VERSION 5.8 ;
BUSBITCHARS "[]" ;
DIVIDERCHAR "/" ;
UNITS
    DATABASE MICRONS 1000 ;
END UNITS

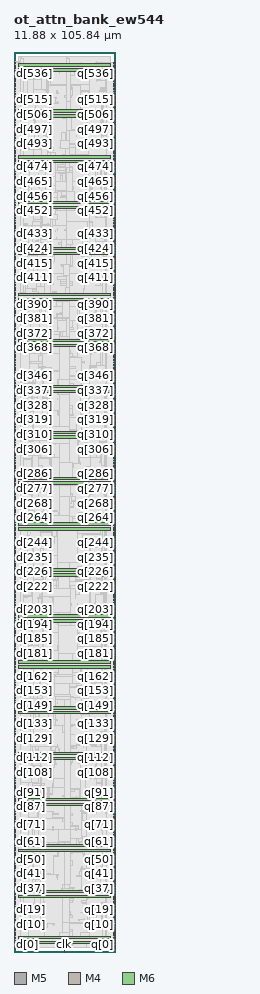
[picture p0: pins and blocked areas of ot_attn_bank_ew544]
MACRO ot_attn_bank_ew544
  FOREIGN ot_attn_bank_ew544 0 0 ;
  CLASS BLOCK ;
  SIZE 11.88 BY 105.84 ;
  PIN clk
    DIRECTION INPUT ;
    USE SIGNAL ;
    PORT
      LAYER M5 ;
        RECT  5.904 0 5.928 0.192 ;
    END
  END clk
  PIN d[0]
    DIRECTION INPUT ;
    USE SIGNAL ;
    PORT
      LAYER M4 ;
        RECT  0 0.384 0.192 0.408 ;
    END
  END d[0]
  PIN d[100]
    DIRECTION INPUT ;
    USE SIGNAL ;
    PORT
      LAYER M4 ;
        RECT  0 19.584 0.192 19.608 ;
    END
  END d[100]
  PIN d[101]
    DIRECTION INPUT ;
    USE SIGNAL ;
    PORT
      LAYER M4 ;
        RECT  0 19.776 0.192 19.8 ;
    END
  END d[101]
  PIN d[102]
    DIRECTION INPUT ;
    USE SIGNAL ;
    PORT
      LAYER M4 ;
        RECT  0 19.968 0.192 19.992 ;
    END
  END d[102]
  PIN d[103]
    DIRECTION INPUT ;
    USE SIGNAL ;
    PORT
      LAYER M4 ;
        RECT  0 20.16 0.192 20.184 ;
    END
  END d[103]
  PIN d[104]
    DIRECTION INPUT ;
    USE SIGNAL ;
    PORT
      LAYER M4 ;
        RECT  0 20.352 0.192 20.376 ;
    END
  END d[104]
  PIN d[105]
    DIRECTION INPUT ;
    USE SIGNAL ;
    PORT
      LAYER M4 ;
        RECT  0 20.544 0.192 20.568 ;
    END
  END d[105]
  PIN d[106]
    DIRECTION INPUT ;
    USE SIGNAL ;
    PORT
      LAYER M4 ;
        RECT  0 20.736 0.192 20.76 ;
    END
  END d[106]
  PIN d[107]
    DIRECTION INPUT ;
    USE SIGNAL ;
    PORT
      LAYER M4 ;
        RECT  0 20.928 0.192 20.952 ;
    END
  END d[107]
  PIN d[108]
    DIRECTION INPUT ;
    USE SIGNAL ;
    PORT
      LAYER M4 ;
        RECT  0 21.12 0.192 21.144 ;
    END
  END d[108]
  PIN d[109]
    DIRECTION INPUT ;
    USE SIGNAL ;
    PORT
      LAYER M4 ;
        RECT  0 21.312 0.192 21.336 ;
    END
  END d[109]
  PIN d[10]
    DIRECTION INPUT ;
    USE SIGNAL ;
    PORT
      LAYER M4 ;
        RECT  0 2.304 0.192 2.328 ;
    END
  END d[10]
  PIN d[110]
    DIRECTION INPUT ;
    USE SIGNAL ;
    PORT
      LAYER M4 ;
        RECT  0 21.504 0.192 21.528 ;
    END
  END d[110]
  PIN d[111]
    DIRECTION INPUT ;
    USE SIGNAL ;
    PORT
      LAYER M4 ;
        RECT  0 21.696 0.192 21.72 ;
    END
  END d[111]
  PIN d[112]
    DIRECTION INPUT ;
    USE SIGNAL ;
    PORT
      LAYER M4 ;
        RECT  0 21.888 0.192 21.912 ;
    END
  END d[112]
  PIN d[113]
    DIRECTION INPUT ;
    USE SIGNAL ;
    PORT
      LAYER M4 ;
        RECT  0 22.08 0.192 22.104 ;
    END
  END d[113]
  PIN d[114]
    DIRECTION INPUT ;
    USE SIGNAL ;
    PORT
      LAYER M4 ;
        RECT  0 22.272 0.192 22.296 ;
    END
  END d[114]
  PIN d[115]
    DIRECTION INPUT ;
    USE SIGNAL ;
    PORT
      LAYER M4 ;
        RECT  0 22.464 0.192 22.488 ;
    END
  END d[115]
  PIN d[116]
    DIRECTION INPUT ;
    USE SIGNAL ;
    PORT
      LAYER M4 ;
        RECT  0 22.656 0.192 22.68 ;
    END
  END d[116]
  PIN d[117]
    DIRECTION INPUT ;
    USE SIGNAL ;
    PORT
      LAYER M4 ;
        RECT  0 22.848 0.192 22.872 ;
    END
  END d[117]
  PIN d[118]
    DIRECTION INPUT ;
    USE SIGNAL ;
    PORT
      LAYER M4 ;
        RECT  0 23.04 0.192 23.064 ;
    END
  END d[118]
  PIN d[119]
    DIRECTION INPUT ;
    USE SIGNAL ;
    PORT
      LAYER M4 ;
        RECT  0 23.232 0.192 23.256 ;
    END
  END d[119]
  PIN d[11]
    DIRECTION INPUT ;
    USE SIGNAL ;
    PORT
      LAYER M4 ;
        RECT  0 2.496 0.192 2.52 ;
    END
  END d[11]
  PIN d[120]
    DIRECTION INPUT ;
    USE SIGNAL ;
    PORT
      LAYER M4 ;
        RECT  0 23.424 0.192 23.448 ;
    END
  END d[120]
  PIN d[121]
    DIRECTION INPUT ;
    USE SIGNAL ;
    PORT
      LAYER M4 ;
        RECT  0 23.616 0.192 23.64 ;
    END
  END d[121]
  PIN d[122]
    DIRECTION INPUT ;
    USE SIGNAL ;
    PORT
      LAYER M4 ;
        RECT  0 23.808 0.192 23.832 ;
    END
  END d[122]
  PIN d[123]
    DIRECTION INPUT ;
    USE SIGNAL ;
    PORT
      LAYER M4 ;
        RECT  0 24 0.192 24.024 ;
    END
  END d[123]
  PIN d[124]
    DIRECTION INPUT ;
    USE SIGNAL ;
    PORT
      LAYER M4 ;
        RECT  0 24.192 0.192 24.216 ;
    END
  END d[124]
  PIN d[125]
    DIRECTION INPUT ;
    USE SIGNAL ;
    PORT
      LAYER M4 ;
        RECT  0 24.384 0.192 24.408 ;
    END
  END d[125]
  PIN d[126]
    DIRECTION INPUT ;
    USE SIGNAL ;
    PORT
      LAYER M4 ;
        RECT  0 24.576 0.192 24.6 ;
    END
  END d[126]
  PIN d[127]
    DIRECTION INPUT ;
    USE SIGNAL ;
    PORT
      LAYER M4 ;
        RECT  0 24.768 0.192 24.792 ;
    END
  END d[127]
  PIN d[128]
    DIRECTION INPUT ;
    USE SIGNAL ;
    PORT
      LAYER M4 ;
        RECT  0 24.96 0.192 24.984 ;
    END
  END d[128]
  PIN d[129]
    DIRECTION INPUT ;
    USE SIGNAL ;
    PORT
      LAYER M4 ;
        RECT  0 25.152 0.192 25.176 ;
    END
  END d[129]
  PIN d[12]
    DIRECTION INPUT ;
    USE SIGNAL ;
    PORT
      LAYER M4 ;
        RECT  0 2.688 0.192 2.712 ;
    END
  END d[12]
  PIN d[130]
    DIRECTION INPUT ;
    USE SIGNAL ;
    PORT
      LAYER M4 ;
        RECT  0 25.344 0.192 25.368 ;
    END
  END d[130]
  PIN d[131]
    DIRECTION INPUT ;
    USE SIGNAL ;
    PORT
      LAYER M4 ;
        RECT  0 25.536 0.192 25.56 ;
    END
  END d[131]
  PIN d[132]
    DIRECTION INPUT ;
    USE SIGNAL ;
    PORT
      LAYER M4 ;
        RECT  0 25.728 0.192 25.752 ;
    END
  END d[132]
  PIN d[133]
    DIRECTION INPUT ;
    USE SIGNAL ;
    PORT
      LAYER M4 ;
        RECT  0 25.92 0.192 25.944 ;
    END
  END d[133]
  PIN d[134]
    DIRECTION INPUT ;
    USE SIGNAL ;
    PORT
      LAYER M4 ;
        RECT  0 26.112 0.192 26.136 ;
    END
  END d[134]
  PIN d[135]
    DIRECTION INPUT ;
    USE SIGNAL ;
    PORT
      LAYER M4 ;
        RECT  0 26.304 0.192 26.328 ;
    END
  END d[135]
  PIN d[136]
    DIRECTION INPUT ;
    USE SIGNAL ;
    PORT
      LAYER M4 ;
        RECT  0 26.496 0.192 26.52 ;
    END
  END d[136]
  PIN d[137]
    DIRECTION INPUT ;
    USE SIGNAL ;
    PORT
      LAYER M4 ;
        RECT  0 26.688 0.192 26.712 ;
    END
  END d[137]
  PIN d[138]
    DIRECTION INPUT ;
    USE SIGNAL ;
    PORT
      LAYER M4 ;
        RECT  0 26.88 0.192 26.904 ;
    END
  END d[138]
  PIN d[139]
    DIRECTION INPUT ;
    USE SIGNAL ;
    PORT
      LAYER M4 ;
        RECT  0 27.072 0.192 27.096 ;
    END
  END d[139]
  PIN d[13]
    DIRECTION INPUT ;
    USE SIGNAL ;
    PORT
      LAYER M4 ;
        RECT  0 2.88 0.192 2.904 ;
    END
  END d[13]
  PIN d[140]
    DIRECTION INPUT ;
    USE SIGNAL ;
    PORT
      LAYER M4 ;
        RECT  0 27.264 0.192 27.288 ;
    END
  END d[140]
  PIN d[141]
    DIRECTION INPUT ;
    USE SIGNAL ;
    PORT
      LAYER M4 ;
        RECT  0 27.456 0.192 27.48 ;
    END
  END d[141]
  PIN d[142]
    DIRECTION INPUT ;
    USE SIGNAL ;
    PORT
      LAYER M4 ;
        RECT  0 27.648 0.192 27.672 ;
    END
  END d[142]
  PIN d[143]
    DIRECTION INPUT ;
    USE SIGNAL ;
    PORT
      LAYER M4 ;
        RECT  0 27.84 0.192 27.864 ;
    END
  END d[143]
  PIN d[144]
    DIRECTION INPUT ;
    USE SIGNAL ;
    PORT
      LAYER M4 ;
        RECT  0 28.032 0.192 28.056 ;
    END
  END d[144]
  PIN d[145]
    DIRECTION INPUT ;
    USE SIGNAL ;
    PORT
      LAYER M4 ;
        RECT  0 28.224 0.192 28.248 ;
    END
  END d[145]
  PIN d[146]
    DIRECTION INPUT ;
    USE SIGNAL ;
    PORT
      LAYER M4 ;
        RECT  0 28.416 0.192 28.44 ;
    END
  END d[146]
  PIN d[147]
    DIRECTION INPUT ;
    USE SIGNAL ;
    PORT
      LAYER M4 ;
        RECT  0 28.608 0.192 28.632 ;
    END
  END d[147]
  PIN d[148]
    DIRECTION INPUT ;
    USE SIGNAL ;
    PORT
      LAYER M4 ;
        RECT  0 28.8 0.192 28.824 ;
    END
  END d[148]
  PIN d[149]
    DIRECTION INPUT ;
    USE SIGNAL ;
    PORT
      LAYER M4 ;
        RECT  0 28.992 0.192 29.016 ;
    END
  END d[149]
  PIN d[14]
    DIRECTION INPUT ;
    USE SIGNAL ;
    PORT
      LAYER M4 ;
        RECT  0 3.072 0.192 3.096 ;
    END
  END d[14]
  PIN d[150]
    DIRECTION INPUT ;
    USE SIGNAL ;
    PORT
      LAYER M4 ;
        RECT  0 29.184 0.192 29.208 ;
    END
  END d[150]
  PIN d[151]
    DIRECTION INPUT ;
    USE SIGNAL ;
    PORT
      LAYER M4 ;
        RECT  0 29.376 0.192 29.4 ;
    END
  END d[151]
  PIN d[152]
    DIRECTION INPUT ;
    USE SIGNAL ;
    PORT
      LAYER M4 ;
        RECT  0 29.568 0.192 29.592 ;
    END
  END d[152]
  PIN d[153]
    DIRECTION INPUT ;
    USE SIGNAL ;
    PORT
      LAYER M4 ;
        RECT  0 29.76 0.192 29.784 ;
    END
  END d[153]
  PIN d[154]
    DIRECTION INPUT ;
    USE SIGNAL ;
    PORT
      LAYER M4 ;
        RECT  0 29.952 0.192 29.976 ;
    END
  END d[154]
  PIN d[155]
    DIRECTION INPUT ;
    USE SIGNAL ;
    PORT
      LAYER M4 ;
        RECT  0 30.144 0.192 30.168 ;
    END
  END d[155]
  PIN d[156]
    DIRECTION INPUT ;
    USE SIGNAL ;
    PORT
      LAYER M4 ;
        RECT  0 30.336 0.192 30.36 ;
    END
  END d[156]
  PIN d[157]
    DIRECTION INPUT ;
    USE SIGNAL ;
    PORT
      LAYER M4 ;
        RECT  0 30.528 0.192 30.552 ;
    END
  END d[157]
  PIN d[158]
    DIRECTION INPUT ;
    USE SIGNAL ;
    PORT
      LAYER M4 ;
        RECT  0 30.72 0.192 30.744 ;
    END
  END d[158]
  PIN d[159]
    DIRECTION INPUT ;
    USE SIGNAL ;
    PORT
      LAYER M4 ;
        RECT  0 30.912 0.192 30.936 ;
    END
  END d[159]
  PIN d[15]
    DIRECTION INPUT ;
    USE SIGNAL ;
    PORT
      LAYER M4 ;
        RECT  0 3.264 0.192 3.288 ;
    END
  END d[15]
  PIN d[160]
    DIRECTION INPUT ;
    USE SIGNAL ;
    PORT
      LAYER M4 ;
        RECT  0 31.104 0.192 31.128 ;
    END
  END d[160]
  PIN d[161]
    DIRECTION INPUT ;
    USE SIGNAL ;
    PORT
      LAYER M4 ;
        RECT  0 31.296 0.192 31.32 ;
    END
  END d[161]
  PIN d[162]
    DIRECTION INPUT ;
    USE SIGNAL ;
    PORT
      LAYER M4 ;
        RECT  0 31.488 0.192 31.512 ;
    END
  END d[162]
  PIN d[163]
    DIRECTION INPUT ;
    USE SIGNAL ;
    PORT
      LAYER M4 ;
        RECT  0 31.68 0.192 31.704 ;
    END
  END d[163]
  PIN d[164]
    DIRECTION INPUT ;
    USE SIGNAL ;
    PORT
      LAYER M4 ;
        RECT  0 31.872 0.192 31.896 ;
    END
  END d[164]
  PIN d[165]
    DIRECTION INPUT ;
    USE SIGNAL ;
    PORT
      LAYER M4 ;
        RECT  0 32.064 0.192 32.088 ;
    END
  END d[165]
  PIN d[166]
    DIRECTION INPUT ;
    USE SIGNAL ;
    PORT
      LAYER M4 ;
        RECT  0 32.256 0.192 32.28 ;
    END
  END d[166]
  PIN d[167]
    DIRECTION INPUT ;
    USE SIGNAL ;
    PORT
      LAYER M4 ;
        RECT  0 32.448 0.192 32.472 ;
    END
  END d[167]
  PIN d[168]
    DIRECTION INPUT ;
    USE SIGNAL ;
    PORT
      LAYER M4 ;
        RECT  0 32.64 0.192 32.664 ;
    END
  END d[168]
  PIN d[169]
    DIRECTION INPUT ;
    USE SIGNAL ;
    PORT
      LAYER M4 ;
        RECT  0 32.832 0.192 32.856 ;
    END
  END d[169]
  PIN d[16]
    DIRECTION INPUT ;
    USE SIGNAL ;
    PORT
      LAYER M4 ;
        RECT  0 3.456 0.192 3.48 ;
    END
  END d[16]
  PIN d[170]
    DIRECTION INPUT ;
    USE SIGNAL ;
    PORT
      LAYER M4 ;
        RECT  0 33.024 0.192 33.048 ;
    END
  END d[170]
  PIN d[171]
    DIRECTION INPUT ;
    USE SIGNAL ;
    PORT
      LAYER M4 ;
        RECT  0 33.216 0.192 33.24 ;
    END
  END d[171]
  PIN d[172]
    DIRECTION INPUT ;
    USE SIGNAL ;
    PORT
      LAYER M4 ;
        RECT  0 33.408 0.192 33.432 ;
    END
  END d[172]
  PIN d[173]
    DIRECTION INPUT ;
    USE SIGNAL ;
    PORT
      LAYER M4 ;
        RECT  0 33.6 0.192 33.624 ;
    END
  END d[173]
  PIN d[174]
    DIRECTION INPUT ;
    USE SIGNAL ;
    PORT
      LAYER M4 ;
        RECT  0 33.792 0.192 33.816 ;
    END
  END d[174]
  PIN d[175]
    DIRECTION INPUT ;
    USE SIGNAL ;
    PORT
      LAYER M4 ;
        RECT  0 33.984 0.192 34.008 ;
    END
  END d[175]
  PIN d[176]
    DIRECTION INPUT ;
    USE SIGNAL ;
    PORT
      LAYER M4 ;
        RECT  0 34.176 0.192 34.2 ;
    END
  END d[176]
  PIN d[177]
    DIRECTION INPUT ;
    USE SIGNAL ;
    PORT
      LAYER M4 ;
        RECT  0 34.368 0.192 34.392 ;
    END
  END d[177]
  PIN d[178]
    DIRECTION INPUT ;
    USE SIGNAL ;
    PORT
      LAYER M4 ;
        RECT  0 34.56 0.192 34.584 ;
    END
  END d[178]
  PIN d[179]
    DIRECTION INPUT ;
    USE SIGNAL ;
    PORT
      LAYER M4 ;
        RECT  0 34.752 0.192 34.776 ;
    END
  END d[179]
  PIN d[17]
    DIRECTION INPUT ;
    USE SIGNAL ;
    PORT
      LAYER M4 ;
        RECT  0 3.648 0.192 3.672 ;
    END
  END d[17]
  PIN d[180]
    DIRECTION INPUT ;
    USE SIGNAL ;
    PORT
      LAYER M4 ;
        RECT  0 34.944 0.192 34.968 ;
    END
  END d[180]
  PIN d[181]
    DIRECTION INPUT ;
    USE SIGNAL ;
    PORT
      LAYER M4 ;
        RECT  0 35.136 0.192 35.16 ;
    END
  END d[181]
  PIN d[182]
    DIRECTION INPUT ;
    USE SIGNAL ;
    PORT
      LAYER M4 ;
        RECT  0 35.328 0.192 35.352 ;
    END
  END d[182]
  PIN d[183]
    DIRECTION INPUT ;
    USE SIGNAL ;
    PORT
      LAYER M4 ;
        RECT  0 35.52 0.192 35.544 ;
    END
  END d[183]
  PIN d[184]
    DIRECTION INPUT ;
    USE SIGNAL ;
    PORT
      LAYER M4 ;
        RECT  0 35.712 0.192 35.736 ;
    END
  END d[184]
  PIN d[185]
    DIRECTION INPUT ;
    USE SIGNAL ;
    PORT
      LAYER M4 ;
        RECT  0 35.904 0.192 35.928 ;
    END
  END d[185]
  PIN d[186]
    DIRECTION INPUT ;
    USE SIGNAL ;
    PORT
      LAYER M4 ;
        RECT  0 36.096 0.192 36.12 ;
    END
  END d[186]
  PIN d[187]
    DIRECTION INPUT ;
    USE SIGNAL ;
    PORT
      LAYER M4 ;
        RECT  0 36.288 0.192 36.312 ;
    END
  END d[187]
  PIN d[188]
    DIRECTION INPUT ;
    USE SIGNAL ;
    PORT
      LAYER M4 ;
        RECT  0 36.48 0.192 36.504 ;
    END
  END d[188]
  PIN d[189]
    DIRECTION INPUT ;
    USE SIGNAL ;
    PORT
      LAYER M4 ;
        RECT  0 36.672 0.192 36.696 ;
    END
  END d[189]
  PIN d[18]
    DIRECTION INPUT ;
    USE SIGNAL ;
    PORT
      LAYER M4 ;
        RECT  0 3.84 0.192 3.864 ;
    END
  END d[18]
  PIN d[190]
    DIRECTION INPUT ;
    USE SIGNAL ;
    PORT
      LAYER M4 ;
        RECT  0 36.864 0.192 36.888 ;
    END
  END d[190]
  PIN d[191]
    DIRECTION INPUT ;
    USE SIGNAL ;
    PORT
      LAYER M4 ;
        RECT  0 37.056 0.192 37.08 ;
    END
  END d[191]
  PIN d[192]
    DIRECTION INPUT ;
    USE SIGNAL ;
    PORT
      LAYER M4 ;
        RECT  0 37.248 0.192 37.272 ;
    END
  END d[192]
  PIN d[193]
    DIRECTION INPUT ;
    USE SIGNAL ;
    PORT
      LAYER M4 ;
        RECT  0 37.44 0.192 37.464 ;
    END
  END d[193]
  PIN d[194]
    DIRECTION INPUT ;
    USE SIGNAL ;
    PORT
      LAYER M4 ;
        RECT  0 37.632 0.192 37.656 ;
    END
  END d[194]
  PIN d[195]
    DIRECTION INPUT ;
    USE SIGNAL ;
    PORT
      LAYER M4 ;
        RECT  0 37.824 0.192 37.848 ;
    END
  END d[195]
  PIN d[196]
    DIRECTION INPUT ;
    USE SIGNAL ;
    PORT
      LAYER M4 ;
        RECT  0 38.016 0.192 38.04 ;
    END
  END d[196]
  PIN d[197]
    DIRECTION INPUT ;
    USE SIGNAL ;
    PORT
      LAYER M4 ;
        RECT  0 38.208 0.192 38.232 ;
    END
  END d[197]
  PIN d[198]
    DIRECTION INPUT ;
    USE SIGNAL ;
    PORT
      LAYER M4 ;
        RECT  0 38.4 0.192 38.424 ;
    END
  END d[198]
  PIN d[199]
    DIRECTION INPUT ;
    USE SIGNAL ;
    PORT
      LAYER M4 ;
        RECT  0 38.592 0.192 38.616 ;
    END
  END d[199]
  PIN d[19]
    DIRECTION INPUT ;
    USE SIGNAL ;
    PORT
      LAYER M4 ;
        RECT  0 4.032 0.192 4.056 ;
    END
  END d[19]
  PIN d[1]
    DIRECTION INPUT ;
    USE SIGNAL ;
    PORT
      LAYER M4 ;
        RECT  0 0.576 0.192 0.6 ;
    END
  END d[1]
  PIN d[200]
    DIRECTION INPUT ;
    USE SIGNAL ;
    PORT
      LAYER M4 ;
        RECT  0 38.784 0.192 38.808 ;
    END
  END d[200]
  PIN d[201]
    DIRECTION INPUT ;
    USE SIGNAL ;
    PORT
      LAYER M4 ;
        RECT  0 38.976 0.192 39 ;
    END
  END d[201]
  PIN d[202]
    DIRECTION INPUT ;
    USE SIGNAL ;
    PORT
      LAYER M4 ;
        RECT  0 39.168 0.192 39.192 ;
    END
  END d[202]
  PIN d[203]
    DIRECTION INPUT ;
    USE SIGNAL ;
    PORT
      LAYER M4 ;
        RECT  0 39.36 0.192 39.384 ;
    END
  END d[203]
  PIN d[204]
    DIRECTION INPUT ;
    USE SIGNAL ;
    PORT
      LAYER M4 ;
        RECT  0 39.552 0.192 39.576 ;
    END
  END d[204]
  PIN d[205]
    DIRECTION INPUT ;
    USE SIGNAL ;
    PORT
      LAYER M4 ;
        RECT  0 39.744 0.192 39.768 ;
    END
  END d[205]
  PIN d[206]
    DIRECTION INPUT ;
    USE SIGNAL ;
    PORT
      LAYER M4 ;
        RECT  0 39.936 0.192 39.96 ;
    END
  END d[206]
  PIN d[207]
    DIRECTION INPUT ;
    USE SIGNAL ;
    PORT
      LAYER M4 ;
        RECT  0 40.128 0.192 40.152 ;
    END
  END d[207]
  PIN d[208]
    DIRECTION INPUT ;
    USE SIGNAL ;
    PORT
      LAYER M4 ;
        RECT  0 40.32 0.192 40.344 ;
    END
  END d[208]
  PIN d[209]
    DIRECTION INPUT ;
    USE SIGNAL ;
    PORT
      LAYER M4 ;
        RECT  0 40.512 0.192 40.536 ;
    END
  END d[209]
  PIN d[20]
    DIRECTION INPUT ;
    USE SIGNAL ;
    PORT
      LAYER M4 ;
        RECT  0 4.224 0.192 4.248 ;
    END
  END d[20]
  PIN d[210]
    DIRECTION INPUT ;
    USE SIGNAL ;
    PORT
      LAYER M4 ;
        RECT  0 40.704 0.192 40.728 ;
    END
  END d[210]
  PIN d[211]
    DIRECTION INPUT ;
    USE SIGNAL ;
    PORT
      LAYER M4 ;
        RECT  0 40.896 0.192 40.92 ;
    END
  END d[211]
  PIN d[212]
    DIRECTION INPUT ;
    USE SIGNAL ;
    PORT
      LAYER M4 ;
        RECT  0 41.088 0.192 41.112 ;
    END
  END d[212]
  PIN d[213]
    DIRECTION INPUT ;
    USE SIGNAL ;
    PORT
      LAYER M4 ;
        RECT  0 41.28 0.192 41.304 ;
    END
  END d[213]
  PIN d[214]
    DIRECTION INPUT ;
    USE SIGNAL ;
    PORT
      LAYER M4 ;
        RECT  0 41.472 0.192 41.496 ;
    END
  END d[214]
  PIN d[215]
    DIRECTION INPUT ;
    USE SIGNAL ;
    PORT
      LAYER M4 ;
        RECT  0 41.664 0.192 41.688 ;
    END
  END d[215]
  PIN d[216]
    DIRECTION INPUT ;
    USE SIGNAL ;
    PORT
      LAYER M4 ;
        RECT  0 41.856 0.192 41.88 ;
    END
  END d[216]
  PIN d[217]
    DIRECTION INPUT ;
    USE SIGNAL ;
    PORT
      LAYER M4 ;
        RECT  0 42.048 0.192 42.072 ;
    END
  END d[217]
  PIN d[218]
    DIRECTION INPUT ;
    USE SIGNAL ;
    PORT
      LAYER M4 ;
        RECT  0 42.24 0.192 42.264 ;
    END
  END d[218]
  PIN d[219]
    DIRECTION INPUT ;
    USE SIGNAL ;
    PORT
      LAYER M4 ;
        RECT  0 42.432 0.192 42.456 ;
    END
  END d[219]
  PIN d[21]
    DIRECTION INPUT ;
    USE SIGNAL ;
    PORT
      LAYER M4 ;
        RECT  0 4.416 0.192 4.44 ;
    END
  END d[21]
  PIN d[220]
    DIRECTION INPUT ;
    USE SIGNAL ;
    PORT
      LAYER M4 ;
        RECT  0 42.624 0.192 42.648 ;
    END
  END d[220]
  PIN d[221]
    DIRECTION INPUT ;
    USE SIGNAL ;
    PORT
      LAYER M4 ;
        RECT  0 42.816 0.192 42.84 ;
    END
  END d[221]
  PIN d[222]
    DIRECTION INPUT ;
    USE SIGNAL ;
    PORT
      LAYER M4 ;
        RECT  0 43.008 0.192 43.032 ;
    END
  END d[222]
  PIN d[223]
    DIRECTION INPUT ;
    USE SIGNAL ;
    PORT
      LAYER M4 ;
        RECT  0 43.2 0.192 43.224 ;
    END
  END d[223]
  PIN d[224]
    DIRECTION INPUT ;
    USE SIGNAL ;
    PORT
      LAYER M4 ;
        RECT  0 43.392 0.192 43.416 ;
    END
  END d[224]
  PIN d[225]
    DIRECTION INPUT ;
    USE SIGNAL ;
    PORT
      LAYER M4 ;
        RECT  0 43.584 0.192 43.608 ;
    END
  END d[225]
  PIN d[226]
    DIRECTION INPUT ;
    USE SIGNAL ;
    PORT
      LAYER M4 ;
        RECT  0 43.776 0.192 43.8 ;
    END
  END d[226]
  PIN d[227]
    DIRECTION INPUT ;
    USE SIGNAL ;
    PORT
      LAYER M4 ;
        RECT  0 43.968 0.192 43.992 ;
    END
  END d[227]
  PIN d[228]
    DIRECTION INPUT ;
    USE SIGNAL ;
    PORT
      LAYER M4 ;
        RECT  0 44.16 0.192 44.184 ;
    END
  END d[228]
  PIN d[229]
    DIRECTION INPUT ;
    USE SIGNAL ;
    PORT
      LAYER M4 ;
        RECT  0 44.352 0.192 44.376 ;
    END
  END d[229]
  PIN d[22]
    DIRECTION INPUT ;
    USE SIGNAL ;
    PORT
      LAYER M4 ;
        RECT  0 4.608 0.192 4.632 ;
    END
  END d[22]
  PIN d[230]
    DIRECTION INPUT ;
    USE SIGNAL ;
    PORT
      LAYER M4 ;
        RECT  0 44.544 0.192 44.568 ;
    END
  END d[230]
  PIN d[231]
    DIRECTION INPUT ;
    USE SIGNAL ;
    PORT
      LAYER M4 ;
        RECT  0 44.736 0.192 44.76 ;
    END
  END d[231]
  PIN d[232]
    DIRECTION INPUT ;
    USE SIGNAL ;
    PORT
      LAYER M4 ;
        RECT  0 44.928 0.192 44.952 ;
    END
  END d[232]
  PIN d[233]
    DIRECTION INPUT ;
    USE SIGNAL ;
    PORT
      LAYER M4 ;
        RECT  0 45.12 0.192 45.144 ;
    END
  END d[233]
  PIN d[234]
    DIRECTION INPUT ;
    USE SIGNAL ;
    PORT
      LAYER M4 ;
        RECT  0 45.312 0.192 45.336 ;
    END
  END d[234]
  PIN d[235]
    DIRECTION INPUT ;
    USE SIGNAL ;
    PORT
      LAYER M4 ;
        RECT  0 45.504 0.192 45.528 ;
    END
  END d[235]
  PIN d[236]
    DIRECTION INPUT ;
    USE SIGNAL ;
    PORT
      LAYER M4 ;
        RECT  0 45.696 0.192 45.72 ;
    END
  END d[236]
  PIN d[237]
    DIRECTION INPUT ;
    USE SIGNAL ;
    PORT
      LAYER M4 ;
        RECT  0 45.888 0.192 45.912 ;
    END
  END d[237]
  PIN d[238]
    DIRECTION INPUT ;
    USE SIGNAL ;
    PORT
      LAYER M4 ;
        RECT  0 46.08 0.192 46.104 ;
    END
  END d[238]
  PIN d[239]
    DIRECTION INPUT ;
    USE SIGNAL ;
    PORT
      LAYER M4 ;
        RECT  0 46.272 0.192 46.296 ;
    END
  END d[239]
  PIN d[23]
    DIRECTION INPUT ;
    USE SIGNAL ;
    PORT
      LAYER M4 ;
        RECT  0 4.8 0.192 4.824 ;
    END
  END d[23]
  PIN d[240]
    DIRECTION INPUT ;
    USE SIGNAL ;
    PORT
      LAYER M4 ;
        RECT  0 46.464 0.192 46.488 ;
    END
  END d[240]
  PIN d[241]
    DIRECTION INPUT ;
    USE SIGNAL ;
    PORT
      LAYER M4 ;
        RECT  0 46.656 0.192 46.68 ;
    END
  END d[241]
  PIN d[242]
    DIRECTION INPUT ;
    USE SIGNAL ;
    PORT
      LAYER M4 ;
        RECT  0 46.848 0.192 46.872 ;
    END
  END d[242]
  PIN d[243]
    DIRECTION INPUT ;
    USE SIGNAL ;
    PORT
      LAYER M4 ;
        RECT  0 47.04 0.192 47.064 ;
    END
  END d[243]
  PIN d[244]
    DIRECTION INPUT ;
    USE SIGNAL ;
    PORT
      LAYER M4 ;
        RECT  0 47.232 0.192 47.256 ;
    END
  END d[244]
  PIN d[245]
    DIRECTION INPUT ;
    USE SIGNAL ;
    PORT
      LAYER M4 ;
        RECT  0 47.424 0.192 47.448 ;
    END
  END d[245]
  PIN d[246]
    DIRECTION INPUT ;
    USE SIGNAL ;
    PORT
      LAYER M4 ;
        RECT  0 47.616 0.192 47.64 ;
    END
  END d[246]
  PIN d[247]
    DIRECTION INPUT ;
    USE SIGNAL ;
    PORT
      LAYER M4 ;
        RECT  0 47.808 0.192 47.832 ;
    END
  END d[247]
  PIN d[248]
    DIRECTION INPUT ;
    USE SIGNAL ;
    PORT
      LAYER M4 ;
        RECT  0 48 0.192 48.024 ;
    END
  END d[248]
  PIN d[249]
    DIRECTION INPUT ;
    USE SIGNAL ;
    PORT
      LAYER M4 ;
        RECT  0 48.192 0.192 48.216 ;
    END
  END d[249]
  PIN d[24]
    DIRECTION INPUT ;
    USE SIGNAL ;
    PORT
      LAYER M4 ;
        RECT  0 4.992 0.192 5.016 ;
    END
  END d[24]
  PIN d[250]
    DIRECTION INPUT ;
    USE SIGNAL ;
    PORT
      LAYER M4 ;
        RECT  0 48.384 0.192 48.408 ;
    END
  END d[250]
  PIN d[251]
    DIRECTION INPUT ;
    USE SIGNAL ;
    PORT
      LAYER M4 ;
        RECT  0 48.576 0.192 48.6 ;
    END
  END d[251]
  PIN d[252]
    DIRECTION INPUT ;
    USE SIGNAL ;
    PORT
      LAYER M4 ;
        RECT  0 48.768 0.192 48.792 ;
    END
  END d[252]
  PIN d[253]
    DIRECTION INPUT ;
    USE SIGNAL ;
    PORT
      LAYER M4 ;
        RECT  0 48.96 0.192 48.984 ;
    END
  END d[253]
  PIN d[254]
    DIRECTION INPUT ;
    USE SIGNAL ;
    PORT
      LAYER M4 ;
        RECT  0 49.152 0.192 49.176 ;
    END
  END d[254]
  PIN d[255]
    DIRECTION INPUT ;
    USE SIGNAL ;
    PORT
      LAYER M4 ;
        RECT  0 49.344 0.192 49.368 ;
    END
  END d[255]
  PIN d[256]
    DIRECTION INPUT ;
    USE SIGNAL ;
    PORT
      LAYER M4 ;
        RECT  0 49.536 0.192 49.56 ;
    END
  END d[256]
  PIN d[257]
    DIRECTION INPUT ;
    USE SIGNAL ;
    PORT
      LAYER M4 ;
        RECT  0 49.728 0.192 49.752 ;
    END
  END d[257]
  PIN d[258]
    DIRECTION INPUT ;
    USE SIGNAL ;
    PORT
      LAYER M4 ;
        RECT  0 49.92 0.192 49.944 ;
    END
  END d[258]
  PIN d[259]
    DIRECTION INPUT ;
    USE SIGNAL ;
    PORT
      LAYER M4 ;
        RECT  0 50.112 0.192 50.136 ;
    END
  END d[259]
  PIN d[25]
    DIRECTION INPUT ;
    USE SIGNAL ;
    PORT
      LAYER M4 ;
        RECT  0 5.184 0.192 5.208 ;
    END
  END d[25]
  PIN d[260]
    DIRECTION INPUT ;
    USE SIGNAL ;
    PORT
      LAYER M4 ;
        RECT  0 50.304 0.192 50.328 ;
    END
  END d[260]
  PIN d[261]
    DIRECTION INPUT ;
    USE SIGNAL ;
    PORT
      LAYER M4 ;
        RECT  0 50.496 0.192 50.52 ;
    END
  END d[261]
  PIN d[262]
    DIRECTION INPUT ;
    USE SIGNAL ;
    PORT
      LAYER M4 ;
        RECT  0 50.688 0.192 50.712 ;
    END
  END d[262]
  PIN d[263]
    DIRECTION INPUT ;
    USE SIGNAL ;
    PORT
      LAYER M4 ;
        RECT  0 50.88 0.192 50.904 ;
    END
  END d[263]
  PIN d[264]
    DIRECTION INPUT ;
    USE SIGNAL ;
    PORT
      LAYER M4 ;
        RECT  0 51.072 0.192 51.096 ;
    END
  END d[264]
  PIN d[265]
    DIRECTION INPUT ;
    USE SIGNAL ;
    PORT
      LAYER M4 ;
        RECT  0 51.264 0.192 51.288 ;
    END
  END d[265]
  PIN d[266]
    DIRECTION INPUT ;
    USE SIGNAL ;
    PORT
      LAYER M4 ;
        RECT  0 51.456 0.192 51.48 ;
    END
  END d[266]
  PIN d[267]
    DIRECTION INPUT ;
    USE SIGNAL ;
    PORT
      LAYER M4 ;
        RECT  0 51.648 0.192 51.672 ;
    END
  END d[267]
  PIN d[268]
    DIRECTION INPUT ;
    USE SIGNAL ;
    PORT
      LAYER M4 ;
        RECT  0 51.84 0.192 51.864 ;
    END
  END d[268]
  PIN d[269]
    DIRECTION INPUT ;
    USE SIGNAL ;
    PORT
      LAYER M4 ;
        RECT  0 52.032 0.192 52.056 ;
    END
  END d[269]
  PIN d[26]
    DIRECTION INPUT ;
    USE SIGNAL ;
    PORT
      LAYER M4 ;
        RECT  0 5.376 0.192 5.4 ;
    END
  END d[26]
  PIN d[270]
    DIRECTION INPUT ;
    USE SIGNAL ;
    PORT
      LAYER M4 ;
        RECT  0 52.224 0.192 52.248 ;
    END
  END d[270]
  PIN d[271]
    DIRECTION INPUT ;
    USE SIGNAL ;
    PORT
      LAYER M4 ;
        RECT  0 52.416 0.192 52.44 ;
    END
  END d[271]
  PIN d[272]
    DIRECTION INPUT ;
    USE SIGNAL ;
    PORT
      LAYER M4 ;
        RECT  0 52.608 0.192 52.632 ;
    END
  END d[272]
  PIN d[273]
    DIRECTION INPUT ;
    USE SIGNAL ;
    PORT
      LAYER M4 ;
        RECT  0 52.8 0.192 52.824 ;
    END
  END d[273]
  PIN d[274]
    DIRECTION INPUT ;
    USE SIGNAL ;
    PORT
      LAYER M4 ;
        RECT  0 52.992 0.192 53.016 ;
    END
  END d[274]
  PIN d[275]
    DIRECTION INPUT ;
    USE SIGNAL ;
    PORT
      LAYER M4 ;
        RECT  0 53.184 0.192 53.208 ;
    END
  END d[275]
  PIN d[276]
    DIRECTION INPUT ;
    USE SIGNAL ;
    PORT
      LAYER M4 ;
        RECT  0 53.376 0.192 53.4 ;
    END
  END d[276]
  PIN d[277]
    DIRECTION INPUT ;
    USE SIGNAL ;
    PORT
      LAYER M4 ;
        RECT  0 53.568 0.192 53.592 ;
    END
  END d[277]
  PIN d[278]
    DIRECTION INPUT ;
    USE SIGNAL ;
    PORT
      LAYER M4 ;
        RECT  0 53.76 0.192 53.784 ;
    END
  END d[278]
  PIN d[279]
    DIRECTION INPUT ;
    USE SIGNAL ;
    PORT
      LAYER M4 ;
        RECT  0 53.952 0.192 53.976 ;
    END
  END d[279]
  PIN d[27]
    DIRECTION INPUT ;
    USE SIGNAL ;
    PORT
      LAYER M4 ;
        RECT  0 5.568 0.192 5.592 ;
    END
  END d[27]
  PIN d[280]
    DIRECTION INPUT ;
    USE SIGNAL ;
    PORT
      LAYER M4 ;
        RECT  0 54.144 0.192 54.168 ;
    END
  END d[280]
  PIN d[281]
    DIRECTION INPUT ;
    USE SIGNAL ;
    PORT
      LAYER M4 ;
        RECT  0 54.336 0.192 54.36 ;
    END
  END d[281]
  PIN d[282]
    DIRECTION INPUT ;
    USE SIGNAL ;
    PORT
      LAYER M4 ;
        RECT  0 54.528 0.192 54.552 ;
    END
  END d[282]
  PIN d[283]
    DIRECTION INPUT ;
    USE SIGNAL ;
    PORT
      LAYER M4 ;
        RECT  0 54.72 0.192 54.744 ;
    END
  END d[283]
  PIN d[284]
    DIRECTION INPUT ;
    USE SIGNAL ;
    PORT
      LAYER M4 ;
        RECT  0 54.912 0.192 54.936 ;
    END
  END d[284]
  PIN d[285]
    DIRECTION INPUT ;
    USE SIGNAL ;
    PORT
      LAYER M4 ;
        RECT  0 55.104 0.192 55.128 ;
    END
  END d[285]
  PIN d[286]
    DIRECTION INPUT ;
    USE SIGNAL ;
    PORT
      LAYER M4 ;
        RECT  0 55.296 0.192 55.32 ;
    END
  END d[286]
  PIN d[287]
    DIRECTION INPUT ;
    USE SIGNAL ;
    PORT
      LAYER M4 ;
        RECT  0 55.488 0.192 55.512 ;
    END
  END d[287]
  PIN d[288]
    DIRECTION INPUT ;
    USE SIGNAL ;
    PORT
      LAYER M4 ;
        RECT  0 55.68 0.192 55.704 ;
    END
  END d[288]
  PIN d[289]
    DIRECTION INPUT ;
    USE SIGNAL ;
    PORT
      LAYER M4 ;
        RECT  0 55.872 0.192 55.896 ;
    END
  END d[289]
  PIN d[28]
    DIRECTION INPUT ;
    USE SIGNAL ;
    PORT
      LAYER M4 ;
        RECT  0 5.76 0.192 5.784 ;
    END
  END d[28]
  PIN d[290]
    DIRECTION INPUT ;
    USE SIGNAL ;
    PORT
      LAYER M4 ;
        RECT  0 56.064 0.192 56.088 ;
    END
  END d[290]
  PIN d[291]
    DIRECTION INPUT ;
    USE SIGNAL ;
    PORT
      LAYER M4 ;
        RECT  0 56.256 0.192 56.28 ;
    END
  END d[291]
  PIN d[292]
    DIRECTION INPUT ;
    USE SIGNAL ;
    PORT
      LAYER M4 ;
        RECT  0 56.448 0.192 56.472 ;
    END
  END d[292]
  PIN d[293]
    DIRECTION INPUT ;
    USE SIGNAL ;
    PORT
      LAYER M4 ;
        RECT  0 56.64 0.192 56.664 ;
    END
  END d[293]
  PIN d[294]
    DIRECTION INPUT ;
    USE SIGNAL ;
    PORT
      LAYER M4 ;
        RECT  0 56.832 0.192 56.856 ;
    END
  END d[294]
  PIN d[295]
    DIRECTION INPUT ;
    USE SIGNAL ;
    PORT
      LAYER M4 ;
        RECT  0 57.024 0.192 57.048 ;
    END
  END d[295]
  PIN d[296]
    DIRECTION INPUT ;
    USE SIGNAL ;
    PORT
      LAYER M4 ;
        RECT  0 57.216 0.192 57.24 ;
    END
  END d[296]
  PIN d[297]
    DIRECTION INPUT ;
    USE SIGNAL ;
    PORT
      LAYER M4 ;
        RECT  0 57.408 0.192 57.432 ;
    END
  END d[297]
  PIN d[298]
    DIRECTION INPUT ;
    USE SIGNAL ;
    PORT
      LAYER M4 ;
        RECT  0 57.6 0.192 57.624 ;
    END
  END d[298]
  PIN d[299]
    DIRECTION INPUT ;
    USE SIGNAL ;
    PORT
      LAYER M4 ;
        RECT  0 57.792 0.192 57.816 ;
    END
  END d[299]
  PIN d[29]
    DIRECTION INPUT ;
    USE SIGNAL ;
    PORT
      LAYER M4 ;
        RECT  0 5.952 0.192 5.976 ;
    END
  END d[29]
  PIN d[2]
    DIRECTION INPUT ;
    USE SIGNAL ;
    PORT
      LAYER M4 ;
        RECT  0 0.768 0.192 0.792 ;
    END
  END d[2]
  PIN d[300]
    DIRECTION INPUT ;
    USE SIGNAL ;
    PORT
      LAYER M4 ;
        RECT  0 57.984 0.192 58.008 ;
    END
  END d[300]
  PIN d[301]
    DIRECTION INPUT ;
    USE SIGNAL ;
    PORT
      LAYER M4 ;
        RECT  0 58.176 0.192 58.2 ;
    END
  END d[301]
  PIN d[302]
    DIRECTION INPUT ;
    USE SIGNAL ;
    PORT
      LAYER M4 ;
        RECT  0 58.368 0.192 58.392 ;
    END
  END d[302]
  PIN d[303]
    DIRECTION INPUT ;
    USE SIGNAL ;
    PORT
      LAYER M4 ;
        RECT  0 58.56 0.192 58.584 ;
    END
  END d[303]
  PIN d[304]
    DIRECTION INPUT ;
    USE SIGNAL ;
    PORT
      LAYER M4 ;
        RECT  0 58.752 0.192 58.776 ;
    END
  END d[304]
  PIN d[305]
    DIRECTION INPUT ;
    USE SIGNAL ;
    PORT
      LAYER M4 ;
        RECT  0 58.944 0.192 58.968 ;
    END
  END d[305]
  PIN d[306]
    DIRECTION INPUT ;
    USE SIGNAL ;
    PORT
      LAYER M4 ;
        RECT  0 59.136 0.192 59.16 ;
    END
  END d[306]
  PIN d[307]
    DIRECTION INPUT ;
    USE SIGNAL ;
    PORT
      LAYER M4 ;
        RECT  0 59.328 0.192 59.352 ;
    END
  END d[307]
  PIN d[308]
    DIRECTION INPUT ;
    USE SIGNAL ;
    PORT
      LAYER M4 ;
        RECT  0 59.52 0.192 59.544 ;
    END
  END d[308]
  PIN d[309]
    DIRECTION INPUT ;
    USE SIGNAL ;
    PORT
      LAYER M4 ;
        RECT  0 59.712 0.192 59.736 ;
    END
  END d[309]
  PIN d[30]
    DIRECTION INPUT ;
    USE SIGNAL ;
    PORT
      LAYER M4 ;
        RECT  0 6.144 0.192 6.168 ;
    END
  END d[30]
  PIN d[310]
    DIRECTION INPUT ;
    USE SIGNAL ;
    PORT
      LAYER M4 ;
        RECT  0 59.904 0.192 59.928 ;
    END
  END d[310]
  PIN d[311]
    DIRECTION INPUT ;
    USE SIGNAL ;
    PORT
      LAYER M4 ;
        RECT  0 60.096 0.192 60.12 ;
    END
  END d[311]
  PIN d[312]
    DIRECTION INPUT ;
    USE SIGNAL ;
    PORT
      LAYER M4 ;
        RECT  0 60.288 0.192 60.312 ;
    END
  END d[312]
  PIN d[313]
    DIRECTION INPUT ;
    USE SIGNAL ;
    PORT
      LAYER M4 ;
        RECT  0 60.48 0.192 60.504 ;
    END
  END d[313]
  PIN d[314]
    DIRECTION INPUT ;
    USE SIGNAL ;
    PORT
      LAYER M4 ;
        RECT  0 60.672 0.192 60.696 ;
    END
  END d[314]
  PIN d[315]
    DIRECTION INPUT ;
    USE SIGNAL ;
    PORT
      LAYER M4 ;
        RECT  0 60.864 0.192 60.888 ;
    END
  END d[315]
  PIN d[316]
    DIRECTION INPUT ;
    USE SIGNAL ;
    PORT
      LAYER M4 ;
        RECT  0 61.056 0.192 61.08 ;
    END
  END d[316]
  PIN d[317]
    DIRECTION INPUT ;
    USE SIGNAL ;
    PORT
      LAYER M4 ;
        RECT  0 61.248 0.192 61.272 ;
    END
  END d[317]
  PIN d[318]
    DIRECTION INPUT ;
    USE SIGNAL ;
    PORT
      LAYER M4 ;
        RECT  0 61.44 0.192 61.464 ;
    END
  END d[318]
  PIN d[319]
    DIRECTION INPUT ;
    USE SIGNAL ;
    PORT
      LAYER M4 ;
        RECT  0 61.632 0.192 61.656 ;
    END
  END d[319]
  PIN d[31]
    DIRECTION INPUT ;
    USE SIGNAL ;
    PORT
      LAYER M4 ;
        RECT  0 6.336 0.192 6.36 ;
    END
  END d[31]
  PIN d[320]
    DIRECTION INPUT ;
    USE SIGNAL ;
    PORT
      LAYER M4 ;
        RECT  0 61.824 0.192 61.848 ;
    END
  END d[320]
  PIN d[321]
    DIRECTION INPUT ;
    USE SIGNAL ;
    PORT
      LAYER M4 ;
        RECT  0 62.016 0.192 62.04 ;
    END
  END d[321]
  PIN d[322]
    DIRECTION INPUT ;
    USE SIGNAL ;
    PORT
      LAYER M4 ;
        RECT  0 62.208 0.192 62.232 ;
    END
  END d[322]
  PIN d[323]
    DIRECTION INPUT ;
    USE SIGNAL ;
    PORT
      LAYER M4 ;
        RECT  0 62.4 0.192 62.424 ;
    END
  END d[323]
  PIN d[324]
    DIRECTION INPUT ;
    USE SIGNAL ;
    PORT
      LAYER M4 ;
        RECT  0 62.592 0.192 62.616 ;
    END
  END d[324]
  PIN d[325]
    DIRECTION INPUT ;
    USE SIGNAL ;
    PORT
      LAYER M4 ;
        RECT  0 62.784 0.192 62.808 ;
    END
  END d[325]
  PIN d[326]
    DIRECTION INPUT ;
    USE SIGNAL ;
    PORT
      LAYER M4 ;
        RECT  0 62.976 0.192 63 ;
    END
  END d[326]
  PIN d[327]
    DIRECTION INPUT ;
    USE SIGNAL ;
    PORT
      LAYER M4 ;
        RECT  0 63.168 0.192 63.192 ;
    END
  END d[327]
  PIN d[328]
    DIRECTION INPUT ;
    USE SIGNAL ;
    PORT
      LAYER M4 ;
        RECT  0 63.36 0.192 63.384 ;
    END
  END d[328]
  PIN d[329]
    DIRECTION INPUT ;
    USE SIGNAL ;
    PORT
      LAYER M4 ;
        RECT  0 63.552 0.192 63.576 ;
    END
  END d[329]
  PIN d[32]
    DIRECTION INPUT ;
    USE SIGNAL ;
    PORT
      LAYER M4 ;
        RECT  0 6.528 0.192 6.552 ;
    END
  END d[32]
  PIN d[330]
    DIRECTION INPUT ;
    USE SIGNAL ;
    PORT
      LAYER M4 ;
        RECT  0 63.744 0.192 63.768 ;
    END
  END d[330]
  PIN d[331]
    DIRECTION INPUT ;
    USE SIGNAL ;
    PORT
      LAYER M4 ;
        RECT  0 63.936 0.192 63.96 ;
    END
  END d[331]
  PIN d[332]
    DIRECTION INPUT ;
    USE SIGNAL ;
    PORT
      LAYER M4 ;
        RECT  0 64.128 0.192 64.152 ;
    END
  END d[332]
  PIN d[333]
    DIRECTION INPUT ;
    USE SIGNAL ;
    PORT
      LAYER M4 ;
        RECT  0 64.32 0.192 64.344 ;
    END
  END d[333]
  PIN d[334]
    DIRECTION INPUT ;
    USE SIGNAL ;
    PORT
      LAYER M4 ;
        RECT  0 64.512 0.192 64.536 ;
    END
  END d[334]
  PIN d[335]
    DIRECTION INPUT ;
    USE SIGNAL ;
    PORT
      LAYER M4 ;
        RECT  0 64.704 0.192 64.728 ;
    END
  END d[335]
  PIN d[336]
    DIRECTION INPUT ;
    USE SIGNAL ;
    PORT
      LAYER M4 ;
        RECT  0 64.896 0.192 64.92 ;
    END
  END d[336]
  PIN d[337]
    DIRECTION INPUT ;
    USE SIGNAL ;
    PORT
      LAYER M4 ;
        RECT  0 65.088 0.192 65.112 ;
    END
  END d[337]
  PIN d[338]
    DIRECTION INPUT ;
    USE SIGNAL ;
    PORT
      LAYER M4 ;
        RECT  0 65.28 0.192 65.304 ;
    END
  END d[338]
  PIN d[339]
    DIRECTION INPUT ;
    USE SIGNAL ;
    PORT
      LAYER M4 ;
        RECT  0 65.472 0.192 65.496 ;
    END
  END d[339]
  PIN d[33]
    DIRECTION INPUT ;
    USE SIGNAL ;
    PORT
      LAYER M4 ;
        RECT  0 6.72 0.192 6.744 ;
    END
  END d[33]
  PIN d[340]
    DIRECTION INPUT ;
    USE SIGNAL ;
    PORT
      LAYER M4 ;
        RECT  0 65.664 0.192 65.688 ;
    END
  END d[340]
  PIN d[341]
    DIRECTION INPUT ;
    USE SIGNAL ;
    PORT
      LAYER M4 ;
        RECT  0 65.856 0.192 65.88 ;
    END
  END d[341]
  PIN d[342]
    DIRECTION INPUT ;
    USE SIGNAL ;
    PORT
      LAYER M4 ;
        RECT  0 66.048 0.192 66.072 ;
    END
  END d[342]
  PIN d[343]
    DIRECTION INPUT ;
    USE SIGNAL ;
    PORT
      LAYER M4 ;
        RECT  0 66.24 0.192 66.264 ;
    END
  END d[343]
  PIN d[344]
    DIRECTION INPUT ;
    USE SIGNAL ;
    PORT
      LAYER M4 ;
        RECT  0 66.432 0.192 66.456 ;
    END
  END d[344]
  PIN d[345]
    DIRECTION INPUT ;
    USE SIGNAL ;
    PORT
      LAYER M4 ;
        RECT  0 66.624 0.192 66.648 ;
    END
  END d[345]
  PIN d[346]
    DIRECTION INPUT ;
    USE SIGNAL ;
    PORT
      LAYER M4 ;
        RECT  0 66.816 0.192 66.84 ;
    END
  END d[346]
  PIN d[347]
    DIRECTION INPUT ;
    USE SIGNAL ;
    PORT
      LAYER M4 ;
        RECT  0 67.008 0.192 67.032 ;
    END
  END d[347]
  PIN d[348]
    DIRECTION INPUT ;
    USE SIGNAL ;
    PORT
      LAYER M4 ;
        RECT  0 67.2 0.192 67.224 ;
    END
  END d[348]
  PIN d[349]
    DIRECTION INPUT ;
    USE SIGNAL ;
    PORT
      LAYER M4 ;
        RECT  0 67.392 0.192 67.416 ;
    END
  END d[349]
  PIN d[34]
    DIRECTION INPUT ;
    USE SIGNAL ;
    PORT
      LAYER M4 ;
        RECT  0 6.912 0.192 6.936 ;
    END
  END d[34]
  PIN d[350]
    DIRECTION INPUT ;
    USE SIGNAL ;
    PORT
      LAYER M4 ;
        RECT  0 67.584 0.192 67.608 ;
    END
  END d[350]
  PIN d[351]
    DIRECTION INPUT ;
    USE SIGNAL ;
    PORT
      LAYER M4 ;
        RECT  0 67.776 0.192 67.8 ;
    END
  END d[351]
  PIN d[352]
    DIRECTION INPUT ;
    USE SIGNAL ;
    PORT
      LAYER M4 ;
        RECT  0 67.968 0.192 67.992 ;
    END
  END d[352]
  PIN d[353]
    DIRECTION INPUT ;
    USE SIGNAL ;
    PORT
      LAYER M4 ;
        RECT  0 68.16 0.192 68.184 ;
    END
  END d[353]
  PIN d[354]
    DIRECTION INPUT ;
    USE SIGNAL ;
    PORT
      LAYER M4 ;
        RECT  0 68.352 0.192 68.376 ;
    END
  END d[354]
  PIN d[355]
    DIRECTION INPUT ;
    USE SIGNAL ;
    PORT
      LAYER M4 ;
        RECT  0 68.544 0.192 68.568 ;
    END
  END d[355]
  PIN d[356]
    DIRECTION INPUT ;
    USE SIGNAL ;
    PORT
      LAYER M4 ;
        RECT  0 68.736 0.192 68.76 ;
    END
  END d[356]
  PIN d[357]
    DIRECTION INPUT ;
    USE SIGNAL ;
    PORT
      LAYER M4 ;
        RECT  0 68.928 0.192 68.952 ;
    END
  END d[357]
  PIN d[358]
    DIRECTION INPUT ;
    USE SIGNAL ;
    PORT
      LAYER M4 ;
        RECT  0 69.12 0.192 69.144 ;
    END
  END d[358]
  PIN d[359]
    DIRECTION INPUT ;
    USE SIGNAL ;
    PORT
      LAYER M4 ;
        RECT  0 69.312 0.192 69.336 ;
    END
  END d[359]
  PIN d[35]
    DIRECTION INPUT ;
    USE SIGNAL ;
    PORT
      LAYER M4 ;
        RECT  0 7.104 0.192 7.128 ;
    END
  END d[35]
  PIN d[360]
    DIRECTION INPUT ;
    USE SIGNAL ;
    PORT
      LAYER M4 ;
        RECT  0 69.504 0.192 69.528 ;
    END
  END d[360]
  PIN d[361]
    DIRECTION INPUT ;
    USE SIGNAL ;
    PORT
      LAYER M4 ;
        RECT  0 69.696 0.192 69.72 ;
    END
  END d[361]
  PIN d[362]
    DIRECTION INPUT ;
    USE SIGNAL ;
    PORT
      LAYER M4 ;
        RECT  0 69.888 0.192 69.912 ;
    END
  END d[362]
  PIN d[363]
    DIRECTION INPUT ;
    USE SIGNAL ;
    PORT
      LAYER M4 ;
        RECT  0 70.08 0.192 70.104 ;
    END
  END d[363]
  PIN d[364]
    DIRECTION INPUT ;
    USE SIGNAL ;
    PORT
      LAYER M4 ;
        RECT  0 70.272 0.192 70.296 ;
    END
  END d[364]
  PIN d[365]
    DIRECTION INPUT ;
    USE SIGNAL ;
    PORT
      LAYER M4 ;
        RECT  0 70.464 0.192 70.488 ;
    END
  END d[365]
  PIN d[366]
    DIRECTION INPUT ;
    USE SIGNAL ;
    PORT
      LAYER M4 ;
        RECT  0 70.656 0.192 70.68 ;
    END
  END d[366]
  PIN d[367]
    DIRECTION INPUT ;
    USE SIGNAL ;
    PORT
      LAYER M4 ;
        RECT  0 70.848 0.192 70.872 ;
    END
  END d[367]
  PIN d[368]
    DIRECTION INPUT ;
    USE SIGNAL ;
    PORT
      LAYER M4 ;
        RECT  0 71.04 0.192 71.064 ;
    END
  END d[368]
  PIN d[369]
    DIRECTION INPUT ;
    USE SIGNAL ;
    PORT
      LAYER M4 ;
        RECT  0 71.232 0.192 71.256 ;
    END
  END d[369]
  PIN d[36]
    DIRECTION INPUT ;
    USE SIGNAL ;
    PORT
      LAYER M4 ;
        RECT  0 7.296 0.192 7.32 ;
    END
  END d[36]
  PIN d[370]
    DIRECTION INPUT ;
    USE SIGNAL ;
    PORT
      LAYER M4 ;
        RECT  0 71.424 0.192 71.448 ;
    END
  END d[370]
  PIN d[371]
    DIRECTION INPUT ;
    USE SIGNAL ;
    PORT
      LAYER M4 ;
        RECT  0 71.616 0.192 71.64 ;
    END
  END d[371]
  PIN d[372]
    DIRECTION INPUT ;
    USE SIGNAL ;
    PORT
      LAYER M4 ;
        RECT  0 71.808 0.192 71.832 ;
    END
  END d[372]
  PIN d[373]
    DIRECTION INPUT ;
    USE SIGNAL ;
    PORT
      LAYER M4 ;
        RECT  0 72 0.192 72.024 ;
    END
  END d[373]
  PIN d[374]
    DIRECTION INPUT ;
    USE SIGNAL ;
    PORT
      LAYER M4 ;
        RECT  0 72.192 0.192 72.216 ;
    END
  END d[374]
  PIN d[375]
    DIRECTION INPUT ;
    USE SIGNAL ;
    PORT
      LAYER M4 ;
        RECT  0 72.384 0.192 72.408 ;
    END
  END d[375]
  PIN d[376]
    DIRECTION INPUT ;
    USE SIGNAL ;
    PORT
      LAYER M4 ;
        RECT  0 72.576 0.192 72.6 ;
    END
  END d[376]
  PIN d[377]
    DIRECTION INPUT ;
    USE SIGNAL ;
    PORT
      LAYER M4 ;
        RECT  0 72.768 0.192 72.792 ;
    END
  END d[377]
  PIN d[378]
    DIRECTION INPUT ;
    USE SIGNAL ;
    PORT
      LAYER M4 ;
        RECT  0 72.96 0.192 72.984 ;
    END
  END d[378]
  PIN d[379]
    DIRECTION INPUT ;
    USE SIGNAL ;
    PORT
      LAYER M4 ;
        RECT  0 73.152 0.192 73.176 ;
    END
  END d[379]
  PIN d[37]
    DIRECTION INPUT ;
    USE SIGNAL ;
    PORT
      LAYER M4 ;
        RECT  0 7.488 0.192 7.512 ;
    END
  END d[37]
  PIN d[380]
    DIRECTION INPUT ;
    USE SIGNAL ;
    PORT
      LAYER M4 ;
        RECT  0 73.344 0.192 73.368 ;
    END
  END d[380]
  PIN d[381]
    DIRECTION INPUT ;
    USE SIGNAL ;
    PORT
      LAYER M4 ;
        RECT  0 73.536 0.192 73.56 ;
    END
  END d[381]
  PIN d[382]
    DIRECTION INPUT ;
    USE SIGNAL ;
    PORT
      LAYER M4 ;
        RECT  0 73.728 0.192 73.752 ;
    END
  END d[382]
  PIN d[383]
    DIRECTION INPUT ;
    USE SIGNAL ;
    PORT
      LAYER M4 ;
        RECT  0 73.92 0.192 73.944 ;
    END
  END d[383]
  PIN d[384]
    DIRECTION INPUT ;
    USE SIGNAL ;
    PORT
      LAYER M4 ;
        RECT  0 74.112 0.192 74.136 ;
    END
  END d[384]
  PIN d[385]
    DIRECTION INPUT ;
    USE SIGNAL ;
    PORT
      LAYER M4 ;
        RECT  0 74.304 0.192 74.328 ;
    END
  END d[385]
  PIN d[386]
    DIRECTION INPUT ;
    USE SIGNAL ;
    PORT
      LAYER M4 ;
        RECT  0 74.496 0.192 74.52 ;
    END
  END d[386]
  PIN d[387]
    DIRECTION INPUT ;
    USE SIGNAL ;
    PORT
      LAYER M4 ;
        RECT  0 74.688 0.192 74.712 ;
    END
  END d[387]
  PIN d[388]
    DIRECTION INPUT ;
    USE SIGNAL ;
    PORT
      LAYER M4 ;
        RECT  0 74.88 0.192 74.904 ;
    END
  END d[388]
  PIN d[389]
    DIRECTION INPUT ;
    USE SIGNAL ;
    PORT
      LAYER M4 ;
        RECT  0 75.072 0.192 75.096 ;
    END
  END d[389]
  PIN d[38]
    DIRECTION INPUT ;
    USE SIGNAL ;
    PORT
      LAYER M4 ;
        RECT  0 7.68 0.192 7.704 ;
    END
  END d[38]
  PIN d[390]
    DIRECTION INPUT ;
    USE SIGNAL ;
    PORT
      LAYER M4 ;
        RECT  0 75.264 0.192 75.288 ;
    END
  END d[390]
  PIN d[391]
    DIRECTION INPUT ;
    USE SIGNAL ;
    PORT
      LAYER M4 ;
        RECT  0 75.456 0.192 75.48 ;
    END
  END d[391]
  PIN d[392]
    DIRECTION INPUT ;
    USE SIGNAL ;
    PORT
      LAYER M4 ;
        RECT  0 75.648 0.192 75.672 ;
    END
  END d[392]
  PIN d[393]
    DIRECTION INPUT ;
    USE SIGNAL ;
    PORT
      LAYER M4 ;
        RECT  0 75.84 0.192 75.864 ;
    END
  END d[393]
  PIN d[394]
    DIRECTION INPUT ;
    USE SIGNAL ;
    PORT
      LAYER M4 ;
        RECT  0 76.032 0.192 76.056 ;
    END
  END d[394]
  PIN d[395]
    DIRECTION INPUT ;
    USE SIGNAL ;
    PORT
      LAYER M4 ;
        RECT  0 76.224 0.192 76.248 ;
    END
  END d[395]
  PIN d[396]
    DIRECTION INPUT ;
    USE SIGNAL ;
    PORT
      LAYER M4 ;
        RECT  0 76.416 0.192 76.44 ;
    END
  END d[396]
  PIN d[397]
    DIRECTION INPUT ;
    USE SIGNAL ;
    PORT
      LAYER M4 ;
        RECT  0 76.608 0.192 76.632 ;
    END
  END d[397]
  PIN d[398]
    DIRECTION INPUT ;
    USE SIGNAL ;
    PORT
      LAYER M4 ;
        RECT  0 76.8 0.192 76.824 ;
    END
  END d[398]
  PIN d[399]
    DIRECTION INPUT ;
    USE SIGNAL ;
    PORT
      LAYER M4 ;
        RECT  0 76.992 0.192 77.016 ;
    END
  END d[399]
  PIN d[39]
    DIRECTION INPUT ;
    USE SIGNAL ;
    PORT
      LAYER M4 ;
        RECT  0 7.872 0.192 7.896 ;
    END
  END d[39]
  PIN d[3]
    DIRECTION INPUT ;
    USE SIGNAL ;
    PORT
      LAYER M4 ;
        RECT  0 0.96 0.192 0.984 ;
    END
  END d[3]
  PIN d[400]
    DIRECTION INPUT ;
    USE SIGNAL ;
    PORT
      LAYER M4 ;
        RECT  0 77.184 0.192 77.208 ;
    END
  END d[400]
  PIN d[401]
    DIRECTION INPUT ;
    USE SIGNAL ;
    PORT
      LAYER M4 ;
        RECT  0 77.376 0.192 77.4 ;
    END
  END d[401]
  PIN d[402]
    DIRECTION INPUT ;
    USE SIGNAL ;
    PORT
      LAYER M4 ;
        RECT  0 77.568 0.192 77.592 ;
    END
  END d[402]
  PIN d[403]
    DIRECTION INPUT ;
    USE SIGNAL ;
    PORT
      LAYER M4 ;
        RECT  0 77.76 0.192 77.784 ;
    END
  END d[403]
  PIN d[404]
    DIRECTION INPUT ;
    USE SIGNAL ;
    PORT
      LAYER M4 ;
        RECT  0 77.952 0.192 77.976 ;
    END
  END d[404]
  PIN d[405]
    DIRECTION INPUT ;
    USE SIGNAL ;
    PORT
      LAYER M4 ;
        RECT  0 78.144 0.192 78.168 ;
    END
  END d[405]
  PIN d[406]
    DIRECTION INPUT ;
    USE SIGNAL ;
    PORT
      LAYER M4 ;
        RECT  0 78.336 0.192 78.36 ;
    END
  END d[406]
  PIN d[407]
    DIRECTION INPUT ;
    USE SIGNAL ;
    PORT
      LAYER M4 ;
        RECT  0 78.528 0.192 78.552 ;
    END
  END d[407]
  PIN d[408]
    DIRECTION INPUT ;
    USE SIGNAL ;
    PORT
      LAYER M4 ;
        RECT  0 78.72 0.192 78.744 ;
    END
  END d[408]
  PIN d[409]
    DIRECTION INPUT ;
    USE SIGNAL ;
    PORT
      LAYER M4 ;
        RECT  0 78.912 0.192 78.936 ;
    END
  END d[409]
  PIN d[40]
    DIRECTION INPUT ;
    USE SIGNAL ;
    PORT
      LAYER M4 ;
        RECT  0 8.064 0.192 8.088 ;
    END
  END d[40]
  PIN d[410]
    DIRECTION INPUT ;
    USE SIGNAL ;
    PORT
      LAYER M4 ;
        RECT  0 79.104 0.192 79.128 ;
    END
  END d[410]
  PIN d[411]
    DIRECTION INPUT ;
    USE SIGNAL ;
    PORT
      LAYER M4 ;
        RECT  0 79.296 0.192 79.32 ;
    END
  END d[411]
  PIN d[412]
    DIRECTION INPUT ;
    USE SIGNAL ;
    PORT
      LAYER M4 ;
        RECT  0 79.488 0.192 79.512 ;
    END
  END d[412]
  PIN d[413]
    DIRECTION INPUT ;
    USE SIGNAL ;
    PORT
      LAYER M4 ;
        RECT  0 79.68 0.192 79.704 ;
    END
  END d[413]
  PIN d[414]
    DIRECTION INPUT ;
    USE SIGNAL ;
    PORT
      LAYER M4 ;
        RECT  0 79.872 0.192 79.896 ;
    END
  END d[414]
  PIN d[415]
    DIRECTION INPUT ;
    USE SIGNAL ;
    PORT
      LAYER M4 ;
        RECT  0 80.064 0.192 80.088 ;
    END
  END d[415]
  PIN d[416]
    DIRECTION INPUT ;
    USE SIGNAL ;
    PORT
      LAYER M4 ;
        RECT  0 80.256 0.192 80.28 ;
    END
  END d[416]
  PIN d[417]
    DIRECTION INPUT ;
    USE SIGNAL ;
    PORT
      LAYER M4 ;
        RECT  0 80.448 0.192 80.472 ;
    END
  END d[417]
  PIN d[418]
    DIRECTION INPUT ;
    USE SIGNAL ;
    PORT
      LAYER M4 ;
        RECT  0 80.64 0.192 80.664 ;
    END
  END d[418]
  PIN d[419]
    DIRECTION INPUT ;
    USE SIGNAL ;
    PORT
      LAYER M4 ;
        RECT  0 80.832 0.192 80.856 ;
    END
  END d[419]
  PIN d[41]
    DIRECTION INPUT ;
    USE SIGNAL ;
    PORT
      LAYER M4 ;
        RECT  0 8.256 0.192 8.28 ;
    END
  END d[41]
  PIN d[420]
    DIRECTION INPUT ;
    USE SIGNAL ;
    PORT
      LAYER M4 ;
        RECT  0 81.024 0.192 81.048 ;
    END
  END d[420]
  PIN d[421]
    DIRECTION INPUT ;
    USE SIGNAL ;
    PORT
      LAYER M4 ;
        RECT  0 81.216 0.192 81.24 ;
    END
  END d[421]
  PIN d[422]
    DIRECTION INPUT ;
    USE SIGNAL ;
    PORT
      LAYER M4 ;
        RECT  0 81.408 0.192 81.432 ;
    END
  END d[422]
  PIN d[423]
    DIRECTION INPUT ;
    USE SIGNAL ;
    PORT
      LAYER M4 ;
        RECT  0 81.6 0.192 81.624 ;
    END
  END d[423]
  PIN d[424]
    DIRECTION INPUT ;
    USE SIGNAL ;
    PORT
      LAYER M4 ;
        RECT  0 81.792 0.192 81.816 ;
    END
  END d[424]
  PIN d[425]
    DIRECTION INPUT ;
    USE SIGNAL ;
    PORT
      LAYER M4 ;
        RECT  0 81.984 0.192 82.008 ;
    END
  END d[425]
  PIN d[426]
    DIRECTION INPUT ;
    USE SIGNAL ;
    PORT
      LAYER M4 ;
        RECT  0 82.176 0.192 82.2 ;
    END
  END d[426]
  PIN d[427]
    DIRECTION INPUT ;
    USE SIGNAL ;
    PORT
      LAYER M4 ;
        RECT  0 82.368 0.192 82.392 ;
    END
  END d[427]
  PIN d[428]
    DIRECTION INPUT ;
    USE SIGNAL ;
    PORT
      LAYER M4 ;
        RECT  0 82.56 0.192 82.584 ;
    END
  END d[428]
  PIN d[429]
    DIRECTION INPUT ;
    USE SIGNAL ;
    PORT
      LAYER M4 ;
        RECT  0 82.752 0.192 82.776 ;
    END
  END d[429]
  PIN d[42]
    DIRECTION INPUT ;
    USE SIGNAL ;
    PORT
      LAYER M4 ;
        RECT  0 8.448 0.192 8.472 ;
    END
  END d[42]
  PIN d[430]
    DIRECTION INPUT ;
    USE SIGNAL ;
    PORT
      LAYER M4 ;
        RECT  0 82.944 0.192 82.968 ;
    END
  END d[430]
  PIN d[431]
    DIRECTION INPUT ;
    USE SIGNAL ;
    PORT
      LAYER M4 ;
        RECT  0 83.136 0.192 83.16 ;
    END
  END d[431]
  PIN d[432]
    DIRECTION INPUT ;
    USE SIGNAL ;
    PORT
      LAYER M4 ;
        RECT  0 83.328 0.192 83.352 ;
    END
  END d[432]
  PIN d[433]
    DIRECTION INPUT ;
    USE SIGNAL ;
    PORT
      LAYER M4 ;
        RECT  0 83.52 0.192 83.544 ;
    END
  END d[433]
  PIN d[434]
    DIRECTION INPUT ;
    USE SIGNAL ;
    PORT
      LAYER M4 ;
        RECT  0 83.712 0.192 83.736 ;
    END
  END d[434]
  PIN d[435]
    DIRECTION INPUT ;
    USE SIGNAL ;
    PORT
      LAYER M4 ;
        RECT  0 83.904 0.192 83.928 ;
    END
  END d[435]
  PIN d[436]
    DIRECTION INPUT ;
    USE SIGNAL ;
    PORT
      LAYER M4 ;
        RECT  0 84.096 0.192 84.12 ;
    END
  END d[436]
  PIN d[437]
    DIRECTION INPUT ;
    USE SIGNAL ;
    PORT
      LAYER M4 ;
        RECT  0 84.288 0.192 84.312 ;
    END
  END d[437]
  PIN d[438]
    DIRECTION INPUT ;
    USE SIGNAL ;
    PORT
      LAYER M4 ;
        RECT  0 84.48 0.192 84.504 ;
    END
  END d[438]
  PIN d[439]
    DIRECTION INPUT ;
    USE SIGNAL ;
    PORT
      LAYER M4 ;
        RECT  0 84.672 0.192 84.696 ;
    END
  END d[439]
  PIN d[43]
    DIRECTION INPUT ;
    USE SIGNAL ;
    PORT
      LAYER M4 ;
        RECT  0 8.64 0.192 8.664 ;
    END
  END d[43]
  PIN d[440]
    DIRECTION INPUT ;
    USE SIGNAL ;
    PORT
      LAYER M4 ;
        RECT  0 84.864 0.192 84.888 ;
    END
  END d[440]
  PIN d[441]
    DIRECTION INPUT ;
    USE SIGNAL ;
    PORT
      LAYER M4 ;
        RECT  0 85.056 0.192 85.08 ;
    END
  END d[441]
  PIN d[442]
    DIRECTION INPUT ;
    USE SIGNAL ;
    PORT
      LAYER M4 ;
        RECT  0 85.248 0.192 85.272 ;
    END
  END d[442]
  PIN d[443]
    DIRECTION INPUT ;
    USE SIGNAL ;
    PORT
      LAYER M4 ;
        RECT  0 85.44 0.192 85.464 ;
    END
  END d[443]
  PIN d[444]
    DIRECTION INPUT ;
    USE SIGNAL ;
    PORT
      LAYER M4 ;
        RECT  0 85.632 0.192 85.656 ;
    END
  END d[444]
  PIN d[445]
    DIRECTION INPUT ;
    USE SIGNAL ;
    PORT
      LAYER M4 ;
        RECT  0 85.824 0.192 85.848 ;
    END
  END d[445]
  PIN d[446]
    DIRECTION INPUT ;
    USE SIGNAL ;
    PORT
      LAYER M4 ;
        RECT  0 86.016 0.192 86.04 ;
    END
  END d[446]
  PIN d[447]
    DIRECTION INPUT ;
    USE SIGNAL ;
    PORT
      LAYER M4 ;
        RECT  0 86.208 0.192 86.232 ;
    END
  END d[447]
  PIN d[448]
    DIRECTION INPUT ;
    USE SIGNAL ;
    PORT
      LAYER M4 ;
        RECT  0 86.4 0.192 86.424 ;
    END
  END d[448]
  PIN d[449]
    DIRECTION INPUT ;
    USE SIGNAL ;
    PORT
      LAYER M4 ;
        RECT  0 86.592 0.192 86.616 ;
    END
  END d[449]
  PIN d[44]
    DIRECTION INPUT ;
    USE SIGNAL ;
    PORT
      LAYER M4 ;
        RECT  0 8.832 0.192 8.856 ;
    END
  END d[44]
  PIN d[450]
    DIRECTION INPUT ;
    USE SIGNAL ;
    PORT
      LAYER M4 ;
        RECT  0 86.784 0.192 86.808 ;
    END
  END d[450]
  PIN d[451]
    DIRECTION INPUT ;
    USE SIGNAL ;
    PORT
      LAYER M4 ;
        RECT  0 86.976 0.192 87 ;
    END
  END d[451]
  PIN d[452]
    DIRECTION INPUT ;
    USE SIGNAL ;
    PORT
      LAYER M4 ;
        RECT  0 87.168 0.192 87.192 ;
    END
  END d[452]
  PIN d[453]
    DIRECTION INPUT ;
    USE SIGNAL ;
    PORT
      LAYER M4 ;
        RECT  0 87.36 0.192 87.384 ;
    END
  END d[453]
  PIN d[454]
    DIRECTION INPUT ;
    USE SIGNAL ;
    PORT
      LAYER M4 ;
        RECT  0 87.552 0.192 87.576 ;
    END
  END d[454]
  PIN d[455]
    DIRECTION INPUT ;
    USE SIGNAL ;
    PORT
      LAYER M4 ;
        RECT  0 87.744 0.192 87.768 ;
    END
  END d[455]
  PIN d[456]
    DIRECTION INPUT ;
    USE SIGNAL ;
    PORT
      LAYER M4 ;
        RECT  0 87.936 0.192 87.96 ;
    END
  END d[456]
  PIN d[457]
    DIRECTION INPUT ;
    USE SIGNAL ;
    PORT
      LAYER M4 ;
        RECT  0 88.128 0.192 88.152 ;
    END
  END d[457]
  PIN d[458]
    DIRECTION INPUT ;
    USE SIGNAL ;
    PORT
      LAYER M4 ;
        RECT  0 88.32 0.192 88.344 ;
    END
  END d[458]
  PIN d[459]
    DIRECTION INPUT ;
    USE SIGNAL ;
    PORT
      LAYER M4 ;
        RECT  0 88.512 0.192 88.536 ;
    END
  END d[459]
  PIN d[45]
    DIRECTION INPUT ;
    USE SIGNAL ;
    PORT
      LAYER M4 ;
        RECT  0 9.024 0.192 9.048 ;
    END
  END d[45]
  PIN d[460]
    DIRECTION INPUT ;
    USE SIGNAL ;
    PORT
      LAYER M4 ;
        RECT  0 88.704 0.192 88.728 ;
    END
  END d[460]
  PIN d[461]
    DIRECTION INPUT ;
    USE SIGNAL ;
    PORT
      LAYER M4 ;
        RECT  0 88.896 0.192 88.92 ;
    END
  END d[461]
  PIN d[462]
    DIRECTION INPUT ;
    USE SIGNAL ;
    PORT
      LAYER M4 ;
        RECT  0 89.088 0.192 89.112 ;
    END
  END d[462]
  PIN d[463]
    DIRECTION INPUT ;
    USE SIGNAL ;
    PORT
      LAYER M4 ;
        RECT  0 89.28 0.192 89.304 ;
    END
  END d[463]
  PIN d[464]
    DIRECTION INPUT ;
    USE SIGNAL ;
    PORT
      LAYER M4 ;
        RECT  0 89.472 0.192 89.496 ;
    END
  END d[464]
  PIN d[465]
    DIRECTION INPUT ;
    USE SIGNAL ;
    PORT
      LAYER M4 ;
        RECT  0 89.664 0.192 89.688 ;
    END
  END d[465]
  PIN d[466]
    DIRECTION INPUT ;
    USE SIGNAL ;
    PORT
      LAYER M4 ;
        RECT  0 89.856 0.192 89.88 ;
    END
  END d[466]
  PIN d[467]
    DIRECTION INPUT ;
    USE SIGNAL ;
    PORT
      LAYER M4 ;
        RECT  0 90.048 0.192 90.072 ;
    END
  END d[467]
  PIN d[468]
    DIRECTION INPUT ;
    USE SIGNAL ;
    PORT
      LAYER M4 ;
        RECT  0 90.24 0.192 90.264 ;
    END
  END d[468]
  PIN d[469]
    DIRECTION INPUT ;
    USE SIGNAL ;
    PORT
      LAYER M4 ;
        RECT  0 90.432 0.192 90.456 ;
    END
  END d[469]
  PIN d[46]
    DIRECTION INPUT ;
    USE SIGNAL ;
    PORT
      LAYER M4 ;
        RECT  0 9.216 0.192 9.24 ;
    END
  END d[46]
  PIN d[470]
    DIRECTION INPUT ;
    USE SIGNAL ;
    PORT
      LAYER M4 ;
        RECT  0 90.624 0.192 90.648 ;
    END
  END d[470]
  PIN d[471]
    DIRECTION INPUT ;
    USE SIGNAL ;
    PORT
      LAYER M4 ;
        RECT  0 90.816 0.192 90.84 ;
    END
  END d[471]
  PIN d[472]
    DIRECTION INPUT ;
    USE SIGNAL ;
    PORT
      LAYER M4 ;
        RECT  0 91.008 0.192 91.032 ;
    END
  END d[472]
  PIN d[473]
    DIRECTION INPUT ;
    USE SIGNAL ;
    PORT
      LAYER M4 ;
        RECT  0 91.2 0.192 91.224 ;
    END
  END d[473]
  PIN d[474]
    DIRECTION INPUT ;
    USE SIGNAL ;
    PORT
      LAYER M4 ;
        RECT  0 91.392 0.192 91.416 ;
    END
  END d[474]
  PIN d[475]
    DIRECTION INPUT ;
    USE SIGNAL ;
    PORT
      LAYER M4 ;
        RECT  0 91.584 0.192 91.608 ;
    END
  END d[475]
  PIN d[476]
    DIRECTION INPUT ;
    USE SIGNAL ;
    PORT
      LAYER M4 ;
        RECT  0 91.776 0.192 91.8 ;
    END
  END d[476]
  PIN d[477]
    DIRECTION INPUT ;
    USE SIGNAL ;
    PORT
      LAYER M4 ;
        RECT  0 91.968 0.192 91.992 ;
    END
  END d[477]
  PIN d[478]
    DIRECTION INPUT ;
    USE SIGNAL ;
    PORT
      LAYER M4 ;
        RECT  0 92.16 0.192 92.184 ;
    END
  END d[478]
  PIN d[479]
    DIRECTION INPUT ;
    USE SIGNAL ;
    PORT
      LAYER M4 ;
        RECT  0 92.352 0.192 92.376 ;
    END
  END d[479]
  PIN d[47]
    DIRECTION INPUT ;
    USE SIGNAL ;
    PORT
      LAYER M4 ;
        RECT  0 9.408 0.192 9.432 ;
    END
  END d[47]
  PIN d[480]
    DIRECTION INPUT ;
    USE SIGNAL ;
    PORT
      LAYER M4 ;
        RECT  0 92.544 0.192 92.568 ;
    END
  END d[480]
  PIN d[481]
    DIRECTION INPUT ;
    USE SIGNAL ;
    PORT
      LAYER M4 ;
        RECT  0 92.736 0.192 92.76 ;
    END
  END d[481]
  PIN d[482]
    DIRECTION INPUT ;
    USE SIGNAL ;
    PORT
      LAYER M4 ;
        RECT  0 92.928 0.192 92.952 ;
    END
  END d[482]
  PIN d[483]
    DIRECTION INPUT ;
    USE SIGNAL ;
    PORT
      LAYER M4 ;
        RECT  0 93.12 0.192 93.144 ;
    END
  END d[483]
  PIN d[484]
    DIRECTION INPUT ;
    USE SIGNAL ;
    PORT
      LAYER M4 ;
        RECT  0 93.312 0.192 93.336 ;
    END
  END d[484]
  PIN d[485]
    DIRECTION INPUT ;
    USE SIGNAL ;
    PORT
      LAYER M4 ;
        RECT  0 93.504 0.192 93.528 ;
    END
  END d[485]
  PIN d[486]
    DIRECTION INPUT ;
    USE SIGNAL ;
    PORT
      LAYER M4 ;
        RECT  0 93.696 0.192 93.72 ;
    END
  END d[486]
  PIN d[487]
    DIRECTION INPUT ;
    USE SIGNAL ;
    PORT
      LAYER M4 ;
        RECT  0 93.888 0.192 93.912 ;
    END
  END d[487]
  PIN d[488]
    DIRECTION INPUT ;
    USE SIGNAL ;
    PORT
      LAYER M4 ;
        RECT  0 94.08 0.192 94.104 ;
    END
  END d[488]
  PIN d[489]
    DIRECTION INPUT ;
    USE SIGNAL ;
    PORT
      LAYER M4 ;
        RECT  0 94.272 0.192 94.296 ;
    END
  END d[489]
  PIN d[48]
    DIRECTION INPUT ;
    USE SIGNAL ;
    PORT
      LAYER M4 ;
        RECT  0 9.6 0.192 9.624 ;
    END
  END d[48]
  PIN d[490]
    DIRECTION INPUT ;
    USE SIGNAL ;
    PORT
      LAYER M4 ;
        RECT  0 94.464 0.192 94.488 ;
    END
  END d[490]
  PIN d[491]
    DIRECTION INPUT ;
    USE SIGNAL ;
    PORT
      LAYER M4 ;
        RECT  0 94.656 0.192 94.68 ;
    END
  END d[491]
  PIN d[492]
    DIRECTION INPUT ;
    USE SIGNAL ;
    PORT
      LAYER M4 ;
        RECT  0 94.848 0.192 94.872 ;
    END
  END d[492]
  PIN d[493]
    DIRECTION INPUT ;
    USE SIGNAL ;
    PORT
      LAYER M4 ;
        RECT  0 95.04 0.192 95.064 ;
    END
  END d[493]
  PIN d[494]
    DIRECTION INPUT ;
    USE SIGNAL ;
    PORT
      LAYER M4 ;
        RECT  0 95.232 0.192 95.256 ;
    END
  END d[494]
  PIN d[495]
    DIRECTION INPUT ;
    USE SIGNAL ;
    PORT
      LAYER M4 ;
        RECT  0 95.424 0.192 95.448 ;
    END
  END d[495]
  PIN d[496]
    DIRECTION INPUT ;
    USE SIGNAL ;
    PORT
      LAYER M4 ;
        RECT  0 95.616 0.192 95.64 ;
    END
  END d[496]
  PIN d[497]
    DIRECTION INPUT ;
    USE SIGNAL ;
    PORT
      LAYER M4 ;
        RECT  0 95.808 0.192 95.832 ;
    END
  END d[497]
  PIN d[498]
    DIRECTION INPUT ;
    USE SIGNAL ;
    PORT
      LAYER M4 ;
        RECT  0 96 0.192 96.024 ;
    END
  END d[498]
  PIN d[499]
    DIRECTION INPUT ;
    USE SIGNAL ;
    PORT
      LAYER M4 ;
        RECT  0 96.192 0.192 96.216 ;
    END
  END d[499]
  PIN d[49]
    DIRECTION INPUT ;
    USE SIGNAL ;
    PORT
      LAYER M4 ;
        RECT  0 9.792 0.192 9.816 ;
    END
  END d[49]
  PIN d[4]
    DIRECTION INPUT ;
    USE SIGNAL ;
    PORT
      LAYER M4 ;
        RECT  0 1.152 0.192 1.176 ;
    END
  END d[4]
  PIN d[500]
    DIRECTION INPUT ;
    USE SIGNAL ;
    PORT
      LAYER M4 ;
        RECT  0 96.384 0.192 96.408 ;
    END
  END d[500]
  PIN d[501]
    DIRECTION INPUT ;
    USE SIGNAL ;
    PORT
      LAYER M4 ;
        RECT  0 96.576 0.192 96.6 ;
    END
  END d[501]
  PIN d[502]
    DIRECTION INPUT ;
    USE SIGNAL ;
    PORT
      LAYER M4 ;
        RECT  0 96.768 0.192 96.792 ;
    END
  END d[502]
  PIN d[503]
    DIRECTION INPUT ;
    USE SIGNAL ;
    PORT
      LAYER M4 ;
        RECT  0 96.96 0.192 96.984 ;
    END
  END d[503]
  PIN d[504]
    DIRECTION INPUT ;
    USE SIGNAL ;
    PORT
      LAYER M4 ;
        RECT  0 97.152 0.192 97.176 ;
    END
  END d[504]
  PIN d[505]
    DIRECTION INPUT ;
    USE SIGNAL ;
    PORT
      LAYER M4 ;
        RECT  0 97.344 0.192 97.368 ;
    END
  END d[505]
  PIN d[506]
    DIRECTION INPUT ;
    USE SIGNAL ;
    PORT
      LAYER M4 ;
        RECT  0 97.536 0.192 97.56 ;
    END
  END d[506]
  PIN d[507]
    DIRECTION INPUT ;
    USE SIGNAL ;
    PORT
      LAYER M4 ;
        RECT  0 97.728 0.192 97.752 ;
    END
  END d[507]
  PIN d[508]
    DIRECTION INPUT ;
    USE SIGNAL ;
    PORT
      LAYER M4 ;
        RECT  0 97.92 0.192 97.944 ;
    END
  END d[508]
  PIN d[509]
    DIRECTION INPUT ;
    USE SIGNAL ;
    PORT
      LAYER M4 ;
        RECT  0 98.112 0.192 98.136 ;
    END
  END d[509]
  PIN d[50]
    DIRECTION INPUT ;
    USE SIGNAL ;
    PORT
      LAYER M4 ;
        RECT  0 9.984 0.192 10.008 ;
    END
  END d[50]
  PIN d[510]
    DIRECTION INPUT ;
    USE SIGNAL ;
    PORT
      LAYER M4 ;
        RECT  0 98.304 0.192 98.328 ;
    END
  END d[510]
  PIN d[511]
    DIRECTION INPUT ;
    USE SIGNAL ;
    PORT
      LAYER M4 ;
        RECT  0 98.496 0.192 98.52 ;
    END
  END d[511]
  PIN d[512]
    DIRECTION INPUT ;
    USE SIGNAL ;
    PORT
      LAYER M4 ;
        RECT  0 98.688 0.192 98.712 ;
    END
  END d[512]
  PIN d[513]
    DIRECTION INPUT ;
    USE SIGNAL ;
    PORT
      LAYER M4 ;
        RECT  0 98.88 0.192 98.904 ;
    END
  END d[513]
  PIN d[514]
    DIRECTION INPUT ;
    USE SIGNAL ;
    PORT
      LAYER M4 ;
        RECT  0 99.072 0.192 99.096 ;
    END
  END d[514]
  PIN d[515]
    DIRECTION INPUT ;
    USE SIGNAL ;
    PORT
      LAYER M4 ;
        RECT  0 99.264 0.192 99.288 ;
    END
  END d[515]
  PIN d[516]
    DIRECTION INPUT ;
    USE SIGNAL ;
    PORT
      LAYER M4 ;
        RECT  0 99.456 0.192 99.48 ;
    END
  END d[516]
  PIN d[517]
    DIRECTION INPUT ;
    USE SIGNAL ;
    PORT
      LAYER M4 ;
        RECT  0 99.648 0.192 99.672 ;
    END
  END d[517]
  PIN d[518]
    DIRECTION INPUT ;
    USE SIGNAL ;
    PORT
      LAYER M4 ;
        RECT  0 99.84 0.192 99.864 ;
    END
  END d[518]
  PIN d[519]
    DIRECTION INPUT ;
    USE SIGNAL ;
    PORT
      LAYER M4 ;
        RECT  0 100.032 0.192 100.056 ;
    END
  END d[519]
  PIN d[51]
    DIRECTION INPUT ;
    USE SIGNAL ;
    PORT
      LAYER M4 ;
        RECT  0 10.176 0.192 10.2 ;
    END
  END d[51]
  PIN d[520]
    DIRECTION INPUT ;
    USE SIGNAL ;
    PORT
      LAYER M4 ;
        RECT  0 100.224 0.192 100.248 ;
    END
  END d[520]
  PIN d[521]
    DIRECTION INPUT ;
    USE SIGNAL ;
    PORT
      LAYER M4 ;
        RECT  0 100.416 0.192 100.44 ;
    END
  END d[521]
  PIN d[522]
    DIRECTION INPUT ;
    USE SIGNAL ;
    PORT
      LAYER M4 ;
        RECT  0 100.608 0.192 100.632 ;
    END
  END d[522]
  PIN d[523]
    DIRECTION INPUT ;
    USE SIGNAL ;
    PORT
      LAYER M4 ;
        RECT  0 100.8 0.192 100.824 ;
    END
  END d[523]
  PIN d[524]
    DIRECTION INPUT ;
    USE SIGNAL ;
    PORT
      LAYER M4 ;
        RECT  0 100.992 0.192 101.016 ;
    END
  END d[524]
  PIN d[525]
    DIRECTION INPUT ;
    USE SIGNAL ;
    PORT
      LAYER M4 ;
        RECT  0 101.184 0.192 101.208 ;
    END
  END d[525]
  PIN d[526]
    DIRECTION INPUT ;
    USE SIGNAL ;
    PORT
      LAYER M4 ;
        RECT  0 101.376 0.192 101.4 ;
    END
  END d[526]
  PIN d[527]
    DIRECTION INPUT ;
    USE SIGNAL ;
    PORT
      LAYER M4 ;
        RECT  0 101.568 0.192 101.592 ;
    END
  END d[527]
  PIN d[528]
    DIRECTION INPUT ;
    USE SIGNAL ;
    PORT
      LAYER M4 ;
        RECT  0 101.76 0.192 101.784 ;
    END
  END d[528]
  PIN d[529]
    DIRECTION INPUT ;
    USE SIGNAL ;
    PORT
      LAYER M4 ;
        RECT  0 101.952 0.192 101.976 ;
    END
  END d[529]
  PIN d[52]
    DIRECTION INPUT ;
    USE SIGNAL ;
    PORT
      LAYER M4 ;
        RECT  0 10.368 0.192 10.392 ;
    END
  END d[52]
  PIN d[530]
    DIRECTION INPUT ;
    USE SIGNAL ;
    PORT
      LAYER M4 ;
        RECT  0 102.144 0.192 102.168 ;
    END
  END d[530]
  PIN d[531]
    DIRECTION INPUT ;
    USE SIGNAL ;
    PORT
      LAYER M4 ;
        RECT  0 102.336 0.192 102.36 ;
    END
  END d[531]
  PIN d[532]
    DIRECTION INPUT ;
    USE SIGNAL ;
    PORT
      LAYER M4 ;
        RECT  0 102.528 0.192 102.552 ;
    END
  END d[532]
  PIN d[533]
    DIRECTION INPUT ;
    USE SIGNAL ;
    PORT
      LAYER M4 ;
        RECT  0 102.72 0.192 102.744 ;
    END
  END d[533]
  PIN d[534]
    DIRECTION INPUT ;
    USE SIGNAL ;
    PORT
      LAYER M4 ;
        RECT  0 102.912 0.192 102.936 ;
    END
  END d[534]
  PIN d[535]
    DIRECTION INPUT ;
    USE SIGNAL ;
    PORT
      LAYER M4 ;
        RECT  0 103.104 0.192 103.128 ;
    END
  END d[535]
  PIN d[536]
    DIRECTION INPUT ;
    USE SIGNAL ;
    PORT
      LAYER M4 ;
        RECT  0 103.296 0.192 103.32 ;
    END
  END d[536]
  PIN d[537]
    DIRECTION INPUT ;
    USE SIGNAL ;
    PORT
      LAYER M4 ;
        RECT  0 103.488 0.192 103.512 ;
    END
  END d[537]
  PIN d[538]
    DIRECTION INPUT ;
    USE SIGNAL ;
    PORT
      LAYER M4 ;
        RECT  0 103.68 0.192 103.704 ;
    END
  END d[538]
  PIN d[539]
    DIRECTION INPUT ;
    USE SIGNAL ;
    PORT
      LAYER M4 ;
        RECT  0 103.872 0.192 103.896 ;
    END
  END d[539]
  PIN d[53]
    DIRECTION INPUT ;
    USE SIGNAL ;
    PORT
      LAYER M4 ;
        RECT  0 10.56 0.192 10.584 ;
    END
  END d[53]
  PIN d[540]
    DIRECTION INPUT ;
    USE SIGNAL ;
    PORT
      LAYER M4 ;
        RECT  0 104.064 0.192 104.088 ;
    END
  END d[540]
  PIN d[541]
    DIRECTION INPUT ;
    USE SIGNAL ;
    PORT
      LAYER M4 ;
        RECT  0 104.256 0.192 104.28 ;
    END
  END d[541]
  PIN d[542]
    DIRECTION INPUT ;
    USE SIGNAL ;
    PORT
      LAYER M4 ;
        RECT  0 104.448 0.192 104.472 ;
    END
  END d[542]
  PIN d[543]
    DIRECTION INPUT ;
    USE SIGNAL ;
    PORT
      LAYER M4 ;
        RECT  0 104.64 0.192 104.664 ;
    END
  END d[543]
  PIN d[54]
    DIRECTION INPUT ;
    USE SIGNAL ;
    PORT
      LAYER M4 ;
        RECT  0 10.752 0.192 10.776 ;
    END
  END d[54]
  PIN d[55]
    DIRECTION INPUT ;
    USE SIGNAL ;
    PORT
      LAYER M4 ;
        RECT  0 10.944 0.192 10.968 ;
    END
  END d[55]
  PIN d[56]
    DIRECTION INPUT ;
    USE SIGNAL ;
    PORT
      LAYER M4 ;
        RECT  0 11.136 0.192 11.16 ;
    END
  END d[56]
  PIN d[57]
    DIRECTION INPUT ;
    USE SIGNAL ;
    PORT
      LAYER M4 ;
        RECT  0 11.328 0.192 11.352 ;
    END
  END d[57]
  PIN d[58]
    DIRECTION INPUT ;
    USE SIGNAL ;
    PORT
      LAYER M4 ;
        RECT  0 11.52 0.192 11.544 ;
    END
  END d[58]
  PIN d[59]
    DIRECTION INPUT ;
    USE SIGNAL ;
    PORT
      LAYER M4 ;
        RECT  0 11.712 0.192 11.736 ;
    END
  END d[59]
  PIN d[5]
    DIRECTION INPUT ;
    USE SIGNAL ;
    PORT
      LAYER M4 ;
        RECT  0 1.344 0.192 1.368 ;
    END
  END d[5]
  PIN d[60]
    DIRECTION INPUT ;
    USE SIGNAL ;
    PORT
      LAYER M4 ;
        RECT  0 11.904 0.192 11.928 ;
    END
  END d[60]
  PIN d[61]
    DIRECTION INPUT ;
    USE SIGNAL ;
    PORT
      LAYER M4 ;
        RECT  0 12.096 0.192 12.12 ;
    END
  END d[61]
  PIN d[62]
    DIRECTION INPUT ;
    USE SIGNAL ;
    PORT
      LAYER M4 ;
        RECT  0 12.288 0.192 12.312 ;
    END
  END d[62]
  PIN d[63]
    DIRECTION INPUT ;
    USE SIGNAL ;
    PORT
      LAYER M4 ;
        RECT  0 12.48 0.192 12.504 ;
    END
  END d[63]
  PIN d[64]
    DIRECTION INPUT ;
    USE SIGNAL ;
    PORT
      LAYER M4 ;
        RECT  0 12.672 0.192 12.696 ;
    END
  END d[64]
  PIN d[65]
    DIRECTION INPUT ;
    USE SIGNAL ;
    PORT
      LAYER M4 ;
        RECT  0 12.864 0.192 12.888 ;
    END
  END d[65]
  PIN d[66]
    DIRECTION INPUT ;
    USE SIGNAL ;
    PORT
      LAYER M4 ;
        RECT  0 13.056 0.192 13.08 ;
    END
  END d[66]
  PIN d[67]
    DIRECTION INPUT ;
    USE SIGNAL ;
    PORT
      LAYER M4 ;
        RECT  0 13.248 0.192 13.272 ;
    END
  END d[67]
  PIN d[68]
    DIRECTION INPUT ;
    USE SIGNAL ;
    PORT
      LAYER M4 ;
        RECT  0 13.44 0.192 13.464 ;
    END
  END d[68]
  PIN d[69]
    DIRECTION INPUT ;
    USE SIGNAL ;
    PORT
      LAYER M4 ;
        RECT  0 13.632 0.192 13.656 ;
    END
  END d[69]
  PIN d[6]
    DIRECTION INPUT ;
    USE SIGNAL ;
    PORT
      LAYER M4 ;
        RECT  0 1.536 0.192 1.56 ;
    END
  END d[6]
  PIN d[70]
    DIRECTION INPUT ;
    USE SIGNAL ;
    PORT
      LAYER M4 ;
        RECT  0 13.824 0.192 13.848 ;
    END
  END d[70]
  PIN d[71]
    DIRECTION INPUT ;
    USE SIGNAL ;
    PORT
      LAYER M4 ;
        RECT  0 14.016 0.192 14.04 ;
    END
  END d[71]
  PIN d[72]
    DIRECTION INPUT ;
    USE SIGNAL ;
    PORT
      LAYER M4 ;
        RECT  0 14.208 0.192 14.232 ;
    END
  END d[72]
  PIN d[73]
    DIRECTION INPUT ;
    USE SIGNAL ;
    PORT
      LAYER M4 ;
        RECT  0 14.4 0.192 14.424 ;
    END
  END d[73]
  PIN d[74]
    DIRECTION INPUT ;
    USE SIGNAL ;
    PORT
      LAYER M4 ;
        RECT  0 14.592 0.192 14.616 ;
    END
  END d[74]
  PIN d[75]
    DIRECTION INPUT ;
    USE SIGNAL ;
    PORT
      LAYER M4 ;
        RECT  0 14.784 0.192 14.808 ;
    END
  END d[75]
  PIN d[76]
    DIRECTION INPUT ;
    USE SIGNAL ;
    PORT
      LAYER M4 ;
        RECT  0 14.976 0.192 15 ;
    END
  END d[76]
  PIN d[77]
    DIRECTION INPUT ;
    USE SIGNAL ;
    PORT
      LAYER M4 ;
        RECT  0 15.168 0.192 15.192 ;
    END
  END d[77]
  PIN d[78]
    DIRECTION INPUT ;
    USE SIGNAL ;
    PORT
      LAYER M4 ;
        RECT  0 15.36 0.192 15.384 ;
    END
  END d[78]
  PIN d[79]
    DIRECTION INPUT ;
    USE SIGNAL ;
    PORT
      LAYER M4 ;
        RECT  0 15.552 0.192 15.576 ;
    END
  END d[79]
  PIN d[7]
    DIRECTION INPUT ;
    USE SIGNAL ;
    PORT
      LAYER M4 ;
        RECT  0 1.728 0.192 1.752 ;
    END
  END d[7]
  PIN d[80]
    DIRECTION INPUT ;
    USE SIGNAL ;
    PORT
      LAYER M4 ;
        RECT  0 15.744 0.192 15.768 ;
    END
  END d[80]
  PIN d[81]
    DIRECTION INPUT ;
    USE SIGNAL ;
    PORT
      LAYER M4 ;
        RECT  0 15.936 0.192 15.96 ;
    END
  END d[81]
  PIN d[82]
    DIRECTION INPUT ;
    USE SIGNAL ;
    PORT
      LAYER M4 ;
        RECT  0 16.128 0.192 16.152 ;
    END
  END d[82]
  PIN d[83]
    DIRECTION INPUT ;
    USE SIGNAL ;
    PORT
      LAYER M4 ;
        RECT  0 16.32 0.192 16.344 ;
    END
  END d[83]
  PIN d[84]
    DIRECTION INPUT ;
    USE SIGNAL ;
    PORT
      LAYER M4 ;
        RECT  0 16.512 0.192 16.536 ;
    END
  END d[84]
  PIN d[85]
    DIRECTION INPUT ;
    USE SIGNAL ;
    PORT
      LAYER M4 ;
        RECT  0 16.704 0.192 16.728 ;
    END
  END d[85]
  PIN d[86]
    DIRECTION INPUT ;
    USE SIGNAL ;
    PORT
      LAYER M4 ;
        RECT  0 16.896 0.192 16.92 ;
    END
  END d[86]
  PIN d[87]
    DIRECTION INPUT ;
    USE SIGNAL ;
    PORT
      LAYER M4 ;
        RECT  0 17.088 0.192 17.112 ;
    END
  END d[87]
  PIN d[88]
    DIRECTION INPUT ;
    USE SIGNAL ;
    PORT
      LAYER M4 ;
        RECT  0 17.28 0.192 17.304 ;
    END
  END d[88]
  PIN d[89]
    DIRECTION INPUT ;
    USE SIGNAL ;
    PORT
      LAYER M4 ;
        RECT  0 17.472 0.192 17.496 ;
    END
  END d[89]
  PIN d[8]
    DIRECTION INPUT ;
    USE SIGNAL ;
    PORT
      LAYER M4 ;
        RECT  0 1.92 0.192 1.944 ;
    END
  END d[8]
  PIN d[90]
    DIRECTION INPUT ;
    USE SIGNAL ;
    PORT
      LAYER M4 ;
        RECT  0 17.664 0.192 17.688 ;
    END
  END d[90]
  PIN d[91]
    DIRECTION INPUT ;
    USE SIGNAL ;
    PORT
      LAYER M4 ;
        RECT  0 17.856 0.192 17.88 ;
    END
  END d[91]
  PIN d[92]
    DIRECTION INPUT ;
    USE SIGNAL ;
    PORT
      LAYER M4 ;
        RECT  0 18.048 0.192 18.072 ;
    END
  END d[92]
  PIN d[93]
    DIRECTION INPUT ;
    USE SIGNAL ;
    PORT
      LAYER M4 ;
        RECT  0 18.24 0.192 18.264 ;
    END
  END d[93]
  PIN d[94]
    DIRECTION INPUT ;
    USE SIGNAL ;
    PORT
      LAYER M4 ;
        RECT  0 18.432 0.192 18.456 ;
    END
  END d[94]
  PIN d[95]
    DIRECTION INPUT ;
    USE SIGNAL ;
    PORT
      LAYER M4 ;
        RECT  0 18.624 0.192 18.648 ;
    END
  END d[95]
  PIN d[96]
    DIRECTION INPUT ;
    USE SIGNAL ;
    PORT
      LAYER M4 ;
        RECT  0 18.816 0.192 18.84 ;
    END
  END d[96]
  PIN d[97]
    DIRECTION INPUT ;
    USE SIGNAL ;
    PORT
      LAYER M4 ;
        RECT  0 19.008 0.192 19.032 ;
    END
  END d[97]
  PIN d[98]
    DIRECTION INPUT ;
    USE SIGNAL ;
    PORT
      LAYER M4 ;
        RECT  0 19.2 0.192 19.224 ;
    END
  END d[98]
  PIN d[99]
    DIRECTION INPUT ;
    USE SIGNAL ;
    PORT
      LAYER M4 ;
        RECT  0 19.392 0.192 19.416 ;
    END
  END d[99]
  PIN d[9]
    DIRECTION INPUT ;
    USE SIGNAL ;
    PORT
      LAYER M4 ;
        RECT  0 2.112 0.192 2.136 ;
    END
  END d[9]
  PIN q[0]
    DIRECTION OUTPUT ;
    USE SIGNAL ;
    PORT
      LAYER M4 ;
        RECT  11.688 0.384 11.88 0.408 ;
    END
  END q[0]
  PIN q[100]
    DIRECTION OUTPUT ;
    USE SIGNAL ;
    PORT
      LAYER M4 ;
        RECT  11.688 19.584 11.88 19.608 ;
    END
  END q[100]
  PIN q[101]
    DIRECTION OUTPUT ;
    USE SIGNAL ;
    PORT
      LAYER M4 ;
        RECT  11.688 19.776 11.88 19.8 ;
    END
  END q[101]
  PIN q[102]
    DIRECTION OUTPUT ;
    USE SIGNAL ;
    PORT
      LAYER M4 ;
        RECT  11.688 19.968 11.88 19.992 ;
    END
  END q[102]
  PIN q[103]
    DIRECTION OUTPUT ;
    USE SIGNAL ;
    PORT
      LAYER M4 ;
        RECT  11.688 20.16 11.88 20.184 ;
    END
  END q[103]
  PIN q[104]
    DIRECTION OUTPUT ;
    USE SIGNAL ;
    PORT
      LAYER M4 ;
        RECT  11.688 20.352 11.88 20.376 ;
    END
  END q[104]
  PIN q[105]
    DIRECTION OUTPUT ;
    USE SIGNAL ;
    PORT
      LAYER M4 ;
        RECT  11.688 20.544 11.88 20.568 ;
    END
  END q[105]
  PIN q[106]
    DIRECTION OUTPUT ;
    USE SIGNAL ;
    PORT
      LAYER M4 ;
        RECT  11.688 20.736 11.88 20.76 ;
    END
  END q[106]
  PIN q[107]
    DIRECTION OUTPUT ;
    USE SIGNAL ;
    PORT
      LAYER M4 ;
        RECT  11.688 20.928 11.88 20.952 ;
    END
  END q[107]
  PIN q[108]
    DIRECTION OUTPUT ;
    USE SIGNAL ;
    PORT
      LAYER M4 ;
        RECT  11.688 21.12 11.88 21.144 ;
    END
  END q[108]
  PIN q[109]
    DIRECTION OUTPUT ;
    USE SIGNAL ;
    PORT
      LAYER M4 ;
        RECT  11.688 21.312 11.88 21.336 ;
    END
  END q[109]
  PIN q[10]
    DIRECTION OUTPUT ;
    USE SIGNAL ;
    PORT
      LAYER M4 ;
        RECT  11.688 2.304 11.88 2.328 ;
    END
  END q[10]
  PIN q[110]
    DIRECTION OUTPUT ;
    USE SIGNAL ;
    PORT
      LAYER M4 ;
        RECT  11.688 21.504 11.88 21.528 ;
    END
  END q[110]
  PIN q[111]
    DIRECTION OUTPUT ;
    USE SIGNAL ;
    PORT
      LAYER M4 ;
        RECT  11.688 21.696 11.88 21.72 ;
    END
  END q[111]
  PIN q[112]
    DIRECTION OUTPUT ;
    USE SIGNAL ;
    PORT
      LAYER M4 ;
        RECT  11.688 21.888 11.88 21.912 ;
    END
  END q[112]
  PIN q[113]
    DIRECTION OUTPUT ;
    USE SIGNAL ;
    PORT
      LAYER M4 ;
        RECT  11.688 22.08 11.88 22.104 ;
    END
  END q[113]
  PIN q[114]
    DIRECTION OUTPUT ;
    USE SIGNAL ;
    PORT
      LAYER M4 ;
        RECT  11.688 22.272 11.88 22.296 ;
    END
  END q[114]
  PIN q[115]
    DIRECTION OUTPUT ;
    USE SIGNAL ;
    PORT
      LAYER M4 ;
        RECT  11.688 22.464 11.88 22.488 ;
    END
  END q[115]
  PIN q[116]
    DIRECTION OUTPUT ;
    USE SIGNAL ;
    PORT
      LAYER M4 ;
        RECT  11.688 22.656 11.88 22.68 ;
    END
  END q[116]
  PIN q[117]
    DIRECTION OUTPUT ;
    USE SIGNAL ;
    PORT
      LAYER M4 ;
        RECT  11.688 22.848 11.88 22.872 ;
    END
  END q[117]
  PIN q[118]
    DIRECTION OUTPUT ;
    USE SIGNAL ;
    PORT
      LAYER M4 ;
        RECT  11.688 23.04 11.88 23.064 ;
    END
  END q[118]
  PIN q[119]
    DIRECTION OUTPUT ;
    USE SIGNAL ;
    PORT
      LAYER M4 ;
        RECT  11.688 23.232 11.88 23.256 ;
    END
  END q[119]
  PIN q[11]
    DIRECTION OUTPUT ;
    USE SIGNAL ;
    PORT
      LAYER M4 ;
        RECT  11.688 2.496 11.88 2.52 ;
    END
  END q[11]
  PIN q[120]
    DIRECTION OUTPUT ;
    USE SIGNAL ;
    PORT
      LAYER M4 ;
        RECT  11.688 23.424 11.88 23.448 ;
    END
  END q[120]
  PIN q[121]
    DIRECTION OUTPUT ;
    USE SIGNAL ;
    PORT
      LAYER M4 ;
        RECT  11.688 23.616 11.88 23.64 ;
    END
  END q[121]
  PIN q[122]
    DIRECTION OUTPUT ;
    USE SIGNAL ;
    PORT
      LAYER M4 ;
        RECT  11.688 23.808 11.88 23.832 ;
    END
  END q[122]
  PIN q[123]
    DIRECTION OUTPUT ;
    USE SIGNAL ;
    PORT
      LAYER M4 ;
        RECT  11.688 24 11.88 24.024 ;
    END
  END q[123]
  PIN q[124]
    DIRECTION OUTPUT ;
    USE SIGNAL ;
    PORT
      LAYER M4 ;
        RECT  11.688 24.192 11.88 24.216 ;
    END
  END q[124]
  PIN q[125]
    DIRECTION OUTPUT ;
    USE SIGNAL ;
    PORT
      LAYER M4 ;
        RECT  11.688 24.384 11.88 24.408 ;
    END
  END q[125]
  PIN q[126]
    DIRECTION OUTPUT ;
    USE SIGNAL ;
    PORT
      LAYER M4 ;
        RECT  11.688 24.576 11.88 24.6 ;
    END
  END q[126]
  PIN q[127]
    DIRECTION OUTPUT ;
    USE SIGNAL ;
    PORT
      LAYER M4 ;
        RECT  11.688 24.768 11.88 24.792 ;
    END
  END q[127]
  PIN q[128]
    DIRECTION OUTPUT ;
    USE SIGNAL ;
    PORT
      LAYER M4 ;
        RECT  11.688 24.96 11.88 24.984 ;
    END
  END q[128]
  PIN q[129]
    DIRECTION OUTPUT ;
    USE SIGNAL ;
    PORT
      LAYER M4 ;
        RECT  11.688 25.152 11.88 25.176 ;
    END
  END q[129]
  PIN q[12]
    DIRECTION OUTPUT ;
    USE SIGNAL ;
    PORT
      LAYER M4 ;
        RECT  11.688 2.688 11.88 2.712 ;
    END
  END q[12]
  PIN q[130]
    DIRECTION OUTPUT ;
    USE SIGNAL ;
    PORT
      LAYER M4 ;
        RECT  11.688 25.344 11.88 25.368 ;
    END
  END q[130]
  PIN q[131]
    DIRECTION OUTPUT ;
    USE SIGNAL ;
    PORT
      LAYER M4 ;
        RECT  11.688 25.536 11.88 25.56 ;
    END
  END q[131]
  PIN q[132]
    DIRECTION OUTPUT ;
    USE SIGNAL ;
    PORT
      LAYER M4 ;
        RECT  11.688 25.728 11.88 25.752 ;
    END
  END q[132]
  PIN q[133]
    DIRECTION OUTPUT ;
    USE SIGNAL ;
    PORT
      LAYER M4 ;
        RECT  11.688 25.92 11.88 25.944 ;
    END
  END q[133]
  PIN q[134]
    DIRECTION OUTPUT ;
    USE SIGNAL ;
    PORT
      LAYER M4 ;
        RECT  11.688 26.112 11.88 26.136 ;
    END
  END q[134]
  PIN q[135]
    DIRECTION OUTPUT ;
    USE SIGNAL ;
    PORT
      LAYER M4 ;
        RECT  11.688 26.304 11.88 26.328 ;
    END
  END q[135]
  PIN q[136]
    DIRECTION OUTPUT ;
    USE SIGNAL ;
    PORT
      LAYER M4 ;
        RECT  11.688 26.496 11.88 26.52 ;
    END
  END q[136]
  PIN q[137]
    DIRECTION OUTPUT ;
    USE SIGNAL ;
    PORT
      LAYER M4 ;
        RECT  11.688 26.688 11.88 26.712 ;
    END
  END q[137]
  PIN q[138]
    DIRECTION OUTPUT ;
    USE SIGNAL ;
    PORT
      LAYER M4 ;
        RECT  11.688 26.88 11.88 26.904 ;
    END
  END q[138]
  PIN q[139]
    DIRECTION OUTPUT ;
    USE SIGNAL ;
    PORT
      LAYER M4 ;
        RECT  11.688 27.072 11.88 27.096 ;
    END
  END q[139]
  PIN q[13]
    DIRECTION OUTPUT ;
    USE SIGNAL ;
    PORT
      LAYER M4 ;
        RECT  11.688 2.88 11.88 2.904 ;
    END
  END q[13]
  PIN q[140]
    DIRECTION OUTPUT ;
    USE SIGNAL ;
    PORT
      LAYER M4 ;
        RECT  11.688 27.264 11.88 27.288 ;
    END
  END q[140]
  PIN q[141]
    DIRECTION OUTPUT ;
    USE SIGNAL ;
    PORT
      LAYER M4 ;
        RECT  11.688 27.456 11.88 27.48 ;
    END
  END q[141]
  PIN q[142]
    DIRECTION OUTPUT ;
    USE SIGNAL ;
    PORT
      LAYER M4 ;
        RECT  11.688 27.648 11.88 27.672 ;
    END
  END q[142]
  PIN q[143]
    DIRECTION OUTPUT ;
    USE SIGNAL ;
    PORT
      LAYER M4 ;
        RECT  11.688 27.84 11.88 27.864 ;
    END
  END q[143]
  PIN q[144]
    DIRECTION OUTPUT ;
    USE SIGNAL ;
    PORT
      LAYER M4 ;
        RECT  11.688 28.032 11.88 28.056 ;
    END
  END q[144]
  PIN q[145]
    DIRECTION OUTPUT ;
    USE SIGNAL ;
    PORT
      LAYER M4 ;
        RECT  11.688 28.224 11.88 28.248 ;
    END
  END q[145]
  PIN q[146]
    DIRECTION OUTPUT ;
    USE SIGNAL ;
    PORT
      LAYER M4 ;
        RECT  11.688 28.416 11.88 28.44 ;
    END
  END q[146]
  PIN q[147]
    DIRECTION OUTPUT ;
    USE SIGNAL ;
    PORT
      LAYER M4 ;
        RECT  11.688 28.608 11.88 28.632 ;
    END
  END q[147]
  PIN q[148]
    DIRECTION OUTPUT ;
    USE SIGNAL ;
    PORT
      LAYER M4 ;
        RECT  11.688 28.8 11.88 28.824 ;
    END
  END q[148]
  PIN q[149]
    DIRECTION OUTPUT ;
    USE SIGNAL ;
    PORT
      LAYER M4 ;
        RECT  11.688 28.992 11.88 29.016 ;
    END
  END q[149]
  PIN q[14]
    DIRECTION OUTPUT ;
    USE SIGNAL ;
    PORT
      LAYER M4 ;
        RECT  11.688 3.072 11.88 3.096 ;
    END
  END q[14]
  PIN q[150]
    DIRECTION OUTPUT ;
    USE SIGNAL ;
    PORT
      LAYER M4 ;
        RECT  11.688 29.184 11.88 29.208 ;
    END
  END q[150]
  PIN q[151]
    DIRECTION OUTPUT ;
    USE SIGNAL ;
    PORT
      LAYER M4 ;
        RECT  11.688 29.376 11.88 29.4 ;
    END
  END q[151]
  PIN q[152]
    DIRECTION OUTPUT ;
    USE SIGNAL ;
    PORT
      LAYER M4 ;
        RECT  11.688 29.568 11.88 29.592 ;
    END
  END q[152]
  PIN q[153]
    DIRECTION OUTPUT ;
    USE SIGNAL ;
    PORT
      LAYER M4 ;
        RECT  11.688 29.76 11.88 29.784 ;
    END
  END q[153]
  PIN q[154]
    DIRECTION OUTPUT ;
    USE SIGNAL ;
    PORT
      LAYER M4 ;
        RECT  11.688 29.952 11.88 29.976 ;
    END
  END q[154]
  PIN q[155]
    DIRECTION OUTPUT ;
    USE SIGNAL ;
    PORT
      LAYER M4 ;
        RECT  11.688 30.144 11.88 30.168 ;
    END
  END q[155]
  PIN q[156]
    DIRECTION OUTPUT ;
    USE SIGNAL ;
    PORT
      LAYER M4 ;
        RECT  11.688 30.336 11.88 30.36 ;
    END
  END q[156]
  PIN q[157]
    DIRECTION OUTPUT ;
    USE SIGNAL ;
    PORT
      LAYER M4 ;
        RECT  11.688 30.528 11.88 30.552 ;
    END
  END q[157]
  PIN q[158]
    DIRECTION OUTPUT ;
    USE SIGNAL ;
    PORT
      LAYER M4 ;
        RECT  11.688 30.72 11.88 30.744 ;
    END
  END q[158]
  PIN q[159]
    DIRECTION OUTPUT ;
    USE SIGNAL ;
    PORT
      LAYER M4 ;
        RECT  11.688 30.912 11.88 30.936 ;
    END
  END q[159]
  PIN q[15]
    DIRECTION OUTPUT ;
    USE SIGNAL ;
    PORT
      LAYER M4 ;
        RECT  11.688 3.264 11.88 3.288 ;
    END
  END q[15]
  PIN q[160]
    DIRECTION OUTPUT ;
    USE SIGNAL ;
    PORT
      LAYER M4 ;
        RECT  11.688 31.104 11.88 31.128 ;
    END
  END q[160]
  PIN q[161]
    DIRECTION OUTPUT ;
    USE SIGNAL ;
    PORT
      LAYER M4 ;
        RECT  11.688 31.296 11.88 31.32 ;
    END
  END q[161]
  PIN q[162]
    DIRECTION OUTPUT ;
    USE SIGNAL ;
    PORT
      LAYER M4 ;
        RECT  11.688 31.488 11.88 31.512 ;
    END
  END q[162]
  PIN q[163]
    DIRECTION OUTPUT ;
    USE SIGNAL ;
    PORT
      LAYER M4 ;
        RECT  11.688 31.68 11.88 31.704 ;
    END
  END q[163]
  PIN q[164]
    DIRECTION OUTPUT ;
    USE SIGNAL ;
    PORT
      LAYER M4 ;
        RECT  11.688 31.872 11.88 31.896 ;
    END
  END q[164]
  PIN q[165]
    DIRECTION OUTPUT ;
    USE SIGNAL ;
    PORT
      LAYER M4 ;
        RECT  11.688 32.064 11.88 32.088 ;
    END
  END q[165]
  PIN q[166]
    DIRECTION OUTPUT ;
    USE SIGNAL ;
    PORT
      LAYER M4 ;
        RECT  11.688 32.256 11.88 32.28 ;
    END
  END q[166]
  PIN q[167]
    DIRECTION OUTPUT ;
    USE SIGNAL ;
    PORT
      LAYER M4 ;
        RECT  11.688 32.448 11.88 32.472 ;
    END
  END q[167]
  PIN q[168]
    DIRECTION OUTPUT ;
    USE SIGNAL ;
    PORT
      LAYER M4 ;
        RECT  11.688 32.64 11.88 32.664 ;
    END
  END q[168]
  PIN q[169]
    DIRECTION OUTPUT ;
    USE SIGNAL ;
    PORT
      LAYER M4 ;
        RECT  11.688 32.832 11.88 32.856 ;
    END
  END q[169]
  PIN q[16]
    DIRECTION OUTPUT ;
    USE SIGNAL ;
    PORT
      LAYER M4 ;
        RECT  11.688 3.456 11.88 3.48 ;
    END
  END q[16]
  PIN q[170]
    DIRECTION OUTPUT ;
    USE SIGNAL ;
    PORT
      LAYER M4 ;
        RECT  11.688 33.024 11.88 33.048 ;
    END
  END q[170]
  PIN q[171]
    DIRECTION OUTPUT ;
    USE SIGNAL ;
    PORT
      LAYER M4 ;
        RECT  11.688 33.216 11.88 33.24 ;
    END
  END q[171]
  PIN q[172]
    DIRECTION OUTPUT ;
    USE SIGNAL ;
    PORT
      LAYER M4 ;
        RECT  11.688 33.408 11.88 33.432 ;
    END
  END q[172]
  PIN q[173]
    DIRECTION OUTPUT ;
    USE SIGNAL ;
    PORT
      LAYER M4 ;
        RECT  11.688 33.6 11.88 33.624 ;
    END
  END q[173]
  PIN q[174]
    DIRECTION OUTPUT ;
    USE SIGNAL ;
    PORT
      LAYER M4 ;
        RECT  11.688 33.792 11.88 33.816 ;
    END
  END q[174]
  PIN q[175]
    DIRECTION OUTPUT ;
    USE SIGNAL ;
    PORT
      LAYER M4 ;
        RECT  11.688 33.984 11.88 34.008 ;
    END
  END q[175]
  PIN q[176]
    DIRECTION OUTPUT ;
    USE SIGNAL ;
    PORT
      LAYER M4 ;
        RECT  11.688 34.176 11.88 34.2 ;
    END
  END q[176]
  PIN q[177]
    DIRECTION OUTPUT ;
    USE SIGNAL ;
    PORT
      LAYER M4 ;
        RECT  11.688 34.368 11.88 34.392 ;
    END
  END q[177]
  PIN q[178]
    DIRECTION OUTPUT ;
    USE SIGNAL ;
    PORT
      LAYER M4 ;
        RECT  11.688 34.56 11.88 34.584 ;
    END
  END q[178]
  PIN q[179]
    DIRECTION OUTPUT ;
    USE SIGNAL ;
    PORT
      LAYER M4 ;
        RECT  11.688 34.752 11.88 34.776 ;
    END
  END q[179]
  PIN q[17]
    DIRECTION OUTPUT ;
    USE SIGNAL ;
    PORT
      LAYER M4 ;
        RECT  11.688 3.648 11.88 3.672 ;
    END
  END q[17]
  PIN q[180]
    DIRECTION OUTPUT ;
    USE SIGNAL ;
    PORT
      LAYER M4 ;
        RECT  11.688 34.944 11.88 34.968 ;
    END
  END q[180]
  PIN q[181]
    DIRECTION OUTPUT ;
    USE SIGNAL ;
    PORT
      LAYER M4 ;
        RECT  11.688 35.136 11.88 35.16 ;
    END
  END q[181]
  PIN q[182]
    DIRECTION OUTPUT ;
    USE SIGNAL ;
    PORT
      LAYER M4 ;
        RECT  11.688 35.328 11.88 35.352 ;
    END
  END q[182]
  PIN q[183]
    DIRECTION OUTPUT ;
    USE SIGNAL ;
    PORT
      LAYER M4 ;
        RECT  11.688 35.52 11.88 35.544 ;
    END
  END q[183]
  PIN q[184]
    DIRECTION OUTPUT ;
    USE SIGNAL ;
    PORT
      LAYER M4 ;
        RECT  11.688 35.712 11.88 35.736 ;
    END
  END q[184]
  PIN q[185]
    DIRECTION OUTPUT ;
    USE SIGNAL ;
    PORT
      LAYER M4 ;
        RECT  11.688 35.904 11.88 35.928 ;
    END
  END q[185]
  PIN q[186]
    DIRECTION OUTPUT ;
    USE SIGNAL ;
    PORT
      LAYER M4 ;
        RECT  11.688 36.096 11.88 36.12 ;
    END
  END q[186]
  PIN q[187]
    DIRECTION OUTPUT ;
    USE SIGNAL ;
    PORT
      LAYER M4 ;
        RECT  11.688 36.288 11.88 36.312 ;
    END
  END q[187]
  PIN q[188]
    DIRECTION OUTPUT ;
    USE SIGNAL ;
    PORT
      LAYER M4 ;
        RECT  11.688 36.48 11.88 36.504 ;
    END
  END q[188]
  PIN q[189]
    DIRECTION OUTPUT ;
    USE SIGNAL ;
    PORT
      LAYER M4 ;
        RECT  11.688 36.672 11.88 36.696 ;
    END
  END q[189]
  PIN q[18]
    DIRECTION OUTPUT ;
    USE SIGNAL ;
    PORT
      LAYER M4 ;
        RECT  11.688 3.84 11.88 3.864 ;
    END
  END q[18]
  PIN q[190]
    DIRECTION OUTPUT ;
    USE SIGNAL ;
    PORT
      LAYER M4 ;
        RECT  11.688 36.864 11.88 36.888 ;
    END
  END q[190]
  PIN q[191]
    DIRECTION OUTPUT ;
    USE SIGNAL ;
    PORT
      LAYER M4 ;
        RECT  11.688 37.056 11.88 37.08 ;
    END
  END q[191]
  PIN q[192]
    DIRECTION OUTPUT ;
    USE SIGNAL ;
    PORT
      LAYER M4 ;
        RECT  11.688 37.248 11.88 37.272 ;
    END
  END q[192]
  PIN q[193]
    DIRECTION OUTPUT ;
    USE SIGNAL ;
    PORT
      LAYER M4 ;
        RECT  11.688 37.44 11.88 37.464 ;
    END
  END q[193]
  PIN q[194]
    DIRECTION OUTPUT ;
    USE SIGNAL ;
    PORT
      LAYER M4 ;
        RECT  11.688 37.632 11.88 37.656 ;
    END
  END q[194]
  PIN q[195]
    DIRECTION OUTPUT ;
    USE SIGNAL ;
    PORT
      LAYER M4 ;
        RECT  11.688 37.824 11.88 37.848 ;
    END
  END q[195]
  PIN q[196]
    DIRECTION OUTPUT ;
    USE SIGNAL ;
    PORT
      LAYER M4 ;
        RECT  11.688 38.016 11.88 38.04 ;
    END
  END q[196]
  PIN q[197]
    DIRECTION OUTPUT ;
    USE SIGNAL ;
    PORT
      LAYER M4 ;
        RECT  11.688 38.208 11.88 38.232 ;
    END
  END q[197]
  PIN q[198]
    DIRECTION OUTPUT ;
    USE SIGNAL ;
    PORT
      LAYER M4 ;
        RECT  11.688 38.4 11.88 38.424 ;
    END
  END q[198]
  PIN q[199]
    DIRECTION OUTPUT ;
    USE SIGNAL ;
    PORT
      LAYER M4 ;
        RECT  11.688 38.592 11.88 38.616 ;
    END
  END q[199]
  PIN q[19]
    DIRECTION OUTPUT ;
    USE SIGNAL ;
    PORT
      LAYER M4 ;
        RECT  11.688 4.032 11.88 4.056 ;
    END
  END q[19]
  PIN q[1]
    DIRECTION OUTPUT ;
    USE SIGNAL ;
    PORT
      LAYER M4 ;
        RECT  11.688 0.576 11.88 0.6 ;
    END
  END q[1]
  PIN q[200]
    DIRECTION OUTPUT ;
    USE SIGNAL ;
    PORT
      LAYER M4 ;
        RECT  11.688 38.784 11.88 38.808 ;
    END
  END q[200]
  PIN q[201]
    DIRECTION OUTPUT ;
    USE SIGNAL ;
    PORT
      LAYER M4 ;
        RECT  11.688 38.976 11.88 39 ;
    END
  END q[201]
  PIN q[202]
    DIRECTION OUTPUT ;
    USE SIGNAL ;
    PORT
      LAYER M4 ;
        RECT  11.688 39.168 11.88 39.192 ;
    END
  END q[202]
  PIN q[203]
    DIRECTION OUTPUT ;
    USE SIGNAL ;
    PORT
      LAYER M4 ;
        RECT  11.688 39.36 11.88 39.384 ;
    END
  END q[203]
  PIN q[204]
    DIRECTION OUTPUT ;
    USE SIGNAL ;
    PORT
      LAYER M4 ;
        RECT  11.688 39.552 11.88 39.576 ;
    END
  END q[204]
  PIN q[205]
    DIRECTION OUTPUT ;
    USE SIGNAL ;
    PORT
      LAYER M4 ;
        RECT  11.688 39.744 11.88 39.768 ;
    END
  END q[205]
  PIN q[206]
    DIRECTION OUTPUT ;
    USE SIGNAL ;
    PORT
      LAYER M4 ;
        RECT  11.688 39.936 11.88 39.96 ;
    END
  END q[206]
  PIN q[207]
    DIRECTION OUTPUT ;
    USE SIGNAL ;
    PORT
      LAYER M4 ;
        RECT  11.688 40.128 11.88 40.152 ;
    END
  END q[207]
  PIN q[208]
    DIRECTION OUTPUT ;
    USE SIGNAL ;
    PORT
      LAYER M4 ;
        RECT  11.688 40.32 11.88 40.344 ;
    END
  END q[208]
  PIN q[209]
    DIRECTION OUTPUT ;
    USE SIGNAL ;
    PORT
      LAYER M4 ;
        RECT  11.688 40.512 11.88 40.536 ;
    END
  END q[209]
  PIN q[20]
    DIRECTION OUTPUT ;
    USE SIGNAL ;
    PORT
      LAYER M4 ;
        RECT  11.688 4.224 11.88 4.248 ;
    END
  END q[20]
  PIN q[210]
    DIRECTION OUTPUT ;
    USE SIGNAL ;
    PORT
      LAYER M4 ;
        RECT  11.688 40.704 11.88 40.728 ;
    END
  END q[210]
  PIN q[211]
    DIRECTION OUTPUT ;
    USE SIGNAL ;
    PORT
      LAYER M4 ;
        RECT  11.688 40.896 11.88 40.92 ;
    END
  END q[211]
  PIN q[212]
    DIRECTION OUTPUT ;
    USE SIGNAL ;
    PORT
      LAYER M4 ;
        RECT  11.688 41.088 11.88 41.112 ;
    END
  END q[212]
  PIN q[213]
    DIRECTION OUTPUT ;
    USE SIGNAL ;
    PORT
      LAYER M4 ;
        RECT  11.688 41.28 11.88 41.304 ;
    END
  END q[213]
  PIN q[214]
    DIRECTION OUTPUT ;
    USE SIGNAL ;
    PORT
      LAYER M4 ;
        RECT  11.688 41.472 11.88 41.496 ;
    END
  END q[214]
  PIN q[215]
    DIRECTION OUTPUT ;
    USE SIGNAL ;
    PORT
      LAYER M4 ;
        RECT  11.688 41.664 11.88 41.688 ;
    END
  END q[215]
  PIN q[216]
    DIRECTION OUTPUT ;
    USE SIGNAL ;
    PORT
      LAYER M4 ;
        RECT  11.688 41.856 11.88 41.88 ;
    END
  END q[216]
  PIN q[217]
    DIRECTION OUTPUT ;
    USE SIGNAL ;
    PORT
      LAYER M4 ;
        RECT  11.688 42.048 11.88 42.072 ;
    END
  END q[217]
  PIN q[218]
    DIRECTION OUTPUT ;
    USE SIGNAL ;
    PORT
      LAYER M4 ;
        RECT  11.688 42.24 11.88 42.264 ;
    END
  END q[218]
  PIN q[219]
    DIRECTION OUTPUT ;
    USE SIGNAL ;
    PORT
      LAYER M4 ;
        RECT  11.688 42.432 11.88 42.456 ;
    END
  END q[219]
  PIN q[21]
    DIRECTION OUTPUT ;
    USE SIGNAL ;
    PORT
      LAYER M4 ;
        RECT  11.688 4.416 11.88 4.44 ;
    END
  END q[21]
  PIN q[220]
    DIRECTION OUTPUT ;
    USE SIGNAL ;
    PORT
      LAYER M4 ;
        RECT  11.688 42.624 11.88 42.648 ;
    END
  END q[220]
  PIN q[221]
    DIRECTION OUTPUT ;
    USE SIGNAL ;
    PORT
      LAYER M4 ;
        RECT  11.688 42.816 11.88 42.84 ;
    END
  END q[221]
  PIN q[222]
    DIRECTION OUTPUT ;
    USE SIGNAL ;
    PORT
      LAYER M4 ;
        RECT  11.688 43.008 11.88 43.032 ;
    END
  END q[222]
  PIN q[223]
    DIRECTION OUTPUT ;
    USE SIGNAL ;
    PORT
      LAYER M4 ;
        RECT  11.688 43.2 11.88 43.224 ;
    END
  END q[223]
  PIN q[224]
    DIRECTION OUTPUT ;
    USE SIGNAL ;
    PORT
      LAYER M4 ;
        RECT  11.688 43.392 11.88 43.416 ;
    END
  END q[224]
  PIN q[225]
    DIRECTION OUTPUT ;
    USE SIGNAL ;
    PORT
      LAYER M4 ;
        RECT  11.688 43.584 11.88 43.608 ;
    END
  END q[225]
  PIN q[226]
    DIRECTION OUTPUT ;
    USE SIGNAL ;
    PORT
      LAYER M4 ;
        RECT  11.688 43.776 11.88 43.8 ;
    END
  END q[226]
  PIN q[227]
    DIRECTION OUTPUT ;
    USE SIGNAL ;
    PORT
      LAYER M4 ;
        RECT  11.688 43.968 11.88 43.992 ;
    END
  END q[227]
  PIN q[228]
    DIRECTION OUTPUT ;
    USE SIGNAL ;
    PORT
      LAYER M4 ;
        RECT  11.688 44.16 11.88 44.184 ;
    END
  END q[228]
  PIN q[229]
    DIRECTION OUTPUT ;
    USE SIGNAL ;
    PORT
      LAYER M4 ;
        RECT  11.688 44.352 11.88 44.376 ;
    END
  END q[229]
  PIN q[22]
    DIRECTION OUTPUT ;
    USE SIGNAL ;
    PORT
      LAYER M4 ;
        RECT  11.688 4.608 11.88 4.632 ;
    END
  END q[22]
  PIN q[230]
    DIRECTION OUTPUT ;
    USE SIGNAL ;
    PORT
      LAYER M4 ;
        RECT  11.688 44.544 11.88 44.568 ;
    END
  END q[230]
  PIN q[231]
    DIRECTION OUTPUT ;
    USE SIGNAL ;
    PORT
      LAYER M4 ;
        RECT  11.688 44.736 11.88 44.76 ;
    END
  END q[231]
  PIN q[232]
    DIRECTION OUTPUT ;
    USE SIGNAL ;
    PORT
      LAYER M4 ;
        RECT  11.688 44.928 11.88 44.952 ;
    END
  END q[232]
  PIN q[233]
    DIRECTION OUTPUT ;
    USE SIGNAL ;
    PORT
      LAYER M4 ;
        RECT  11.688 45.12 11.88 45.144 ;
    END
  END q[233]
  PIN q[234]
    DIRECTION OUTPUT ;
    USE SIGNAL ;
    PORT
      LAYER M4 ;
        RECT  11.688 45.312 11.88 45.336 ;
    END
  END q[234]
  PIN q[235]
    DIRECTION OUTPUT ;
    USE SIGNAL ;
    PORT
      LAYER M4 ;
        RECT  11.688 45.504 11.88 45.528 ;
    END
  END q[235]
  PIN q[236]
    DIRECTION OUTPUT ;
    USE SIGNAL ;
    PORT
      LAYER M4 ;
        RECT  11.688 45.696 11.88 45.72 ;
    END
  END q[236]
  PIN q[237]
    DIRECTION OUTPUT ;
    USE SIGNAL ;
    PORT
      LAYER M4 ;
        RECT  11.688 45.888 11.88 45.912 ;
    END
  END q[237]
  PIN q[238]
    DIRECTION OUTPUT ;
    USE SIGNAL ;
    PORT
      LAYER M4 ;
        RECT  11.688 46.08 11.88 46.104 ;
    END
  END q[238]
  PIN q[239]
    DIRECTION OUTPUT ;
    USE SIGNAL ;
    PORT
      LAYER M4 ;
        RECT  11.688 46.272 11.88 46.296 ;
    END
  END q[239]
  PIN q[23]
    DIRECTION OUTPUT ;
    USE SIGNAL ;
    PORT
      LAYER M4 ;
        RECT  11.688 4.8 11.88 4.824 ;
    END
  END q[23]
  PIN q[240]
    DIRECTION OUTPUT ;
    USE SIGNAL ;
    PORT
      LAYER M4 ;
        RECT  11.688 46.464 11.88 46.488 ;
    END
  END q[240]
  PIN q[241]
    DIRECTION OUTPUT ;
    USE SIGNAL ;
    PORT
      LAYER M4 ;
        RECT  11.688 46.656 11.88 46.68 ;
    END
  END q[241]
  PIN q[242]
    DIRECTION OUTPUT ;
    USE SIGNAL ;
    PORT
      LAYER M4 ;
        RECT  11.688 46.848 11.88 46.872 ;
    END
  END q[242]
  PIN q[243]
    DIRECTION OUTPUT ;
    USE SIGNAL ;
    PORT
      LAYER M4 ;
        RECT  11.688 47.04 11.88 47.064 ;
    END
  END q[243]
  PIN q[244]
    DIRECTION OUTPUT ;
    USE SIGNAL ;
    PORT
      LAYER M4 ;
        RECT  11.688 47.232 11.88 47.256 ;
    END
  END q[244]
  PIN q[245]
    DIRECTION OUTPUT ;
    USE SIGNAL ;
    PORT
      LAYER M4 ;
        RECT  11.688 47.424 11.88 47.448 ;
    END
  END q[245]
  PIN q[246]
    DIRECTION OUTPUT ;
    USE SIGNAL ;
    PORT
      LAYER M4 ;
        RECT  11.688 47.616 11.88 47.64 ;
    END
  END q[246]
  PIN q[247]
    DIRECTION OUTPUT ;
    USE SIGNAL ;
    PORT
      LAYER M4 ;
        RECT  11.688 47.808 11.88 47.832 ;
    END
  END q[247]
  PIN q[248]
    DIRECTION OUTPUT ;
    USE SIGNAL ;
    PORT
      LAYER M4 ;
        RECT  11.688 48 11.88 48.024 ;
    END
  END q[248]
  PIN q[249]
    DIRECTION OUTPUT ;
    USE SIGNAL ;
    PORT
      LAYER M4 ;
        RECT  11.688 48.192 11.88 48.216 ;
    END
  END q[249]
  PIN q[24]
    DIRECTION OUTPUT ;
    USE SIGNAL ;
    PORT
      LAYER M4 ;
        RECT  11.688 4.992 11.88 5.016 ;
    END
  END q[24]
  PIN q[250]
    DIRECTION OUTPUT ;
    USE SIGNAL ;
    PORT
      LAYER M4 ;
        RECT  11.688 48.384 11.88 48.408 ;
    END
  END q[250]
  PIN q[251]
    DIRECTION OUTPUT ;
    USE SIGNAL ;
    PORT
      LAYER M4 ;
        RECT  11.688 48.576 11.88 48.6 ;
    END
  END q[251]
  PIN q[252]
    DIRECTION OUTPUT ;
    USE SIGNAL ;
    PORT
      LAYER M4 ;
        RECT  11.688 48.768 11.88 48.792 ;
    END
  END q[252]
  PIN q[253]
    DIRECTION OUTPUT ;
    USE SIGNAL ;
    PORT
      LAYER M4 ;
        RECT  11.688 48.96 11.88 48.984 ;
    END
  END q[253]
  PIN q[254]
    DIRECTION OUTPUT ;
    USE SIGNAL ;
    PORT
      LAYER M4 ;
        RECT  11.688 49.152 11.88 49.176 ;
    END
  END q[254]
  PIN q[255]
    DIRECTION OUTPUT ;
    USE SIGNAL ;
    PORT
      LAYER M4 ;
        RECT  11.688 49.344 11.88 49.368 ;
    END
  END q[255]
  PIN q[256]
    DIRECTION OUTPUT ;
    USE SIGNAL ;
    PORT
      LAYER M4 ;
        RECT  11.688 49.536 11.88 49.56 ;
    END
  END q[256]
  PIN q[257]
    DIRECTION OUTPUT ;
    USE SIGNAL ;
    PORT
      LAYER M4 ;
        RECT  11.688 49.728 11.88 49.752 ;
    END
  END q[257]
  PIN q[258]
    DIRECTION OUTPUT ;
    USE SIGNAL ;
    PORT
      LAYER M4 ;
        RECT  11.688 49.92 11.88 49.944 ;
    END
  END q[258]
  PIN q[259]
    DIRECTION OUTPUT ;
    USE SIGNAL ;
    PORT
      LAYER M4 ;
        RECT  11.688 50.112 11.88 50.136 ;
    END
  END q[259]
  PIN q[25]
    DIRECTION OUTPUT ;
    USE SIGNAL ;
    PORT
      LAYER M4 ;
        RECT  11.688 5.184 11.88 5.208 ;
    END
  END q[25]
  PIN q[260]
    DIRECTION OUTPUT ;
    USE SIGNAL ;
    PORT
      LAYER M4 ;
        RECT  11.688 50.304 11.88 50.328 ;
    END
  END q[260]
  PIN q[261]
    DIRECTION OUTPUT ;
    USE SIGNAL ;
    PORT
      LAYER M4 ;
        RECT  11.688 50.496 11.88 50.52 ;
    END
  END q[261]
  PIN q[262]
    DIRECTION OUTPUT ;
    USE SIGNAL ;
    PORT
      LAYER M4 ;
        RECT  11.688 50.688 11.88 50.712 ;
    END
  END q[262]
  PIN q[263]
    DIRECTION OUTPUT ;
    USE SIGNAL ;
    PORT
      LAYER M4 ;
        RECT  11.688 50.88 11.88 50.904 ;
    END
  END q[263]
  PIN q[264]
    DIRECTION OUTPUT ;
    USE SIGNAL ;
    PORT
      LAYER M4 ;
        RECT  11.688 51.072 11.88 51.096 ;
    END
  END q[264]
  PIN q[265]
    DIRECTION OUTPUT ;
    USE SIGNAL ;
    PORT
      LAYER M4 ;
        RECT  11.688 51.264 11.88 51.288 ;
    END
  END q[265]
  PIN q[266]
    DIRECTION OUTPUT ;
    USE SIGNAL ;
    PORT
      LAYER M4 ;
        RECT  11.688 51.456 11.88 51.48 ;
    END
  END q[266]
  PIN q[267]
    DIRECTION OUTPUT ;
    USE SIGNAL ;
    PORT
      LAYER M4 ;
        RECT  11.688 51.648 11.88 51.672 ;
    END
  END q[267]
  PIN q[268]
    DIRECTION OUTPUT ;
    USE SIGNAL ;
    PORT
      LAYER M4 ;
        RECT  11.688 51.84 11.88 51.864 ;
    END
  END q[268]
  PIN q[269]
    DIRECTION OUTPUT ;
    USE SIGNAL ;
    PORT
      LAYER M4 ;
        RECT  11.688 52.032 11.88 52.056 ;
    END
  END q[269]
  PIN q[26]
    DIRECTION OUTPUT ;
    USE SIGNAL ;
    PORT
      LAYER M4 ;
        RECT  11.688 5.376 11.88 5.4 ;
    END
  END q[26]
  PIN q[270]
    DIRECTION OUTPUT ;
    USE SIGNAL ;
    PORT
      LAYER M4 ;
        RECT  11.688 52.224 11.88 52.248 ;
    END
  END q[270]
  PIN q[271]
    DIRECTION OUTPUT ;
    USE SIGNAL ;
    PORT
      LAYER M4 ;
        RECT  11.688 52.416 11.88 52.44 ;
    END
  END q[271]
  PIN q[272]
    DIRECTION OUTPUT ;
    USE SIGNAL ;
    PORT
      LAYER M4 ;
        RECT  11.688 52.608 11.88 52.632 ;
    END
  END q[272]
  PIN q[273]
    DIRECTION OUTPUT ;
    USE SIGNAL ;
    PORT
      LAYER M4 ;
        RECT  11.688 52.8 11.88 52.824 ;
    END
  END q[273]
  PIN q[274]
    DIRECTION OUTPUT ;
    USE SIGNAL ;
    PORT
      LAYER M4 ;
        RECT  11.688 52.992 11.88 53.016 ;
    END
  END q[274]
  PIN q[275]
    DIRECTION OUTPUT ;
    USE SIGNAL ;
    PORT
      LAYER M4 ;
        RECT  11.688 53.184 11.88 53.208 ;
    END
  END q[275]
  PIN q[276]
    DIRECTION OUTPUT ;
    USE SIGNAL ;
    PORT
      LAYER M4 ;
        RECT  11.688 53.376 11.88 53.4 ;
    END
  END q[276]
  PIN q[277]
    DIRECTION OUTPUT ;
    USE SIGNAL ;
    PORT
      LAYER M4 ;
        RECT  11.688 53.568 11.88 53.592 ;
    END
  END q[277]
  PIN q[278]
    DIRECTION OUTPUT ;
    USE SIGNAL ;
    PORT
      LAYER M4 ;
        RECT  11.688 53.76 11.88 53.784 ;
    END
  END q[278]
  PIN q[279]
    DIRECTION OUTPUT ;
    USE SIGNAL ;
    PORT
      LAYER M4 ;
        RECT  11.688 53.952 11.88 53.976 ;
    END
  END q[279]
  PIN q[27]
    DIRECTION OUTPUT ;
    USE SIGNAL ;
    PORT
      LAYER M4 ;
        RECT  11.688 5.568 11.88 5.592 ;
    END
  END q[27]
  PIN q[280]
    DIRECTION OUTPUT ;
    USE SIGNAL ;
    PORT
      LAYER M4 ;
        RECT  11.688 54.144 11.88 54.168 ;
    END
  END q[280]
  PIN q[281]
    DIRECTION OUTPUT ;
    USE SIGNAL ;
    PORT
      LAYER M4 ;
        RECT  11.688 54.336 11.88 54.36 ;
    END
  END q[281]
  PIN q[282]
    DIRECTION OUTPUT ;
    USE SIGNAL ;
    PORT
      LAYER M4 ;
        RECT  11.688 54.528 11.88 54.552 ;
    END
  END q[282]
  PIN q[283]
    DIRECTION OUTPUT ;
    USE SIGNAL ;
    PORT
      LAYER M4 ;
        RECT  11.688 54.72 11.88 54.744 ;
    END
  END q[283]
  PIN q[284]
    DIRECTION OUTPUT ;
    USE SIGNAL ;
    PORT
      LAYER M4 ;
        RECT  11.688 54.912 11.88 54.936 ;
    END
  END q[284]
  PIN q[285]
    DIRECTION OUTPUT ;
    USE SIGNAL ;
    PORT
      LAYER M4 ;
        RECT  11.688 55.104 11.88 55.128 ;
    END
  END q[285]
  PIN q[286]
    DIRECTION OUTPUT ;
    USE SIGNAL ;
    PORT
      LAYER M4 ;
        RECT  11.688 55.296 11.88 55.32 ;
    END
  END q[286]
  PIN q[287]
    DIRECTION OUTPUT ;
    USE SIGNAL ;
    PORT
      LAYER M4 ;
        RECT  11.688 55.488 11.88 55.512 ;
    END
  END q[287]
  PIN q[288]
    DIRECTION OUTPUT ;
    USE SIGNAL ;
    PORT
      LAYER M4 ;
        RECT  11.688 55.68 11.88 55.704 ;
    END
  END q[288]
  PIN q[289]
    DIRECTION OUTPUT ;
    USE SIGNAL ;
    PORT
      LAYER M4 ;
        RECT  11.688 55.872 11.88 55.896 ;
    END
  END q[289]
  PIN q[28]
    DIRECTION OUTPUT ;
    USE SIGNAL ;
    PORT
      LAYER M4 ;
        RECT  11.688 5.76 11.88 5.784 ;
    END
  END q[28]
  PIN q[290]
    DIRECTION OUTPUT ;
    USE SIGNAL ;
    PORT
      LAYER M4 ;
        RECT  11.688 56.064 11.88 56.088 ;
    END
  END q[290]
  PIN q[291]
    DIRECTION OUTPUT ;
    USE SIGNAL ;
    PORT
      LAYER M4 ;
        RECT  11.688 56.256 11.88 56.28 ;
    END
  END q[291]
  PIN q[292]
    DIRECTION OUTPUT ;
    USE SIGNAL ;
    PORT
      LAYER M4 ;
        RECT  11.688 56.448 11.88 56.472 ;
    END
  END q[292]
  PIN q[293]
    DIRECTION OUTPUT ;
    USE SIGNAL ;
    PORT
      LAYER M4 ;
        RECT  11.688 56.64 11.88 56.664 ;
    END
  END q[293]
  PIN q[294]
    DIRECTION OUTPUT ;
    USE SIGNAL ;
    PORT
      LAYER M4 ;
        RECT  11.688 56.832 11.88 56.856 ;
    END
  END q[294]
  PIN q[295]
    DIRECTION OUTPUT ;
    USE SIGNAL ;
    PORT
      LAYER M4 ;
        RECT  11.688 57.024 11.88 57.048 ;
    END
  END q[295]
  PIN q[296]
    DIRECTION OUTPUT ;
    USE SIGNAL ;
    PORT
      LAYER M4 ;
        RECT  11.688 57.216 11.88 57.24 ;
    END
  END q[296]
  PIN q[297]
    DIRECTION OUTPUT ;
    USE SIGNAL ;
    PORT
      LAYER M4 ;
        RECT  11.688 57.408 11.88 57.432 ;
    END
  END q[297]
  PIN q[298]
    DIRECTION OUTPUT ;
    USE SIGNAL ;
    PORT
      LAYER M4 ;
        RECT  11.688 57.6 11.88 57.624 ;
    END
  END q[298]
  PIN q[299]
    DIRECTION OUTPUT ;
    USE SIGNAL ;
    PORT
      LAYER M4 ;
        RECT  11.688 57.792 11.88 57.816 ;
    END
  END q[299]
  PIN q[29]
    DIRECTION OUTPUT ;
    USE SIGNAL ;
    PORT
      LAYER M4 ;
        RECT  11.688 5.952 11.88 5.976 ;
    END
  END q[29]
  PIN q[2]
    DIRECTION OUTPUT ;
    USE SIGNAL ;
    PORT
      LAYER M4 ;
        RECT  11.688 0.768 11.88 0.792 ;
    END
  END q[2]
  PIN q[300]
    DIRECTION OUTPUT ;
    USE SIGNAL ;
    PORT
      LAYER M4 ;
        RECT  11.688 57.984 11.88 58.008 ;
    END
  END q[300]
  PIN q[301]
    DIRECTION OUTPUT ;
    USE SIGNAL ;
    PORT
      LAYER M4 ;
        RECT  11.688 58.176 11.88 58.2 ;
    END
  END q[301]
  PIN q[302]
    DIRECTION OUTPUT ;
    USE SIGNAL ;
    PORT
      LAYER M4 ;
        RECT  11.688 58.368 11.88 58.392 ;
    END
  END q[302]
  PIN q[303]
    DIRECTION OUTPUT ;
    USE SIGNAL ;
    PORT
      LAYER M4 ;
        RECT  11.688 58.56 11.88 58.584 ;
    END
  END q[303]
  PIN q[304]
    DIRECTION OUTPUT ;
    USE SIGNAL ;
    PORT
      LAYER M4 ;
        RECT  11.688 58.752 11.88 58.776 ;
    END
  END q[304]
  PIN q[305]
    DIRECTION OUTPUT ;
    USE SIGNAL ;
    PORT
      LAYER M4 ;
        RECT  11.688 58.944 11.88 58.968 ;
    END
  END q[305]
  PIN q[306]
    DIRECTION OUTPUT ;
    USE SIGNAL ;
    PORT
      LAYER M4 ;
        RECT  11.688 59.136 11.88 59.16 ;
    END
  END q[306]
  PIN q[307]
    DIRECTION OUTPUT ;
    USE SIGNAL ;
    PORT
      LAYER M4 ;
        RECT  11.688 59.328 11.88 59.352 ;
    END
  END q[307]
  PIN q[308]
    DIRECTION OUTPUT ;
    USE SIGNAL ;
    PORT
      LAYER M4 ;
        RECT  11.688 59.52 11.88 59.544 ;
    END
  END q[308]
  PIN q[309]
    DIRECTION OUTPUT ;
    USE SIGNAL ;
    PORT
      LAYER M4 ;
        RECT  11.688 59.712 11.88 59.736 ;
    END
  END q[309]
  PIN q[30]
    DIRECTION OUTPUT ;
    USE SIGNAL ;
    PORT
      LAYER M4 ;
        RECT  11.688 6.144 11.88 6.168 ;
    END
  END q[30]
  PIN q[310]
    DIRECTION OUTPUT ;
    USE SIGNAL ;
    PORT
      LAYER M4 ;
        RECT  11.688 59.904 11.88 59.928 ;
    END
  END q[310]
  PIN q[311]
    DIRECTION OUTPUT ;
    USE SIGNAL ;
    PORT
      LAYER M4 ;
        RECT  11.688 60.096 11.88 60.12 ;
    END
  END q[311]
  PIN q[312]
    DIRECTION OUTPUT ;
    USE SIGNAL ;
    PORT
      LAYER M4 ;
        RECT  11.688 60.288 11.88 60.312 ;
    END
  END q[312]
  PIN q[313]
    DIRECTION OUTPUT ;
    USE SIGNAL ;
    PORT
      LAYER M4 ;
        RECT  11.688 60.48 11.88 60.504 ;
    END
  END q[313]
  PIN q[314]
    DIRECTION OUTPUT ;
    USE SIGNAL ;
    PORT
      LAYER M4 ;
        RECT  11.688 60.672 11.88 60.696 ;
    END
  END q[314]
  PIN q[315]
    DIRECTION OUTPUT ;
    USE SIGNAL ;
    PORT
      LAYER M4 ;
        RECT  11.688 60.864 11.88 60.888 ;
    END
  END q[315]
  PIN q[316]
    DIRECTION OUTPUT ;
    USE SIGNAL ;
    PORT
      LAYER M4 ;
        RECT  11.688 61.056 11.88 61.08 ;
    END
  END q[316]
  PIN q[317]
    DIRECTION OUTPUT ;
    USE SIGNAL ;
    PORT
      LAYER M4 ;
        RECT  11.688 61.248 11.88 61.272 ;
    END
  END q[317]
  PIN q[318]
    DIRECTION OUTPUT ;
    USE SIGNAL ;
    PORT
      LAYER M4 ;
        RECT  11.688 61.44 11.88 61.464 ;
    END
  END q[318]
  PIN q[319]
    DIRECTION OUTPUT ;
    USE SIGNAL ;
    PORT
      LAYER M4 ;
        RECT  11.688 61.632 11.88 61.656 ;
    END
  END q[319]
  PIN q[31]
    DIRECTION OUTPUT ;
    USE SIGNAL ;
    PORT
      LAYER M4 ;
        RECT  11.688 6.336 11.88 6.36 ;
    END
  END q[31]
  PIN q[320]
    DIRECTION OUTPUT ;
    USE SIGNAL ;
    PORT
      LAYER M4 ;
        RECT  11.688 61.824 11.88 61.848 ;
    END
  END q[320]
  PIN q[321]
    DIRECTION OUTPUT ;
    USE SIGNAL ;
    PORT
      LAYER M4 ;
        RECT  11.688 62.016 11.88 62.04 ;
    END
  END q[321]
  PIN q[322]
    DIRECTION OUTPUT ;
    USE SIGNAL ;
    PORT
      LAYER M4 ;
        RECT  11.688 62.208 11.88 62.232 ;
    END
  END q[322]
  PIN q[323]
    DIRECTION OUTPUT ;
    USE SIGNAL ;
    PORT
      LAYER M4 ;
        RECT  11.688 62.4 11.88 62.424 ;
    END
  END q[323]
  PIN q[324]
    DIRECTION OUTPUT ;
    USE SIGNAL ;
    PORT
      LAYER M4 ;
        RECT  11.688 62.592 11.88 62.616 ;
    END
  END q[324]
  PIN q[325]
    DIRECTION OUTPUT ;
    USE SIGNAL ;
    PORT
      LAYER M4 ;
        RECT  11.688 62.784 11.88 62.808 ;
    END
  END q[325]
  PIN q[326]
    DIRECTION OUTPUT ;
    USE SIGNAL ;
    PORT
      LAYER M4 ;
        RECT  11.688 62.976 11.88 63 ;
    END
  END q[326]
  PIN q[327]
    DIRECTION OUTPUT ;
    USE SIGNAL ;
    PORT
      LAYER M4 ;
        RECT  11.688 63.168 11.88 63.192 ;
    END
  END q[327]
  PIN q[328]
    DIRECTION OUTPUT ;
    USE SIGNAL ;
    PORT
      LAYER M4 ;
        RECT  11.688 63.36 11.88 63.384 ;
    END
  END q[328]
  PIN q[329]
    DIRECTION OUTPUT ;
    USE SIGNAL ;
    PORT
      LAYER M4 ;
        RECT  11.688 63.552 11.88 63.576 ;
    END
  END q[329]
  PIN q[32]
    DIRECTION OUTPUT ;
    USE SIGNAL ;
    PORT
      LAYER M4 ;
        RECT  11.688 6.528 11.88 6.552 ;
    END
  END q[32]
  PIN q[330]
    DIRECTION OUTPUT ;
    USE SIGNAL ;
    PORT
      LAYER M4 ;
        RECT  11.688 63.744 11.88 63.768 ;
    END
  END q[330]
  PIN q[331]
    DIRECTION OUTPUT ;
    USE SIGNAL ;
    PORT
      LAYER M4 ;
        RECT  11.688 63.936 11.88 63.96 ;
    END
  END q[331]
  PIN q[332]
    DIRECTION OUTPUT ;
    USE SIGNAL ;
    PORT
      LAYER M4 ;
        RECT  11.688 64.128 11.88 64.152 ;
    END
  END q[332]
  PIN q[333]
    DIRECTION OUTPUT ;
    USE SIGNAL ;
    PORT
      LAYER M4 ;
        RECT  11.688 64.32 11.88 64.344 ;
    END
  END q[333]
  PIN q[334]
    DIRECTION OUTPUT ;
    USE SIGNAL ;
    PORT
      LAYER M4 ;
        RECT  11.688 64.512 11.88 64.536 ;
    END
  END q[334]
  PIN q[335]
    DIRECTION OUTPUT ;
    USE SIGNAL ;
    PORT
      LAYER M4 ;
        RECT  11.688 64.704 11.88 64.728 ;
    END
  END q[335]
  PIN q[336]
    DIRECTION OUTPUT ;
    USE SIGNAL ;
    PORT
      LAYER M4 ;
        RECT  11.688 64.896 11.88 64.92 ;
    END
  END q[336]
  PIN q[337]
    DIRECTION OUTPUT ;
    USE SIGNAL ;
    PORT
      LAYER M4 ;
        RECT  11.688 65.088 11.88 65.112 ;
    END
  END q[337]
  PIN q[338]
    DIRECTION OUTPUT ;
    USE SIGNAL ;
    PORT
      LAYER M4 ;
        RECT  11.688 65.28 11.88 65.304 ;
    END
  END q[338]
  PIN q[339]
    DIRECTION OUTPUT ;
    USE SIGNAL ;
    PORT
      LAYER M4 ;
        RECT  11.688 65.472 11.88 65.496 ;
    END
  END q[339]
  PIN q[33]
    DIRECTION OUTPUT ;
    USE SIGNAL ;
    PORT
      LAYER M4 ;
        RECT  11.688 6.72 11.88 6.744 ;
    END
  END q[33]
  PIN q[340]
    DIRECTION OUTPUT ;
    USE SIGNAL ;
    PORT
      LAYER M4 ;
        RECT  11.688 65.664 11.88 65.688 ;
    END
  END q[340]
  PIN q[341]
    DIRECTION OUTPUT ;
    USE SIGNAL ;
    PORT
      LAYER M4 ;
        RECT  11.688 65.856 11.88 65.88 ;
    END
  END q[341]
  PIN q[342]
    DIRECTION OUTPUT ;
    USE SIGNAL ;
    PORT
      LAYER M4 ;
        RECT  11.688 66.048 11.88 66.072 ;
    END
  END q[342]
  PIN q[343]
    DIRECTION OUTPUT ;
    USE SIGNAL ;
    PORT
      LAYER M4 ;
        RECT  11.688 66.24 11.88 66.264 ;
    END
  END q[343]
  PIN q[344]
    DIRECTION OUTPUT ;
    USE SIGNAL ;
    PORT
      LAYER M4 ;
        RECT  11.688 66.432 11.88 66.456 ;
    END
  END q[344]
  PIN q[345]
    DIRECTION OUTPUT ;
    USE SIGNAL ;
    PORT
      LAYER M4 ;
        RECT  11.688 66.624 11.88 66.648 ;
    END
  END q[345]
  PIN q[346]
    DIRECTION OUTPUT ;
    USE SIGNAL ;
    PORT
      LAYER M4 ;
        RECT  11.688 66.816 11.88 66.84 ;
    END
  END q[346]
  PIN q[347]
    DIRECTION OUTPUT ;
    USE SIGNAL ;
    PORT
      LAYER M4 ;
        RECT  11.688 67.008 11.88 67.032 ;
    END
  END q[347]
  PIN q[348]
    DIRECTION OUTPUT ;
    USE SIGNAL ;
    PORT
      LAYER M4 ;
        RECT  11.688 67.2 11.88 67.224 ;
    END
  END q[348]
  PIN q[349]
    DIRECTION OUTPUT ;
    USE SIGNAL ;
    PORT
      LAYER M4 ;
        RECT  11.688 67.392 11.88 67.416 ;
    END
  END q[349]
  PIN q[34]
    DIRECTION OUTPUT ;
    USE SIGNAL ;
    PORT
      LAYER M4 ;
        RECT  11.688 6.912 11.88 6.936 ;
    END
  END q[34]
  PIN q[350]
    DIRECTION OUTPUT ;
    USE SIGNAL ;
    PORT
      LAYER M4 ;
        RECT  11.688 67.584 11.88 67.608 ;
    END
  END q[350]
  PIN q[351]
    DIRECTION OUTPUT ;
    USE SIGNAL ;
    PORT
      LAYER M4 ;
        RECT  11.688 67.776 11.88 67.8 ;
    END
  END q[351]
  PIN q[352]
    DIRECTION OUTPUT ;
    USE SIGNAL ;
    PORT
      LAYER M4 ;
        RECT  11.688 67.968 11.88 67.992 ;
    END
  END q[352]
  PIN q[353]
    DIRECTION OUTPUT ;
    USE SIGNAL ;
    PORT
      LAYER M4 ;
        RECT  11.688 68.16 11.88 68.184 ;
    END
  END q[353]
  PIN q[354]
    DIRECTION OUTPUT ;
    USE SIGNAL ;
    PORT
      LAYER M4 ;
        RECT  11.688 68.352 11.88 68.376 ;
    END
  END q[354]
  PIN q[355]
    DIRECTION OUTPUT ;
    USE SIGNAL ;
    PORT
      LAYER M4 ;
        RECT  11.688 68.544 11.88 68.568 ;
    END
  END q[355]
  PIN q[356]
    DIRECTION OUTPUT ;
    USE SIGNAL ;
    PORT
      LAYER M4 ;
        RECT  11.688 68.736 11.88 68.76 ;
    END
  END q[356]
  PIN q[357]
    DIRECTION OUTPUT ;
    USE SIGNAL ;
    PORT
      LAYER M4 ;
        RECT  11.688 68.928 11.88 68.952 ;
    END
  END q[357]
  PIN q[358]
    DIRECTION OUTPUT ;
    USE SIGNAL ;
    PORT
      LAYER M4 ;
        RECT  11.688 69.12 11.88 69.144 ;
    END
  END q[358]
  PIN q[359]
    DIRECTION OUTPUT ;
    USE SIGNAL ;
    PORT
      LAYER M4 ;
        RECT  11.688 69.312 11.88 69.336 ;
    END
  END q[359]
  PIN q[35]
    DIRECTION OUTPUT ;
    USE SIGNAL ;
    PORT
      LAYER M4 ;
        RECT  11.688 7.104 11.88 7.128 ;
    END
  END q[35]
  PIN q[360]
    DIRECTION OUTPUT ;
    USE SIGNAL ;
    PORT
      LAYER M4 ;
        RECT  11.688 69.504 11.88 69.528 ;
    END
  END q[360]
  PIN q[361]
    DIRECTION OUTPUT ;
    USE SIGNAL ;
    PORT
      LAYER M4 ;
        RECT  11.688 69.696 11.88 69.72 ;
    END
  END q[361]
  PIN q[362]
    DIRECTION OUTPUT ;
    USE SIGNAL ;
    PORT
      LAYER M4 ;
        RECT  11.688 69.888 11.88 69.912 ;
    END
  END q[362]
  PIN q[363]
    DIRECTION OUTPUT ;
    USE SIGNAL ;
    PORT
      LAYER M4 ;
        RECT  11.688 70.08 11.88 70.104 ;
    END
  END q[363]
  PIN q[364]
    DIRECTION OUTPUT ;
    USE SIGNAL ;
    PORT
      LAYER M4 ;
        RECT  11.688 70.272 11.88 70.296 ;
    END
  END q[364]
  PIN q[365]
    DIRECTION OUTPUT ;
    USE SIGNAL ;
    PORT
      LAYER M4 ;
        RECT  11.688 70.464 11.88 70.488 ;
    END
  END q[365]
  PIN q[366]
    DIRECTION OUTPUT ;
    USE SIGNAL ;
    PORT
      LAYER M4 ;
        RECT  11.688 70.656 11.88 70.68 ;
    END
  END q[366]
  PIN q[367]
    DIRECTION OUTPUT ;
    USE SIGNAL ;
    PORT
      LAYER M4 ;
        RECT  11.688 70.848 11.88 70.872 ;
    END
  END q[367]
  PIN q[368]
    DIRECTION OUTPUT ;
    USE SIGNAL ;
    PORT
      LAYER M4 ;
        RECT  11.688 71.04 11.88 71.064 ;
    END
  END q[368]
  PIN q[369]
    DIRECTION OUTPUT ;
    USE SIGNAL ;
    PORT
      LAYER M4 ;
        RECT  11.688 71.232 11.88 71.256 ;
    END
  END q[369]
  PIN q[36]
    DIRECTION OUTPUT ;
    USE SIGNAL ;
    PORT
      LAYER M4 ;
        RECT  11.688 7.296 11.88 7.32 ;
    END
  END q[36]
  PIN q[370]
    DIRECTION OUTPUT ;
    USE SIGNAL ;
    PORT
      LAYER M4 ;
        RECT  11.688 71.424 11.88 71.448 ;
    END
  END q[370]
  PIN q[371]
    DIRECTION OUTPUT ;
    USE SIGNAL ;
    PORT
      LAYER M4 ;
        RECT  11.688 71.616 11.88 71.64 ;
    END
  END q[371]
  PIN q[372]
    DIRECTION OUTPUT ;
    USE SIGNAL ;
    PORT
      LAYER M4 ;
        RECT  11.688 71.808 11.88 71.832 ;
    END
  END q[372]
  PIN q[373]
    DIRECTION OUTPUT ;
    USE SIGNAL ;
    PORT
      LAYER M4 ;
        RECT  11.688 72 11.88 72.024 ;
    END
  END q[373]
  PIN q[374]
    DIRECTION OUTPUT ;
    USE SIGNAL ;
    PORT
      LAYER M4 ;
        RECT  11.688 72.192 11.88 72.216 ;
    END
  END q[374]
  PIN q[375]
    DIRECTION OUTPUT ;
    USE SIGNAL ;
    PORT
      LAYER M4 ;
        RECT  11.688 72.384 11.88 72.408 ;
    END
  END q[375]
  PIN q[376]
    DIRECTION OUTPUT ;
    USE SIGNAL ;
    PORT
      LAYER M4 ;
        RECT  11.688 72.576 11.88 72.6 ;
    END
  END q[376]
  PIN q[377]
    DIRECTION OUTPUT ;
    USE SIGNAL ;
    PORT
      LAYER M4 ;
        RECT  11.688 72.768 11.88 72.792 ;
    END
  END q[377]
  PIN q[378]
    DIRECTION OUTPUT ;
    USE SIGNAL ;
    PORT
      LAYER M4 ;
        RECT  11.688 72.96 11.88 72.984 ;
    END
  END q[378]
  PIN q[379]
    DIRECTION OUTPUT ;
    USE SIGNAL ;
    PORT
      LAYER M4 ;
        RECT  11.688 73.152 11.88 73.176 ;
    END
  END q[379]
  PIN q[37]
    DIRECTION OUTPUT ;
    USE SIGNAL ;
    PORT
      LAYER M4 ;
        RECT  11.688 7.488 11.88 7.512 ;
    END
  END q[37]
  PIN q[380]
    DIRECTION OUTPUT ;
    USE SIGNAL ;
    PORT
      LAYER M4 ;
        RECT  11.688 73.344 11.88 73.368 ;
    END
  END q[380]
  PIN q[381]
    DIRECTION OUTPUT ;
    USE SIGNAL ;
    PORT
      LAYER M4 ;
        RECT  11.688 73.536 11.88 73.56 ;
    END
  END q[381]
  PIN q[382]
    DIRECTION OUTPUT ;
    USE SIGNAL ;
    PORT
      LAYER M4 ;
        RECT  11.688 73.728 11.88 73.752 ;
    END
  END q[382]
  PIN q[383]
    DIRECTION OUTPUT ;
    USE SIGNAL ;
    PORT
      LAYER M4 ;
        RECT  11.688 73.92 11.88 73.944 ;
    END
  END q[383]
  PIN q[384]
    DIRECTION OUTPUT ;
    USE SIGNAL ;
    PORT
      LAYER M4 ;
        RECT  11.688 74.112 11.88 74.136 ;
    END
  END q[384]
  PIN q[385]
    DIRECTION OUTPUT ;
    USE SIGNAL ;
    PORT
      LAYER M4 ;
        RECT  11.688 74.304 11.88 74.328 ;
    END
  END q[385]
  PIN q[386]
    DIRECTION OUTPUT ;
    USE SIGNAL ;
    PORT
      LAYER M4 ;
        RECT  11.688 74.496 11.88 74.52 ;
    END
  END q[386]
  PIN q[387]
    DIRECTION OUTPUT ;
    USE SIGNAL ;
    PORT
      LAYER M4 ;
        RECT  11.688 74.688 11.88 74.712 ;
    END
  END q[387]
  PIN q[388]
    DIRECTION OUTPUT ;
    USE SIGNAL ;
    PORT
      LAYER M4 ;
        RECT  11.688 74.88 11.88 74.904 ;
    END
  END q[388]
  PIN q[389]
    DIRECTION OUTPUT ;
    USE SIGNAL ;
    PORT
      LAYER M4 ;
        RECT  11.688 75.072 11.88 75.096 ;
    END
  END q[389]
  PIN q[38]
    DIRECTION OUTPUT ;
    USE SIGNAL ;
    PORT
      LAYER M4 ;
        RECT  11.688 7.68 11.88 7.704 ;
    END
  END q[38]
  PIN q[390]
    DIRECTION OUTPUT ;
    USE SIGNAL ;
    PORT
      LAYER M4 ;
        RECT  11.688 75.264 11.88 75.288 ;
    END
  END q[390]
  PIN q[391]
    DIRECTION OUTPUT ;
    USE SIGNAL ;
    PORT
      LAYER M4 ;
        RECT  11.688 75.456 11.88 75.48 ;
    END
  END q[391]
  PIN q[392]
    DIRECTION OUTPUT ;
    USE SIGNAL ;
    PORT
      LAYER M4 ;
        RECT  11.688 75.648 11.88 75.672 ;
    END
  END q[392]
  PIN q[393]
    DIRECTION OUTPUT ;
    USE SIGNAL ;
    PORT
      LAYER M4 ;
        RECT  11.688 75.84 11.88 75.864 ;
    END
  END q[393]
  PIN q[394]
    DIRECTION OUTPUT ;
    USE SIGNAL ;
    PORT
      LAYER M4 ;
        RECT  11.688 76.032 11.88 76.056 ;
    END
  END q[394]
  PIN q[395]
    DIRECTION OUTPUT ;
    USE SIGNAL ;
    PORT
      LAYER M4 ;
        RECT  11.688 76.224 11.88 76.248 ;
    END
  END q[395]
  PIN q[396]
    DIRECTION OUTPUT ;
    USE SIGNAL ;
    PORT
      LAYER M4 ;
        RECT  11.688 76.416 11.88 76.44 ;
    END
  END q[396]
  PIN q[397]
    DIRECTION OUTPUT ;
    USE SIGNAL ;
    PORT
      LAYER M4 ;
        RECT  11.688 76.608 11.88 76.632 ;
    END
  END q[397]
  PIN q[398]
    DIRECTION OUTPUT ;
    USE SIGNAL ;
    PORT
      LAYER M4 ;
        RECT  11.688 76.8 11.88 76.824 ;
    END
  END q[398]
  PIN q[399]
    DIRECTION OUTPUT ;
    USE SIGNAL ;
    PORT
      LAYER M4 ;
        RECT  11.688 76.992 11.88 77.016 ;
    END
  END q[399]
  PIN q[39]
    DIRECTION OUTPUT ;
    USE SIGNAL ;
    PORT
      LAYER M4 ;
        RECT  11.688 7.872 11.88 7.896 ;
    END
  END q[39]
  PIN q[3]
    DIRECTION OUTPUT ;
    USE SIGNAL ;
    PORT
      LAYER M4 ;
        RECT  11.688 0.96 11.88 0.984 ;
    END
  END q[3]
  PIN q[400]
    DIRECTION OUTPUT ;
    USE SIGNAL ;
    PORT
      LAYER M4 ;
        RECT  11.688 77.184 11.88 77.208 ;
    END
  END q[400]
  PIN q[401]
    DIRECTION OUTPUT ;
    USE SIGNAL ;
    PORT
      LAYER M4 ;
        RECT  11.688 77.376 11.88 77.4 ;
    END
  END q[401]
  PIN q[402]
    DIRECTION OUTPUT ;
    USE SIGNAL ;
    PORT
      LAYER M4 ;
        RECT  11.688 77.568 11.88 77.592 ;
    END
  END q[402]
  PIN q[403]
    DIRECTION OUTPUT ;
    USE SIGNAL ;
    PORT
      LAYER M4 ;
        RECT  11.688 77.76 11.88 77.784 ;
    END
  END q[403]
  PIN q[404]
    DIRECTION OUTPUT ;
    USE SIGNAL ;
    PORT
      LAYER M4 ;
        RECT  11.688 77.952 11.88 77.976 ;
    END
  END q[404]
  PIN q[405]
    DIRECTION OUTPUT ;
    USE SIGNAL ;
    PORT
      LAYER M4 ;
        RECT  11.688 78.144 11.88 78.168 ;
    END
  END q[405]
  PIN q[406]
    DIRECTION OUTPUT ;
    USE SIGNAL ;
    PORT
      LAYER M4 ;
        RECT  11.688 78.336 11.88 78.36 ;
    END
  END q[406]
  PIN q[407]
    DIRECTION OUTPUT ;
    USE SIGNAL ;
    PORT
      LAYER M4 ;
        RECT  11.688 78.528 11.88 78.552 ;
    END
  END q[407]
  PIN q[408]
    DIRECTION OUTPUT ;
    USE SIGNAL ;
    PORT
      LAYER M4 ;
        RECT  11.688 78.72 11.88 78.744 ;
    END
  END q[408]
  PIN q[409]
    DIRECTION OUTPUT ;
    USE SIGNAL ;
    PORT
      LAYER M4 ;
        RECT  11.688 78.912 11.88 78.936 ;
    END
  END q[409]
  PIN q[40]
    DIRECTION OUTPUT ;
    USE SIGNAL ;
    PORT
      LAYER M4 ;
        RECT  11.688 8.064 11.88 8.088 ;
    END
  END q[40]
  PIN q[410]
    DIRECTION OUTPUT ;
    USE SIGNAL ;
    PORT
      LAYER M4 ;
        RECT  11.688 79.104 11.88 79.128 ;
    END
  END q[410]
  PIN q[411]
    DIRECTION OUTPUT ;
    USE SIGNAL ;
    PORT
      LAYER M4 ;
        RECT  11.688 79.296 11.88 79.32 ;
    END
  END q[411]
  PIN q[412]
    DIRECTION OUTPUT ;
    USE SIGNAL ;
    PORT
      LAYER M4 ;
        RECT  11.688 79.488 11.88 79.512 ;
    END
  END q[412]
  PIN q[413]
    DIRECTION OUTPUT ;
    USE SIGNAL ;
    PORT
      LAYER M4 ;
        RECT  11.688 79.68 11.88 79.704 ;
    END
  END q[413]
  PIN q[414]
    DIRECTION OUTPUT ;
    USE SIGNAL ;
    PORT
      LAYER M4 ;
        RECT  11.688 79.872 11.88 79.896 ;
    END
  END q[414]
  PIN q[415]
    DIRECTION OUTPUT ;
    USE SIGNAL ;
    PORT
      LAYER M4 ;
        RECT  11.688 80.064 11.88 80.088 ;
    END
  END q[415]
  PIN q[416]
    DIRECTION OUTPUT ;
    USE SIGNAL ;
    PORT
      LAYER M4 ;
        RECT  11.688 80.256 11.88 80.28 ;
    END
  END q[416]
  PIN q[417]
    DIRECTION OUTPUT ;
    USE SIGNAL ;
    PORT
      LAYER M4 ;
        RECT  11.688 80.448 11.88 80.472 ;
    END
  END q[417]
  PIN q[418]
    DIRECTION OUTPUT ;
    USE SIGNAL ;
    PORT
      LAYER M4 ;
        RECT  11.688 80.64 11.88 80.664 ;
    END
  END q[418]
  PIN q[419]
    DIRECTION OUTPUT ;
    USE SIGNAL ;
    PORT
      LAYER M4 ;
        RECT  11.688 80.832 11.88 80.856 ;
    END
  END q[419]
  PIN q[41]
    DIRECTION OUTPUT ;
    USE SIGNAL ;
    PORT
      LAYER M4 ;
        RECT  11.688 8.256 11.88 8.28 ;
    END
  END q[41]
  PIN q[420]
    DIRECTION OUTPUT ;
    USE SIGNAL ;
    PORT
      LAYER M4 ;
        RECT  11.688 81.024 11.88 81.048 ;
    END
  END q[420]
  PIN q[421]
    DIRECTION OUTPUT ;
    USE SIGNAL ;
    PORT
      LAYER M4 ;
        RECT  11.688 81.216 11.88 81.24 ;
    END
  END q[421]
  PIN q[422]
    DIRECTION OUTPUT ;
    USE SIGNAL ;
    PORT
      LAYER M4 ;
        RECT  11.688 81.408 11.88 81.432 ;
    END
  END q[422]
  PIN q[423]
    DIRECTION OUTPUT ;
    USE SIGNAL ;
    PORT
      LAYER M4 ;
        RECT  11.688 81.6 11.88 81.624 ;
    END
  END q[423]
  PIN q[424]
    DIRECTION OUTPUT ;
    USE SIGNAL ;
    PORT
      LAYER M4 ;
        RECT  11.688 81.792 11.88 81.816 ;
    END
  END q[424]
  PIN q[425]
    DIRECTION OUTPUT ;
    USE SIGNAL ;
    PORT
      LAYER M4 ;
        RECT  11.688 81.984 11.88 82.008 ;
    END
  END q[425]
  PIN q[426]
    DIRECTION OUTPUT ;
    USE SIGNAL ;
    PORT
      LAYER M4 ;
        RECT  11.688 82.176 11.88 82.2 ;
    END
  END q[426]
  PIN q[427]
    DIRECTION OUTPUT ;
    USE SIGNAL ;
    PORT
      LAYER M4 ;
        RECT  11.688 82.368 11.88 82.392 ;
    END
  END q[427]
  PIN q[428]
    DIRECTION OUTPUT ;
    USE SIGNAL ;
    PORT
      LAYER M4 ;
        RECT  11.688 82.56 11.88 82.584 ;
    END
  END q[428]
  PIN q[429]
    DIRECTION OUTPUT ;
    USE SIGNAL ;
    PORT
      LAYER M4 ;
        RECT  11.688 82.752 11.88 82.776 ;
    END
  END q[429]
  PIN q[42]
    DIRECTION OUTPUT ;
    USE SIGNAL ;
    PORT
      LAYER M4 ;
        RECT  11.688 8.448 11.88 8.472 ;
    END
  END q[42]
  PIN q[430]
    DIRECTION OUTPUT ;
    USE SIGNAL ;
    PORT
      LAYER M4 ;
        RECT  11.688 82.944 11.88 82.968 ;
    END
  END q[430]
  PIN q[431]
    DIRECTION OUTPUT ;
    USE SIGNAL ;
    PORT
      LAYER M4 ;
        RECT  11.688 83.136 11.88 83.16 ;
    END
  END q[431]
  PIN q[432]
    DIRECTION OUTPUT ;
    USE SIGNAL ;
    PORT
      LAYER M4 ;
        RECT  11.688 83.328 11.88 83.352 ;
    END
  END q[432]
  PIN q[433]
    DIRECTION OUTPUT ;
    USE SIGNAL ;
    PORT
      LAYER M4 ;
        RECT  11.688 83.52 11.88 83.544 ;
    END
  END q[433]
  PIN q[434]
    DIRECTION OUTPUT ;
    USE SIGNAL ;
    PORT
      LAYER M4 ;
        RECT  11.688 83.712 11.88 83.736 ;
    END
  END q[434]
  PIN q[435]
    DIRECTION OUTPUT ;
    USE SIGNAL ;
    PORT
      LAYER M4 ;
        RECT  11.688 83.904 11.88 83.928 ;
    END
  END q[435]
  PIN q[436]
    DIRECTION OUTPUT ;
    USE SIGNAL ;
    PORT
      LAYER M4 ;
        RECT  11.688 84.096 11.88 84.12 ;
    END
  END q[436]
  PIN q[437]
    DIRECTION OUTPUT ;
    USE SIGNAL ;
    PORT
      LAYER M4 ;
        RECT  11.688 84.288 11.88 84.312 ;
    END
  END q[437]
  PIN q[438]
    DIRECTION OUTPUT ;
    USE SIGNAL ;
    PORT
      LAYER M4 ;
        RECT  11.688 84.48 11.88 84.504 ;
    END
  END q[438]
  PIN q[439]
    DIRECTION OUTPUT ;
    USE SIGNAL ;
    PORT
      LAYER M4 ;
        RECT  11.688 84.672 11.88 84.696 ;
    END
  END q[439]
  PIN q[43]
    DIRECTION OUTPUT ;
    USE SIGNAL ;
    PORT
      LAYER M4 ;
        RECT  11.688 8.64 11.88 8.664 ;
    END
  END q[43]
  PIN q[440]
    DIRECTION OUTPUT ;
    USE SIGNAL ;
    PORT
      LAYER M4 ;
        RECT  11.688 84.864 11.88 84.888 ;
    END
  END q[440]
  PIN q[441]
    DIRECTION OUTPUT ;
    USE SIGNAL ;
    PORT
      LAYER M4 ;
        RECT  11.688 85.056 11.88 85.08 ;
    END
  END q[441]
  PIN q[442]
    DIRECTION OUTPUT ;
    USE SIGNAL ;
    PORT
      LAYER M4 ;
        RECT  11.688 85.248 11.88 85.272 ;
    END
  END q[442]
  PIN q[443]
    DIRECTION OUTPUT ;
    USE SIGNAL ;
    PORT
      LAYER M4 ;
        RECT  11.688 85.44 11.88 85.464 ;
    END
  END q[443]
  PIN q[444]
    DIRECTION OUTPUT ;
    USE SIGNAL ;
    PORT
      LAYER M4 ;
        RECT  11.688 85.632 11.88 85.656 ;
    END
  END q[444]
  PIN q[445]
    DIRECTION OUTPUT ;
    USE SIGNAL ;
    PORT
      LAYER M4 ;
        RECT  11.688 85.824 11.88 85.848 ;
    END
  END q[445]
  PIN q[446]
    DIRECTION OUTPUT ;
    USE SIGNAL ;
    PORT
      LAYER M4 ;
        RECT  11.688 86.016 11.88 86.04 ;
    END
  END q[446]
  PIN q[447]
    DIRECTION OUTPUT ;
    USE SIGNAL ;
    PORT
      LAYER M4 ;
        RECT  11.688 86.208 11.88 86.232 ;
    END
  END q[447]
  PIN q[448]
    DIRECTION OUTPUT ;
    USE SIGNAL ;
    PORT
      LAYER M4 ;
        RECT  11.688 86.4 11.88 86.424 ;
    END
  END q[448]
  PIN q[449]
    DIRECTION OUTPUT ;
    USE SIGNAL ;
    PORT
      LAYER M4 ;
        RECT  11.688 86.592 11.88 86.616 ;
    END
  END q[449]
  PIN q[44]
    DIRECTION OUTPUT ;
    USE SIGNAL ;
    PORT
      LAYER M4 ;
        RECT  11.688 8.832 11.88 8.856 ;
    END
  END q[44]
  PIN q[450]
    DIRECTION OUTPUT ;
    USE SIGNAL ;
    PORT
      LAYER M4 ;
        RECT  11.688 86.784 11.88 86.808 ;
    END
  END q[450]
  PIN q[451]
    DIRECTION OUTPUT ;
    USE SIGNAL ;
    PORT
      LAYER M4 ;
        RECT  11.688 86.976 11.88 87 ;
    END
  END q[451]
  PIN q[452]
    DIRECTION OUTPUT ;
    USE SIGNAL ;
    PORT
      LAYER M4 ;
        RECT  11.688 87.168 11.88 87.192 ;
    END
  END q[452]
  PIN q[453]
    DIRECTION OUTPUT ;
    USE SIGNAL ;
    PORT
      LAYER M4 ;
        RECT  11.688 87.36 11.88 87.384 ;
    END
  END q[453]
  PIN q[454]
    DIRECTION OUTPUT ;
    USE SIGNAL ;
    PORT
      LAYER M4 ;
        RECT  11.688 87.552 11.88 87.576 ;
    END
  END q[454]
  PIN q[455]
    DIRECTION OUTPUT ;
    USE SIGNAL ;
    PORT
      LAYER M4 ;
        RECT  11.688 87.744 11.88 87.768 ;
    END
  END q[455]
  PIN q[456]
    DIRECTION OUTPUT ;
    USE SIGNAL ;
    PORT
      LAYER M4 ;
        RECT  11.688 87.936 11.88 87.96 ;
    END
  END q[456]
  PIN q[457]
    DIRECTION OUTPUT ;
    USE SIGNAL ;
    PORT
      LAYER M4 ;
        RECT  11.688 88.128 11.88 88.152 ;
    END
  END q[457]
  PIN q[458]
    DIRECTION OUTPUT ;
    USE SIGNAL ;
    PORT
      LAYER M4 ;
        RECT  11.688 88.32 11.88 88.344 ;
    END
  END q[458]
  PIN q[459]
    DIRECTION OUTPUT ;
    USE SIGNAL ;
    PORT
      LAYER M4 ;
        RECT  11.688 88.512 11.88 88.536 ;
    END
  END q[459]
  PIN q[45]
    DIRECTION OUTPUT ;
    USE SIGNAL ;
    PORT
      LAYER M4 ;
        RECT  11.688 9.024 11.88 9.048 ;
    END
  END q[45]
  PIN q[460]
    DIRECTION OUTPUT ;
    USE SIGNAL ;
    PORT
      LAYER M4 ;
        RECT  11.688 88.704 11.88 88.728 ;
    END
  END q[460]
  PIN q[461]
    DIRECTION OUTPUT ;
    USE SIGNAL ;
    PORT
      LAYER M4 ;
        RECT  11.688 88.896 11.88 88.92 ;
    END
  END q[461]
  PIN q[462]
    DIRECTION OUTPUT ;
    USE SIGNAL ;
    PORT
      LAYER M4 ;
        RECT  11.688 89.088 11.88 89.112 ;
    END
  END q[462]
  PIN q[463]
    DIRECTION OUTPUT ;
    USE SIGNAL ;
    PORT
      LAYER M4 ;
        RECT  11.688 89.28 11.88 89.304 ;
    END
  END q[463]
  PIN q[464]
    DIRECTION OUTPUT ;
    USE SIGNAL ;
    PORT
      LAYER M4 ;
        RECT  11.688 89.472 11.88 89.496 ;
    END
  END q[464]
  PIN q[465]
    DIRECTION OUTPUT ;
    USE SIGNAL ;
    PORT
      LAYER M4 ;
        RECT  11.688 89.664 11.88 89.688 ;
    END
  END q[465]
  PIN q[466]
    DIRECTION OUTPUT ;
    USE SIGNAL ;
    PORT
      LAYER M4 ;
        RECT  11.688 89.856 11.88 89.88 ;
    END
  END q[466]
  PIN q[467]
    DIRECTION OUTPUT ;
    USE SIGNAL ;
    PORT
      LAYER M4 ;
        RECT  11.688 90.048 11.88 90.072 ;
    END
  END q[467]
  PIN q[468]
    DIRECTION OUTPUT ;
    USE SIGNAL ;
    PORT
      LAYER M4 ;
        RECT  11.688 90.24 11.88 90.264 ;
    END
  END q[468]
  PIN q[469]
    DIRECTION OUTPUT ;
    USE SIGNAL ;
    PORT
      LAYER M4 ;
        RECT  11.688 90.432 11.88 90.456 ;
    END
  END q[469]
  PIN q[46]
    DIRECTION OUTPUT ;
    USE SIGNAL ;
    PORT
      LAYER M4 ;
        RECT  11.688 9.216 11.88 9.24 ;
    END
  END q[46]
  PIN q[470]
    DIRECTION OUTPUT ;
    USE SIGNAL ;
    PORT
      LAYER M4 ;
        RECT  11.688 90.624 11.88 90.648 ;
    END
  END q[470]
  PIN q[471]
    DIRECTION OUTPUT ;
    USE SIGNAL ;
    PORT
      LAYER M4 ;
        RECT  11.688 90.816 11.88 90.84 ;
    END
  END q[471]
  PIN q[472]
    DIRECTION OUTPUT ;
    USE SIGNAL ;
    PORT
      LAYER M4 ;
        RECT  11.688 91.008 11.88 91.032 ;
    END
  END q[472]
  PIN q[473]
    DIRECTION OUTPUT ;
    USE SIGNAL ;
    PORT
      LAYER M4 ;
        RECT  11.688 91.2 11.88 91.224 ;
    END
  END q[473]
  PIN q[474]
    DIRECTION OUTPUT ;
    USE SIGNAL ;
    PORT
      LAYER M4 ;
        RECT  11.688 91.392 11.88 91.416 ;
    END
  END q[474]
  PIN q[475]
    DIRECTION OUTPUT ;
    USE SIGNAL ;
    PORT
      LAYER M4 ;
        RECT  11.688 91.584 11.88 91.608 ;
    END
  END q[475]
  PIN q[476]
    DIRECTION OUTPUT ;
    USE SIGNAL ;
    PORT
      LAYER M4 ;
        RECT  11.688 91.776 11.88 91.8 ;
    END
  END q[476]
  PIN q[477]
    DIRECTION OUTPUT ;
    USE SIGNAL ;
    PORT
      LAYER M4 ;
        RECT  11.688 91.968 11.88 91.992 ;
    END
  END q[477]
  PIN q[478]
    DIRECTION OUTPUT ;
    USE SIGNAL ;
    PORT
      LAYER M4 ;
        RECT  11.688 92.16 11.88 92.184 ;
    END
  END q[478]
  PIN q[479]
    DIRECTION OUTPUT ;
    USE SIGNAL ;
    PORT
      LAYER M4 ;
        RECT  11.688 92.352 11.88 92.376 ;
    END
  END q[479]
  PIN q[47]
    DIRECTION OUTPUT ;
    USE SIGNAL ;
    PORT
      LAYER M4 ;
        RECT  11.688 9.408 11.88 9.432 ;
    END
  END q[47]
  PIN q[480]
    DIRECTION OUTPUT ;
    USE SIGNAL ;
    PORT
      LAYER M4 ;
        RECT  11.688 92.544 11.88 92.568 ;
    END
  END q[480]
  PIN q[481]
    DIRECTION OUTPUT ;
    USE SIGNAL ;
    PORT
      LAYER M4 ;
        RECT  11.688 92.736 11.88 92.76 ;
    END
  END q[481]
  PIN q[482]
    DIRECTION OUTPUT ;
    USE SIGNAL ;
    PORT
      LAYER M4 ;
        RECT  11.688 92.928 11.88 92.952 ;
    END
  END q[482]
  PIN q[483]
    DIRECTION OUTPUT ;
    USE SIGNAL ;
    PORT
      LAYER M4 ;
        RECT  11.688 93.12 11.88 93.144 ;
    END
  END q[483]
  PIN q[484]
    DIRECTION OUTPUT ;
    USE SIGNAL ;
    PORT
      LAYER M4 ;
        RECT  11.688 93.312 11.88 93.336 ;
    END
  END q[484]
  PIN q[485]
    DIRECTION OUTPUT ;
    USE SIGNAL ;
    PORT
      LAYER M4 ;
        RECT  11.688 93.504 11.88 93.528 ;
    END
  END q[485]
  PIN q[486]
    DIRECTION OUTPUT ;
    USE SIGNAL ;
    PORT
      LAYER M4 ;
        RECT  11.688 93.696 11.88 93.72 ;
    END
  END q[486]
  PIN q[487]
    DIRECTION OUTPUT ;
    USE SIGNAL ;
    PORT
      LAYER M4 ;
        RECT  11.688 93.888 11.88 93.912 ;
    END
  END q[487]
  PIN q[488]
    DIRECTION OUTPUT ;
    USE SIGNAL ;
    PORT
      LAYER M4 ;
        RECT  11.688 94.08 11.88 94.104 ;
    END
  END q[488]
  PIN q[489]
    DIRECTION OUTPUT ;
    USE SIGNAL ;
    PORT
      LAYER M4 ;
        RECT  11.688 94.272 11.88 94.296 ;
    END
  END q[489]
  PIN q[48]
    DIRECTION OUTPUT ;
    USE SIGNAL ;
    PORT
      LAYER M4 ;
        RECT  11.688 9.6 11.88 9.624 ;
    END
  END q[48]
  PIN q[490]
    DIRECTION OUTPUT ;
    USE SIGNAL ;
    PORT
      LAYER M4 ;
        RECT  11.688 94.464 11.88 94.488 ;
    END
  END q[490]
  PIN q[491]
    DIRECTION OUTPUT ;
    USE SIGNAL ;
    PORT
      LAYER M4 ;
        RECT  11.688 94.656 11.88 94.68 ;
    END
  END q[491]
  PIN q[492]
    DIRECTION OUTPUT ;
    USE SIGNAL ;
    PORT
      LAYER M4 ;
        RECT  11.688 94.848 11.88 94.872 ;
    END
  END q[492]
  PIN q[493]
    DIRECTION OUTPUT ;
    USE SIGNAL ;
    PORT
      LAYER M4 ;
        RECT  11.688 95.04 11.88 95.064 ;
    END
  END q[493]
  PIN q[494]
    DIRECTION OUTPUT ;
    USE SIGNAL ;
    PORT
      LAYER M4 ;
        RECT  11.688 95.232 11.88 95.256 ;
    END
  END q[494]
  PIN q[495]
    DIRECTION OUTPUT ;
    USE SIGNAL ;
    PORT
      LAYER M4 ;
        RECT  11.688 95.424 11.88 95.448 ;
    END
  END q[495]
  PIN q[496]
    DIRECTION OUTPUT ;
    USE SIGNAL ;
    PORT
      LAYER M4 ;
        RECT  11.688 95.616 11.88 95.64 ;
    END
  END q[496]
  PIN q[497]
    DIRECTION OUTPUT ;
    USE SIGNAL ;
    PORT
      LAYER M4 ;
        RECT  11.688 95.808 11.88 95.832 ;
    END
  END q[497]
  PIN q[498]
    DIRECTION OUTPUT ;
    USE SIGNAL ;
    PORT
      LAYER M4 ;
        RECT  11.688 96 11.88 96.024 ;
    END
  END q[498]
  PIN q[499]
    DIRECTION OUTPUT ;
    USE SIGNAL ;
    PORT
      LAYER M4 ;
        RECT  11.688 96.192 11.88 96.216 ;
    END
  END q[499]
  PIN q[49]
    DIRECTION OUTPUT ;
    USE SIGNAL ;
    PORT
      LAYER M4 ;
        RECT  11.688 9.792 11.88 9.816 ;
    END
  END q[49]
  PIN q[4]
    DIRECTION OUTPUT ;
    USE SIGNAL ;
    PORT
      LAYER M4 ;
        RECT  11.688 1.152 11.88 1.176 ;
    END
  END q[4]
  PIN q[500]
    DIRECTION OUTPUT ;
    USE SIGNAL ;
    PORT
      LAYER M4 ;
        RECT  11.688 96.384 11.88 96.408 ;
    END
  END q[500]
  PIN q[501]
    DIRECTION OUTPUT ;
    USE SIGNAL ;
    PORT
      LAYER M4 ;
        RECT  11.688 96.576 11.88 96.6 ;
    END
  END q[501]
  PIN q[502]
    DIRECTION OUTPUT ;
    USE SIGNAL ;
    PORT
      LAYER M4 ;
        RECT  11.688 96.768 11.88 96.792 ;
    END
  END q[502]
  PIN q[503]
    DIRECTION OUTPUT ;
    USE SIGNAL ;
    PORT
      LAYER M4 ;
        RECT  11.688 96.96 11.88 96.984 ;
    END
  END q[503]
  PIN q[504]
    DIRECTION OUTPUT ;
    USE SIGNAL ;
    PORT
      LAYER M4 ;
        RECT  11.688 97.152 11.88 97.176 ;
    END
  END q[504]
  PIN q[505]
    DIRECTION OUTPUT ;
    USE SIGNAL ;
    PORT
      LAYER M4 ;
        RECT  11.688 97.344 11.88 97.368 ;
    END
  END q[505]
  PIN q[506]
    DIRECTION OUTPUT ;
    USE SIGNAL ;
    PORT
      LAYER M4 ;
        RECT  11.688 97.536 11.88 97.56 ;
    END
  END q[506]
  PIN q[507]
    DIRECTION OUTPUT ;
    USE SIGNAL ;
    PORT
      LAYER M4 ;
        RECT  11.688 97.728 11.88 97.752 ;
    END
  END q[507]
  PIN q[508]
    DIRECTION OUTPUT ;
    USE SIGNAL ;
    PORT
      LAYER M4 ;
        RECT  11.688 97.92 11.88 97.944 ;
    END
  END q[508]
  PIN q[509]
    DIRECTION OUTPUT ;
    USE SIGNAL ;
    PORT
      LAYER M4 ;
        RECT  11.688 98.112 11.88 98.136 ;
    END
  END q[509]
  PIN q[50]
    DIRECTION OUTPUT ;
    USE SIGNAL ;
    PORT
      LAYER M4 ;
        RECT  11.688 9.984 11.88 10.008 ;
    END
  END q[50]
  PIN q[510]
    DIRECTION OUTPUT ;
    USE SIGNAL ;
    PORT
      LAYER M4 ;
        RECT  11.688 98.304 11.88 98.328 ;
    END
  END q[510]
  PIN q[511]
    DIRECTION OUTPUT ;
    USE SIGNAL ;
    PORT
      LAYER M4 ;
        RECT  11.688 98.496 11.88 98.52 ;
    END
  END q[511]
  PIN q[512]
    DIRECTION OUTPUT ;
    USE SIGNAL ;
    PORT
      LAYER M4 ;
        RECT  11.688 98.688 11.88 98.712 ;
    END
  END q[512]
  PIN q[513]
    DIRECTION OUTPUT ;
    USE SIGNAL ;
    PORT
      LAYER M4 ;
        RECT  11.688 98.88 11.88 98.904 ;
    END
  END q[513]
  PIN q[514]
    DIRECTION OUTPUT ;
    USE SIGNAL ;
    PORT
      LAYER M4 ;
        RECT  11.688 99.072 11.88 99.096 ;
    END
  END q[514]
  PIN q[515]
    DIRECTION OUTPUT ;
    USE SIGNAL ;
    PORT
      LAYER M4 ;
        RECT  11.688 99.264 11.88 99.288 ;
    END
  END q[515]
  PIN q[516]
    DIRECTION OUTPUT ;
    USE SIGNAL ;
    PORT
      LAYER M4 ;
        RECT  11.688 99.456 11.88 99.48 ;
    END
  END q[516]
  PIN q[517]
    DIRECTION OUTPUT ;
    USE SIGNAL ;
    PORT
      LAYER M4 ;
        RECT  11.688 99.648 11.88 99.672 ;
    END
  END q[517]
  PIN q[518]
    DIRECTION OUTPUT ;
    USE SIGNAL ;
    PORT
      LAYER M4 ;
        RECT  11.688 99.84 11.88 99.864 ;
    END
  END q[518]
  PIN q[519]
    DIRECTION OUTPUT ;
    USE SIGNAL ;
    PORT
      LAYER M4 ;
        RECT  11.688 100.032 11.88 100.056 ;
    END
  END q[519]
  PIN q[51]
    DIRECTION OUTPUT ;
    USE SIGNAL ;
    PORT
      LAYER M4 ;
        RECT  11.688 10.176 11.88 10.2 ;
    END
  END q[51]
  PIN q[520]
    DIRECTION OUTPUT ;
    USE SIGNAL ;
    PORT
      LAYER M4 ;
        RECT  11.688 100.224 11.88 100.248 ;
    END
  END q[520]
  PIN q[521]
    DIRECTION OUTPUT ;
    USE SIGNAL ;
    PORT
      LAYER M4 ;
        RECT  11.688 100.416 11.88 100.44 ;
    END
  END q[521]
  PIN q[522]
    DIRECTION OUTPUT ;
    USE SIGNAL ;
    PORT
      LAYER M4 ;
        RECT  11.688 100.608 11.88 100.632 ;
    END
  END q[522]
  PIN q[523]
    DIRECTION OUTPUT ;
    USE SIGNAL ;
    PORT
      LAYER M4 ;
        RECT  11.688 100.8 11.88 100.824 ;
    END
  END q[523]
  PIN q[524]
    DIRECTION OUTPUT ;
    USE SIGNAL ;
    PORT
      LAYER M4 ;
        RECT  11.688 100.992 11.88 101.016 ;
    END
  END q[524]
  PIN q[525]
    DIRECTION OUTPUT ;
    USE SIGNAL ;
    PORT
      LAYER M4 ;
        RECT  11.688 101.184 11.88 101.208 ;
    END
  END q[525]
  PIN q[526]
    DIRECTION OUTPUT ;
    USE SIGNAL ;
    PORT
      LAYER M4 ;
        RECT  11.688 101.376 11.88 101.4 ;
    END
  END q[526]
  PIN q[527]
    DIRECTION OUTPUT ;
    USE SIGNAL ;
    PORT
      LAYER M4 ;
        RECT  11.688 101.568 11.88 101.592 ;
    END
  END q[527]
  PIN q[528]
    DIRECTION OUTPUT ;
    USE SIGNAL ;
    PORT
      LAYER M4 ;
        RECT  11.688 101.76 11.88 101.784 ;
    END
  END q[528]
  PIN q[529]
    DIRECTION OUTPUT ;
    USE SIGNAL ;
    PORT
      LAYER M4 ;
        RECT  11.688 101.952 11.88 101.976 ;
    END
  END q[529]
  PIN q[52]
    DIRECTION OUTPUT ;
    USE SIGNAL ;
    PORT
      LAYER M4 ;
        RECT  11.688 10.368 11.88 10.392 ;
    END
  END q[52]
  PIN q[530]
    DIRECTION OUTPUT ;
    USE SIGNAL ;
    PORT
      LAYER M4 ;
        RECT  11.688 102.144 11.88 102.168 ;
    END
  END q[530]
  PIN q[531]
    DIRECTION OUTPUT ;
    USE SIGNAL ;
    PORT
      LAYER M4 ;
        RECT  11.688 102.336 11.88 102.36 ;
    END
  END q[531]
  PIN q[532]
    DIRECTION OUTPUT ;
    USE SIGNAL ;
    PORT
      LAYER M4 ;
        RECT  11.688 102.528 11.88 102.552 ;
    END
  END q[532]
  PIN q[533]
    DIRECTION OUTPUT ;
    USE SIGNAL ;
    PORT
      LAYER M4 ;
        RECT  11.688 102.72 11.88 102.744 ;
    END
  END q[533]
  PIN q[534]
    DIRECTION OUTPUT ;
    USE SIGNAL ;
    PORT
      LAYER M4 ;
        RECT  11.688 102.912 11.88 102.936 ;
    END
  END q[534]
  PIN q[535]
    DIRECTION OUTPUT ;
    USE SIGNAL ;
    PORT
      LAYER M4 ;
        RECT  11.688 103.104 11.88 103.128 ;
    END
  END q[535]
  PIN q[536]
    DIRECTION OUTPUT ;
    USE SIGNAL ;
    PORT
      LAYER M4 ;
        RECT  11.688 103.296 11.88 103.32 ;
    END
  END q[536]
  PIN q[537]
    DIRECTION OUTPUT ;
    USE SIGNAL ;
    PORT
      LAYER M4 ;
        RECT  11.688 103.488 11.88 103.512 ;
    END
  END q[537]
  PIN q[538]
    DIRECTION OUTPUT ;
    USE SIGNAL ;
    PORT
      LAYER M4 ;
        RECT  11.688 103.68 11.88 103.704 ;
    END
  END q[538]
  PIN q[539]
    DIRECTION OUTPUT ;
    USE SIGNAL ;
    PORT
      LAYER M4 ;
        RECT  11.688 103.872 11.88 103.896 ;
    END
  END q[539]
  PIN q[53]
    DIRECTION OUTPUT ;
    USE SIGNAL ;
    PORT
      LAYER M4 ;
        RECT  11.688 10.56 11.88 10.584 ;
    END
  END q[53]
  PIN q[540]
    DIRECTION OUTPUT ;
    USE SIGNAL ;
    PORT
      LAYER M4 ;
        RECT  11.688 104.064 11.88 104.088 ;
    END
  END q[540]
  PIN q[541]
    DIRECTION OUTPUT ;
    USE SIGNAL ;
    PORT
      LAYER M4 ;
        RECT  11.688 104.256 11.88 104.28 ;
    END
  END q[541]
  PIN q[542]
    DIRECTION OUTPUT ;
    USE SIGNAL ;
    PORT
      LAYER M4 ;
        RECT  11.688 104.448 11.88 104.472 ;
    END
  END q[542]
  PIN q[543]
    DIRECTION OUTPUT ;
    USE SIGNAL ;
    PORT
      LAYER M4 ;
        RECT  11.688 104.64 11.88 104.664 ;
    END
  END q[543]
  PIN q[54]
    DIRECTION OUTPUT ;
    USE SIGNAL ;
    PORT
      LAYER M4 ;
        RECT  11.688 10.752 11.88 10.776 ;
    END
  END q[54]
  PIN q[55]
    DIRECTION OUTPUT ;
    USE SIGNAL ;
    PORT
      LAYER M4 ;
        RECT  11.688 10.944 11.88 10.968 ;
    END
  END q[55]
  PIN q[56]
    DIRECTION OUTPUT ;
    USE SIGNAL ;
    PORT
      LAYER M4 ;
        RECT  11.688 11.136 11.88 11.16 ;
    END
  END q[56]
  PIN q[57]
    DIRECTION OUTPUT ;
    USE SIGNAL ;
    PORT
      LAYER M4 ;
        RECT  11.688 11.328 11.88 11.352 ;
    END
  END q[57]
  PIN q[58]
    DIRECTION OUTPUT ;
    USE SIGNAL ;
    PORT
      LAYER M4 ;
        RECT  11.688 11.52 11.88 11.544 ;
    END
  END q[58]
  PIN q[59]
    DIRECTION OUTPUT ;
    USE SIGNAL ;
    PORT
      LAYER M4 ;
        RECT  11.688 11.712 11.88 11.736 ;
    END
  END q[59]
  PIN q[5]
    DIRECTION OUTPUT ;
    USE SIGNAL ;
    PORT
      LAYER M4 ;
        RECT  11.688 1.344 11.88 1.368 ;
    END
  END q[5]
  PIN q[60]
    DIRECTION OUTPUT ;
    USE SIGNAL ;
    PORT
      LAYER M4 ;
        RECT  11.688 11.904 11.88 11.928 ;
    END
  END q[60]
  PIN q[61]
    DIRECTION OUTPUT ;
    USE SIGNAL ;
    PORT
      LAYER M4 ;
        RECT  11.688 12.096 11.88 12.12 ;
    END
  END q[61]
  PIN q[62]
    DIRECTION OUTPUT ;
    USE SIGNAL ;
    PORT
      LAYER M4 ;
        RECT  11.688 12.288 11.88 12.312 ;
    END
  END q[62]
  PIN q[63]
    DIRECTION OUTPUT ;
    USE SIGNAL ;
    PORT
      LAYER M4 ;
        RECT  11.688 12.48 11.88 12.504 ;
    END
  END q[63]
  PIN q[64]
    DIRECTION OUTPUT ;
    USE SIGNAL ;
    PORT
      LAYER M4 ;
        RECT  11.688 12.672 11.88 12.696 ;
    END
  END q[64]
  PIN q[65]
    DIRECTION OUTPUT ;
    USE SIGNAL ;
    PORT
      LAYER M4 ;
        RECT  11.688 12.864 11.88 12.888 ;
    END
  END q[65]
  PIN q[66]
    DIRECTION OUTPUT ;
    USE SIGNAL ;
    PORT
      LAYER M4 ;
        RECT  11.688 13.056 11.88 13.08 ;
    END
  END q[66]
  PIN q[67]
    DIRECTION OUTPUT ;
    USE SIGNAL ;
    PORT
      LAYER M4 ;
        RECT  11.688 13.248 11.88 13.272 ;
    END
  END q[67]
  PIN q[68]
    DIRECTION OUTPUT ;
    USE SIGNAL ;
    PORT
      LAYER M4 ;
        RECT  11.688 13.44 11.88 13.464 ;
    END
  END q[68]
  PIN q[69]
    DIRECTION OUTPUT ;
    USE SIGNAL ;
    PORT
      LAYER M4 ;
        RECT  11.688 13.632 11.88 13.656 ;
    END
  END q[69]
  PIN q[6]
    DIRECTION OUTPUT ;
    USE SIGNAL ;
    PORT
      LAYER M4 ;
        RECT  11.688 1.536 11.88 1.56 ;
    END
  END q[6]
  PIN q[70]
    DIRECTION OUTPUT ;
    USE SIGNAL ;
    PORT
      LAYER M4 ;
        RECT  11.688 13.824 11.88 13.848 ;
    END
  END q[70]
  PIN q[71]
    DIRECTION OUTPUT ;
    USE SIGNAL ;
    PORT
      LAYER M4 ;
        RECT  11.688 14.016 11.88 14.04 ;
    END
  END q[71]
  PIN q[72]
    DIRECTION OUTPUT ;
    USE SIGNAL ;
    PORT
      LAYER M4 ;
        RECT  11.688 14.208 11.88 14.232 ;
    END
  END q[72]
  PIN q[73]
    DIRECTION OUTPUT ;
    USE SIGNAL ;
    PORT
      LAYER M4 ;
        RECT  11.688 14.4 11.88 14.424 ;
    END
  END q[73]
  PIN q[74]
    DIRECTION OUTPUT ;
    USE SIGNAL ;
    PORT
      LAYER M4 ;
        RECT  11.688 14.592 11.88 14.616 ;
    END
  END q[74]
  PIN q[75]
    DIRECTION OUTPUT ;
    USE SIGNAL ;
    PORT
      LAYER M4 ;
        RECT  11.688 14.784 11.88 14.808 ;
    END
  END q[75]
  PIN q[76]
    DIRECTION OUTPUT ;
    USE SIGNAL ;
    PORT
      LAYER M4 ;
        RECT  11.688 14.976 11.88 15 ;
    END
  END q[76]
  PIN q[77]
    DIRECTION OUTPUT ;
    USE SIGNAL ;
    PORT
      LAYER M4 ;
        RECT  11.688 15.168 11.88 15.192 ;
    END
  END q[77]
  PIN q[78]
    DIRECTION OUTPUT ;
    USE SIGNAL ;
    PORT
      LAYER M4 ;
        RECT  11.688 15.36 11.88 15.384 ;
    END
  END q[78]
  PIN q[79]
    DIRECTION OUTPUT ;
    USE SIGNAL ;
    PORT
      LAYER M4 ;
        RECT  11.688 15.552 11.88 15.576 ;
    END
  END q[79]
  PIN q[7]
    DIRECTION OUTPUT ;
    USE SIGNAL ;
    PORT
      LAYER M4 ;
        RECT  11.688 1.728 11.88 1.752 ;
    END
  END q[7]
  PIN q[80]
    DIRECTION OUTPUT ;
    USE SIGNAL ;
    PORT
      LAYER M4 ;
        RECT  11.688 15.744 11.88 15.768 ;
    END
  END q[80]
  PIN q[81]
    DIRECTION OUTPUT ;
    USE SIGNAL ;
    PORT
      LAYER M4 ;
        RECT  11.688 15.936 11.88 15.96 ;
    END
  END q[81]
  PIN q[82]
    DIRECTION OUTPUT ;
    USE SIGNAL ;
    PORT
      LAYER M4 ;
        RECT  11.688 16.128 11.88 16.152 ;
    END
  END q[82]
  PIN q[83]
    DIRECTION OUTPUT ;
    USE SIGNAL ;
    PORT
      LAYER M4 ;
        RECT  11.688 16.32 11.88 16.344 ;
    END
  END q[83]
  PIN q[84]
    DIRECTION OUTPUT ;
    USE SIGNAL ;
    PORT
      LAYER M4 ;
        RECT  11.688 16.512 11.88 16.536 ;
    END
  END q[84]
  PIN q[85]
    DIRECTION OUTPUT ;
    USE SIGNAL ;
    PORT
      LAYER M4 ;
        RECT  11.688 16.704 11.88 16.728 ;
    END
  END q[85]
  PIN q[86]
    DIRECTION OUTPUT ;
    USE SIGNAL ;
    PORT
      LAYER M4 ;
        RECT  11.688 16.896 11.88 16.92 ;
    END
  END q[86]
  PIN q[87]
    DIRECTION OUTPUT ;
    USE SIGNAL ;
    PORT
      LAYER M4 ;
        RECT  11.688 17.088 11.88 17.112 ;
    END
  END q[87]
  PIN q[88]
    DIRECTION OUTPUT ;
    USE SIGNAL ;
    PORT
      LAYER M4 ;
        RECT  11.688 17.28 11.88 17.304 ;
    END
  END q[88]
  PIN q[89]
    DIRECTION OUTPUT ;
    USE SIGNAL ;
    PORT
      LAYER M4 ;
        RECT  11.688 17.472 11.88 17.496 ;
    END
  END q[89]
  PIN q[8]
    DIRECTION OUTPUT ;
    USE SIGNAL ;
    PORT
      LAYER M4 ;
        RECT  11.688 1.92 11.88 1.944 ;
    END
  END q[8]
  PIN q[90]
    DIRECTION OUTPUT ;
    USE SIGNAL ;
    PORT
      LAYER M4 ;
        RECT  11.688 17.664 11.88 17.688 ;
    END
  END q[90]
  PIN q[91]
    DIRECTION OUTPUT ;
    USE SIGNAL ;
    PORT
      LAYER M4 ;
        RECT  11.688 17.856 11.88 17.88 ;
    END
  END q[91]
  PIN q[92]
    DIRECTION OUTPUT ;
    USE SIGNAL ;
    PORT
      LAYER M4 ;
        RECT  11.688 18.048 11.88 18.072 ;
    END
  END q[92]
  PIN q[93]
    DIRECTION OUTPUT ;
    USE SIGNAL ;
    PORT
      LAYER M4 ;
        RECT  11.688 18.24 11.88 18.264 ;
    END
  END q[93]
  PIN q[94]
    DIRECTION OUTPUT ;
    USE SIGNAL ;
    PORT
      LAYER M4 ;
        RECT  11.688 18.432 11.88 18.456 ;
    END
  END q[94]
  PIN q[95]
    DIRECTION OUTPUT ;
    USE SIGNAL ;
    PORT
      LAYER M4 ;
        RECT  11.688 18.624 11.88 18.648 ;
    END
  END q[95]
  PIN q[96]
    DIRECTION OUTPUT ;
    USE SIGNAL ;
    PORT
      LAYER M4 ;
        RECT  11.688 18.816 11.88 18.84 ;
    END
  END q[96]
  PIN q[97]
    DIRECTION OUTPUT ;
    USE SIGNAL ;
    PORT
      LAYER M4 ;
        RECT  11.688 19.008 11.88 19.032 ;
    END
  END q[97]
  PIN q[98]
    DIRECTION OUTPUT ;
    USE SIGNAL ;
    PORT
      LAYER M4 ;
        RECT  11.688 19.2 11.88 19.224 ;
    END
  END q[98]
  PIN q[99]
    DIRECTION OUTPUT ;
    USE SIGNAL ;
    PORT
      LAYER M4 ;
        RECT  11.688 19.392 11.88 19.416 ;
    END
  END q[99]
  PIN q[9]
    DIRECTION OUTPUT ;
    USE SIGNAL ;
    PORT
      LAYER M4 ;
        RECT  11.688 2.112 11.88 2.136 ;
    END
  END q[9]
  PIN VDD
    DIRECTION INOUT ;
    USE POWER ;
    PORT
      LAYER M6 ;
        RECT  0.54 104.172 11.34 104.46 ;
        RECT  0.54 98.772 11.34 99.06 ;
        RECT  0.54 93.372 11.34 93.66 ;
        RECT  0.54 87.972 11.34 88.26 ;
        RECT  0.54 82.572 11.34 82.86 ;
        RECT  0.54 77.172 11.34 77.46 ;
        RECT  0.54 71.772 11.34 72.06 ;
        RECT  0.54 66.372 11.34 66.66 ;
        RECT  0.54 60.972 11.34 61.26 ;
        RECT  0.54 55.572 11.34 55.86 ;
        RECT  0.54 50.172 11.34 50.46 ;
        RECT  0.54 44.772 11.34 45.06 ;
        RECT  0.54 39.372 11.34 39.66 ;
        RECT  0.54 33.972 11.34 34.26 ;
        RECT  0.54 28.572 11.34 28.86 ;
        RECT  0.54 23.172 11.34 23.46 ;
        RECT  0.54 17.772 11.34 18.06 ;
        RECT  0.54 12.372 11.34 12.66 ;
        RECT  0.54 6.972 11.34 7.26 ;
        RECT  0.54 1.572 11.34 1.86 ;
    END
  END VDD
  PIN VSS
    DIRECTION INOUT ;
    USE GROUND ;
    PORT
      LAYER M6 ;
        RECT  0.54 103.596 11.34 103.884 ;
        RECT  0.54 98.196 11.34 98.484 ;
        RECT  0.54 92.796 11.34 93.084 ;
        RECT  0.54 87.396 11.34 87.684 ;
        RECT  0.54 81.996 11.34 82.284 ;
        RECT  0.54 76.596 11.34 76.884 ;
        RECT  0.54 71.196 11.34 71.484 ;
        RECT  0.54 65.796 11.34 66.084 ;
        RECT  0.54 60.396 11.34 60.684 ;
        RECT  0.54 54.996 11.34 55.284 ;
        RECT  0.54 49.596 11.34 49.884 ;
        RECT  0.54 44.196 11.34 44.484 ;
        RECT  0.54 38.796 11.34 39.084 ;
        RECT  0.54 33.396 11.34 33.684 ;
        RECT  0.54 27.996 11.34 28.284 ;
        RECT  0.54 22.596 11.34 22.884 ;
        RECT  0.54 17.196 11.34 17.484 ;
        RECT  0.54 11.796 11.34 12.084 ;
        RECT  0.54 6.396 11.34 6.684 ;
        RECT  0.54 0.996 11.34 1.284 ;
    END
  END VSS
  OBS
    LAYER RVTN ;
     RECT  0.54 0.54 11.34 0.675 ;
     RECT  0.54 0.945 11.34 1.215 ;
     RECT  0.54 1.485 11.34 1.755 ;
     RECT  0.54 2.025 11.34 2.295 ;
     RECT  0.54 2.565 11.34 2.835 ;
     RECT  0.54 3.105 11.34 3.375 ;
     RECT  0.54 3.645 11.34 3.915 ;
     RECT  0.54 4.185 11.34 4.455 ;
     RECT  0.54 4.725 11.34 4.995 ;
     RECT  0.54 5.265 11.34 5.535 ;
     RECT  0.54 5.805 11.34 6.075 ;
     RECT  0.54 6.345 11.34 6.615 ;
     RECT  0.54 6.885 11.34 7.155 ;
     RECT  0.54 7.425 11.34 7.695 ;
     RECT  0.54 7.965 11.34 8.235 ;
     RECT  0.54 8.505 11.34 8.775 ;
     RECT  0.54 9.045 11.34 9.315 ;
     RECT  0.54 9.585 11.34 9.855 ;
     RECT  0.54 10.125 11.34 10.395 ;
     RECT  0.54 10.665 11.34 10.935 ;
     RECT  0.54 11.205 11.34 11.475 ;
     RECT  0.54 11.745 11.34 12.015 ;
     RECT  0.54 12.285 11.34 12.555 ;
     RECT  0.54 12.825 11.34 13.095 ;
     RECT  0.54 13.365 11.34 13.635 ;
     RECT  0.54 13.905 11.34 14.175 ;
     RECT  0.54 14.445 11.34 14.715 ;
     RECT  0.54 14.985 11.34 15.255 ;
     RECT  0.54 15.525 11.34 15.795 ;
     RECT  0.54 16.065 11.34 16.335 ;
     RECT  0.54 16.605 11.34 16.875 ;
     RECT  0.54 17.145 11.34 17.415 ;
     RECT  0.54 17.685 11.34 17.955 ;
     RECT  0.54 18.225 11.34 18.495 ;
     RECT  0.54 18.765 11.34 19.035 ;
     RECT  0.54 19.305 11.34 19.575 ;
     RECT  0.54 19.845 11.34 20.115 ;
     RECT  0.54 20.385 11.34 20.655 ;
     RECT  0.54 20.925 11.34 21.195 ;
     RECT  0.54 21.465 11.34 21.735 ;
     RECT  0.54 22.005 11.34 22.275 ;
     RECT  0.54 22.545 11.34 22.815 ;
     RECT  0.54 23.085 11.34 23.355 ;
     RECT  0.54 23.625 11.34 23.895 ;
     RECT  0.54 24.165 11.34 24.435 ;
     RECT  0.54 24.705 11.34 24.975 ;
     RECT  0.54 25.245 11.34 25.515 ;
     RECT  0.54 25.785 11.34 26.055 ;
     RECT  0.54 26.325 11.34 26.595 ;
     RECT  0.54 26.865 11.34 27.135 ;
     RECT  0.54 27.405 11.34 27.675 ;
     RECT  0.54 27.945 11.34 28.215 ;
     RECT  0.54 28.485 11.34 28.755 ;
     RECT  0.54 29.025 11.34 29.295 ;
     RECT  0.54 29.565 11.34 29.835 ;
     RECT  0.54 30.105 11.34 30.375 ;
     RECT  0.54 30.645 11.34 30.915 ;
     RECT  0.54 31.185 11.34 31.455 ;
     RECT  0.54 31.725 11.34 31.995 ;
     RECT  0.54 32.265 11.34 32.535 ;
     RECT  0.54 32.805 11.34 33.075 ;
     RECT  0.54 33.345 11.34 33.615 ;
     RECT  0.54 33.885 11.34 34.155 ;
     RECT  0.54 34.425 11.34 34.695 ;
     RECT  0.54 34.965 11.34 35.235 ;
     RECT  0.54 35.505 11.34 35.775 ;
     RECT  0.54 36.045 11.34 36.315 ;
     RECT  0.54 36.585 11.34 36.855 ;
     RECT  0.54 37.125 11.34 37.395 ;
     RECT  0.54 37.665 11.34 37.935 ;
     RECT  0.54 38.205 11.34 38.475 ;
     RECT  0.54 38.745 11.34 39.015 ;
     RECT  0.54 39.285 11.34 39.555 ;
     RECT  0.54 39.825 11.34 40.095 ;
     RECT  0.54 40.365 11.34 40.635 ;
     RECT  0.54 40.905 11.34 41.175 ;
     RECT  0.54 41.445 11.34 41.715 ;
     RECT  0.54 41.985 11.34 42.255 ;
     RECT  0.54 42.525 11.34 42.795 ;
     RECT  0.54 43.065 11.34 43.335 ;
     RECT  0.54 43.605 11.34 43.875 ;
     RECT  0.54 44.145 11.34 44.415 ;
     RECT  0.54 44.685 11.34 44.955 ;
     RECT  0.54 45.225 11.34 45.495 ;
     RECT  0.54 45.765 11.34 46.035 ;
     RECT  0.54 46.305 11.34 46.575 ;
     RECT  0.54 46.845 11.34 47.115 ;
     RECT  0.54 47.385 11.34 47.655 ;
     RECT  0.54 47.925 11.34 48.195 ;
     RECT  0.54 48.465 11.34 48.735 ;
     RECT  0.54 49.005 11.34 49.275 ;
     RECT  0.54 49.545 11.34 49.815 ;
     RECT  0.54 50.085 11.34 50.355 ;
     RECT  0.54 50.625 11.34 50.895 ;
     RECT  0.54 51.165 11.34 51.435 ;
     RECT  0.54 51.705 11.34 51.975 ;
     RECT  0.54 52.245 11.34 52.515 ;
     RECT  0.54 52.785 11.34 53.055 ;
     RECT  0.54 53.325 11.34 53.595 ;
     RECT  0.54 53.865 11.34 54.135 ;
     RECT  0.54 54.405 11.34 54.675 ;
     RECT  0.54 54.945 11.34 55.215 ;
     RECT  0.54 55.485 11.34 55.755 ;
     RECT  0.54 56.025 11.34 56.295 ;
     RECT  0.54 56.565 11.34 56.835 ;
     RECT  0.54 57.105 11.34 57.375 ;
     RECT  0.54 57.645 11.34 57.915 ;
     RECT  0.54 58.185 11.34 58.455 ;
     RECT  0.54 58.725 11.34 58.995 ;
     RECT  0.54 59.265 11.34 59.535 ;
     RECT  0.54 59.805 11.34 60.075 ;
     RECT  0.54 60.345 11.34 60.615 ;
     RECT  0.54 60.885 11.34 61.155 ;
     RECT  0.54 61.425 11.34 61.695 ;
     RECT  0.54 61.965 11.34 62.235 ;
     RECT  0.54 62.505 11.34 62.775 ;
     RECT  0.54 63.045 11.34 63.315 ;
     RECT  0.54 63.585 11.34 63.855 ;
     RECT  0.54 64.125 11.34 64.395 ;
     RECT  0.54 64.665 11.34 64.935 ;
     RECT  0.54 65.205 11.34 65.475 ;
     RECT  0.54 65.745 11.34 66.015 ;
     RECT  0.54 66.285 11.34 66.555 ;
     RECT  0.54 66.825 11.34 67.095 ;
     RECT  0.54 67.365 11.34 67.635 ;
     RECT  0.54 67.905 11.34 68.175 ;
     RECT  0.54 68.445 11.34 68.715 ;
     RECT  0.54 68.985 11.34 69.255 ;
     RECT  0.54 69.525 11.34 69.795 ;
     RECT  0.54 70.065 11.34 70.335 ;
     RECT  0.54 70.605 11.34 70.875 ;
     RECT  0.54 71.145 11.34 71.415 ;
     RECT  0.54 71.685 11.34 71.955 ;
     RECT  0.54 72.225 11.34 72.495 ;
     RECT  0.54 72.765 11.34 73.035 ;
     RECT  0.54 73.305 11.34 73.575 ;
     RECT  0.54 73.845 11.34 74.115 ;
     RECT  0.54 74.385 11.34 74.655 ;
     RECT  0.54 74.925 11.34 75.195 ;
     RECT  0.54 75.465 11.34 75.735 ;
     RECT  0.54 76.005 11.34 76.275 ;
     RECT  0.54 76.545 11.34 76.815 ;
     RECT  0.54 77.085 11.34 77.355 ;
     RECT  0.54 77.625 11.34 77.895 ;
     RECT  0.54 78.165 11.34 78.435 ;
     RECT  0.54 78.705 11.34 78.975 ;
     RECT  0.54 79.245 11.34 79.515 ;
     RECT  0.54 79.785 11.34 80.055 ;
     RECT  0.54 80.325 11.34 80.595 ;
     RECT  0.54 80.865 11.34 81.135 ;
     RECT  0.54 81.405 11.34 81.675 ;
     RECT  0.54 81.945 11.34 82.215 ;
     RECT  0.54 82.485 11.34 82.755 ;
     RECT  0.54 83.025 11.34 83.295 ;
     RECT  0.54 83.565 11.34 83.835 ;
     RECT  0.54 84.105 11.34 84.375 ;
     RECT  0.54 84.645 11.34 84.915 ;
     RECT  0.54 85.185 11.34 85.455 ;
     RECT  0.54 85.725 11.34 85.995 ;
     RECT  0.54 86.265 11.34 86.535 ;
     RECT  0.54 86.805 11.34 87.075 ;
     RECT  0.54 87.345 11.34 87.615 ;
     RECT  0.54 87.885 11.34 88.155 ;
     RECT  0.54 88.425 11.34 88.695 ;
     RECT  0.54 88.965 11.34 89.235 ;
     RECT  0.54 89.505 11.34 89.775 ;
     RECT  0.54 90.045 11.34 90.315 ;
     RECT  0.54 90.585 11.34 90.855 ;
     RECT  0.54 91.125 11.34 91.395 ;
     RECT  0.54 91.665 11.34 91.935 ;
     RECT  0.54 92.205 11.34 92.475 ;
     RECT  0.54 92.745 11.34 93.015 ;
     RECT  0.54 93.285 11.34 93.555 ;
     RECT  0.54 93.825 11.34 94.095 ;
     RECT  0.54 94.365 11.34 94.635 ;
     RECT  0.54 94.905 11.34 95.175 ;
     RECT  0.54 95.445 11.34 95.715 ;
     RECT  0.54 95.985 11.34 96.255 ;
     RECT  0.54 96.525 11.34 96.795 ;
     RECT  0.54 97.065 11.34 97.335 ;
     RECT  0.54 97.605 11.34 97.875 ;
     RECT  0.54 98.145 11.34 98.415 ;
     RECT  0.54 98.685 11.34 98.955 ;
     RECT  0.54 99.225 11.34 99.495 ;
     RECT  0.54 99.765 11.34 100.035 ;
     RECT  0.54 100.305 11.34 100.575 ;
     RECT  0.54 100.845 11.34 101.115 ;
     RECT  0.54 101.385 11.34 101.655 ;
     RECT  0.54 101.925 11.34 102.195 ;
     RECT  0.54 102.465 11.34 102.735 ;
     RECT  0.54 103.005 11.34 103.275 ;
     RECT  0.54 103.545 11.34 103.815 ;
     RECT  0.54 104.085 11.34 104.355 ;
     RECT  0.54 104.625 11.34 104.895 ;
     RECT  0.54 105.165 11.34 105.3 ;
    LAYER RVTP ;
     RECT  0.54 0.675 11.34 0.945 ;
     RECT  0.54 1.215 11.34 1.485 ;
     RECT  0.54 1.755 11.34 2.025 ;
     RECT  0.54 2.295 11.34 2.565 ;
     RECT  0.54 2.835 11.34 3.105 ;
     RECT  0.54 3.375 11.34 3.645 ;
     RECT  0.54 3.915 11.34 4.185 ;
     RECT  0.54 4.455 11.34 4.725 ;
     RECT  0.54 4.995 11.34 5.265 ;
     RECT  0.54 5.535 11.34 5.805 ;
     RECT  0.54 6.075 11.34 6.345 ;
     RECT  0.54 6.615 11.34 6.885 ;
     RECT  0.54 7.155 11.34 7.425 ;
     RECT  0.54 7.695 11.34 7.965 ;
     RECT  0.54 8.235 11.34 8.505 ;
     RECT  0.54 8.775 11.34 9.045 ;
     RECT  0.54 9.315 11.34 9.585 ;
     RECT  0.54 9.855 11.34 10.125 ;
     RECT  0.54 10.395 11.34 10.665 ;
     RECT  0.54 10.935 11.34 11.205 ;
     RECT  0.54 11.475 11.34 11.745 ;
     RECT  0.54 12.015 11.34 12.285 ;
     RECT  0.54 12.555 11.34 12.825 ;
     RECT  0.54 13.095 11.34 13.365 ;
     RECT  0.54 13.635 11.34 13.905 ;
     RECT  0.54 14.175 11.34 14.445 ;
     RECT  0.54 14.715 11.34 14.985 ;
     RECT  0.54 15.255 11.34 15.525 ;
     RECT  0.54 15.795 11.34 16.065 ;
     RECT  0.54 16.335 11.34 16.605 ;
     RECT  0.54 16.875 11.34 17.145 ;
     RECT  0.54 17.415 11.34 17.685 ;
     RECT  0.54 17.955 11.34 18.225 ;
     RECT  0.54 18.495 11.34 18.765 ;
     RECT  0.54 19.035 11.34 19.305 ;
     RECT  0.54 19.575 11.34 19.845 ;
     RECT  0.54 20.115 11.34 20.385 ;
     RECT  0.54 20.655 11.34 20.925 ;
     RECT  0.54 21.195 11.34 21.465 ;
     RECT  0.54 21.735 11.34 22.005 ;
     RECT  0.54 22.275 11.34 22.545 ;
     RECT  0.54 22.815 11.34 23.085 ;
     RECT  0.54 23.355 11.34 23.625 ;
     RECT  0.54 23.895 11.34 24.165 ;
     RECT  0.54 24.435 11.34 24.705 ;
     RECT  0.54 24.975 11.34 25.245 ;
     RECT  0.54 25.515 11.34 25.785 ;
     RECT  0.54 26.055 11.34 26.325 ;
     RECT  0.54 26.595 11.34 26.865 ;
     RECT  0.54 27.135 11.34 27.405 ;
     RECT  0.54 27.675 11.34 27.945 ;
     RECT  0.54 28.215 11.34 28.485 ;
     RECT  0.54 28.755 11.34 29.025 ;
     RECT  0.54 29.295 11.34 29.565 ;
     RECT  0.54 29.835 11.34 30.105 ;
     RECT  0.54 30.375 11.34 30.645 ;
     RECT  0.54 30.915 11.34 31.185 ;
     RECT  0.54 31.455 11.34 31.725 ;
     RECT  0.54 31.995 11.34 32.265 ;
     RECT  0.54 32.535 11.34 32.805 ;
     RECT  0.54 33.075 11.34 33.345 ;
     RECT  0.54 33.615 11.34 33.885 ;
     RECT  0.54 34.155 11.34 34.425 ;
     RECT  0.54 34.695 11.34 34.965 ;
     RECT  0.54 35.235 11.34 35.505 ;
     RECT  0.54 35.775 11.34 36.045 ;
     RECT  0.54 36.315 11.34 36.585 ;
     RECT  0.54 36.855 11.34 37.125 ;
     RECT  0.54 37.395 11.34 37.665 ;
     RECT  0.54 37.935 11.34 38.205 ;
     RECT  0.54 38.475 11.34 38.745 ;
     RECT  0.54 39.015 11.34 39.285 ;
     RECT  0.54 39.555 11.34 39.825 ;
     RECT  0.54 40.095 11.34 40.365 ;
     RECT  0.54 40.635 11.34 40.905 ;
     RECT  0.54 41.175 11.34 41.445 ;
     RECT  0.54 41.715 11.34 41.985 ;
     RECT  0.54 42.255 11.34 42.525 ;
     RECT  0.54 42.795 11.34 43.065 ;
     RECT  0.54 43.335 11.34 43.605 ;
     RECT  0.54 43.875 11.34 44.145 ;
     RECT  0.54 44.415 11.34 44.685 ;
     RECT  0.54 44.955 11.34 45.225 ;
     RECT  0.54 45.495 11.34 45.765 ;
     RECT  0.54 46.035 11.34 46.305 ;
     RECT  0.54 46.575 11.34 46.845 ;
     RECT  0.54 47.115 11.34 47.385 ;
     RECT  0.54 47.655 11.34 47.925 ;
     RECT  0.54 48.195 11.34 48.465 ;
     RECT  0.54 48.735 11.34 49.005 ;
     RECT  0.54 49.275 11.34 49.545 ;
     RECT  0.54 49.815 11.34 50.085 ;
     RECT  0.54 50.355 11.34 50.625 ;
     RECT  0.54 50.895 11.34 51.165 ;
     RECT  0.54 51.435 11.34 51.705 ;
     RECT  0.54 51.975 11.34 52.245 ;
     RECT  0.54 52.515 11.34 52.785 ;
     RECT  0.54 53.055 11.34 53.325 ;
     RECT  0.54 53.595 11.34 53.865 ;
     RECT  0.54 54.135 11.34 54.405 ;
     RECT  0.54 54.675 11.34 54.945 ;
     RECT  0.54 55.215 11.34 55.485 ;
     RECT  0.54 55.755 11.34 56.025 ;
     RECT  0.54 56.295 11.34 56.565 ;
     RECT  0.54 56.835 11.34 57.105 ;
     RECT  0.54 57.375 11.34 57.645 ;
     RECT  0.54 57.915 11.34 58.185 ;
     RECT  0.54 58.455 11.34 58.725 ;
     RECT  0.54 58.995 11.34 59.265 ;
     RECT  0.54 59.535 11.34 59.805 ;
     RECT  0.54 60.075 11.34 60.345 ;
     RECT  0.54 60.615 11.34 60.885 ;
     RECT  0.54 61.155 11.34 61.425 ;
     RECT  0.54 61.695 11.34 61.965 ;
     RECT  0.54 62.235 11.34 62.505 ;
     RECT  0.54 62.775 11.34 63.045 ;
     RECT  0.54 63.315 11.34 63.585 ;
     RECT  0.54 63.855 11.34 64.125 ;
     RECT  0.54 64.395 11.34 64.665 ;
     RECT  0.54 64.935 11.34 65.205 ;
     RECT  0.54 65.475 11.34 65.745 ;
     RECT  0.54 66.015 11.34 66.285 ;
     RECT  0.54 66.555 11.34 66.825 ;
     RECT  0.54 67.095 11.34 67.365 ;
     RECT  0.54 67.635 11.34 67.905 ;
     RECT  0.54 68.175 11.34 68.445 ;
     RECT  0.54 68.715 11.34 68.985 ;
     RECT  0.54 69.255 11.34 69.525 ;
     RECT  0.54 69.795 11.34 70.065 ;
     RECT  0.54 70.335 11.34 70.605 ;
     RECT  0.54 70.875 11.34 71.145 ;
     RECT  0.54 71.415 11.34 71.685 ;
     RECT  0.54 71.955 11.34 72.225 ;
     RECT  0.54 72.495 11.34 72.765 ;
     RECT  0.54 73.035 11.34 73.305 ;
     RECT  0.54 73.575 11.34 73.845 ;
     RECT  0.54 74.115 11.34 74.385 ;
     RECT  0.54 74.655 11.34 74.925 ;
     RECT  0.54 75.195 11.34 75.465 ;
     RECT  0.54 75.735 11.34 76.005 ;
     RECT  0.54 76.275 11.34 76.545 ;
     RECT  0.54 76.815 11.34 77.085 ;
     RECT  0.54 77.355 11.34 77.625 ;
     RECT  0.54 77.895 11.34 78.165 ;
     RECT  0.54 78.435 11.34 78.705 ;
     RECT  0.54 78.975 11.34 79.245 ;
     RECT  0.54 79.515 11.34 79.785 ;
     RECT  0.54 80.055 11.34 80.325 ;
     RECT  0.54 80.595 11.34 80.865 ;
     RECT  0.54 81.135 11.34 81.405 ;
     RECT  0.54 81.675 11.34 81.945 ;
     RECT  0.54 82.215 11.34 82.485 ;
     RECT  0.54 82.755 11.34 83.025 ;
     RECT  0.54 83.295 11.34 83.565 ;
     RECT  0.54 83.835 11.34 84.105 ;
     RECT  0.54 84.375 11.34 84.645 ;
     RECT  0.54 84.915 11.34 85.185 ;
     RECT  0.54 85.455 11.34 85.725 ;
     RECT  0.54 85.995 11.34 86.265 ;
     RECT  0.54 86.535 11.34 86.805 ;
     RECT  0.54 87.075 11.34 87.345 ;
     RECT  0.54 87.615 11.34 87.885 ;
     RECT  0.54 88.155 11.34 88.425 ;
     RECT  0.54 88.695 11.34 88.965 ;
     RECT  0.54 89.235 11.34 89.505 ;
     RECT  0.54 89.775 11.34 90.045 ;
     RECT  0.54 90.315 11.34 90.585 ;
     RECT  0.54 90.855 11.34 91.125 ;
     RECT  0.54 91.395 11.34 91.665 ;
     RECT  0.54 91.935 11.34 92.205 ;
     RECT  0.54 92.475 11.34 92.745 ;
     RECT  0.54 93.015 11.34 93.285 ;
     RECT  0.54 93.555 11.34 93.825 ;
     RECT  0.54 94.095 11.34 94.365 ;
     RECT  0.54 94.635 11.34 94.905 ;
     RECT  0.54 95.175 11.34 95.445 ;
     RECT  0.54 95.715 11.34 95.985 ;
     RECT  0.54 96.255 11.34 96.525 ;
     RECT  0.54 96.795 11.34 97.065 ;
     RECT  0.54 97.335 11.34 97.605 ;
     RECT  0.54 97.875 11.34 98.145 ;
     RECT  0.54 98.415 11.34 98.685 ;
     RECT  0.54 98.955 11.34 99.225 ;
     RECT  0.54 99.495 11.34 99.765 ;
     RECT  0.54 100.035 11.34 100.305 ;
     RECT  0.54 100.575 11.34 100.845 ;
     RECT  0.54 101.115 11.34 101.385 ;
     RECT  0.54 101.655 11.34 101.925 ;
     RECT  0.54 102.195 11.34 102.465 ;
     RECT  0.54 102.735 11.34 103.005 ;
     RECT  0.54 103.275 11.34 103.545 ;
     RECT  0.54 103.815 11.34 104.085 ;
     RECT  0.54 104.355 11.34 104.625 ;
     RECT  0.54 104.895 11.34 105.165 ;
    LAYER M1 ;
     RECT  0.54 0.531 11.34 105.309 ;
    LAYER M2 ;
     RECT  0.211 0.612 0.247 6.84 ;
     RECT  0.211 7.902 0.247 10.35 ;
     RECT  0.211 11.142 0.247 22.572 ;
     RECT  0.211 26.874 0.247 58.95 ;
     RECT  0.211 59.742 0.247 59.832 ;
     RECT  0.211 61.092 0.247 84.132 ;
     RECT  0.211 85.122 0.247 87.408 ;
     RECT  0.211 88.74 0.247 90.54 ;
     RECT  0.211 91.602 0.247 97.56 ;
     RECT  0.211 98.352 0.247 101.07 ;
     RECT  0.211 104.67 0.499 104.688 ;
     RECT  0.247 0.612 0.535 22.572 ;
     RECT  0.211 23.634 0.535 26.01 ;
     RECT  0.247 26.874 0.535 87.408 ;
     RECT  0.247 88.74 0.535 101.07 ;
     RECT  0.211 102.132 0.535 102.15 ;
     RECT  0.211 102.942 0.535 103.302 ;
     RECT  0.499 104.256 0.535 104.688 ;
     RECT  0.535 0.612 0.54 26.01 ;
     RECT  0.535 26.874 0.54 104.688 ;
     RECT  0.54 0.531 11.34 105.309 ;
     RECT  11.34 50.796 11.687 50.814 ;
     RECT  11.34 3.42 11.759 3.438 ;
     RECT  11.34 12.636 11.759 12.654 ;
     RECT  11.34 28.611 11.759 28.629 ;
     RECT  11.34 35.946 11.759 35.964 ;
     RECT  11.34 46.62 11.759 46.638 ;
     RECT  11.34 79.83 11.759 79.848 ;
     RECT  11.34 104.211 11.759 104.229 ;
    LAYER M3 ;
     RECT  0.795 0.523 0.885 0.571 ;
     RECT  2.088 0.379 2.106 0.635 ;
     RECT  5.4 0.607 5.418 0.751 ;
     RECT  6.195 0.523 6.285 0.751 ;
     RECT  10.836 0.379 10.854 0.751 ;
     RECT  0.216 0.571 0.885 0.793 ;
     RECT  10.836 0.751 10.89 0.797 ;
     RECT  8.532 0.571 9.234 0.869 ;
     RECT  5.4 0.751 6.93 0.877 ;
     RECT  0.216 0.793 1.077 0.913 ;
     RECT  5.4 0.877 7.002 0.977 ;
     RECT  2.844 0.913 2.862 0.985 ;
     RECT  5.4 0.977 6.93 1.111 ;
     RECT  5.256 1.111 6.93 1.139 ;
     RECT  5.256 1.139 5.274 1.181 ;
     RECT  2.7 0.985 2.862 1.381 ;
     RECT  3.6 1.183 3.618 1.381 ;
     RECT  0.216 0.913 1.782 1.453 ;
     RECT  2.7 1.381 3.618 1.453 ;
     RECT  10.836 0.797 10.854 1.531 ;
     RECT  0.216 1.453 3.618 1.553 ;
     RECT  2.376 1.553 3.618 1.589 ;
     RECT  10.188 1.531 10.854 1.589 ;
     RECT  10.368 1.589 10.854 1.651 ;
     RECT  2.916 1.589 3.618 1.679 ;
     RECT  4.572 1.525 4.59 1.679 ;
     RECT  3.6 1.679 3.618 1.709 ;
     RECT  0.216 1.553 1.458 1.715 ;
     RECT  6.195 1.139 6.93 1.715 ;
     RECT  5.328 2.227 5.346 2.285 ;
     RECT  7.812 1.795 7.83 2.285 ;
     RECT  10.368 1.651 10.926 2.333 ;
     RECT  6.195 1.715 6.858 2.461 ;
     RECT  10.872 2.333 10.926 2.525 ;
     RECT  8.82 0.869 8.838 2.569 ;
     RECT  6.195 2.461 6.93 2.669 ;
     RECT  8.568 2.569 8.838 2.759 ;
     RECT  10.872 2.525 10.89 2.759 ;
     RECT  8.64 2.759 8.838 2.767 ;
     RECT  8.64 2.767 9.198 2.861 ;
     RECT  3.852 2.803 3.87 2.909 ;
     RECT  9.18 2.861 9.198 2.909 ;
     RECT  10.8 3.064 10.854 3.101 ;
     RECT  0.216 1.715 1.077 3.109 ;
     RECT  3.384 3.109 3.402 3.181 ;
     RECT  4.608 3.145 4.626 3.181 ;
     RECT  0.216 3.109 1.422 3.259 ;
     RECT  3.096 3.181 3.402 3.299 ;
     RECT  4.536 3.181 4.77 3.299 ;
     RECT  4.536 3.299 4.626 3.335 ;
     RECT  3.204 3.299 3.222 3.389 ;
     RECT  4.608 3.335 4.626 3.389 ;
     RECT  6.195 2.669 6.477 3.403 ;
     RECT  11.736 3.403 11.754 3.415 ;
     RECT  11.664 3.415 11.754 3.443 ;
     RECT  0.216 3.259 1.746 3.451 ;
     RECT  11.664 3.443 11.682 3.485 ;
     RECT  0.216 3.451 1.854 3.685 ;
     RECT  0.216 3.685 1.998 3.713 ;
     RECT  7.632 3.721 7.65 3.811 ;
     RECT  7.632 3.811 8.262 3.839 ;
     RECT  9.648 3.835 9.666 3.875 ;
     RECT  8.244 3.839 8.262 3.947 ;
     RECT  1.836 3.713 1.998 3.965 ;
     RECT  6.12 3.403 6.477 3.983 ;
     RECT  1.836 3.965 1.962 4.019 ;
     RECT  9.684 3.919 9.702 4.061 ;
     RECT  6.195 3.983 6.477 4.081 ;
     RECT  6.195 4.081 6.858 4.253 ;
     RECT  10.836 3.101 10.854 4.351 ;
     RECT  10.512 4.351 10.854 4.445 ;
     RECT  6.195 4.253 6.786 4.451 ;
     RECT  10.692 4.445 10.854 4.637 ;
     RECT  9.828 4.531 9.846 4.649 ;
     RECT  7.812 4.651 7.83 4.691 ;
     RECT  8.784 4.075 8.802 4.765 ;
     RECT  6.195 4.451 6.606 4.793 ;
     RECT  8.784 4.765 9.054 4.793 ;
     RECT  10.836 4.637 10.854 4.795 ;
     RECT  0.216 3.713 1.077 4.801 ;
     RECT  10.836 4.795 11.142 4.835 ;
     RECT  9.036 4.793 9.054 4.891 ;
     RECT  1.944 4.019 1.962 4.987 ;
     RECT  2.844 4.387 2.862 4.987 ;
     RECT  6.195 4.793 6.534 4.991 ;
     RECT  9.036 4.891 9.702 4.991 ;
     RECT  9.684 4.991 9.702 5.021 ;
     RECT  1.944 4.987 2.862 5.035 ;
     RECT  1.944 5.035 3.078 5.083 ;
     RECT  1.872 5.083 3.078 5.117 ;
     RECT  0.216 4.801 1.098 5.161 ;
     RECT  1.872 5.117 2.646 5.161 ;
     RECT  0.216 5.161 2.646 5.189 ;
     RECT  6.195 4.991 6.477 5.269 ;
     RECT  5.652 5.269 6.477 5.369 ;
     RECT  5.724 5.369 6.477 5.405 ;
     RECT  3.384 5.575 3.402 5.645 ;
     RECT  8.1 5.701 8.118 5.707 ;
     RECT  10.836 4.835 10.89 5.755 ;
     RECT  10.332 5.755 10.89 5.801 ;
     RECT  6.195 5.405 6.477 5.809 ;
     RECT  8.1 5.707 8.55 5.845 ;
     RECT  3.6 5.809 3.618 5.909 ;
     RECT  0.216 5.189 1.638 5.999 ;
     RECT  7.956 5.845 8.55 5.999 ;
     RECT  10.764 5.801 10.89 6.043 ;
     RECT  6.195 5.809 6.858 6.079 ;
     RECT  2.556 5.189 2.646 6.151 ;
     RECT  8.532 5.999 8.55 6.151 ;
     RECT  2.196 6.151 2.646 6.269 ;
     RECT  6.195 6.079 7.002 6.269 ;
     RECT  6.195 6.269 6.786 6.341 ;
     RECT  8.532 6.151 8.694 6.349 ;
     RECT  8.532 6.349 8.802 6.377 ;
     RECT  4.572 6.379 4.59 6.419 ;
     RECT  2.34 6.269 2.646 6.656 ;
     RECT  10.764 6.043 10.926 7.087 ;
     RECT  10.224 7.087 10.926 7.133 ;
     RECT  6.195 6.341 6.477 7.159 ;
     RECT  8.784 6.377 8.802 7.159 ;
     RECT  6.195 7.159 6.858 7.195 ;
     RECT  10.224 7.133 10.674 7.195 ;
     RECT  8.784 7.159 8.946 7.231 ;
     RECT  9.9 7.195 10.674 7.231 ;
     RECT  2.376 6.656 2.646 7.321 ;
     RECT  8.64 7.231 8.946 7.349 ;
     RECT  9.792 7.231 10.674 7.349 ;
     RECT  7.704 7.339 7.722 7.385 ;
     RECT  8.784 7.349 8.946 7.385 ;
     RECT  0.216 5.999 1.077 7.393 ;
     RECT  2.376 7.321 2.826 7.421 ;
     RECT  5.544 7.195 6.858 7.421 ;
     RECT  5.76 7.421 6.858 7.501 ;
     RECT  3.636 7.501 3.654 7.619 ;
     RECT  5.76 7.501 7.11 7.619 ;
     RECT  10.224 7.349 10.674 7.709 ;
     RECT  2.376 7.421 2.79 7.771 ;
     RECT  2.268 7.771 2.79 7.799 ;
     RECT  9.144 7.771 9.162 7.901 ;
     RECT  10.26 7.709 10.674 7.933 ;
     RECT  5.76 7.619 6.477 7.949 ;
     RECT  2.268 7.799 2.61 7.963 ;
     RECT  5.904 7.949 6.477 8.069 ;
     RECT  2.088 7.963 2.61 8.159 ;
     RECT  0.216 7.393 1.134 8.437 ;
     RECT  2.088 8.159 2.466 8.437 ;
     RECT  0.216 8.437 2.466 8.525 ;
     RECT  10.26 7.933 10.854 8.806 ;
     RECT  5.148 8.581 5.166 8.815 ;
     RECT  10.224 8.806 10.854 8.861 ;
     RECT  2.124 8.525 2.466 8.909 ;
     RECT  5.004 8.815 5.166 8.941 ;
     RECT  7.38 8.851 7.866 8.941 ;
     RECT  7.38 8.941 7.938 9.041 ;
     RECT  6.195 8.069 6.477 9.085 ;
     RECT  5.004 8.941 5.238 9.113 ;
     RECT  3.816 9.115 3.834 9.121 ;
     RECT  5.004 9.113 5.022 9.121 ;
     RECT  3.816 9.121 5.022 9.149 ;
     RECT  2.232 8.909 2.466 9.239 ;
     RECT  3.816 9.149 4.338 9.239 ;
     RECT  2.232 9.239 2.25 9.275 ;
     RECT  0.216 8.525 1.098 9.349 ;
     RECT  0.216 9.349 1.242 9.389 ;
     RECT  6.195 9.085 6.678 9.389 ;
     RECT  7.668 9.041 7.902 9.419 ;
     RECT  6.195 9.389 6.477 9.517 ;
     RECT  3.816 9.239 3.834 9.545 ;
     RECT  6.156 9.517 6.477 9.689 ;
     RECT  10.836 8.861 10.854 9.751 ;
     RECT  10.296 9.751 10.854 9.787 ;
     RECT  10.296 9.787 11.214 9.824 ;
     RECT  7.812 9.419 7.902 9.851 ;
     RECT  7.884 9.851 7.902 9.931 ;
     RECT  10.296 9.824 10.926 9.931 ;
     RECT  2.16 9.931 2.178 10.049 ;
     RECT  7.884 9.931 8.046 10.049 ;
     RECT  9.252 9.739 9.27 10.085 ;
     RECT  10.224 9.931 10.926 10.085 ;
     RECT  6.195 9.689 6.477 10.129 ;
     RECT  10.8 10.085 10.926 10.397 ;
     RECT  0.216 9.389 1.077 10.435 ;
     RECT  10.836 10.397 10.926 10.552 ;
     RECT  10.836 10.552 11.214 10.589 ;
     RECT  8.424 10.555 8.55 10.595 ;
     RECT  3.24 10.435 3.258 10.697 ;
     RECT  6.195 10.129 6.858 10.769 ;
     RECT  9.684 10.471 9.702 10.781 ;
     RECT  8.424 10.595 8.442 11.011 ;
     RECT  8.316 11.011 8.442 11.039 ;
     RECT  8.316 11.039 8.334 11.101 ;
     RECT  2.268 10.741 2.286 11.137 ;
     RECT  4.644 10.267 4.662 11.137 ;
     RECT  8.244 11.101 8.334 11.137 ;
     RECT  9.648 11.101 9.666 11.165 ;
     RECT  6.195 10.769 6.477 11.245 ;
     RECT  4.644 11.137 4.698 11.281 ;
     RECT  2.052 11.137 2.286 11.309 ;
     RECT  4.644 11.281 5.202 11.309 ;
     RECT  10.836 10.589 10.926 11.357 ;
     RECT  6.156 11.245 6.477 11.515 ;
     RECT  2.304 11.407 2.394 11.551 ;
     RECT  3.168 11.407 3.186 11.551 ;
     RECT  6.156 11.515 6.642 11.551 ;
     RECT  8.136 11.137 8.334 11.641 ;
     RECT  10.836 11.357 10.89 11.713 ;
     RECT  10.8 11.713 10.89 11.741 ;
     RECT  2.304 11.551 3.69 11.777 ;
     RECT  6.156 11.551 6.93 11.777 ;
     RECT  5.112 11.309 5.202 11.785 ;
     RECT  6.156 11.777 6.786 11.785 ;
     RECT  8.028 11.641 8.334 11.785 ;
     RECT  0.216 10.435 1.134 11.821 ;
     RECT  7.812 11.785 8.334 11.821 ;
     RECT  5.112 11.785 6.786 11.837 ;
     RECT  2.34 11.777 3.69 11.849 ;
     RECT  7.668 11.821 8.334 11.849 ;
     RECT  0.216 11.821 1.314 11.911 ;
     RECT  10.8 11.741 10.854 11.933 ;
     RECT  7.668 11.849 7.83 11.939 ;
     RECT  2.34 11.849 3.186 11.981 ;
     RECT  9.792 12.091 9.81 12.128 ;
     RECT  0.216 11.911 1.386 12.361 ;
     RECT  0.216 12.361 1.53 12.413 ;
     RECT  9.648 12.451 9.666 12.509 ;
     RECT  5.184 11.837 6.786 12.523 ;
     RECT  2.34 11.981 2.862 12.551 ;
     RECT  4.068 11.947 4.086 12.557 ;
     RECT  5.184 12.523 6.858 12.56 ;
     RECT  11.736 12.619 11.754 12.631 ;
     RECT  11.664 12.631 11.754 12.659 ;
     RECT  11.664 12.659 11.682 12.701 ;
     RECT  7.668 11.939 7.686 12.829 ;
     RECT  10.836 11.933 10.854 12.859 ;
     RECT  7.596 12.829 7.686 12.901 ;
     RECT  8.712 12.865 8.73 12.901 ;
     RECT  10.836 12.859 10.926 12.901 ;
     RECT  3.708 12.763 3.726 12.929 ;
     RECT  5.184 12.56 5.274 12.929 ;
     RECT  5.184 12.929 5.202 12.941 ;
     RECT  7.596 12.901 8.73 13.019 ;
     RECT  6.195 12.56 6.858 13.085 ;
     RECT  0.216 12.413 1.077 13.171 ;
     RECT  2.844 12.551 2.862 13.171 ;
     RECT  7.596 13.019 8.082 13.291 ;
     RECT  2.844 13.171 2.934 13.297 ;
     RECT  7.308 13.291 8.082 13.331 ;
     RECT  0.216 13.171 1.206 13.369 ;
     RECT  2.052 12.631 2.07 13.369 ;
     RECT  6.195 13.085 6.477 13.369 ;
     RECT  2.844 13.297 2.97 13.397 ;
     RECT  10.656 12.901 10.926 13.432 ;
     RECT  0.216 13.369 2.07 13.441 ;
     RECT  2.844 13.397 2.934 13.441 ;
     RECT  0.216 13.441 2.934 13.469 ;
     RECT  9.108 13.369 9.126 13.469 ;
     RECT  10.476 13.432 10.926 13.469 ;
     RECT  0.216 13.469 2.898 13.559 ;
     RECT  5.976 13.369 6.477 13.559 ;
     RECT  10.8 13.469 10.926 13.627 ;
     RECT  7.956 13.331 8.082 13.661 ;
     RECT  10.8 13.627 11.214 13.667 ;
     RECT  5.4 14.071 5.418 14.207 ;
     RECT  10.8 13.667 10.854 14.251 ;
     RECT  7.2 14.251 7.218 14.347 ;
     RECT  4.572 14.251 4.59 14.377 ;
     RECT  2.34 13.559 2.862 14.429 ;
     RECT  4.572 14.377 5.274 14.429 ;
     RECT  3.6 14.395 3.618 14.449 ;
     RECT  2.592 14.429 2.862 14.513 ;
     RECT  0.216 13.559 1.17 14.521 ;
     RECT  7.2 14.347 7.398 14.521 ;
     RECT  3.6 14.449 3.654 14.549 ;
     RECT  0.216 14.521 1.746 14.639 ;
     RECT  3.6 14.549 3.618 14.675 ;
     RECT  4.572 14.429 4.59 14.747 ;
     RECT  6.195 13.559 6.477 14.791 ;
     RECT  7.2 14.521 7.542 14.791 ;
     RECT  6.195 14.791 7.542 14.819 ;
     RECT  10.26 14.251 10.854 14.971 ;
     RECT  9.684 14.971 10.854 15.017 ;
     RECT  2.844 14.513 2.862 15.025 ;
     RECT  6.195 14.819 6.822 15.179 ;
     RECT  8.928 15.061 8.946 15.179 ;
     RECT  10.26 15.017 10.854 15.197 ;
     RECT  6.195 15.179 6.477 15.331 ;
     RECT  2.844 15.025 2.934 15.565 ;
     RECT  2.808 15.565 2.934 15.629 ;
     RECT  3.708 15.529 3.726 15.719 ;
     RECT  5.724 15.331 6.477 15.727 ;
     RECT  5.58 15.727 6.477 15.773 ;
     RECT  6.192 15.773 6.477 15.997 ;
     RECT  6.192 15.997 6.606 16.025 ;
     RECT  2.844 15.629 2.934 16.061 ;
     RECT  0.216 14.639 1.71 16.069 ;
     RECT  7.92 15.403 8.01 16.069 ;
     RECT  6.195 16.025 6.606 16.105 ;
     RECT  10.836 15.197 10.854 16.123 ;
     RECT  3.816 16.069 3.906 16.141 ;
     RECT  0.216 16.069 1.746 16.169 ;
     RECT  10.836 16.123 10.89 16.169 ;
     RECT  3.816 16.141 5.202 16.259 ;
     RECT  4.464 16.259 4.698 16.295 ;
     RECT  6.195 16.105 6.894 16.295 ;
     RECT  7.884 16.069 8.01 16.303 ;
     RECT  10.836 16.169 10.854 16.315 ;
     RECT  7.884 16.303 8.082 16.339 ;
     RECT  6.195 16.295 6.678 16.439 ;
     RECT  7.884 16.339 8.694 16.439 ;
     RECT  7.884 16.439 8.622 16.501 ;
     RECT  10.8 16.315 10.854 16.501 ;
     RECT  2.844 16.061 2.862 16.529 ;
     RECT  4.536 16.295 4.698 16.529 ;
     RECT  6.195 16.439 6.606 16.541 ;
     RECT  10.476 16.501 10.854 16.541 ;
     RECT  4.536 16.529 4.554 16.552 ;
     RECT  7.848 16.501 8.622 16.601 ;
     RECT  0.216 16.169 1.71 16.709 ;
     RECT  9.684 16.303 9.702 16.733 ;
     RECT  7.884 16.601 8.622 17.105 ;
     RECT  2.412 17.077 2.43 17.117 ;
     RECT  8.028 17.105 8.622 17.221 ;
     RECT  0.216 16.709 1.278 17.339 ;
     RECT  8.028 17.221 9.45 17.375 ;
     RECT  10.62 16.541 10.854 17.455 ;
     RECT  8.028 17.375 9.162 17.501 ;
     RECT  10.62 17.455 11.214 17.501 ;
     RECT  5.148 17.347 5.166 17.519 ;
     RECT  8.532 17.501 9.162 17.519 ;
     RECT  10.62 17.501 10.854 17.581 ;
     RECT  1.908 17.491 2.142 17.609 ;
     RECT  1.908 17.609 1.926 17.645 ;
     RECT  4.032 17.611 4.05 17.653 ;
     RECT  10.26 17.581 10.854 17.693 ;
     RECT  3.888 17.653 4.05 17.803 ;
     RECT  3.132 17.803 4.05 17.887 ;
     RECT  6.195 16.541 6.477 18.031 ;
     RECT  7.668 17.959 7.686 18.059 ;
     RECT  2.844 17.887 4.05 18.139 ;
     RECT  7.416 18.157 7.434 18.193 ;
     RECT  7.308 18.193 7.434 18.221 ;
     RECT  10.8 17.693 10.854 18.269 ;
     RECT  0.216 17.339 1.077 18.301 ;
     RECT  6.192 18.031 6.477 18.301 ;
     RECT  7.308 18.221 7.326 18.329 ;
     RECT  9.144 17.519 9.162 18.391 ;
     RECT  0.216 18.301 1.386 18.419 ;
     RECT  2.844 18.139 4.122 18.427 ;
     RECT  9.144 18.391 9.702 18.427 ;
     RECT  5.652 18.301 6.477 18.455 ;
     RECT  2.52 18.427 4.122 18.491 ;
     RECT  9.036 18.427 9.702 18.599 ;
     RECT  4.212 18.565 4.23 18.605 ;
     RECT  9.684 18.599 9.702 18.652 ;
     RECT  9.684 18.652 9.738 18.653 ;
     RECT  6.195 18.455 6.477 18.841 ;
     RECT  9.72 18.653 9.738 18.845 ;
     RECT  2.52 18.491 2.934 18.967 ;
     RECT  10.836 18.269 10.854 19.003 ;
     RECT  10.836 19.003 11.214 19.04 ;
     RECT  6.195 18.841 7.074 19.111 ;
     RECT  10.836 19.04 10.998 19.111 ;
     RECT  6.195 19.111 7.686 19.181 ;
     RECT  0.216 18.419 1.077 19.201 ;
     RECT  6.195 19.181 7.146 19.229 ;
     RECT  10.656 19.111 10.998 19.229 ;
     RECT  0.216 19.201 1.422 19.301 ;
     RECT  2.376 18.967 2.934 19.339 ;
     RECT  5.256 19.336 5.274 19.373 ;
     RECT  8.388 19.339 8.406 19.379 ;
     RECT  10.656 19.229 10.854 19.613 ;
     RECT  2.376 19.339 3.582 19.615 ;
     RECT  2.124 19.615 3.582 19.769 ;
     RECT  9.684 19.741 9.702 19.771 ;
     RECT  2.124 19.769 2.934 19.949 ;
     RECT  9.684 19.771 10.278 19.949 ;
     RECT  9.684 19.949 9.702 19.997 ;
     RECT  7.812 20.149 7.83 20.189 ;
     RECT  9.468 20.281 9.486 20.381 ;
     RECT  0.216 19.301 1.077 20.389 ;
     RECT  4.608 19.771 4.626 20.389 ;
     RECT  4.608 20.389 5.274 20.429 ;
     RECT  2.844 19.949 2.862 20.489 ;
     RECT  9 20.389 9.09 20.489 ;
     RECT  9.072 20.489 9.09 20.525 ;
     RECT  11.196 20.149 11.214 20.551 ;
     RECT  10.836 20.551 11.214 20.573 ;
     RECT  0.216 20.389 1.134 20.779 ;
     RECT  0.216 20.779 1.422 20.849 ;
     RECT  4.608 20.429 4.626 21.115 ;
     RECT  6.195 19.229 6.477 21.211 ;
     RECT  8.028 21.235 8.046 21.293 ;
     RECT  10.836 20.573 10.854 21.307 ;
     RECT  10.836 21.307 10.998 21.389 ;
     RECT  5.976 21.211 6.477 21.425 ;
     RECT  9.576 21.259 9.594 21.425 ;
     RECT  2.916 21.361 2.934 21.433 ;
     RECT  2.844 21.433 2.934 21.505 ;
     RECT  2.448 21.505 2.934 21.541 ;
     RECT  9.648 21.496 9.666 21.631 ;
     RECT  10.836 21.389 10.854 21.631 ;
     RECT  4.212 21.115 4.626 21.643 ;
     RECT  4.212 21.643 4.806 21.682 ;
     RECT  0.216 20.849 1.35 21.695 ;
     RECT  9.648 21.631 10.854 21.725 ;
     RECT  2.376 21.541 2.934 21.811 ;
     RECT  2.052 21.811 3.114 21.931 ;
     RECT  2.052 21.931 3.15 21.971 ;
     RECT  4.788 21.682 4.806 22.045 ;
     RECT  6.195 21.425 6.477 22.081 ;
     RECT  3.06 21.971 3.15 22.199 ;
     RECT  4.788 22.045 4.95 22.199 ;
     RECT  9.648 21.725 9.666 22.199 ;
     RECT  7.884 22.207 7.902 22.219 ;
     RECT  2.052 21.971 2.142 22.235 ;
     RECT  4.788 22.199 4.806 22.235 ;
     RECT  6.195 22.081 6.786 22.315 ;
     RECT  7.596 22.219 7.902 22.315 ;
     RECT  6.195 22.315 6.858 22.351 ;
     RECT  7.596 22.315 8.118 22.351 ;
     RECT  2.052 22.235 2.07 22.441 ;
     RECT  3.132 22.199 3.15 22.469 ;
     RECT  7.596 22.351 8.37 22.541 ;
     RECT  1.98 22.441 2.07 22.577 ;
     RECT  9.684 22.585 9.702 22.685 ;
     RECT  10.836 21.725 10.854 22.783 ;
     RECT  6.048 22.351 6.858 22.981 ;
     RECT  7.596 22.541 7.614 22.981 ;
     RECT  10.656 22.783 10.854 22.981 ;
     RECT  10.656 22.981 11.142 23.069 ;
     RECT  2.916 22.981 2.934 23.153 ;
     RECT  6.048 22.981 7.614 23.153 ;
     RECT  6.048 23.153 6.477 23.161 ;
     RECT  2.376 23.161 2.862 23.279 ;
     RECT  4.392 23.161 4.41 23.279 ;
     RECT  5.472 23.161 6.477 23.279 ;
     RECT  10.656 23.069 10.854 23.287 ;
     RECT  0.216 21.695 1.077 23.323 ;
     RECT  2.52 23.279 2.862 23.357 ;
     RECT  10.26 23.287 10.854 23.453 ;
     RECT  7.56 23.153 7.578 23.549 ;
     RECT  4.248 23.395 4.374 23.693 ;
     RECT  5.328 23.323 5.382 23.701 ;
     RECT  4.356 23.693 4.374 23.741 ;
     RECT  2.664 23.357 2.862 23.819 ;
     RECT  0.216 23.323 1.494 23.855 ;
     RECT  2.844 23.819 2.862 23.891 ;
     RECT  5.292 23.701 5.382 23.891 ;
     RECT  6.195 23.279 6.477 23.971 ;
     RECT  10.8 23.453 10.854 24.029 ;
     RECT  2.916 23.971 2.934 24.125 ;
     RECT  5.04 24.091 5.166 24.131 ;
     RECT  6.195 23.971 7.362 24.169 ;
     RECT  9.144 24.169 9.162 24.187 ;
     RECT  8.136 24.061 8.226 24.197 ;
     RECT  6.048 24.169 7.362 24.269 ;
     RECT  9.144 24.187 9.702 24.269 ;
     RECT  7.344 24.269 7.362 24.283 ;
     RECT  8.136 24.197 8.154 24.283 ;
     RECT  1.944 24.241 1.962 24.317 ;
     RECT  10.836 24.029 10.854 24.331 ;
     RECT  6.048 24.269 6.477 24.359 ;
     RECT  7.344 24.283 8.154 24.359 ;
     RECT  5.148 24.131 5.166 24.395 ;
     RECT  9.144 24.269 9.162 24.413 ;
     RECT  0.216 23.855 1.077 24.745 ;
     RECT  0.216 24.745 1.566 24.797 ;
     RECT  8.928 24.859 8.946 24.935 ;
     RECT  10.836 24.331 10.926 24.989 ;
     RECT  6.195 24.359 6.477 25.141 ;
     RECT  2.088 25.141 2.178 25.285 ;
     RECT  3.384 25.285 3.546 25.325 ;
     RECT  9.684 25.249 9.702 25.373 ;
     RECT  3.528 25.325 3.546 25.439 ;
     RECT  10.836 24.989 10.854 25.519 ;
     RECT  6.195 25.141 6.606 25.555 ;
     RECT  6.195 25.555 7.11 25.613 ;
     RECT  2.088 25.285 2.322 25.627 ;
     RECT  6.195 25.613 6.477 25.819 ;
     RECT  2.016 25.627 2.322 25.901 ;
     RECT  10.8 25.519 10.854 25.915 ;
     RECT  5.724 25.819 6.477 25.979 ;
     RECT  10.224 25.915 10.854 25.979 ;
     RECT  0.216 24.797 1.077 26.015 ;
     RECT  0.684 26.015 1.077 26.107 ;
     RECT  0.684 26.107 1.17 26.203 ;
     RECT  10.692 25.979 10.854 26.221 ;
     RECT  10.692 26.221 10.89 26.293 ;
     RECT  2.52 26.257 2.538 26.333 ;
     RECT  3.348 26.221 3.366 26.365 ;
     RECT  2.844 26.365 3.366 26.429 ;
     RECT  7.704 26.293 7.722 26.443 ;
     RECT  7.704 26.443 8.118 26.519 ;
     RECT  6.195 25.979 6.477 26.527 ;
     RECT  6.195 26.527 6.858 26.587 ;
     RECT  7.704 26.519 7.722 26.587 ;
     RECT  0.684 26.203 1.494 26.789 ;
     RECT  6.195 26.587 7.722 26.789 ;
     RECT  0.684 26.789 1.077 26.869 ;
     RECT  10.692 26.293 10.926 26.909 ;
     RECT  10.692 26.909 10.854 27.139 ;
     RECT  2.844 26.429 2.97 27.175 ;
     RECT  4.032 26.905 4.05 27.175 ;
     RECT  4.032 27.175 4.59 27.211 ;
     RECT  10.26 27.139 10.854 27.293 ;
     RECT  2.268 27.175 2.97 27.329 ;
     RECT  7.308 26.789 7.722 27.329 ;
     RECT  4.032 27.211 5.166 27.341 ;
     RECT  2.628 27.329 2.97 27.365 ;
     RECT  4.032 27.341 4.05 27.365 ;
     RECT  5.148 27.341 5.166 27.365 ;
     RECT  7.704 27.329 7.722 27.365 ;
     RECT  10.836 27.293 10.854 27.485 ;
     RECT  0.216 26.869 1.077 27.607 ;
     RECT  10.872 27.637 10.89 27.832 ;
     RECT  8.892 26.875 8.91 27.841 ;
     RECT  10.872 27.832 11.214 27.869 ;
     RECT  8.82 27.841 8.91 27.917 ;
     RECT  8.82 27.917 8.838 28.013 ;
     RECT  10.872 27.869 10.926 28.139 ;
     RECT  6.195 26.789 6.477 28.219 ;
     RECT  7.884 27.751 7.902 28.219 ;
     RECT  7.596 28.219 7.902 28.255 ;
     RECT  7.596 28.255 7.938 28.291 ;
     RECT  5.148 28.219 5.166 28.319 ;
     RECT  6.156 28.219 6.477 28.363 ;
     RECT  6.156 28.363 6.606 28.409 ;
     RECT  0.216 27.607 1.206 28.411 ;
     RECT  7.596 28.291 8.478 28.445 ;
     RECT  0.216 28.411 1.818 28.451 ;
     RECT  4.788 28.417 4.806 28.453 ;
     RECT  7.776 28.445 8.154 28.517 ;
     RECT  6.195 28.409 6.606 28.555 ;
     RECT  7.812 28.517 8.154 28.589 ;
     RECT  11.736 28.555 11.754 28.6 ;
     RECT  11.664 28.6 11.754 28.634 ;
     RECT  11.664 28.634 11.682 28.637 ;
     RECT  4.608 28.453 4.806 28.733 ;
     RECT  6.195 28.555 6.858 28.733 ;
     RECT  3.456 28.645 3.474 28.921 ;
     RECT  2.844 28.921 3.474 29.101 ;
     RECT  0.216 28.451 1.53 29.179 ;
     RECT  10.8 28.219 10.854 29.179 ;
     RECT  2.844 29.101 4.014 29.219 ;
     RECT  10.8 29.179 11.142 29.219 ;
     RECT  0.216 29.179 1.782 29.255 ;
     RECT  2.844 29.219 3.906 29.291 ;
     RECT  5.148 29.191 5.166 29.291 ;
     RECT  10.8 29.219 10.854 29.461 ;
     RECT  10.368 29.461 10.854 29.597 ;
     RECT  2.844 29.291 3.294 29.755 ;
     RECT  7.272 29.641 7.29 29.759 ;
     RECT  5.076 29.755 5.094 29.795 ;
     RECT  8.136 28.589 8.154 29.803 ;
     RECT  6.195 28.733 6.477 29.875 ;
     RECT  8.136 29.803 8.73 29.981 ;
     RECT  10.8 29.597 10.854 29.981 ;
     RECT  6.195 29.875 7.002 30.029 ;
     RECT  8.676 29.981 8.73 30.073 ;
     RECT  2.772 29.755 3.294 30.137 ;
     RECT  5.148 30.073 5.166 30.209 ;
     RECT  6.195 30.029 6.477 30.271 ;
     RECT  2.772 30.137 3.15 30.307 ;
     RECT  7.884 30.271 7.902 30.371 ;
     RECT  2.592 30.307 3.15 30.415 ;
     RECT  8.676 30.073 9.054 30.415 ;
     RECT  2.304 30.415 3.15 30.461 ;
     RECT  2.592 30.461 3.15 30.479 ;
     RECT  8.676 30.415 9.126 30.509 ;
     RECT  10.836 29.981 10.854 30.541 ;
     RECT  0.216 29.255 1.077 30.577 ;
     RECT  2.592 30.479 2.862 30.677 ;
     RECT  6.156 30.271 6.477 30.677 ;
     RECT  9.108 30.509 9.126 30.677 ;
     RECT  0.216 30.577 1.422 30.749 ;
     RECT  10.836 30.541 10.89 30.749 ;
     RECT  4.86 30.715 4.878 30.755 ;
     RECT  10.836 30.749 10.854 31.019 ;
     RECT  6.195 30.677 6.477 31.081 ;
     RECT  7.38 30.955 7.398 31.081 ;
     RECT  6.195 31.081 7.398 31.181 ;
     RECT  7.38 31.181 7.398 31.225 ;
     RECT  10.26 31.099 10.278 31.261 ;
     RECT  2.592 30.677 2.61 31.325 ;
     RECT  9.648 31.261 10.278 31.325 ;
     RECT  7.38 31.225 7.65 31.351 ;
     RECT  3.996 31.243 4.014 31.415 ;
     RECT  11.196 31.483 11.214 31.523 ;
     RECT  7.38 31.351 7.938 31.565 ;
     RECT  5.184 31.495 5.202 31.729 ;
     RECT  9.108 31.531 9.522 31.757 ;
     RECT  8.928 31.765 8.946 31.805 ;
     RECT  5.184 31.729 5.238 31.829 ;
     RECT  10.368 31.801 10.386 31.891 ;
     RECT  10.368 31.891 11.106 31.901 ;
     RECT  6.195 31.181 6.477 31.915 ;
     RECT  7.92 31.565 7.938 32.305 ;
     RECT  2.268 31.531 2.286 32.341 ;
     RECT  3.096 32.155 3.114 32.341 ;
     RECT  7.632 32.305 7.938 32.341 ;
     RECT  4.716 32.395 4.734 32.431 ;
     RECT  10.836 31.901 11.106 32.431 ;
     RECT  7.632 32.341 8.19 32.459 ;
     RECT  0.216 30.749 1.077 32.467 ;
     RECT  7.632 32.459 8.046 32.495 ;
     RECT  2.124 32.341 3.114 32.531 ;
     RECT  6.195 31.915 6.858 32.539 ;
     RECT  7.632 32.495 7.938 32.539 ;
     RECT  3.996 32.431 4.734 32.611 ;
     RECT  2.844 32.531 3.114 32.639 ;
     RECT  10.836 32.431 11.142 32.669 ;
     RECT  3.996 32.611 5.13 32.837 ;
     RECT  3.996 32.837 4.41 32.909 ;
     RECT  6.195 32.539 7.938 32.909 ;
     RECT  9.576 32.827 9.594 32.909 ;
     RECT  3.096 32.639 3.114 33.007 ;
     RECT  0.216 32.467 1.134 33.151 ;
     RECT  2.052 32.611 2.07 33.151 ;
     RECT  10.836 32.669 10.854 33.211 ;
     RECT  4.392 32.909 4.41 33.269 ;
     RECT  7.74 32.909 7.938 33.269 ;
     RECT  10.332 33.211 10.854 33.269 ;
     RECT  7.74 33.269 7.758 33.389 ;
     RECT  0.216 33.151 2.07 33.539 ;
     RECT  1.98 33.539 1.998 33.611 ;
     RECT  6.195 32.909 6.477 33.643 ;
     RECT  6.195 33.643 6.534 33.655 ;
     RECT  10.836 33.269 10.854 33.655 ;
     RECT  3.096 33.007 3.294 33.691 ;
     RECT  5.904 33.655 6.534 33.691 ;
     RECT  5.904 33.691 6.678 33.809 ;
     RECT  10.836 33.655 10.89 33.821 ;
     RECT  9.144 33.961 9.162 34.013 ;
     RECT  6.195 33.809 6.678 34.171 ;
     RECT  2.844 33.691 3.294 34.205 ;
     RECT  6.195 34.171 6.858 34.223 ;
     RECT  6.195 34.223 6.534 34.349 ;
     RECT  10.836 33.821 10.854 34.501 ;
     RECT  2.844 34.205 2.862 34.555 ;
     RECT  10.116 34.501 10.854 34.555 ;
     RECT  2.052 34.555 2.862 34.591 ;
     RECT  8.64 34.555 8.658 34.619 ;
     RECT  10.116 34.555 11.214 34.619 ;
     RECT  3.96 34.591 3.978 34.627 ;
     RECT  10.116 34.619 10.818 34.663 ;
     RECT  3.96 34.627 4.122 34.727 ;
     RECT  10.08 34.663 10.818 34.735 ;
     RECT  10.008 34.735 10.818 34.781 ;
     RECT  6.195 34.349 6.477 34.843 ;
     RECT  5.508 34.843 6.477 34.889 ;
     RECT  8.604 34.771 8.622 34.889 ;
     RECT  10.008 34.781 10.026 34.889 ;
     RECT  1.98 34.591 2.862 34.969 ;
     RECT  8.496 35.005 8.514 35.069 ;
     RECT  9.432 34.939 9.45 35.069 ;
     RECT  1.98 34.969 2.934 35.159 ;
     RECT  4.284 34.897 4.374 35.159 ;
     RECT  10.8 34.781 10.818 35.168 ;
     RECT  7.38 35.131 7.398 35.195 ;
     RECT  6.195 34.889 6.477 35.323 ;
     RECT  4.284 35.159 4.302 35.453 ;
     RECT  6.195 35.323 6.858 35.453 ;
     RECT  0.216 33.539 1.077 35.545 ;
     RECT  1.98 35.159 1.998 35.545 ;
     RECT  0.216 35.545 1.998 35.573 ;
     RECT  2.844 35.159 2.934 35.671 ;
     RECT  0.216 35.573 1.746 35.741 ;
     RECT  0.216 35.741 1.53 35.807 ;
     RECT  11.664 35.899 11.682 35.941 ;
     RECT  5.148 35.815 5.166 35.947 ;
     RECT  6.195 35.453 6.822 35.947 ;
     RECT  11.664 35.941 11.754 35.969 ;
     RECT  11.736 35.969 11.754 35.981 ;
     RECT  5.148 35.947 6.822 36.005 ;
     RECT  5.148 36.005 5.166 36.077 ;
     RECT  2.844 35.671 3.366 36.085 ;
     RECT  10.836 35.401 10.854 36.091 ;
     RECT  2.772 36.085 3.366 36.125 ;
     RECT  0.216 35.807 1.35 36.413 ;
     RECT  2.808 36.125 3.366 36.475 ;
     RECT  10.764 36.091 10.854 36.475 ;
     RECT  6.195 36.005 6.822 36.481 ;
     RECT  2.808 36.475 3.942 36.545 ;
     RECT  2.808 36.545 3.474 36.617 ;
     RECT  6.195 36.481 6.966 36.617 ;
     RECT  8.532 36.475 8.55 36.625 ;
     RECT  3.276 36.617 3.474 36.653 ;
     RECT  6.195 36.617 6.822 36.689 ;
     RECT  8.352 36.625 8.91 36.931 ;
     RECT  8.244 36.931 8.91 37.003 ;
     RECT  3.384 36.653 3.474 37.049 ;
     RECT  8.1 37.003 8.91 37.049 ;
     RECT  3.384 37.049 3.402 37.229 ;
     RECT  0.216 36.413 1.077 37.471 ;
     RECT  2.16 37.201 2.178 37.471 ;
     RECT  0.216 37.471 2.178 37.517 ;
     RECT  4.5 37.561 4.518 37.579 ;
     RECT  7.632 37.471 7.65 37.579 ;
     RECT  7.488 37.579 7.65 37.589 ;
     RECT  4.5 37.579 4.59 37.625 ;
     RECT  7.488 37.589 7.506 37.625 ;
     RECT  4.5 37.625 4.518 37.733 ;
     RECT  10.26 36.475 10.854 37.741 ;
     RECT  10.224 37.741 10.854 37.853 ;
     RECT  2.16 37.517 2.178 38.045 ;
     RECT  8.892 37.049 8.91 38.101 ;
     RECT  8.82 38.101 8.91 38.189 ;
     RECT  10.656 37.853 10.854 38.237 ;
     RECT  8.82 38.189 8.838 38.273 ;
     RECT  0.216 37.517 1.077 38.281 ;
     RECT  6.195 36.689 6.714 38.281 ;
     RECT  6.195 38.281 6.858 38.399 ;
     RECT  5.436 38.515 5.454 38.551 ;
     RECT  5.148 38.551 5.454 38.669 ;
     RECT  5.292 38.669 5.31 38.675 ;
     RECT  0.216 38.281 1.782 38.705 ;
     RECT  3.312 38.635 3.33 38.705 ;
     RECT  7.812 38.551 7.83 38.705 ;
     RECT  7.956 38.713 7.974 38.849 ;
     RECT  2.412 39.055 2.43 39.211 ;
     RECT  2.412 39.211 2.862 39.245 ;
     RECT  2.628 39.245 2.862 39.251 ;
     RECT  6.195 38.399 6.477 39.361 ;
     RECT  10.8 38.237 10.854 39.395 ;
     RECT  2.844 39.251 2.862 39.451 ;
     RECT  6.156 39.361 6.477 39.451 ;
     RECT  9.648 39.361 9.738 39.451 ;
     RECT  2.844 39.451 2.934 39.515 ;
     RECT  6.156 39.451 6.822 39.515 ;
     RECT  6.195 39.515 6.822 39.523 ;
     RECT  9.648 39.451 10.278 39.559 ;
     RECT  3.78 39.211 3.798 39.631 ;
     RECT  6.195 39.523 6.966 39.659 ;
     RECT  9.36 39.559 10.278 39.749 ;
     RECT  10.26 39.749 10.278 39.773 ;
     RECT  2.916 39.515 2.934 39.821 ;
     RECT  3.78 39.631 4.266 39.857 ;
     RECT  5.436 39.865 5.454 39.917 ;
     RECT  11.196 39.865 11.214 39.965 ;
     RECT  9.108 39.865 9.126 40.027 ;
     RECT  8.892 40.027 9.126 40.445 ;
     RECT  3.78 39.857 3.798 40.567 ;
     RECT  3.168 40.567 3.798 40.595 ;
     RECT  0.216 38.705 1.077 40.675 ;
     RECT  3.168 40.595 3.33 40.711 ;
     RECT  6.195 39.659 6.477 40.801 ;
     RECT  0.216 40.675 1.314 40.829 ;
     RECT  2.916 40.711 3.33 40.829 ;
     RECT  10.584 40.123 10.854 40.829 ;
     RECT  9.144 40.711 9.342 40.891 ;
     RECT  7.488 40.837 7.506 41.009 ;
     RECT  9.144 40.891 9.882 41.009 ;
     RECT  6.195 40.801 6.75 41.021 ;
     RECT  9.144 41.009 9.702 41.021 ;
     RECT  2.916 40.829 3.186 41.521 ;
     RECT  4.572 41.215 4.59 41.521 ;
     RECT  2.772 41.521 3.186 41.639 ;
     RECT  4.572 41.521 4.662 41.647 ;
     RECT  0.216 40.829 1.077 41.719 ;
     RECT  4.14 41.647 5.022 41.747 ;
     RECT  0.216 41.719 1.638 41.791 ;
     RECT  0.216 41.791 2.142 41.909 ;
     RECT  4.248 41.747 4.338 41.909 ;
     RECT  2.952 41.639 3.186 42.017 ;
     RECT  7.2 41.611 7.218 42.025 ;
     RECT  9.648 41.021 9.702 42.089 ;
     RECT  3.204 42.025 3.222 42.139 ;
     RECT  10.836 40.829 10.854 42.151 ;
     RECT  3.204 42.139 3.33 42.179 ;
     RECT  4.32 41.909 4.338 42.179 ;
     RECT  10.224 42.151 10.854 42.323 ;
     RECT  0.216 41.909 2.07 42.449 ;
     RECT  6.195 41.021 6.477 42.715 ;
     RECT  7.2 42.025 7.758 42.715 ;
     RECT  9.036 42.601 9.126 42.715 ;
     RECT  2.052 42.449 2.07 42.719 ;
     RECT  10.836 42.323 10.854 42.727 ;
     RECT  8.892 42.715 9.126 42.755 ;
     RECT  10.836 42.727 11.214 42.845 ;
     RECT  6.195 42.715 7.758 42.871 ;
     RECT  9.108 42.755 9.126 42.899 ;
     RECT  6.195 42.871 7.794 43.105 ;
     RECT  2.16 43.069 2.178 43.169 ;
     RECT  10.836 42.845 10.89 43.229 ;
     RECT  3.492 43.141 3.51 43.259 ;
     RECT  2.232 43.243 2.25 43.295 ;
     RECT  10.836 43.229 10.854 43.339 ;
     RECT  6.195 43.105 7.902 43.529 ;
     RECT  4.644 42.763 4.95 43.645 ;
     RECT  10.26 43.339 10.854 43.645 ;
     RECT  7.2 43.529 7.902 43.681 ;
     RECT  8.928 43.645 8.946 43.681 ;
     RECT  10.008 43.645 10.854 43.681 ;
     RECT  7.2 43.681 8.946 43.799 ;
     RECT  4.464 43.645 5.094 43.805 ;
     RECT  9.684 43.681 10.854 43.805 ;
     RECT  7.2 43.799 8.802 43.835 ;
     RECT  9.684 43.805 9.702 43.997 ;
     RECT  7.2 43.835 8.082 44.069 ;
     RECT  2.844 43.411 2.862 44.149 ;
     RECT  2.628 44.149 2.862 44.221 ;
     RECT  3.636 43.951 3.654 44.221 ;
     RECT  2.628 44.221 3.654 44.249 ;
     RECT  3.096 44.249 3.654 44.429 ;
     RECT  3.6 44.429 3.654 44.455 ;
     RECT  4.932 43.805 5.094 44.491 ;
     RECT  6.195 43.529 6.477 44.491 ;
     RECT  3.6 44.455 4.122 44.609 ;
     RECT  4.932 44.491 6.477 44.609 ;
     RECT  4.104 44.609 4.122 44.725 ;
     RECT  4.932 44.609 4.95 44.725 ;
     RECT  7.488 44.069 8.082 44.725 ;
     RECT  9.576 44.725 9.594 44.731 ;
     RECT  0.216 42.449 1.077 44.761 ;
     RECT  4.104 44.725 4.95 44.765 ;
     RECT  4.104 44.765 4.122 44.789 ;
     RECT  9.576 44.731 9.63 44.789 ;
     RECT  0.216 44.761 1.782 44.879 ;
     RECT  7.488 44.725 8.55 44.879 ;
     RECT  7.488 44.879 7.938 44.923 ;
     RECT  9.576 44.789 9.594 44.957 ;
     RECT  4.932 44.765 4.95 45.023 ;
     RECT  7.416 44.923 7.938 45.293 ;
     RECT  10.836 43.805 10.854 45.493 ;
     RECT  10.836 45.493 11.214 45.533 ;
     RECT  6.195 44.609 6.477 45.688 ;
     RECT  10.836 45.533 10.854 45.688 ;
     RECT  5.544 45.688 6.477 45.725 ;
     RECT  2.088 45.691 2.214 45.731 ;
     RECT  6.195 45.725 6.477 45.769 ;
     RECT  2.196 45.731 2.214 45.821 ;
     RECT  6.195 45.769 6.858 45.869 ;
     RECT  7.92 45.293 7.938 45.869 ;
     RECT  10.656 45.688 10.854 45.917 ;
     RECT  5.004 46.069 5.166 46.109 ;
     RECT  8.46 46.237 8.478 46.267 ;
     RECT  5.148 46.109 5.166 46.301 ;
     RECT  6.195 45.869 6.75 46.301 ;
     RECT  8.46 46.267 9.198 46.301 ;
     RECT  8.532 46.301 9.198 46.337 ;
     RECT  10.656 45.917 10.818 46.381 ;
     RECT  8.532 46.337 8.622 46.409 ;
     RECT  0.216 44.879 1.077 46.459 ;
     RECT  10.368 46.381 10.818 46.493 ;
     RECT  8.604 46.409 8.622 46.499 ;
     RECT  11.736 46.603 11.754 46.615 ;
     RECT  11.664 46.615 11.754 46.643 ;
     RECT  2.844 46.309 2.862 46.651 ;
     RECT  11.664 46.643 11.682 46.685 ;
     RECT  0.216 46.459 1.53 46.733 ;
     RECT  2.736 46.651 2.862 46.747 ;
     RECT  3.636 46.603 3.654 46.747 ;
     RECT  2.736 46.747 3.654 46.769 ;
     RECT  6.195 46.301 6.477 46.849 ;
     RECT  10.836 46.741 10.854 46.921 ;
     RECT  5.292 46.849 6.477 47.039 ;
     RECT  2.016 46.885 2.25 47.147 ;
     RECT  5.724 47.039 6.477 47.219 ;
     RECT  10.836 46.921 10.89 47.261 ;
     RECT  10.836 47.261 10.854 47.281 ;
     RECT  10.26 47.281 10.854 47.453 ;
     RECT  6.195 47.219 6.477 47.461 ;
     RECT  3.06 46.769 3.438 47.489 ;
     RECT  2.232 47.147 2.25 47.579 ;
     RECT  3.06 47.489 3.078 47.741 ;
     RECT  9.648 47.551 9.81 47.899 ;
     RECT  6.195 47.461 7.11 47.993 ;
     RECT  9.036 47.899 9.81 48.029 ;
     RECT  9.036 48.029 9.234 48.119 ;
     RECT  9.036 48.119 9.054 48.155 ;
     RECT  4.752 48.001 4.77 48.235 ;
     RECT  6.195 47.993 6.477 48.235 ;
     RECT  10.836 47.453 10.854 48.271 ;
     RECT  7.524 48.271 7.542 48.389 ;
     RECT  10.836 48.271 11.214 48.413 ;
     RECT  10.836 48.413 10.89 48.571 ;
     RECT  8.028 48.541 8.19 48.659 ;
     RECT  10.368 48.571 10.89 48.659 ;
     RECT  8.028 48.659 8.046 48.695 ;
     RECT  10.8 48.659 10.89 48.803 ;
     RECT  5.76 48.235 6.477 48.845 ;
     RECT  4.536 48.235 4.77 48.901 ;
     RECT  0.216 46.733 1.077 48.937 ;
     RECT  1.8 48.541 1.818 48.937 ;
     RECT  4.536 48.901 5.094 48.941 ;
     RECT  4.536 48.941 5.022 48.973 ;
     RECT  0.216 48.937 1.818 48.989 ;
     RECT  6.195 48.845 6.477 49.051 ;
     RECT  4.392 48.973 5.022 49.085 ;
     RECT  6.195 49.051 6.858 49.181 ;
     RECT  1.944 49.207 1.962 49.379 ;
     RECT  3.996 49.351 4.014 49.421 ;
     RECT  5.004 49.085 5.022 49.565 ;
     RECT  2.844 49.441 2.862 49.577 ;
     RECT  10.8 48.803 10.854 49.711 ;
     RECT  10.224 49.711 10.854 49.757 ;
     RECT  6.195 49.181 6.534 49.783 ;
     RECT  10.656 49.757 10.854 49.915 ;
     RECT  2.124 49.783 2.142 50.009 ;
     RECT  10.656 49.915 10.926 50.009 ;
     RECT  10.656 50.009 10.854 50.141 ;
     RECT  5.508 49.783 6.534 50.153 ;
     RECT  10.656 50.141 10.674 50.333 ;
     RECT  2.952 50.107 2.97 50.731 ;
     RECT  5.508 50.153 6.477 50.731 ;
     RECT  2.952 50.731 3.186 50.791 ;
     RECT  7.92 50.251 7.938 50.791 ;
     RECT  11.664 50.491 11.682 50.819 ;
     RECT  2.952 50.791 3.402 50.827 ;
     RECT  7.92 50.791 8.082 50.827 ;
     RECT  10.368 50.683 10.386 50.875 ;
     RECT  4.572 50.791 4.59 50.971 ;
     RECT  5.328 50.731 6.477 50.971 ;
     RECT  7.38 50.827 8.082 50.971 ;
     RECT  4.536 50.971 4.59 50.972 ;
     RECT  10.26 50.875 10.386 51.101 ;
     RECT  2.844 50.827 3.402 51.205 ;
     RECT  5.328 50.971 8.082 51.233 ;
     RECT  2.844 51.205 3.762 51.269 ;
     RECT  0.216 48.989 1.077 51.307 ;
     RECT  2.088 50.587 2.106 51.307 ;
     RECT  5.328 51.233 6.477 51.307 ;
     RECT  0.216 51.307 2.106 51.403 ;
     RECT  7.632 51.233 8.082 51.601 ;
     RECT  5.292 51.307 6.477 51.629 ;
     RECT  7.632 51.601 8.37 51.629 ;
     RECT  3.456 51.269 3.762 51.637 ;
     RECT  4.536 50.972 4.554 51.637 ;
     RECT  5.976 51.629 6.477 51.665 ;
     RECT  3.456 51.637 4.554 51.677 ;
     RECT  9.648 51.601 9.666 51.677 ;
     RECT  8.352 51.629 8.37 51.773 ;
     RECT  4.464 51.677 4.554 51.781 ;
     RECT  10.836 51.241 10.854 51.868 ;
     RECT  4.464 51.781 5.13 51.899 ;
     RECT  0.216 51.403 2.358 51.935 ;
     RECT  10.836 51.868 10.89 52.141 ;
     RECT  3.456 51.677 3.474 52.169 ;
     RECT  6.156 51.665 6.477 52.321 ;
     RECT  3.132 52.321 3.15 52.439 ;
     RECT  4.464 51.899 4.518 52.439 ;
     RECT  6.156 52.321 7.002 52.439 ;
     RECT  0.216 51.935 2.214 52.475 ;
     RECT  4.356 52.447 4.374 52.493 ;
     RECT  10.8 52.141 10.89 52.795 ;
     RECT  8.82 52.825 8.838 52.877 ;
     RECT  2.16 52.475 2.214 52.889 ;
     RECT  2.196 52.889 2.214 53.021 ;
     RECT  6.195 52.439 7.002 53.035 ;
     RECT  10.8 52.795 11.142 53.365 ;
     RECT  8.352 53.365 8.37 53.405 ;
     RECT  6.195 53.035 7.182 53.563 ;
     RECT  10.8 53.365 11.214 53.563 ;
     RECT  5.76 53.563 7.182 53.597 ;
     RECT  10.656 53.563 11.214 53.752 ;
     RECT  10.584 53.752 11.214 53.789 ;
     RECT  5.76 53.597 6.93 53.825 ;
     RECT  9.216 53.797 9.234 53.837 ;
     RECT  1.872 53.851 1.89 53.869 ;
     RECT  2.916 53.257 2.934 53.869 ;
     RECT  6.195 53.825 6.93 53.933 ;
     RECT  2.844 53.869 2.934 53.969 ;
     RECT  6.195 53.933 6.75 53.969 ;
     RECT  10.8 53.789 11.214 53.981 ;
     RECT  1.872 53.869 2.07 54.329 ;
     RECT  3.024 54.031 3.69 54.473 ;
     RECT  3.78 54.481 3.798 54.571 ;
     RECT  3.78 54.571 3.906 54.599 ;
     RECT  0.216 52.475 1.077 54.607 ;
     RECT  1.872 54.329 1.926 54.607 ;
     RECT  3.888 54.599 3.906 54.607 ;
     RECT  10.8 53.981 10.854 54.607 ;
     RECT  3.024 54.473 3.042 54.635 ;
     RECT  3.888 54.607 4.518 54.653 ;
     RECT  3.888 54.653 3.906 54.779 ;
     RECT  10.26 54.607 10.854 54.904 ;
     RECT  5.148 54.904 5.166 54.941 ;
     RECT  6.195 53.969 6.477 54.985 ;
     RECT  6.012 54.985 6.678 55.021 ;
     RECT  7.488 54.811 7.506 55.021 ;
     RECT  9.756 54.904 10.854 55.133 ;
     RECT  0.216 54.607 1.926 55.139 ;
     RECT  9.756 55.133 9.774 55.139 ;
     RECT  6.012 55.021 7.506 55.175 ;
     RECT  8.46 55.021 8.478 55.211 ;
     RECT  2.844 55.147 2.862 55.283 ;
     RECT  2.088 55.387 2.106 55.445 ;
     RECT  9.648 55.651 9.666 55.709 ;
     RECT  4.464 55.675 4.482 55.715 ;
     RECT  6.012 55.175 6.858 55.771 ;
     RECT  5.868 55.771 6.858 55.823 ;
     RECT  6.195 55.823 6.858 55.859 ;
     RECT  10.836 55.133 10.854 56.056 ;
     RECT  8.064 56.029 8.082 56.219 ;
     RECT  10.656 56.056 10.854 56.291 ;
     RECT  10.8 56.291 10.854 56.371 ;
     RECT  7.92 56.335 7.938 56.381 ;
     RECT  2.844 56.029 2.862 56.641 ;
     RECT  9 56.065 9.018 56.909 ;
     RECT  6.195 55.859 6.822 57.001 ;
     RECT  10.8 56.371 10.926 57.019 ;
     RECT  8.532 57.001 8.55 57.053 ;
     RECT  10.8 57.019 11.214 57.065 ;
     RECT  2.844 56.641 3.402 57.209 ;
     RECT  10.8 57.065 10.854 57.211 ;
     RECT  4.32 57.181 4.41 57.271 ;
     RECT  0.216 55.139 1.077 57.343 ;
     RECT  4.248 57.271 4.41 57.343 ;
     RECT  6.195 57.001 7.038 57.415 ;
     RECT  7.812 57.379 7.83 57.415 ;
     RECT  10.26 57.211 10.854 57.541 ;
     RECT  6.195 57.415 7.83 57.569 ;
     RECT  10.08 57.541 10.854 57.629 ;
     RECT  6.195 57.569 7.182 57.713 ;
     RECT  10.08 57.629 10.098 57.713 ;
     RECT  0.216 57.343 1.17 57.919 ;
     RECT  2.844 57.209 2.862 58.081 ;
     RECT  4.176 57.343 4.41 58.081 ;
     RECT  0.216 57.919 2.034 58.109 ;
     RECT  0.216 58.109 1.89 58.145 ;
     RECT  2.844 58.081 4.41 58.189 ;
     RECT  2.844 58.189 4.77 58.205 ;
     RECT  2.844 58.205 3.114 58.379 ;
     RECT  1.872 58.145 1.89 58.415 ;
     RECT  2.952 58.379 2.97 58.415 ;
     RECT  10.836 57.629 10.854 58.415 ;
     RECT  6.195 57.713 7.038 58.495 ;
     RECT  4.212 58.205 4.77 58.523 ;
     RECT  8.028 58.423 8.046 58.531 ;
     RECT  8.784 58.495 8.802 58.531 ;
     RECT  7.956 58.531 8.802 58.649 ;
     RECT  6.195 58.495 7.182 58.651 ;
     RECT  7.956 58.649 8.226 58.651 ;
     RECT  4.212 58.523 4.23 58.685 ;
     RECT  6.195 58.651 8.226 58.685 ;
     RECT  9.684 58.531 9.702 58.699 ;
     RECT  7.524 58.685 8.226 58.721 ;
     RECT  9 58.699 9.702 58.781 ;
     RECT  0.216 58.145 1.077 59.071 ;
     RECT  10.908 58.891 10.926 59.071 ;
     RECT  0.216 59.071 1.422 59.189 ;
     RECT  7.524 58.721 7.722 59.261 ;
     RECT  6.195 58.685 6.477 59.431 ;
     RECT  9 58.781 9.018 59.467 ;
     RECT  8.568 59.467 9.018 59.495 ;
     RECT  10.908 59.071 11.214 59.503 ;
     RECT  10.08 59.503 11.214 59.549 ;
     RECT  4.824 59.701 4.842 59.737 ;
     RECT  4.824 59.737 4.914 59.789 ;
     RECT  8.568 59.495 8.586 59.845 ;
     RECT  4.824 59.789 4.842 59.873 ;
     RECT  8.244 59.845 8.586 59.873 ;
     RECT  10.08 59.549 11.106 59.881 ;
     RECT  3.024 59.881 3.042 59.999 ;
     RECT  10.008 59.881 11.106 59.999 ;
     RECT  1.872 59.995 2.106 60.035 ;
     RECT  8.244 59.873 8.262 60.079 ;
     RECT  6.195 59.431 6.858 60.151 ;
     RECT  7.74 60.079 8.262 60.151 ;
     RECT  1.872 60.035 1.89 60.241 ;
     RECT  2.808 60.151 2.826 60.269 ;
     RECT  6.195 60.151 8.262 60.269 ;
     RECT  1.8 60.241 1.89 60.305 ;
     RECT  6.195 60.269 6.714 60.377 ;
     RECT  1.8 60.305 1.818 60.413 ;
     RECT  6.195 60.377 6.606 60.421 ;
     RECT  10.008 59.999 10.998 60.509 ;
     RECT  4.536 60.475 4.554 60.539 ;
     RECT  6.156 60.421 6.606 60.539 ;
     RECT  0.216 59.189 1.077 60.547 ;
     RECT  10.008 60.509 10.17 60.691 ;
     RECT  10.98 60.509 10.998 60.701 ;
     RECT  0.216 60.547 1.746 60.719 ;
     RECT  7.452 60.269 8.262 60.893 ;
     RECT  4.68 60.691 4.698 60.955 ;
     RECT  4.68 60.955 4.986 60.995 ;
     RECT  4.68 60.995 4.698 61.079 ;
     RECT  9.684 60.691 10.17 61.085 ;
     RECT  6.195 60.539 6.606 61.231 ;
     RECT  7.452 60.893 7.938 61.231 ;
     RECT  9.684 61.085 9.702 61.277 ;
     RECT  3.204 61.231 3.222 61.321 ;
     RECT  6.195 61.231 7.938 61.349 ;
     RECT  6.195 61.349 7.362 61.357 ;
     RECT  3.204 61.321 3.366 61.373 ;
     RECT  2.232 61.339 2.25 61.429 ;
     RECT  6.156 61.357 7.362 61.469 ;
     RECT  2.232 61.429 2.826 61.529 ;
     RECT  6.156 61.469 6.477 61.591 ;
     RECT  4.248 61.579 4.266 61.655 ;
     RECT  5.436 61.591 6.477 61.799 ;
     RECT  10.836 61.357 10.854 61.819 ;
     RECT  5.544 61.799 6.477 61.925 ;
     RECT  7.344 61.469 7.362 61.997 ;
     RECT  2.232 61.529 2.25 62.005 ;
     RECT  1.872 62.005 2.25 62.033 ;
     RECT  10.764 61.819 10.854 62.045 ;
     RECT  1.872 62.033 1.89 62.141 ;
     RECT  8.892 62.155 8.91 62.545 ;
     RECT  0.216 60.719 1.077 62.581 ;
     RECT  8.244 62.545 8.91 62.581 ;
     RECT  8.244 62.581 9.054 62.621 ;
     RECT  0.216 62.581 1.134 62.699 ;
     RECT  10.656 62.203 10.674 62.699 ;
     RECT  8.892 62.621 9.054 62.813 ;
     RECT  8.028 62.671 8.046 62.827 ;
     RECT  8.892 62.813 8.91 62.861 ;
     RECT  1.908 62.971 1.926 63.121 ;
     RECT  2.844 63.049 2.862 63.121 ;
     RECT  6.195 61.925 6.477 63.121 ;
     RECT  1.908 63.121 2.862 63.149 ;
     RECT  10.8 62.971 10.818 63.149 ;
     RECT  1.908 63.149 2.466 63.239 ;
     RECT  6.195 63.121 7.038 63.239 ;
     RECT  5.292 63.121 5.31 63.247 ;
     RECT  3.384 63.247 3.402 63.259 ;
     RECT  7.884 62.827 8.046 63.262 ;
     RECT  5.148 63.247 5.31 63.391 ;
     RECT  5.148 63.391 5.454 63.509 ;
     RECT  1.908 63.239 2.322 63.545 ;
     RECT  2.232 63.545 2.322 63.617 ;
     RECT  5.148 63.509 5.166 63.689 ;
     RECT  8.388 63.661 8.406 63.779 ;
     RECT  6.195 63.239 6.858 63.931 ;
     RECT  3.384 63.259 4.014 63.959 ;
     RECT  2.232 63.617 2.25 64.085 ;
     RECT  9.684 62.941 9.702 64.12 ;
     RECT  10.836 63.211 10.854 64.12 ;
     RECT  3.384 63.959 3.618 64.157 ;
     RECT  9.684 64.12 10.854 64.157 ;
     RECT  0.216 62.699 1.077 64.165 ;
     RECT  3.384 64.157 3.402 64.201 ;
     RECT  6.012 63.931 6.858 64.229 ;
     RECT  6.012 64.229 6.477 64.319 ;
     RECT  3.132 64.201 3.402 64.355 ;
     RECT  6.084 64.319 6.477 64.397 ;
     RECT  9.684 64.157 9.702 64.541 ;
     RECT  0.216 64.165 1.422 64.781 ;
     RECT  3.384 64.355 3.402 64.925 ;
     RECT  8.82 64.987 8.838 65.011 ;
     RECT  10.836 64.157 10.854 65.083 ;
     RECT  5.148 64.975 5.166 65.129 ;
     RECT  8.712 65.011 8.838 65.129 ;
     RECT  9.792 64.975 9.81 65.129 ;
     RECT  3.888 65.011 3.906 65.131 ;
     RECT  3.888 65.131 4.194 65.171 ;
     RECT  3.888 65.171 3.906 65.237 ;
     RECT  10.836 65.083 10.926 65.272 ;
     RECT  10.656 65.272 10.926 65.309 ;
     RECT  6.195 64.397 6.477 65.509 ;
     RECT  5.58 65.509 6.477 65.549 ;
     RECT  0.216 64.781 1.077 65.659 ;
     RECT  2.736 65.137 2.754 65.785 ;
     RECT  8.82 65.129 8.838 65.785 ;
     RECT  7.632 65.821 7.65 65.899 ;
     RECT  2.448 65.785 2.754 65.911 ;
     RECT  2.448 65.911 2.934 65.939 ;
     RECT  8.82 65.785 9.018 65.939 ;
     RECT  6.195 65.549 6.477 65.947 ;
     RECT  10.836 65.309 10.926 66.043 ;
     RECT  0.216 65.659 1.566 66.091 ;
     RECT  10.836 66.043 11.034 66.091 ;
     RECT  10.656 66.091 11.034 66.119 ;
     RECT  7.632 65.899 7.794 66.125 ;
     RECT  8.82 65.939 8.838 66.125 ;
     RECT  2.844 65.939 2.934 66.181 ;
     RECT  10.656 66.119 10.89 66.209 ;
     RECT  10.656 66.209 10.854 66.245 ;
     RECT  6.195 65.947 6.858 66.289 ;
     RECT  8.388 66.283 8.406 66.323 ;
     RECT  6.156 66.289 6.858 66.325 ;
     RECT  5.148 66.325 5.166 66.365 ;
     RECT  4.32 66.331 4.338 66.479 ;
     RECT  6.156 66.325 7.326 66.479 ;
     RECT  0.216 66.091 1.71 66.515 ;
     RECT  2.844 66.181 3.006 66.715 ;
     RECT  2.844 66.715 3.186 66.721 ;
     RECT  2.484 66.721 3.186 66.785 ;
     RECT  5.292 66.721 5.31 66.857 ;
     RECT  6.156 66.479 6.966 66.857 ;
     RECT  10.8 66.245 10.854 66.857 ;
     RECT  2.484 66.785 2.502 66.865 ;
     RECT  2.088 66.865 2.502 66.941 ;
     RECT  10.836 66.857 10.854 66.991 ;
     RECT  6.156 66.857 6.534 67.027 ;
     RECT  8.928 67.243 8.946 67.288 ;
     RECT  8.604 67.288 8.946 67.325 ;
     RECT  2.34 66.941 2.502 67.567 ;
     RECT  2.34 67.567 2.862 67.613 ;
     RECT  5.436 67.027 6.534 67.639 ;
     RECT  7.56 67.369 7.578 67.639 ;
     RECT  0.216 66.515 1.35 67.675 ;
     RECT  8.928 67.325 8.946 67.675 ;
     RECT  2.844 67.613 2.862 67.703 ;
     RECT  5.436 67.639 8.118 67.709 ;
     RECT  10.836 66.991 10.89 67.711 ;
     RECT  6.195 67.709 8.118 67.739 ;
     RECT  3.996 67.171 4.014 67.771 ;
     RECT  3.672 67.771 4.014 67.801 ;
     RECT  10.836 67.711 11.214 67.805 ;
     RECT  0.216 67.675 1.386 67.829 ;
     RECT  6.195 67.739 8.046 67.829 ;
     RECT  8.928 67.675 9.63 67.829 ;
     RECT  10.836 67.805 10.854 68.107 ;
     RECT  3.6 67.801 4.014 68.245 ;
     RECT  7.38 67.829 7.398 68.405 ;
     RECT  3.6 68.245 4.338 68.485 ;
     RECT  2.844 68.485 2.862 68.521 ;
     RECT  3.6 68.485 4.374 68.521 ;
     RECT  10.8 68.107 10.854 68.539 ;
     RECT  6.195 67.829 6.477 68.611 ;
     RECT  2.844 68.521 4.374 68.711 ;
     RECT  0.216 67.829 1.35 68.755 ;
     RECT  8.928 67.829 8.946 68.755 ;
     RECT  9.684 68.683 9.702 68.755 ;
     RECT  0.216 68.755 1.782 68.813 ;
     RECT  2.844 68.711 3.69 68.819 ;
     RECT  10.764 68.539 10.854 68.881 ;
     RECT  6.195 68.611 7.254 68.909 ;
     RECT  8.928 68.755 9.702 68.909 ;
     RECT  8.928 68.909 8.946 68.968 ;
     RECT  10.764 68.881 10.926 69.149 ;
     RECT  2.844 68.819 3.402 69.187 ;
     RECT  2.628 69.187 3.402 69.223 ;
     RECT  8.28 69.223 8.298 69.331 ;
     RECT  10.764 69.149 10.782 69.331 ;
     RECT  9.684 68.909 9.702 69.341 ;
     RECT  1.908 69.223 3.402 69.449 ;
     RECT  7.992 69.331 8.298 69.449 ;
     RECT  2.628 69.449 3.402 69.485 ;
     RECT  8.136 69.449 8.154 69.491 ;
     RECT  10.548 69.331 10.782 69.493 ;
     RECT  6.195 68.909 6.534 69.499 ;
     RECT  10.224 69.493 10.782 69.725 ;
     RECT  10.8 69.871 10.818 69.917 ;
     RECT  5.724 69.499 6.534 69.931 ;
     RECT  5.472 69.931 7.254 69.989 ;
     RECT  5.472 69.989 6.858 70.013 ;
     RECT  2.844 69.485 3.402 70.097 ;
     RECT  10.908 70.069 11.106 70.109 ;
     RECT  0.216 68.813 1.077 70.141 ;
     RECT  0.216 70.141 1.71 70.259 ;
     RECT  9.036 70.219 9.054 70.375 ;
     RECT  5.22 70.363 5.238 70.403 ;
     RECT  6.195 70.013 6.858 70.439 ;
     RECT  8.928 70.375 9.054 70.493 ;
     RECT  9.036 70.493 9.054 70.537 ;
     RECT  9.036 70.537 9.702 70.685 ;
     RECT  6.195 70.439 6.606 70.709 ;
     RECT  10.908 70.109 10.926 70.771 ;
     RECT  3.168 70.097 3.402 70.835 ;
     RECT  10.836 70.771 10.926 70.877 ;
     RECT  3.312 70.835 3.402 71.185 ;
     RECT  3.312 71.185 3.438 71.261 ;
     RECT  9.684 70.685 9.702 71.261 ;
     RECT  1.944 70.951 1.962 71.311 ;
     RECT  6.195 70.709 6.477 71.323 ;
     RECT  4.428 71.311 4.518 71.357 ;
     RECT  5.976 71.323 6.477 71.375 ;
     RECT  4.5 71.357 4.518 71.411 ;
     RECT  7.776 71.419 7.794 71.519 ;
     RECT  9.144 71.491 9.162 71.563 ;
     RECT  0.216 70.259 1.134 71.581 ;
     RECT  1.944 71.311 2.394 71.581 ;
     RECT  6.195 71.375 6.477 71.581 ;
     RECT  8.532 71.563 9.162 71.609 ;
     RECT  0.216 71.581 2.862 71.645 ;
     RECT  9.108 71.609 9.162 71.645 ;
     RECT  0.216 71.645 1.422 71.681 ;
     RECT  2.268 71.645 2.862 71.681 ;
     RECT  10.836 70.877 10.854 71.761 ;
     RECT  6.195 71.581 6.858 71.803 ;
     RECT  10.836 71.761 10.926 71.837 ;
     RECT  6.195 71.803 7.47 71.879 ;
     RECT  2.268 71.681 2.646 72.059 ;
     RECT  6.195 71.879 6.858 72.059 ;
     RECT  2.592 72.059 2.646 72.149 ;
     RECT  9.108 71.645 9.126 72.185 ;
     RECT  10.656 71.995 10.674 72.187 ;
     RECT  3.6 72.031 3.618 72.257 ;
     RECT  2.628 72.149 2.646 72.317 ;
     RECT  10.26 72.187 10.674 72.329 ;
     RECT  6.195 72.059 6.477 72.379 ;
     RECT  10.656 72.329 10.674 72.413 ;
     RECT  3.924 72.379 4.158 72.455 ;
     RECT  0.216 71.681 1.077 72.571 ;
     RECT  2.808 72.463 2.826 72.571 ;
     RECT  9.684 72.391 9.702 72.605 ;
     RECT  0.216 72.571 1.746 72.689 ;
     RECT  5.364 72.379 6.477 72.712 ;
     RECT  5.364 72.712 5.382 72.841 ;
     RECT  1.872 72.805 1.89 72.845 ;
     RECT  2.808 72.571 2.862 72.955 ;
     RECT  5.328 72.841 5.382 72.955 ;
     RECT  5.22 72.955 5.382 72.959 ;
     RECT  7.632 72.841 7.65 72.959 ;
     RECT  5.22 72.959 5.346 72.989 ;
     RECT  5.22 72.989 5.238 72.995 ;
     RECT  2.808 72.955 2.97 73.075 ;
     RECT  10.836 72.661 10.854 73.147 ;
     RECT  6.195 72.712 6.477 73.201 ;
     RECT  2.16 73.075 2.97 73.229 ;
     RECT  3.924 72.455 4.086 73.229 ;
     RECT  6.195 73.201 6.75 73.237 ;
     RECT  10.764 73.147 10.854 73.237 ;
     RECT  3.924 73.229 3.942 73.265 ;
     RECT  2.7 73.229 2.97 73.301 ;
     RECT  10.764 73.237 10.926 73.471 ;
     RECT  8.136 73.381 8.154 73.483 ;
     RECT  5.184 73.381 5.202 73.499 ;
     RECT  6.195 73.237 7.038 73.499 ;
     RECT  8.136 73.483 8.442 73.499 ;
     RECT  10.368 73.471 10.926 73.565 ;
     RECT  0.216 72.689 1.077 73.651 ;
     RECT  0.216 73.651 1.71 73.769 ;
     RECT  2.952 73.301 2.97 73.949 ;
     RECT  8.424 73.499 8.442 74.062 ;
     RECT  10.8 73.565 10.926 74.141 ;
     RECT  10.8 74.141 10.854 74.333 ;
     RECT  6.195 73.499 6.858 74.345 ;
     RECT  7.704 74.299 7.722 74.345 ;
     RECT  5.148 74.389 5.166 74.461 ;
     RECT  6.195 74.345 6.477 74.461 ;
     RECT  3.852 74.461 3.87 74.579 ;
     RECT  4.644 74.461 5.166 74.579 ;
     RECT  5.004 74.579 5.166 74.615 ;
     RECT  9.684 74.491 9.702 74.651 ;
     RECT  10.836 74.333 10.854 74.717 ;
     RECT  7.488 74.623 7.506 74.759 ;
     RECT  2.844 74.929 2.862 75.001 ;
     RECT  3.6 74.587 3.762 75.001 ;
     RECT  5.04 74.615 5.166 75.001 ;
     RECT  6.012 74.461 6.477 75.001 ;
     RECT  2.844 75.001 3.762 75.029 ;
     RECT  5.04 75.001 6.477 75.119 ;
     RECT  9.648 74.875 9.666 75.119 ;
     RECT  2.916 75.029 3.762 75.191 ;
     RECT  5.472 75.119 6.477 75.191 ;
     RECT  0.216 73.769 1.53 75.211 ;
     RECT  5.688 75.191 6.477 75.259 ;
     RECT  0.216 75.211 1.71 75.299 ;
     RECT  5.688 75.259 6.858 75.437 ;
     RECT  3.276 75.191 3.762 75.631 ;
     RECT  10.836 75.451 10.854 75.631 ;
     RECT  0.216 75.299 1.494 75.659 ;
     RECT  10.836 75.631 10.926 75.677 ;
     RECT  8.568 75.505 8.586 75.695 ;
     RECT  0.216 75.659 1.422 75.803 ;
     RECT  0.216 75.803 1.386 75.821 ;
     RECT  3.276 75.631 4.23 75.965 ;
     RECT  6.195 75.437 6.858 75.965 ;
     RECT  0.216 75.821 1.35 76.109 ;
     RECT  3.276 75.965 3.834 76.235 ;
     RECT  6.195 75.965 6.477 76.459 ;
     RECT  9.648 76.411 9.666 76.469 ;
     RECT  5.004 76.459 5.022 76.477 ;
     RECT  6.012 76.459 6.477 76.477 ;
     RECT  5.004 76.477 6.477 76.505 ;
     RECT  8.316 76.441 8.334 76.613 ;
     RECT  5.004 76.505 5.382 76.621 ;
     RECT  7.488 76.363 7.506 76.621 ;
     RECT  2.844 76.441 2.934 76.649 ;
     RECT  4.752 76.621 5.382 76.649 ;
     RECT  2.052 76.621 2.07 76.739 ;
     RECT  2.844 76.649 2.898 76.739 ;
     RECT  4.752 76.649 5.166 76.739 ;
     RECT  2.844 76.739 2.862 76.747 ;
     RECT  5.004 76.739 5.022 76.775 ;
     RECT  7.488 76.621 8.154 76.775 ;
     RECT  10.836 75.677 10.854 76.795 ;
     RECT  2.304 76.747 2.862 76.829 ;
     RECT  10.224 76.795 10.854 76.891 ;
     RECT  10.224 76.891 11.142 76.919 ;
     RECT  3.816 76.235 3.834 76.925 ;
     RECT  10.368 76.919 11.142 77.021 ;
     RECT  10.368 77.021 10.926 77.213 ;
     RECT  0.216 76.109 1.077 77.515 ;
     RECT  7.236 77.125 7.254 77.549 ;
     RECT  4.968 77.521 4.986 77.593 ;
     RECT  2.844 76.829 2.862 77.621 ;
     RECT  4.536 77.593 4.986 77.657 ;
     RECT  4.536 77.657 4.554 77.729 ;
     RECT  2.232 77.665 2.646 77.927 ;
     RECT  8.136 76.775 8.154 77.981 ;
     RECT  10.368 77.213 10.854 77.999 ;
     RECT  6.195 76.505 6.477 78.061 ;
     RECT  0.216 77.515 1.242 78.077 ;
     RECT  9.648 78.331 9.666 78.368 ;
     RECT  2.556 77.927 2.646 78.403 ;
     RECT  3.492 78.283 3.726 78.403 ;
     RECT  2.556 78.403 3.726 78.431 ;
     RECT  6.12 78.061 6.477 78.439 ;
     RECT  3.564 78.431 3.726 78.523 ;
     RECT  3.564 78.523 3.834 78.557 ;
     RECT  2.556 78.431 2.79 78.629 ;
     RECT  3.636 78.557 3.834 78.629 ;
     RECT  5.472 78.439 6.858 78.637 ;
     RECT  3.708 78.629 3.834 78.665 ;
     RECT  2.556 78.629 2.646 78.749 ;
     RECT  4.572 78.511 4.662 78.773 ;
     RECT  5.472 78.637 6.93 78.809 ;
     RECT  3.996 78.907 4.014 78.944 ;
     RECT  5.472 78.809 6.477 79.051 ;
     RECT  10.836 77.999 10.854 79.099 ;
     RECT  7.38 79.051 7.542 79.169 ;
     RECT  10.224 79.099 10.854 79.169 ;
     RECT  2.34 79.051 2.358 79.205 ;
     RECT  0.216 78.077 1.077 79.321 ;
     RECT  5.148 79.051 6.477 79.439 ;
     RECT  7.38 79.169 7.398 79.439 ;
     RECT  9.036 79.321 9.054 79.439 ;
     RECT  10.836 79.169 10.854 79.483 ;
     RECT  5.868 79.439 6.477 79.591 ;
     RECT  8.892 79.555 8.91 79.591 ;
     RECT  5.868 79.591 6.534 79.613 ;
     RECT  8.46 79.591 8.91 79.675 ;
     RECT  6.195 79.613 6.534 79.709 ;
     RECT  10.836 79.483 11.214 79.709 ;
     RECT  0.216 79.321 1.278 79.717 ;
     RECT  8.28 79.675 8.91 79.745 ;
     RECT  0.216 79.717 1.494 79.757 ;
     RECT  8.892 79.745 8.91 79.805 ;
     RECT  11.664 79.816 11.754 79.853 ;
     RECT  3.132 79.591 3.15 79.889 ;
     RECT  11.664 79.853 11.682 79.901 ;
     RECT  2.268 80.131 2.286 80.365 ;
     RECT  2.268 80.365 2.754 80.393 ;
     RECT  6.195 79.709 6.477 80.599 ;
     RECT  7.56 80.527 7.578 80.627 ;
     RECT  10.836 79.709 10.854 80.635 ;
     RECT  2.304 80.393 2.754 80.669 ;
     RECT  5.832 80.599 6.477 80.671 ;
     RECT  3.24 80.671 3.258 80.779 ;
     RECT  3.24 80.779 3.762 80.789 ;
     RECT  5.58 80.671 6.894 80.789 ;
     RECT  2.304 80.669 2.322 80.861 ;
     RECT  5.436 80.797 5.454 80.861 ;
     RECT  3.744 80.789 3.762 80.957 ;
     RECT  10.8 80.635 10.854 81.019 ;
     RECT  10.224 81.019 10.854 81.059 ;
     RECT  0.216 79.757 1.17 81.175 ;
     RECT  4.572 80.923 4.59 81.175 ;
     RECT  0.216 81.175 1.458 81.481 ;
     RECT  0.216 81.481 1.602 81.599 ;
     RECT  8.568 81.595 9.126 81.635 ;
     RECT  10.548 81.059 10.854 81.787 ;
     RECT  8.136 81.751 8.154 81.835 ;
     RECT  4.572 81.175 4.734 81.869 ;
     RECT  7.992 81.835 8.154 81.869 ;
     RECT  2.628 81.877 2.646 81.917 ;
     RECT  4.5 81.976 4.518 82.013 ;
     RECT  10.548 81.787 10.926 82.021 ;
     RECT  10.332 82.021 10.926 82.139 ;
     RECT  6.195 80.789 6.858 82.147 ;
     RECT  9.108 81.635 9.126 82.147 ;
     RECT  9.108 82.147 9.486 82.162 ;
     RECT  10.728 82.139 10.926 82.171 ;
     RECT  2.772 82.021 2.79 82.175 ;
     RECT  10.728 82.171 11.214 82.175 ;
     RECT  10.8 82.175 11.214 82.211 ;
     RECT  6.195 82.147 6.93 82.409 ;
     RECT  9.468 82.162 9.486 82.409 ;
     RECT  3.6 82.411 3.618 82.451 ;
     RECT  0.216 81.599 1.077 82.459 ;
     RECT  6.195 82.409 6.858 82.481 ;
     RECT  7.992 81.869 8.01 82.541 ;
     RECT  2.844 82.381 2.862 82.553 ;
     RECT  9.684 82.525 9.702 82.679 ;
     RECT  4.86 82.651 5.238 82.751 ;
     RECT  7.668 82.651 7.686 82.751 ;
     RECT  10.8 82.211 10.926 82.823 ;
     RECT  10.836 82.823 10.926 82.973 ;
     RECT  0.216 82.459 1.278 83.035 ;
     RECT  4.392 83.101 4.41 83.219 ;
     RECT  6.195 82.481 6.477 83.227 ;
     RECT  0.216 83.035 1.926 83.255 ;
     RECT  10.836 82.973 10.854 83.399 ;
     RECT  2.808 83.065 2.826 83.419 ;
     RECT  2.7 83.419 2.826 83.461 ;
     RECT  5.292 83.227 6.477 83.489 ;
     RECT  9.648 83.461 9.666 83.549 ;
     RECT  2.556 83.461 2.826 83.569 ;
     RECT  2.556 83.569 2.934 83.633 ;
     RECT  2.772 83.633 2.934 83.669 ;
     RECT  4.248 83.605 4.266 83.731 ;
     RECT  0.216 83.255 1.746 83.759 ;
     RECT  3.78 83.731 4.266 83.759 ;
     RECT  3.78 83.759 4.086 83.795 ;
     RECT  6.195 83.489 6.477 83.803 ;
     RECT  3.78 83.795 3.798 83.837 ;
     RECT  5.004 83.755 5.022 84.065 ;
     RECT  6.195 83.803 6.822 84.109 ;
     RECT  2.844 83.669 2.862 84.173 ;
     RECT  8.784 84.109 8.802 84.181 ;
     RECT  6.195 84.109 6.93 84.235 ;
     RECT  9.972 83.707 10.242 84.271 ;
     RECT  11.088 84.091 11.106 84.271 ;
     RECT  8.496 84.181 8.802 84.299 ;
     RECT  9.972 84.271 11.214 84.299 ;
     RECT  10.44 84.299 11.214 84.317 ;
     RECT  0.216 83.759 1.314 84.371 ;
     RECT  10.44 84.317 10.926 84.371 ;
     RECT  10.512 84.371 10.926 84.479 ;
     RECT  10.656 84.479 10.926 84.509 ;
     RECT  2.268 84.451 2.286 84.763 ;
     RECT  2.16 84.763 2.286 84.811 ;
     RECT  6.195 84.235 7.578 84.811 ;
     RECT  2.088 84.811 2.286 84.839 ;
     RECT  4.86 84.721 4.878 84.839 ;
     RECT  2.088 84.839 2.106 84.911 ;
     RECT  5.94 84.811 7.578 84.911 ;
     RECT  2.844 84.991 2.862 85.099 ;
     RECT  9.36 84.991 9.378 85.099 ;
     RECT  2.844 85.099 3.222 85.109 ;
     RECT  5.112 84.883 5.13 85.109 ;
     RECT  9.216 85.099 9.378 85.109 ;
     RECT  3.204 85.109 3.222 85.145 ;
     RECT  10.836 84.509 10.926 85.243 ;
     RECT  10.836 85.243 11.142 85.289 ;
     RECT  10.836 85.289 10.89 85.435 ;
     RECT  6.195 84.911 7.578 85.469 ;
     RECT  0.216 84.371 1.134 85.531 ;
     RECT  9.216 85.109 9.27 85.531 ;
     RECT  4.032 85.531 4.05 85.579 ;
     RECT  0.216 85.531 1.602 85.649 ;
     RECT  3.888 85.579 4.05 85.649 ;
     RECT  7.488 85.469 7.578 85.729 ;
     RECT  9.18 85.531 9.27 85.801 ;
     RECT  9 85.801 9.27 85.915 ;
     RECT  7.488 85.729 7.974 85.919 ;
     RECT  8.82 85.915 9.27 85.919 ;
     RECT  2.412 85.915 2.43 85.955 ;
     RECT  7.488 85.919 7.506 85.955 ;
     RECT  8.82 85.919 8.838 85.955 ;
     RECT  10.8 85.435 10.89 86.045 ;
     RECT  2.916 86.071 2.934 86.155 ;
     RECT  5.364 86.071 5.382 86.155 ;
     RECT  5.22 86.155 5.382 86.161 ;
     RECT  6.195 85.469 6.477 86.161 ;
     RECT  2.916 86.155 3.294 86.189 ;
     RECT  5.22 86.161 6.477 86.189 ;
     RECT  5.22 86.189 5.238 86.225 ;
     RECT  6.084 86.189 6.477 86.369 ;
     RECT  9.648 86.341 9.666 86.429 ;
     RECT  3.276 86.189 3.294 86.621 ;
     RECT  0.216 85.649 1.077 87.115 ;
     RECT  1.908 87.067 1.926 87.115 ;
     RECT  5.04 86.635 5.166 87.115 ;
     RECT  8.784 87.115 8.802 87.151 ;
     RECT  0.216 87.115 1.926 87.211 ;
     RECT  0.216 87.211 2.286 87.269 ;
     RECT  4.86 87.115 5.166 87.269 ;
     RECT  0.216 87.269 1.926 87.305 ;
     RECT  10.8 86.045 10.854 87.355 ;
     RECT  3.24 87.349 3.258 87.385 ;
     RECT  8.784 87.151 8.874 87.385 ;
     RECT  8.352 87.385 8.874 87.499 ;
     RECT  8.208 87.499 8.874 87.511 ;
     RECT  8.208 87.511 9.414 87.539 ;
     RECT  10.368 87.355 10.854 87.547 ;
     RECT  9.072 87.539 9.414 87.719 ;
     RECT  0.216 87.305 1.71 87.773 ;
     RECT  10.26 87.547 10.854 87.773 ;
     RECT  10.26 87.773 10.386 87.781 ;
     RECT  2.844 87.385 3.258 87.787 ;
     RECT  8.208 87.539 8.226 87.787 ;
     RECT  7.56 87.787 8.226 87.821 ;
     RECT  2.844 87.787 3.474 87.961 ;
     RECT  7.56 87.821 7.578 87.961 ;
     RECT  9.684 87.781 10.386 87.965 ;
     RECT  2.844 87.961 3.726 87.989 ;
     RECT  3.708 87.989 3.726 88.051 ;
     RECT  7.344 87.961 7.578 88.079 ;
     RECT  5.148 87.269 5.166 88.087 ;
     RECT  0.252 87.773 1.71 88.171 ;
     RECT  0.252 88.171 1.818 88.231 ;
     RECT  2.844 87.989 2.862 88.231 ;
     RECT  5.148 88.087 5.274 88.253 ;
     RECT  5.256 88.253 5.274 88.259 ;
     RECT  6.195 86.369 6.477 88.315 ;
     RECT  0.252 88.231 2.862 88.349 ;
     RECT  3.708 88.051 4.014 88.627 ;
     RECT  0.252 88.349 2.07 88.699 ;
     RECT  6.195 88.315 6.93 88.771 ;
     RECT  10.26 87.965 10.386 88.771 ;
     RECT  3.708 88.627 4.194 88.781 ;
     RECT  10.26 88.771 10.854 88.799 ;
     RECT  5.472 88.771 6.93 88.889 ;
     RECT  10.656 88.799 10.854 88.897 ;
     RECT  0.216 88.699 2.07 88.925 ;
     RECT  5.616 88.889 6.93 88.925 ;
     RECT  3.996 88.781 4.194 89.033 ;
     RECT  4.104 89.033 4.194 89.041 ;
     RECT  10.656 88.897 10.89 89.117 ;
     RECT  9.324 89.041 9.342 89.131 ;
     RECT  1.8 88.925 2.07 89.195 ;
     RECT  4.104 89.041 4.338 89.311 ;
     RECT  4.104 89.311 4.554 89.357 ;
     RECT  5.616 88.925 6.477 89.429 ;
     RECT  9.144 89.131 9.342 89.464 ;
     RECT  5.688 89.429 6.477 89.501 ;
     RECT  9.144 89.464 9.666 89.501 ;
     RECT  10.656 89.117 10.854 89.659 ;
     RECT  6.195 89.501 6.477 89.707 ;
     RECT  2.052 89.195 2.07 89.735 ;
     RECT  9.144 89.501 9.198 89.743 ;
     RECT  10.584 89.659 10.854 89.743 ;
     RECT  0.216 88.925 1.077 89.755 ;
     RECT  4.104 89.357 4.338 89.807 ;
     RECT  6.195 89.707 7.038 89.807 ;
     RECT  2.952 89.815 2.97 89.851 ;
     RECT  0.216 89.755 1.278 89.941 ;
     RECT  8.82 89.743 9.198 89.947 ;
     RECT  6.195 89.807 6.966 89.969 ;
     RECT  10.116 89.743 10.854 89.969 ;
     RECT  6.195 89.969 6.786 90.029 ;
     RECT  2.844 89.851 2.97 90.041 ;
     RECT  10.26 89.969 10.854 90.077 ;
     RECT  2.844 90.041 2.934 90.239 ;
     RECT  10.584 90.077 10.854 90.269 ;
     RECT  2.916 90.239 2.934 90.275 ;
     RECT  8.784 89.947 9.198 90.419 ;
     RECT  4.86 90.391 4.878 90.461 ;
     RECT  10.8 90.269 10.854 90.461 ;
     RECT  8.784 90.419 8.802 90.605 ;
     RECT  4.932 90.589 4.95 90.653 ;
     RECT  3.708 90.043 3.726 90.787 ;
     RECT  3.708 90.787 4.014 90.845 ;
     RECT  10.8 90.461 10.818 90.851 ;
     RECT  0.216 89.941 1.854 91.049 ;
     RECT  8.532 91.021 8.55 91.121 ;
     RECT  6.195 90.029 6.477 91.165 ;
     RECT  3.708 90.845 3.726 91.193 ;
     RECT  10.224 91.003 10.242 91.229 ;
     RECT  2.916 91.291 2.934 91.327 ;
     RECT  5.436 90.895 5.454 91.363 ;
     RECT  6.195 91.165 6.858 91.363 ;
     RECT  2.844 91.327 2.934 91.499 ;
     RECT  9.576 91.387 9.774 91.499 ;
     RECT  2.916 91.499 2.934 91.589 ;
     RECT  5.436 91.363 6.858 91.597 ;
     RECT  5.22 91.597 6.858 91.705 ;
     RECT  9.648 91.499 9.774 91.769 ;
     RECT  10.836 91.741 10.89 91.805 ;
     RECT  4.536 91.705 6.858 91.949 ;
     RECT  5.148 91.949 6.858 92.281 ;
     RECT  0.216 91.049 1.782 92.371 ;
     RECT  2.628 92.347 2.646 92.371 ;
     RECT  10.836 91.805 10.854 92.371 ;
     RECT  0.216 92.371 2.646 92.381 ;
     RECT  5.148 92.281 6.93 92.399 ;
     RECT  2.484 92.381 2.646 92.477 ;
     RECT  7.776 92.371 7.794 92.551 ;
     RECT  5.148 92.399 6.477 92.579 ;
     RECT  7.452 92.551 7.794 92.741 ;
     RECT  9.648 91.769 9.666 92.785 ;
     RECT  3.924 92.779 3.942 92.819 ;
     RECT  9.576 92.785 9.666 92.821 ;
     RECT  9.576 92.821 9.81 92.939 ;
     RECT  7.56 92.741 7.794 92.947 ;
     RECT  9.792 92.939 9.81 92.957 ;
     RECT  2.628 92.477 2.646 92.983 ;
     RECT  10.584 92.371 10.854 93.181 ;
     RECT  2.628 92.983 3.15 93.289 ;
     RECT  8.64 93.217 8.658 93.325 ;
     RECT  10.224 93.181 10.854 93.341 ;
     RECT  2.628 93.289 3.366 93.479 ;
     RECT  7.56 92.947 7.866 93.479 ;
     RECT  8.64 93.325 8.946 93.479 ;
     RECT  10.44 93.341 10.854 93.551 ;
     RECT  2.628 93.479 3.222 93.631 ;
     RECT  8.64 93.479 8.802 93.739 ;
     RECT  5.724 92.579 6.477 93.749 ;
     RECT  8.388 93.739 8.802 93.749 ;
     RECT  8.388 93.749 8.406 93.785 ;
     RECT  10.836 93.551 10.854 93.883 ;
     RECT  4.104 93.979 4.122 94.019 ;
     RECT  6.048 93.749 6.477 94.061 ;
     RECT  6.195 94.061 6.477 94.171 ;
     RECT  2.268 93.631 3.222 94.363 ;
     RECT  6.195 94.171 6.822 94.405 ;
     RECT  1.98 94.363 3.222 94.433 ;
     RECT  0.216 92.381 1.077 94.531 ;
     RECT  1.98 94.433 2.862 94.531 ;
     RECT  4.572 94.261 4.59 94.559 ;
     RECT  5.328 94.555 5.346 94.595 ;
     RECT  10.836 93.883 10.89 94.603 ;
     RECT  0.216 94.531 2.862 94.631 ;
     RECT  10.548 94.603 10.89 94.685 ;
     RECT  8.892 94.711 8.91 94.795 ;
     RECT  1.8 94.631 2.862 94.829 ;
     RECT  8.748 94.795 8.91 94.829 ;
     RECT  8.748 94.829 8.766 94.835 ;
     RECT  10.656 94.685 10.89 94.877 ;
     RECT  6.195 94.405 7.182 94.909 ;
     RECT  5.58 94.909 7.182 94.981 ;
     RECT  1.908 94.829 2.862 95.099 ;
     RECT  5.58 94.981 7.326 95.099 ;
     RECT  1.98 95.099 2.862 95.135 ;
     RECT  5.58 95.099 7.182 95.135 ;
     RECT  8.496 94.909 8.514 95.171 ;
     RECT  10.8 94.877 10.89 95.171 ;
     RECT  2.052 95.135 2.862 95.279 ;
     RECT  5.58 95.135 6.477 95.371 ;
     RECT  3.924 95.107 3.942 95.377 ;
     RECT  3.924 95.377 4.266 95.453 ;
     RECT  9.684 95.605 9.702 95.645 ;
     RECT  2.376 95.279 2.862 95.783 ;
     RECT  3.924 95.453 4.158 95.881 ;
     RECT  3.708 95.881 4.158 95.981 ;
     RECT  3.708 95.981 3.834 95.989 ;
     RECT  10.8 95.171 10.854 95.995 ;
     RECT  7.38 95.917 7.398 96.017 ;
     RECT  10.26 95.995 10.854 96.089 ;
     RECT  10.548 96.089 10.854 96.151 ;
     RECT  2.376 95.783 2.682 96.179 ;
     RECT  3.492 95.989 3.834 96.251 ;
     RECT  2.52 96.179 2.682 96.317 ;
     RECT  5.544 95.371 6.477 96.365 ;
     RECT  9.324 96.331 9.342 96.427 ;
     RECT  6.12 96.365 6.477 96.449 ;
     RECT  8.532 96.427 9.342 96.449 ;
     RECT  8.532 96.449 9.162 96.485 ;
     RECT  10.548 96.151 10.926 96.565 ;
     RECT  6.192 96.449 6.477 96.571 ;
     RECT  3.816 96.251 3.834 96.593 ;
     RECT  6.192 96.571 7.074 96.605 ;
     RECT  10.548 96.565 11.214 96.605 ;
     RECT  8.532 96.485 8.694 96.719 ;
     RECT  6.195 96.605 7.074 96.755 ;
     RECT  2.808 96.565 2.826 96.797 ;
     RECT  10.548 96.605 11.142 96.797 ;
     RECT  10.548 96.797 10.89 96.989 ;
     RECT  8.532 96.719 8.55 97.141 ;
     RECT  0.216 94.631 1.077 97.231 ;
     RECT  4.176 97.141 4.194 97.243 ;
     RECT  4.176 97.243 4.374 97.259 ;
     RECT  8.244 97.141 8.55 97.259 ;
     RECT  4.356 97.259 4.374 97.295 ;
     RECT  2.304 97.291 2.322 97.331 ;
     RECT  10.368 97.147 10.386 97.339 ;
     RECT  0.216 97.231 1.17 97.439 ;
     RECT  8.532 97.259 8.55 97.469 ;
     RECT  10.26 97.339 10.386 97.501 ;
     RECT  6.195 96.755 6.534 97.531 ;
     RECT  10.224 97.501 10.386 97.807 ;
     RECT  10.224 97.807 10.854 97.979 ;
     RECT  6.195 97.531 6.75 98.041 ;
     RECT  4.608 97.951 4.626 98.069 ;
     RECT  3.672 98.041 3.69 98.093 ;
     RECT  5.724 98.041 6.75 98.093 ;
     RECT  9.648 98.104 9.666 98.141 ;
     RECT  0.216 97.439 1.077 98.221 ;
     RECT  6.195 98.093 6.75 98.221 ;
     RECT  4.212 98.149 4.23 98.249 ;
     RECT  8.64 98.299 9.198 98.311 ;
     RECT  0.216 98.221 1.17 98.339 ;
     RECT  2.34 97.771 2.43 98.347 ;
     RECT  3.168 98.311 3.186 98.347 ;
     RECT  8.28 98.311 9.198 98.411 ;
     RECT  2.34 98.347 3.186 98.447 ;
     RECT  10.836 97.979 10.854 98.485 ;
     RECT  3.168 98.447 3.186 98.519 ;
     RECT  10.836 98.485 11.106 98.525 ;
     RECT  6.195 98.221 6.93 98.609 ;
     RECT  8.28 98.411 8.658 98.621 ;
     RECT  2.34 98.447 2.358 98.645 ;
     RECT  8.064 98.761 8.082 98.864 ;
     RECT  2.268 98.761 2.286 98.879 ;
     RECT  7.812 98.864 8.082 98.879 ;
     RECT  4.392 98.875 4.41 98.887 ;
     RECT  4.392 98.887 4.482 98.915 ;
     RECT  10.836 98.525 10.854 98.995 ;
     RECT  10.656 98.995 10.854 99.059 ;
     RECT  10.656 99.059 10.818 99.121 ;
     RECT  4.464 98.915 4.482 99.185 ;
     RECT  10.26 99.121 10.818 99.485 ;
     RECT  6.195 98.609 6.477 99.818 ;
     RECT  6.195 99.818 6.534 99.841 ;
     RECT  10.8 99.485 10.818 99.841 ;
     RECT  9.648 99.835 9.666 99.959 ;
     RECT  5.148 99.835 5.166 99.995 ;
     RECT  0.216 98.339 1.077 100.111 ;
     RECT  10.8 99.841 10.854 100.253 ;
     RECT  2.556 100.219 2.574 100.265 ;
     RECT  5.004 100.381 5.022 100.459 ;
     RECT  6.195 99.841 6.678 100.471 ;
     RECT  0.216 100.111 1.422 100.499 ;
     RECT  3.78 100.459 3.798 100.499 ;
     RECT  4.824 100.459 5.022 100.535 ;
     RECT  6.195 100.471 6.714 100.543 ;
     RECT  9.684 100.579 9.702 100.637 ;
     RECT  5.94 100.543 6.714 100.679 ;
     RECT  6.195 100.679 6.714 100.777 ;
     RECT  10.836 100.253 10.854 100.795 ;
     RECT  10.836 100.795 10.89 100.987 ;
     RECT  5.04 100.921 5.202 101.039 ;
     RECT  0.216 100.499 1.077 101.075 ;
     RECT  7.812 98.879 7.83 101.119 ;
     RECT  7.812 101.119 7.974 101.191 ;
     RECT  8.784 100.921 8.874 101.191 ;
     RECT  10.548 100.987 10.89 101.191 ;
     RECT  3.996 101.191 4.014 101.281 ;
     RECT  10.08 101.191 10.89 101.281 ;
     RECT  5.04 101.039 5.058 101.309 ;
     RECT  10.08 101.281 10.926 101.309 ;
     RECT  0.252 101.075 1.077 101.357 ;
     RECT  7.812 101.191 8.874 101.357 ;
     RECT  3.564 101.281 4.014 101.381 ;
     RECT  3.996 101.381 4.014 101.417 ;
     RECT  10.188 101.309 10.926 101.425 ;
     RECT  2.304 100.795 2.322 101.453 ;
     RECT  10.188 101.425 11.214 101.597 ;
     RECT  10.188 101.597 10.998 101.615 ;
     RECT  6.195 100.777 6.858 101.687 ;
     RECT  8.136 101.357 8.874 101.993 ;
     RECT  10.8 101.615 10.998 101.993 ;
     RECT  8.856 101.993 8.874 102.035 ;
     RECT  0.54 101.357 1.077 102.127 ;
     RECT  4.032 102.229 4.05 102.469 ;
     RECT  4.032 102.469 4.302 102.533 ;
     RECT  4.284 102.533 4.302 102.557 ;
     RECT  9.684 102.361 9.702 102.557 ;
     RECT  2.268 101.515 2.286 102.667 ;
     RECT  2.268 102.667 2.538 102.695 ;
     RECT  10.8 101.993 10.854 102.907 ;
     RECT  0.216 102.127 1.077 103.003 ;
     RECT  6.195 101.687 6.477 103.009 ;
     RECT  10.224 102.907 10.854 103.037 ;
     RECT  6.195 103.009 6.498 103.081 ;
     RECT  2.448 102.695 2.538 103.195 ;
     RECT  0.216 103.003 1.566 103.235 ;
     RECT  10.836 103.037 10.854 103.441 ;
     RECT  2.448 103.195 3.258 103.469 ;
     RECT  4.428 103.351 4.446 103.469 ;
     RECT  6.195 103.081 7.074 103.549 ;
     RECT  6.195 103.549 7.506 103.585 ;
     RECT  10.836 103.441 10.926 103.621 ;
     RECT  0.216 103.235 1.077 103.709 ;
     RECT  10.836 103.621 11.214 103.709 ;
     RECT  6.195 103.585 7.686 103.723 ;
     RECT  5.328 103.315 5.346 103.757 ;
     RECT  2.52 103.469 3.258 103.855 ;
     RECT  10.836 103.709 10.926 103.855 ;
     RECT  2.52 103.855 3.402 103.901 ;
     RECT  10.224 103.855 10.926 103.901 ;
     RECT  2.52 103.901 2.862 104.045 ;
     RECT  6.084 103.723 7.686 104.089 ;
     RECT  10.368 103.901 10.926 104.093 ;
     RECT  6.084 104.089 7.974 104.153 ;
     RECT  7.416 104.153 7.974 104.237 ;
     RECT  11.664 104.2 11.754 104.237 ;
     RECT  2.844 104.045 2.862 104.279 ;
     RECT  7.668 104.237 7.974 104.285 ;
     RECT  11.664 104.237 11.682 104.285 ;
     RECT  6.084 104.153 6.477 104.315 ;
     RECT  9 104.251 9.018 104.315 ;
     RECT  10.368 104.093 10.386 104.477 ;
     RECT  7.956 104.285 7.974 104.585 ;
     RECT  0.504 103.709 1.077 104.635 ;
     RECT  9.648 104.629 9.666 104.669 ;
     RECT  0.216 104.635 1.077 104.693 ;
     RECT  0.795 104.693 1.077 105.047 ;
     RECT  6.195 104.315 6.477 105.047 ;
     RECT  0.795 105.047 0.885 105.317 ;
     RECT  6.195 105.047 6.285 105.317 ;
    LAYER M4 ;
     RECT  0.156 0.384 0.788 104.664 ;
     RECT  0.788 0.384 0.892 105.312 ;
     RECT  0.892 0.384 1.084 105.042 ;
     RECT  1.084 80.832 1.289 83.448 ;
     RECT  1.084 20.784 1.361 21.432 ;
     RECT  1.084 76.8 1.379 79.752 ;
     RECT  1.084 74.304 1.42 75.816 ;
     RECT  1.084 43.248 1.571 46.92 ;
     RECT  1.084 48.384 1.571 48.984 ;
     RECT  1.379 78.048 1.571 79.752 ;
     RECT  1.289 80.832 1.571 82.008 ;
     RECT  1.084 64.752 1.577 65.688 ;
     RECT  1.084 99.84 1.577 104.088 ;
     RECT  1.571 43.248 1.585 46.728 ;
     RECT  1.084 13.584 1.667 16.44 ;
     RECT  1.361 20.784 1.667 20.808 ;
     RECT  1.084 50.592 1.685 52.296 ;
     RECT  1.084 87.072 1.685 90.84 ;
     RECT  1.667 13.584 1.721 15.768 ;
     RECT  1.084 34.56 1.757 37.512 ;
     RECT  1.084 3.264 1.763 3.96 ;
     RECT  1.685 51.648 1.793 52.296 ;
     RECT  1.084 0.384 1.804 1.32 ;
     RECT  1.084 66.912 1.811 68.808 ;
     RECT  1.685 87.072 1.829 89.496 ;
     RECT  1.084 53.856 1.901 54.936 ;
     RECT  1.084 22.416 1.907 31.272 ;
     RECT  1.084 72.288 1.907 72.84 ;
     RECT  1.42 74.304 1.907 75.24 ;
     RECT  1.084 62.112 1.937 63 ;
     RECT  1.289 83.04 1.937 83.448 ;
     RECT  1.829 87.072 1.937 87.24 ;
     RECT  1.937 62.112 1.945 62.136 ;
     RECT  1.907 22.416 1.973 24.312 ;
     RECT  1.084 70.368 1.973 71.016 ;
     RECT  1.763 3.936 2.009 3.96 ;
     RECT  1.084 94.368 2.009 94.392 ;
     RECT  1.901 54.624 2.06 54.936 ;
     RECT  1.907 72.288 2.077 72.504 ;
     RECT  1.757 36.096 2.108 37.512 ;
     RECT  1.084 85.44 2.108 85.464 ;
     RECT  1.804 0.384 2.117 0.408 ;
     RECT  1.084 7.968 2.117 9.384 ;
     RECT  2.06 54.624 2.147 55.416 ;
     RECT  1.084 58.08 2.147 58.392 ;
     RECT  1.577 64.752 2.147 65.208 ;
     RECT  1.084 12.384 2.149 12.408 ;
     RECT  1.721 13.584 2.149 14.424 ;
     RECT  2.108 84.768 2.149 85.464 ;
     RECT  2.053 19.92 2.153 19.944 ;
     RECT  1.811 66.912 2.181 68.376 ;
     RECT  1.973 22.416 2.195 24.216 ;
     RECT  2.108 36.096 2.195 38.04 ;
     RECT  1.084 41.904 2.195 41.928 ;
     RECT  2.149 84.768 2.195 85.944 ;
     RECT  2.101 52.992 2.225 53.016 ;
     RECT  1.084 60 2.243 60.12 ;
     RECT  1.585 43.248 2.261 46.296 ;
     RECT  2.197 61.344 2.284 61.368 ;
     RECT  1.829 88.848 2.291 89.496 ;
     RECT  1.907 29.76 2.293 31.272 ;
     RECT  1.084 98.4 2.329 98.424 ;
     RECT  2.245 10.752 2.332 10.776 ;
     RECT  1.907 25.632 2.333 28.248 ;
     RECT  2.293 29.76 2.333 31.32 ;
     RECT  1.379 76.8 2.333 76.824 ;
     RECT  1.571 80.832 2.333 80.856 ;
     RECT  1.084 96.576 2.333 97.32 ;
     RECT  1.577 99.84 2.333 102.552 ;
     RECT  1.084 33.504 2.339 33.528 ;
     RECT  1.084 4.992 2.369 6.648 ;
     RECT  1.793 51.648 2.369 51.912 ;
     RECT  2.181 67.584 2.369 68.376 ;
     RECT  2.329 98.4 2.396 98.616 ;
     RECT  1.084 95.424 2.437 95.448 ;
     RECT  2.333 96.576 2.437 96.792 ;
     RECT  2.369 4.992 2.441 6.408 ;
     RECT  2.149 12.384 2.441 14.424 ;
     RECT  1.084 91.92 2.473 92.376 ;
     RECT  2.117 8.112 2.477 9.384 ;
     RECT  2.396 97.776 2.483 98.616 ;
     RECT  2.195 23.328 2.549 24.216 ;
     RECT  2.333 26.304 2.549 28.248 ;
     RECT  2.483 98.4 2.579 98.616 ;
     RECT  2.473 91.92 2.617 92.472 ;
     RECT  2.333 99.84 2.62 100.248 ;
     RECT  2.617 91.92 2.653 92.808 ;
     RECT  1.571 78.048 2.657 78.936 ;
     RECT  1.571 81.888 2.657 82.008 ;
     RECT  1.721 15.744 2.753 15.768 ;
     RECT  2.441 12.384 2.765 13.608 ;
     RECT  2.147 65.184 2.765 65.208 ;
     RECT  2.579 98.4 2.765 98.424 ;
     RECT  1.937 83.184 2.771 83.448 ;
     RECT  2.753 15.6 2.773 15.768 ;
     RECT  2.401 17.088 2.773 17.112 ;
     RECT  2.333 29.76 2.801 30.216 ;
     RECT  1.757 34.56 2.833 34.776 ;
     RECT  2.195 36.096 2.833 36.6 ;
     RECT  2.773 15.6 2.837 17.112 ;
     RECT  2.077 71.616 2.837 72.504 ;
     RECT  2.437 95.424 2.837 96.792 ;
     RECT  2.837 15.744 2.869 17.112 ;
     RECT  2.509 18.432 2.869 18.456 ;
     RECT  2.833 34.56 2.869 36.6 ;
     RECT  1.937 87.12 2.869 87.24 ;
     RECT  2.549 26.496 2.873 28.248 ;
     RECT  2.147 54.912 2.873 55.176 ;
     RECT  2.837 95.424 2.873 95.688 ;
     RECT  2.869 15.744 2.915 18.456 ;
     RECT  2.869 34.176 2.917 36.6 ;
     RECT  1.907 74.304 2.924 74.328 ;
     RECT  1.685 50.592 2.941 50.616 ;
     RECT  2.924 73.92 2.941 74.328 ;
     RECT  2.873 26.592 2.981 28.248 ;
     RECT  2.147 58.368 2.981 58.392 ;
     RECT  2.941 72.96 3.011 74.328 ;
     RECT  2.333 31.248 3.013 31.32 ;
     RECT  1.571 48.384 3.02 48.408 ;
     RECT  2.941 50.112 3.061 50.616 ;
     RECT  2.369 51.648 3.061 51.768 ;
     RECT  2.441 5.088 3.089 6.408 ;
     RECT  2.801 30.192 3.097 30.216 ;
     RECT  3.02 47.712 3.107 48.408 ;
     RECT  3.061 49.392 3.107 51.768 ;
     RECT  2.195 85.44 3.109 85.944 ;
     RECT  2.869 87.12 3.109 87.816 ;
     RECT  2.657 78.288 3.121 78.936 ;
     RECT  2.684 80.64 3.121 80.664 ;
     RECT  3.013 31.248 3.125 32.184 ;
     RECT  2.477 8.112 3.155 8.136 ;
     RECT  3.109 85.44 3.155 87.816 ;
     RECT  2.765 12.384 3.157 12.888 ;
     RECT  2.915 17.808 3.157 18.456 ;
     RECT  3.155 85.44 3.157 86.616 ;
     RECT  3.107 50.736 3.197 51.768 ;
     RECT  2.833 21.936 3.203 21.96 ;
     RECT  2.771 83.184 3.203 83.208 ;
     RECT  2.333 101.376 3.229 102.552 ;
     RECT  1.577 103.584 3.229 104.088 ;
     RECT  3.157 85.104 3.244 86.616 ;
     RECT  3.157 41.76 3.26 41.784 ;
     RECT  2.369 68.352 3.265 68.376 ;
     RECT  2.401 39.216 3.301 39.24 ;
     RECT  3.26 41.76 3.301 42.168 ;
     RECT  2.261 43.776 3.301 46.296 ;
     RECT  2.917 34.176 3.305 34.68 ;
     RECT  2.965 75.84 3.305 75.864 ;
     RECT  3.244 85.44 3.305 86.616 ;
     RECT  3.301 41.76 3.337 46.296 ;
     RECT  3.305 34.608 3.347 34.68 ;
     RECT  3.337 41.76 3.347 46.776 ;
     RECT  2.917 35.856 3.397 36.6 ;
     RECT  3.265 68.352 3.397 68.664 ;
     RECT  1.973 70.368 3.397 70.392 ;
     RECT  2.837 71.616 3.397 71.64 ;
     RECT  3.089 5.616 3.413 6.408 ;
     RECT  3.397 35.856 3.443 37.032 ;
     RECT  3.301 38.64 3.443 39.24 ;
     RECT  3.347 43.104 3.443 46.776 ;
     RECT  3.356 64.896 3.443 65.16 ;
     RECT  3.157 66.72 3.443 66.744 ;
     RECT  3.397 67.776 3.443 68.664 ;
     RECT  2.981 28.224 3.445 28.248 ;
     RECT  3.443 36.48 3.485 37.032 ;
     RECT  3.155 87.792 3.485 87.816 ;
     RECT  2.657 81.984 3.548 82.008 ;
     RECT  3.109 3.36 3.589 3.384 ;
     RECT  3.121 78.288 3.589 80.664 ;
     RECT  3.548 1.68 3.635 1.704 ;
     RECT  2.291 89.472 3.653 89.496 ;
     RECT  1.685 90.816 3.653 90.84 ;
     RECT  2.873 54.912 3.661 54.936 ;
     RECT  3.653 89.472 3.685 90.84 ;
     RECT  2.653 91.92 3.685 93.24 ;
     RECT  3.443 67.776 3.701 68.376 ;
     RECT  3.589 78.288 3.733 80.808 ;
     RECT  3.733 78.288 3.737 80.952 ;
     RECT  3.685 88.752 3.737 93.24 ;
     RECT  2.62 99.84 3.769 99.864 ;
     RECT  3.229 101.376 3.769 104.088 ;
     RECT  3.737 88.752 3.772 89.496 ;
     RECT  3.737 90.816 3.772 93.24 ;
     RECT  3.737 78.528 3.773 80.952 ;
     RECT  3.109 9.504 3.805 9.528 ;
     RECT  3.443 39.216 3.809 39.24 ;
     RECT  3.805 9.12 3.845 9.528 ;
     RECT  3.589 76.896 3.845 76.92 ;
     RECT  3.773 78.528 3.845 79.848 ;
     RECT  3.589 2.88 3.881 3.384 ;
     RECT  2.873 95.424 3.913 95.448 ;
     RECT  3.485 36.48 3.953 36.504 ;
     RECT  3.772 91.92 3.953 93.24 ;
     RECT  3.953 93.216 3.973 93.24 ;
     RECT  3.157 17.808 3.98 19.368 ;
     RECT  3.697 63.648 3.985 63.672 ;
     RECT  3.769 99.84 4.019 104.088 ;
     RECT  2.981 26.592 4.021 26.616 ;
     RECT  3.445 28.224 4.021 28.68 ;
     RECT  3.125 31.248 4.025 31.272 ;
     RECT  3.197 51.648 4.025 51.768 ;
     RECT  3.845 78.912 4.025 79.848 ;
     RECT  3.772 90.816 4.025 90.84 ;
     RECT  4.019 99.84 4.025 102.552 ;
     RECT  3.347 34.656 4.061 34.68 ;
     RECT  3.98 17.616 4.067 19.368 ;
     RECT  3.157 11.952 4.097 12.888 ;
     RECT  3.397 70.368 4.124 71.64 ;
     RECT  3.011 72.96 4.124 72.984 ;
     RECT  3.913 95.136 4.124 95.448 ;
     RECT  4.067 18.144 4.133 19.368 ;
     RECT  3.661 98.064 4.165 98.088 ;
     RECT  4.025 99.84 4.165 100.488 ;
     RECT  3.553 58.176 4.201 58.2 ;
     RECT  3.443 65.136 4.205 65.16 ;
     RECT  4.124 70.368 4.211 72.984 ;
     RECT  4.124 95.136 4.211 95.976 ;
     RECT  4.165 97.248 4.211 100.488 ;
     RECT  2.243 60.096 4.213 60.12 ;
     RECT  3.337 61.344 4.213 61.368 ;
     RECT  3.985 63.264 4.259 63.672 ;
     RECT  4.211 95.424 4.277 95.448 ;
     RECT  4.201 58.176 4.285 58.68 ;
     RECT  3.772 89.088 4.307 89.496 ;
     RECT  4.285 58.176 4.309 58.2 ;
     RECT  4.025 101.952 4.313 102.552 ;
     RECT  4.025 51.744 4.316 51.768 ;
     RECT  2.549 24.192 4.345 24.216 ;
     RECT  3.347 41.76 4.349 41.784 ;
     RECT  3.107 49.392 4.357 49.416 ;
     RECT  3.661 54.048 4.357 54.936 ;
     RECT  3.107 48.384 4.381 48.408 ;
     RECT  4.357 49.392 4.381 49.56 ;
     RECT  4.211 97.248 4.385 97.272 ;
     RECT  4.316 51.744 4.403 52.488 ;
     RECT  4.357 54.048 4.403 55.704 ;
     RECT  4.309 57.264 4.403 58.2 ;
     RECT  4.211 98.88 4.421 100.488 ;
     RECT  3.443 43.104 4.493 46.632 ;
     RECT  4.403 51.744 4.493 51.768 ;
     RECT  4.403 54.624 4.493 55.704 ;
     RECT  4.345 23.712 4.499 24.216 ;
     RECT  3.373 25.296 4.499 25.32 ;
     RECT  4.133 18.576 4.501 19.368 ;
     RECT  4.493 54.624 4.529 54.936 ;
     RECT  3.548 81.984 4.529 82.68 ;
     RECT  4.501 18.576 4.547 19.8 ;
     RECT  3.305 85.44 4.549 85.608 ;
     RECT  2.915 15.744 4.565 16.536 ;
     RECT  4.493 44.736 4.565 46.632 ;
     RECT  4.381 48.384 4.565 49.56 ;
     RECT  3.953 91.92 4.565 91.944 ;
     RECT  4.547 19.344 4.597 19.8 ;
     RECT  4.201 21.12 4.597 21.672 ;
     RECT  4.021 26.592 4.597 28.68 ;
     RECT  4.493 43.104 4.597 43.128 ;
     RECT  3.413 6.384 4.601 6.408 ;
     RECT  3.773 80.928 4.601 80.952 ;
     RECT  3.881 3.36 4.637 3.384 ;
     RECT  4.597 19.344 4.637 21.672 ;
     RECT  4.556 41.232 4.643 41.256 ;
     RECT  4.604 10.272 4.691 10.296 ;
     RECT  4.637 21.648 4.777 21.672 ;
     RECT  3.301 32.4 4.787 32.424 ;
     RECT  4.777 21.648 4.817 22.2 ;
     RECT  4.741 30.048 4.844 30.072 ;
     RECT  4.307 89.328 4.844 89.496 ;
     RECT  4.529 82.656 4.849 82.68 ;
     RECT  4.549 85.44 4.849 86.184 ;
     RECT  4.421 99.84 4.853 100.488 ;
     RECT  4.817 22.176 4.861 22.2 ;
     RECT  4.213 60.096 4.885 61.608 ;
     RECT  4.597 26.592 4.931 28.728 ;
     RECT  4.844 30.048 4.931 30.744 ;
     RECT  4.844 89.328 4.931 90.648 ;
     RECT  3.973 93.216 4.931 94.008 ;
     RECT  4.597 42.768 4.961 43.128 ;
     RECT  4.885 59.76 4.981 61.608 ;
     RECT  3.011 74.304 4.993 74.328 ;
     RECT  4.201 75.936 4.993 75.96 ;
     RECT  4.981 59.76 5.027 61.8 ;
     RECT  3.845 9.12 5.033 9.144 ;
     RECT  4.565 48.912 5.033 49.56 ;
     RECT  4.849 82.656 5.033 82.728 ;
     RECT  4.931 30.048 5.065 30.072 ;
     RECT  4.499 24.096 5.069 24.216 ;
     RECT  4.565 44.976 5.077 46.632 ;
     RECT  4.097 12.528 5.101 12.888 ;
     RECT  5.077 44.976 5.123 47.208 ;
     RECT  5.101 11.808 5.132 12.888 ;
     RECT  4.273 35.424 5.137 35.448 ;
     RECT  4.931 89.328 5.171 89.496 ;
     RECT  5.077 51.312 5.173 51.336 ;
     RECT  4.309 66.336 5.173 66.36 ;
     RECT  5.069 24.192 5.177 24.216 ;
     RECT  4.931 28.224 5.177 28.728 ;
     RECT  4.529 54.912 5.177 54.936 ;
     RECT  4.853 99.84 5.177 99.864 ;
     RECT  5.125 88.224 5.212 88.248 ;
     RECT  5.132 11.808 5.219 12.936 ;
     RECT  5.065 29.76 5.219 30.072 ;
     RECT  4.259 63.648 5.281 63.672 ;
     RECT  5.173 50.832 5.317 51.336 ;
     RECT  4.019 104.064 5.317 104.088 ;
     RECT  4.211 70.368 5.353 71.64 ;
     RECT  4.211 72.672 5.353 72.984 ;
     RECT  5.245 1.152 5.365 1.176 ;
     RECT  5.353 70.368 5.42 72.984 ;
     RECT  5.173 65.52 5.425 67.272 ;
     RECT  3.701 68.256 5.425 68.376 ;
     RECT  5.137 35.424 5.468 36.072 ;
     RECT  5.317 94.56 5.509 94.584 ;
     RECT  5.509 94.56 5.533 95.4 ;
     RECT  5.033 82.704 5.605 82.728 ;
     RECT  3.769 83.76 5.605 83.832 ;
     RECT  5.42 69.936 5.653 72.984 ;
     RECT  4.993 74.304 5.653 74.568 ;
     RECT  4.993 75.936 5.653 76.488 ;
     RECT  5.365 1.104 5.701 1.176 ;
     RECT  5.317 2.256 5.701 2.28 ;
     RECT  4.931 26.592 5.713 26.616 ;
     RECT  4.931 90.624 5.713 90.648 ;
     RECT  5.701 3.408 5.749 3.432 ;
     RECT  5.708 5.376 5.749 5.4 ;
     RECT  5.533 7.392 5.749 7.416 ;
     RECT  5.033 48.912 5.749 49.08 ;
     RECT  4.025 79.824 5.845 79.848 ;
     RECT  5.317 50.736 5.948 51.336 ;
     RECT  4.637 20.4 5.965 20.424 ;
     RECT  5.749 53.568 5.989 53.592 ;
     RECT  5.281 63.216 6.001 63.672 ;
     RECT  6.001 63.216 6.037 64.2 ;
     RECT  5.653 74.304 6.037 76.488 ;
     RECT  5.713 90.624 6.037 91.608 ;
     RECT  4.931 93.216 6.037 93.24 ;
     RECT  5.533 94.56 6.037 96.36 ;
     RECT  6.037 90.624 6.181 96.36 ;
     RECT  5.701 1.104 6.188 2.28 ;
     RECT  5.749 3.408 6.188 5.4 ;
     RECT  5.749 7.392 6.188 7.944 ;
     RECT  5.219 11.808 6.188 12.888 ;
     RECT  3.589 14.4 6.188 14.424 ;
     RECT  4.565 15.744 6.188 15.768 ;
     RECT  4.637 19.344 6.188 19.368 ;
     RECT  5.965 20.4 6.188 21.24 ;
     RECT  5.713 25.824 6.188 26.616 ;
     RECT  5.177 28.704 6.188 28.728 ;
     RECT  5.219 30.048 6.188 30.072 ;
     RECT  4.885 32.64 6.188 32.664 ;
     RECT  5.468 34.848 6.188 36.072 ;
     RECT  4.561 37.584 6.188 37.608 ;
     RECT  5.269 38.64 6.188 38.664 ;
     RECT  4.597 39.888 6.188 39.912 ;
     RECT  4.961 43.104 6.188 43.128 ;
     RECT  5.123 45.696 6.188 47.208 ;
     RECT  5.749 48.816 6.188 49.08 ;
     RECT  5.948 50.736 6.188 51.624 ;
     RECT  5.989 52.8 6.188 53.592 ;
     RECT  5.857 55.776 6.188 55.8 ;
     RECT  4.403 58.176 6.188 58.2 ;
     RECT  5.027 60.096 6.188 60.12 ;
     RECT  5.027 61.44 6.188 61.8 ;
     RECT  6.037 63.216 6.188 64.392 ;
     RECT  5.425 65.52 6.188 68.376 ;
     RECT  5.653 69.504 6.188 72.984 ;
     RECT  6.037 74.304 6.188 78.12 ;
     RECT  5.845 79.584 6.188 79.848 ;
     RECT  5.425 80.832 6.188 80.856 ;
     RECT  5.605 82.704 6.188 83.832 ;
     RECT  4.849 85.44 6.188 87.144 ;
     RECT  5.171 89.472 6.188 89.496 ;
     RECT  6.181 90.624 6.188 96.6 ;
     RECT  5.713 98.064 6.188 98.088 ;
     RECT  4.313 101.952 6.188 101.976 ;
     RECT  5.317 103.728 6.188 104.088 ;
     RECT  6.188 0.528 6.292 105.312 ;
     RECT  6.292 0.798 6.484 105.042 ;
     RECT  6.484 7.92 6.611 7.944 ;
     RECT  6.484 39.6 6.611 39.624 ;
     RECT  6.484 40.992 6.611 43.128 ;
     RECT  6.484 80.832 6.611 81.384 ;
     RECT  6.484 82.704 6.611 85.464 ;
     RECT  6.484 99.84 6.611 100.104 ;
     RECT  6.484 11.52 6.653 13.32 ;
     RECT  6.484 15.744 6.659 16.536 ;
     RECT  6.484 18.192 6.659 18.744 ;
     RECT  6.484 21.216 6.659 21.24 ;
     RECT  6.484 22.464 6.659 22.488 ;
     RECT  6.484 24.096 6.659 24.36 ;
     RECT  6.484 25.584 6.659 26.616 ;
     RECT  6.484 28.368 6.659 28.728 ;
     RECT  6.484 29.904 6.659 30.264 ;
     RECT  6.611 100.08 6.659 100.104 ;
     RECT  6.484 103.728 6.659 104.232 ;
     RECT  6.659 16.512 6.661 16.536 ;
     RECT  6.484 9.36 6.689 9.384 ;
     RECT  6.484 96.576 6.755 98.088 ;
     RECT  6.484 52.8 6.761 53.592 ;
     RECT  6.484 101.424 6.761 101.976 ;
     RECT  6.755 96.576 6.796 97.56 ;
     RECT  6.484 4.416 6.797 4.44 ;
     RECT  6.484 31.536 6.833 38.376 ;
     RECT  6.484 54.816 6.851 56.424 ;
     RECT  6.611 83.232 6.851 85.464 ;
     RECT  6.484 89.424 6.851 91.608 ;
     RECT  6.659 28.56 6.869 28.728 ;
     RECT  6.833 31.536 6.869 35.976 ;
     RECT  6.851 90.624 6.889 91.608 ;
     RECT  6.484 48.624 6.905 51.192 ;
     RECT  6.869 32.88 6.913 35.976 ;
     RECT  6.659 24.096 6.941 24.12 ;
     RECT  6.796 96.576 7.085 96.6 ;
     RECT  6.851 83.76 7.091 85.464 ;
     RECT  6.484 88.32 7.091 88.344 ;
     RECT  6.851 89.424 7.091 89.448 ;
     RECT  6.659 25.584 7.121 25.608 ;
     RECT  6.484 61.44 7.121 61.464 ;
     RECT  7.091 85.44 7.121 85.464 ;
     RECT  6.761 53.04 7.193 53.592 ;
     RECT  6.484 93.744 7.193 94.584 ;
     RECT  6.484 77.376 7.265 77.4 ;
     RECT  6.653 11.664 7.337 13.32 ;
     RECT  6.659 26.592 7.445 26.616 ;
     RECT  6.611 42.72 7.445 43.128 ;
     RECT  6.913 35.136 7.475 35.976 ;
     RECT  6.833 37.008 7.475 38.376 ;
     RECT  6.484 45.84 7.475 47.592 ;
     RECT  6.905 48.624 7.475 50.28 ;
     RECT  6.484 74.304 7.477 75.96 ;
     RECT  7.475 37.008 7.517 37.608 ;
     RECT  6.851 54.816 7.517 54.84 ;
     RECT  6.484 71.808 7.523 71.832 ;
     RECT  6.484 87.12 7.549 87.144 ;
     RECT  6.484 57.504 7.553 60.456 ;
     RECT  7.553 59.232 7.564 60.456 ;
     RECT  6.659 18.192 7.657 18.216 ;
     RECT  6.659 104.208 7.657 104.232 ;
     RECT  7.553 57.504 7.697 58.2 ;
     RECT  6.484 66.096 7.724 66.12 ;
     RECT  7.477 74.304 7.763 76.392 ;
     RECT  7.657 18.192 7.765 19.176 ;
     RECT  6.484 62.832 7.765 62.856 ;
     RECT  7.193 93.744 7.765 93.768 ;
     RECT  6.869 31.536 7.769 31.56 ;
     RECT  6.913 32.88 7.769 33.384 ;
     RECT  7.564 60.096 7.769 60.456 ;
     RECT  7.763 74.304 7.797 75.864 ;
     RECT  6.761 101.952 7.801 101.976 ;
     RECT  7.765 17.472 7.811 19.176 ;
     RECT  7.585 22.224 7.811 22.248 ;
     RECT  7.724 65.904 7.811 66.12 ;
     RECT  7.765 20.16 7.852 20.184 ;
     RECT  6.484 67.296 7.868 67.32 ;
     RECT  6.869 28.56 7.873 28.584 ;
     RECT  7.475 45.84 7.909 46.632 ;
     RECT  7.765 62.832 7.909 63.24 ;
     RECT  7.811 66.096 7.909 66.12 ;
     RECT  6.484 69.936 7.909 69.96 ;
     RECT  7.909 62.592 7.913 63.24 ;
     RECT  7.909 45.024 7.949 46.632 ;
     RECT  7.475 50.256 7.949 50.28 ;
     RECT  7.868 60.864 7.955 61.272 ;
     RECT  7.868 67.296 7.955 67.8 ;
     RECT  7.909 69.456 7.955 69.96 ;
     RECT  6.484 14.352 7.957 14.376 ;
     RECT  7.873 27.888 7.957 28.584 ;
     RECT  6.659 29.904 7.957 29.928 ;
     RECT  7.949 45.024 7.993 45.048 ;
     RECT  7.957 13.632 8.003 14.376 ;
     RECT  7.957 15.408 8.044 15.432 ;
     RECT  7.337 11.664 8.057 12.648 ;
     RECT  7.811 17.472 8.057 17.496 ;
     RECT  7.475 48.624 8.057 49.176 ;
     RECT  7.981 81.84 8.065 82.536 ;
     RECT  8.003 13.632 8.093 13.656 ;
     RECT  7.957 27.888 8.125 29.928 ;
     RECT  7.517 37.008 8.129 37.032 ;
     RECT  8.125 27.888 8.165 29.976 ;
     RECT  7.955 69.456 8.165 69.48 ;
     RECT  7.549 87.12 8.237 87.816 ;
     RECT  6.484 79.824 8.245 79.848 ;
     RECT  8.125 77.952 8.291 77.976 ;
     RECT  8.245 79.68 8.332 79.848 ;
     RECT  8.017 21.264 8.389 21.288 ;
     RECT  6.484 72.96 8.413 72.984 ;
     RECT  7.909 66.096 8.417 66.312 ;
     RECT  7.765 92.928 8.417 93.768 ;
     RECT  8.348 19.344 8.435 19.368 ;
     RECT  8.389 17.28 8.444 17.304 ;
     RECT  7.873 9.744 8.485 9.768 ;
     RECT  8.057 12.624 8.485 12.648 ;
     RECT  7.475 35.328 8.485 35.976 ;
     RECT  6.484 1.152 8.521 1.176 ;
     RECT  8.485 35.04 8.521 35.976 ;
     RECT  7.909 56.352 8.521 56.376 ;
     RECT  8.444 16.656 8.531 17.304 ;
     RECT  8.413 72.96 8.531 74.04 ;
     RECT  8.125 76.944 8.531 76.968 ;
     RECT  7.981 24.288 8.533 24.312 ;
     RECT  8.089 26.448 8.533 26.472 ;
     RECT  7.913 62.592 8.533 62.856 ;
     RECT  8.065 81.84 8.54 82.152 ;
     RECT  8.485 9.744 8.572 10.584 ;
     RECT  8.089 5.712 8.579 5.736 ;
     RECT  8.533 24.288 8.579 24.888 ;
     RECT  8.533 26.448 8.579 26.904 ;
     RECT  7.955 60.864 8.579 60.888 ;
     RECT  8.521 97.44 8.581 97.464 ;
     RECT  7.801 98.88 8.581 98.904 ;
     RECT  8.521 35.04 8.588 36.504 ;
     RECT  8.588 34.56 8.605 36.504 ;
     RECT  8.581 97.44 8.627 98.904 ;
     RECT  7.801 2.256 8.629 2.28 ;
     RECT  6.484 3.408 8.629 3.432 ;
     RECT  7.801 4.656 8.629 4.68 ;
     RECT  8.165 29.904 8.629 29.976 ;
     RECT  7.091 83.904 8.629 84.264 ;
     RECT  7.955 67.296 8.633 67.32 ;
     RECT  8.017 31.776 8.675 32.472 ;
     RECT  8.629 83.904 8.675 85.944 ;
     RECT  8.627 98.304 8.675 98.904 ;
     RECT  8.629 29.904 8.705 30.504 ;
     RECT  8.675 98.304 8.713 98.616 ;
     RECT  8.705 30.48 8.716 30.504 ;
     RECT  8.485 12.624 8.741 12.936 ;
     RECT  8.341 53.376 8.773 53.4 ;
     RECT  6.889 90.624 8.773 90.648 ;
     RECT  7.693 7.344 8.813 7.368 ;
     RECT  7.868 43.728 8.813 43.752 ;
     RECT  8.417 92.928 8.819 93.528 ;
     RECT  8.732 94.8 8.819 94.824 ;
     RECT  7.801 101.328 8.828 101.976 ;
     RECT  8.629 2.256 8.849 4.68 ;
     RECT  8.773 52.848 8.86 53.832 ;
     RECT  8.773 89.952 8.869 90.648 ;
     RECT  8.828 101.328 8.885 102.024 ;
     RECT  8.809 64.992 8.915 65.016 ;
     RECT  8.417 66.096 8.915 66.12 ;
     RECT  8.675 85.104 8.915 85.944 ;
     RECT  8.885 102 8.915 102.024 ;
     RECT  8.876 40.416 8.917 40.44 ;
     RECT  8.579 26.88 8.921 26.904 ;
     RECT  8.165 27.888 8.921 28.584 ;
     RECT  8.533 62.16 8.921 62.856 ;
     RECT  8.332 79.776 8.921 79.848 ;
     RECT  7.697 58.176 8.945 58.2 ;
     RECT  8.675 31.776 8.957 31.8 ;
     RECT  8.869 67.248 8.957 67.272 ;
     RECT  8.869 89.136 8.957 90.648 ;
     RECT  8.917 40.416 8.963 41.016 ;
     RECT  8.876 42.72 8.963 42.744 ;
     RECT  8.521 56.352 9.011 57.048 ;
     RECT  8.917 70.464 9.013 70.488 ;
     RECT  9.013 70.224 9.025 70.488 ;
     RECT  8.521 71.568 9.025 71.592 ;
     RECT  9.011 56.352 9.029 56.904 ;
     RECT  9.029 56.88 9.052 56.904 ;
     RECT  9.025 70.224 9.061 71.592 ;
     RECT  8.531 72.96 9.061 73.512 ;
     RECT  9.061 70.224 9.1 73.512 ;
     RECT  8.881 38.16 9.107 38.184 ;
     RECT  9.1 70.464 9.107 73.512 ;
     RECT  8.531 17.28 9.133 17.304 ;
     RECT  8.605 34.56 9.133 35.976 ;
     RECT  9.053 39.888 9.137 39.912 ;
     RECT  8.54 81.6 9.137 82.152 ;
     RECT  8.957 89.136 9.173 89.496 ;
     RECT  8.521 96.432 9.173 96.456 ;
     RECT  8.86 53.808 9.245 53.832 ;
     RECT  8.915 85.104 9.245 85.128 ;
     RECT  8.572 9.744 9.281 9.768 ;
     RECT  8.389 20.496 9.457 21.288 ;
     RECT  8.957 90.624 9.565 90.648 ;
     RECT  9.565 44.928 9.601 44.952 ;
     RECT  9.457 20.352 9.605 21.288 ;
     RECT  8.741 12.624 9.637 12.648 ;
     RECT  9.493 31.68 9.637 31.704 ;
     RECT  8.963 40.896 9.637 41.016 ;
     RECT  8.917 47.904 9.637 47.928 ;
     RECT  7.797 75.264 9.637 75.864 ;
     RECT  8.675 83.904 9.637 83.928 ;
     RECT  8.237 87.12 9.637 87.528 ;
     RECT  9.565 90.624 9.637 91.416 ;
     RECT  8.713 98.304 9.637 98.328 ;
     RECT  7.657 104.208 9.637 104.28 ;
     RECT  8.849 2.88 9.673 4.68 ;
     RECT  9.637 11.136 9.673 11.16 ;
     RECT  9.133 17.28 9.673 18.072 ;
     RECT  9.605 20.352 9.673 20.376 ;
     RECT  9.637 21.504 9.673 22.104 ;
     RECT  8.579 24.384 9.673 24.888 ;
     RECT  9.601 44.736 9.673 44.952 ;
     RECT  8.945 58.176 9.673 58.728 ;
     RECT  8.921 62.784 9.673 62.856 ;
     RECT  8.917 68.928 9.673 68.952 ;
     RECT  9.637 74.88 9.673 76.44 ;
     RECT  9.637 86.4 9.673 87.528 ;
     RECT  9.637 99.84 9.673 99.864 ;
     RECT  9.673 16.704 9.709 18.648 ;
     RECT  9.637 55.68 9.745 55.704 ;
     RECT  9.673 10.752 9.781 11.16 ;
     RECT  9.637 12.48 9.781 12.648 ;
     RECT  9.637 47.616 9.781 47.928 ;
     RECT  9.637 90.624 9.781 92.184 ;
     RECT  8.521 0.576 10.177 1.176 ;
     RECT  9.133 7.872 10.213 7.896 ;
     RECT  9.673 24.192 10.213 25.368 ;
     RECT  8.057 49.152 10.213 49.176 ;
     RECT  9.673 58.176 10.213 58.776 ;
     RECT  9.673 60.864 10.213 61.272 ;
     RECT  9.673 68.928 10.213 69.336 ;
     RECT  9.107 70.464 10.213 72.984 ;
     RECT  9.673 74.496 10.213 76.44 ;
     RECT  9.637 78.336 10.213 78.36 ;
     RECT  8.921 79.824 10.213 79.848 ;
     RECT  9.781 90.624 10.213 92.952 ;
     RECT  9.637 98.112 10.213 98.328 ;
     RECT  9.673 102.528 10.213 102.552 ;
     RECT  9.637 104.208 10.213 104.664 ;
     RECT  9.673 14.976 10.249 15 ;
     RECT  9.709 16.704 10.249 18.84 ;
     RECT  9.673 19.968 10.249 20.376 ;
     RECT  9.673 21.504 10.249 22.68 ;
     RECT  10.213 24.192 10.249 25.944 ;
     RECT  9.637 31.296 10.249 31.704 ;
     RECT  9.133 33.984 10.249 35.976 ;
     RECT  10.213 37.824 10.249 37.848 ;
     RECT  10.213 39.552 10.249 39.576 ;
     RECT  9.673 43.968 10.249 44.952 ;
     RECT  7.949 46.272 10.249 46.632 ;
     RECT  9.781 47.616 10.249 48.024 ;
     RECT  9.637 51.648 10.249 51.672 ;
     RECT  9.745 54.912 10.249 55.704 ;
     RECT  10.213 57.6 10.249 58.776 ;
     RECT  9.673 86.4 10.249 87.96 ;
     RECT  9.173 89.472 10.249 89.496 ;
     RECT  10.213 90.624 10.249 93.336 ;
     RECT  9.673 95.616 10.249 95.64 ;
     RECT  10.213 97.536 10.249 98.328 ;
     RECT  9.673 99.84 10.249 100.632 ;
     RECT  9.673 2.88 10.321 5.016 ;
     RECT  9.565 32.832 10.321 32.856 ;
     RECT  10.249 33.984 10.321 37.848 ;
     RECT  10.177 0.576 10.357 1.56 ;
     RECT  10.321 2.88 10.357 5.784 ;
     RECT  10.249 31.104 10.357 31.704 ;
     RECT  10.321 32.832 10.357 37.848 ;
     RECT  10.249 46.272 10.357 48.024 ;
     RECT  10.213 49.152 10.357 49.752 ;
     RECT  10.249 50.88 10.357 51.672 ;
     RECT  10.213 68.928 10.357 72.984 ;
     RECT  10.213 74.496 10.357 76.824 ;
     RECT  10.213 78.336 10.357 79.848 ;
     RECT  10.249 97.344 10.357 100.632 ;
     RECT  9.781 10.752 10.465 12.648 ;
     RECT  10.249 14.4 10.465 15.192 ;
     RECT  10.249 16.704 10.465 20.376 ;
     RECT  10.249 43.776 10.465 44.952 ;
     RECT  10.213 81.024 10.537 81.048 ;
     RECT  10.249 95.616 10.537 96.024 ;
     RECT  10.357 97.152 10.537 100.632 ;
     RECT  10.249 39.552 10.573 39.768 ;
     RECT  9.637 40.896 10.573 42.072 ;
     RECT  10.249 54.72 10.573 55.704 ;
     RECT  10.357 31.104 10.645 37.848 ;
     RECT  10.465 43.584 10.645 44.952 ;
     RECT  10.357 46.272 10.645 51.672 ;
     RECT  10.573 53.76 10.645 55.704 ;
     RECT  10.249 57.216 10.645 58.776 ;
     RECT  10.213 60.288 10.645 61.272 ;
     RECT  9.673 62.784 10.645 64.536 ;
     RECT  9.637 83.52 10.645 83.928 ;
     RECT  10.249 86.4 10.645 93.336 ;
     RECT  10.249 21.504 10.681 25.944 ;
     RECT  10.249 27.264 10.681 27.288 ;
     RECT  10.573 39.552 10.681 42.072 ;
     RECT  10.357 0.576 10.753 5.784 ;
     RECT  10.213 7.296 10.753 8.856 ;
     RECT  10.357 68.928 10.753 79.848 ;
     RECT  10.465 16.512 10.789 20.376 ;
     RECT  10.681 21.504 10.789 27.288 ;
     RECT  8.921 28.56 10.789 28.584 ;
     RECT  10.357 29.568 10.789 29.592 ;
     RECT  10.645 31.104 10.789 38.232 ;
     RECT  10.681 39.552 10.789 42.264 ;
     RECT  10.645 43.584 10.789 51.672 ;
     RECT  10.645 53.568 10.789 58.776 ;
     RECT  10.645 60.288 10.789 65.304 ;
     RECT  10.753 68.544 10.789 79.848 ;
     RECT  10.537 81.024 10.789 81.624 ;
     RECT  10.645 83.52 10.789 84.504 ;
     RECT  10.645 86.4 10.789 93.528 ;
     RECT  10.213 102.528 10.789 104.664 ;
     RECT  10.753 0.576 10.825 8.856 ;
     RECT  10.465 9.984 10.825 15.192 ;
     RECT  10.789 16.32 10.825 20.376 ;
     RECT  10.789 21.504 10.825 29.976 ;
     RECT  10.789 31.104 10.825 42.264 ;
     RECT  10.789 43.584 10.825 58.776 ;
     RECT  10.789 60.096 10.825 65.304 ;
     RECT  10.789 66.432 10.825 66.84 ;
     RECT  10.789 68.352 10.825 81.624 ;
     RECT  10.789 83.52 10.825 93.528 ;
     RECT  10.537 94.656 10.825 96.024 ;
     RECT  10.537 97.152 10.825 101.016 ;
     RECT  10.789 102.144 10.825 104.664 ;
     RECT  10.825 60.096 10.861 104.664 ;
     RECT  10.825 0.384 10.897 58.776 ;
     RECT  10.861 59.904 10.897 104.664 ;
     RECT  10.897 0.384 11.724 104.664 ;
     RECT  11.724 3.408 11.765 3.432 ;
     RECT  11.724 12.624 11.765 12.648 ;
     RECT  11.724 28.56 11.765 28.584 ;
     RECT  11.724 35.952 11.765 35.976 ;
     RECT  11.724 46.608 11.765 46.632 ;
     RECT  11.724 79.824 11.765 79.848 ;
     RECT  11.724 104.208 11.765 104.232 ;
    LAYER M5 ;
     RECT  5.904 0.144 5.928 0.517 ;
     RECT  0.78 0.517 0.9 0.787 ;
     RECT  5.904 0.517 6.3 0.787 ;
     RECT  5.904 0.787 6.492 1.093 ;
     RECT  0.78 0.787 1.092 1.285 ;
     RECT  5.376 1.093 6.492 2.291 ;
     RECT  3.6 1.669 3.624 3.349 ;
     RECT  3.12 3.349 3.624 3.395 ;
     RECT  5.712 2.291 6.492 3.443 ;
     RECT  0.78 1.285 1.752 3.925 ;
     RECT  8.64 2.821 8.664 4.115 ;
     RECT  0.78 3.925 1.992 5.077 ;
     RECT  3.12 3.395 3.144 5.077 ;
     RECT  0.78 5.077 3.144 5.171 ;
     RECT  2.256 5.171 3.144 5.747 ;
     RECT  8.544 4.645 8.568 5.747 ;
     RECT  5.76 3.443 6.492 7.427 ;
     RECT  5.904 7.427 6.492 7.909 ;
     RECT  3.12 5.747 3.144 8.485 ;
     RECT  2.256 8.485 3.144 8.869 ;
     RECT  2.16 8.869 3.144 9.539 ;
     RECT  7.968 7.333 7.992 9.733 ;
     RECT  7.968 9.733 8.52 9.779 ;
     RECT  4.656 9.109 4.68 10.307 ;
     RECT  8.496 9.779 8.52 10.595 ;
     RECT  0.78 5.171 1.092 12.373 ;
     RECT  2.16 9.539 2.28 12.373 ;
     RECT  0.78 12.373 2.28 12.419 ;
     RECT  0.78 12.419 2.184 12.803 ;
     RECT  5.904 7.909 6.6 12.901 ;
     RECT  5.184 12.901 6.6 13.045 ;
     RECT  0.78 12.803 1.752 13.619 ;
     RECT  8.496 12.901 8.52 13.621 ;
     RECT  5.184 13.045 6.648 14.435 ;
     RECT  7.968 13.621 8.52 15.443 ;
     RECT  2.784 15.589 2.808 16.501 ;
     RECT  2.784 16.501 2.904 16.547 ;
     RECT  8.496 15.443 8.52 17.269 ;
     RECT  8.4 17.269 8.52 17.315 ;
     RECT  8.4 17.315 8.424 17.461 ;
     RECT  2.88 16.547 2.904 18.421 ;
     RECT  4.032 17.605 4.056 18.421 ;
     RECT  2.88 18.421 4.056 18.467 ;
     RECT  3.168 18.467 4.056 18.565 ;
     RECT  3.168 18.565 4.536 18.611 ;
     RECT  4.512 18.611 4.536 19.811 ;
     RECT  0.78 13.619 1.656 19.909 ;
     RECT  7.776 17.461 8.424 20.485 ;
     RECT  7.776 20.485 9.096 21.299 ;
     RECT  3.168 18.611 3.192 21.971 ;
     RECT  7.776 21.299 8.568 22.259 ;
     RECT  0.78 19.909 2.088 22.405 ;
     RECT  0.78 22.405 2.184 23.363 ;
     RECT  4.8 22.165 4.824 23.701 ;
     RECT  4.464 23.701 4.824 24.131 ;
     RECT  8.544 22.259 8.568 26.915 ;
     RECT  4.464 24.131 4.488 27.301 ;
     RECT  4.464 27.301 4.92 27.347 ;
     RECT  7.968 27.877 7.992 29.123 ;
     RECT  4.896 27.347 4.92 29.749 ;
     RECT  5.904 14.435 6.648 29.749 ;
     RECT  0.78 23.363 1.896 29.795 ;
     RECT  4.896 29.749 6.648 30.037 ;
     RECT  4.752 30.037 6.648 30.275 ;
     RECT  3.024 30.181 3.048 31.285 ;
     RECT  4.752 30.275 6.492 31.525 ;
     RECT  2.304 31.285 3.048 32.195 ;
     RECT  4.752 31.525 6.888 32.435 ;
     RECT  4.896 32.435 6.888 32.675 ;
     RECT  2.304 32.195 2.328 34.165 ;
     RECT  3.312 32.389 3.336 34.165 ;
     RECT  2.304 34.165 3.336 34.595 ;
     RECT  8.64 29.941 8.664 35.029 ;
     RECT  8.544 35.029 8.664 35.075 ;
     RECT  5.184 32.675 6.888 35.125 ;
     RECT  2.88 34.595 3.336 35.171 ;
     RECT  3.312 35.171 3.336 35.845 ;
     RECT  0.78 29.795 1.092 36.373 ;
     RECT  8.544 35.075 8.568 36.515 ;
     RECT  0.78 36.373 1.368 37.477 ;
     RECT  0.78 37.477 2.184 37.523 ;
     RECT  5.184 35.125 7.464 38.387 ;
     RECT  3.312 35.845 3.432 39.251 ;
     RECT  5.184 38.387 6.6 39.877 ;
     RECT  9.072 38.149 9.096 39.923 ;
     RECT  3.312 39.251 3.336 41.749 ;
     RECT  4.608 39.877 6.6 41.749 ;
     RECT  3.312 41.749 6.6 42.755 ;
     RECT  3.312 42.755 6.492 42.803 ;
     RECT  3.312 42.803 3.672 43.139 ;
     RECT  0.78 37.523 1.092 43.237 ;
     RECT  2.16 37.523 2.184 43.237 ;
     RECT  0.78 43.237 2.184 43.283 ;
     RECT  3.648 43.139 3.672 44.147 ;
     RECT  5.184 42.803 6.492 44.965 ;
     RECT  7.92 43.717 7.944 45.059 ;
     RECT  0.78 43.283 1.224 45.685 ;
     RECT  5.088 44.965 6.492 45.829 ;
     RECT  0.78 45.685 1.512 46.693 ;
     RECT  3.408 44.389 3.432 46.787 ;
     RECT  8.928 40.405 8.952 47.939 ;
     RECT  5.088 45.829 7.464 49.525 ;
     RECT  4.368 49.525 7.464 50.291 ;
     RECT  3.072 47.701 3.096 50.771 ;
     RECT  0.78 46.693 1.56 51.347 ;
     RECT  4.368 50.291 6.492 51.347 ;
     RECT  5.376 51.347 6.492 53.557 ;
     RECT  5.376 53.557 6.696 54.805 ;
     RECT  8.784 52.837 8.808 56.387 ;
     RECT  4.368 51.347 4.392 57.299 ;
     RECT  5.376 54.805 6.84 57.539 ;
     RECT  2.112 52.981 2.136 58.115 ;
     RECT  0.78 51.347 1.092 58.357 ;
     RECT  8.976 56.869 9 58.739 ;
     RECT  4.224 58.645 4.248 59.749 ;
     RECT  5.376 57.539 6.492 59.749 ;
     RECT  0.78 58.357 1.896 59.989 ;
     RECT  0.78 59.989 2.232 60.035 ;
     RECT  7.488 59.221 7.512 60.467 ;
     RECT  8.544 60.853 8.568 61.237 ;
     RECT  2.208 60.035 2.232 61.379 ;
     RECT  4.224 59.749 6.492 61.811 ;
     RECT  0.78 60.035 1.092 62.101 ;
     RECT  7.92 61.237 8.568 62.821 ;
     RECT  7.92 62.821 8.904 62.867 ;
     RECT  4.224 61.811 4.248 63.299 ;
     RECT  0.78 62.101 1.896 64.741 ;
     RECT  0.78 64.741 2.136 64.787 ;
     RECT  8.88 62.867 8.904 65.027 ;
     RECT  5.376 61.811 6.492 65.509 ;
     RECT  7.776 63.205 7.8 65.939 ;
     RECT  0.78 64.787 1.092 66.901 ;
     RECT  2.112 64.787 2.136 66.901 ;
     RECT  0.78 66.901 2.136 66.947 ;
     RECT  5.184 65.509 6.492 67.283 ;
     RECT  7.92 66.085 8.904 67.283 ;
     RECT  3.408 64.885 3.432 68.675 ;
     RECT  7.92 67.283 7.944 69.925 ;
     RECT  7.488 69.925 7.944 69.971 ;
     RECT  9.024 68.917 9.048 70.259 ;
     RECT  0.78 66.947 1.8 70.981 ;
     RECT  3.408 71.221 3.432 71.317 ;
     RECT  5.376 67.283 6.492 72.419 ;
     RECT  3.408 71.317 4.2 72.661 ;
     RECT  3.408 72.661 4.296 72.949 ;
     RECT  3.408 72.949 5.16 72.995 ;
     RECT  9.072 70.645 9.096 73.523 ;
     RECT  7.488 69.971 7.512 74.293 ;
     RECT  8.496 74.005 8.52 74.293 ;
     RECT  7.488 74.293 8.52 74.339 ;
     RECT  4.272 72.995 5.16 74.533 ;
     RECT  6.18 72.419 6.492 74.533 ;
     RECT  4.272 74.533 6.492 74.579 ;
     RECT  0.78 70.981 1.896 75.251 ;
     RECT  2.976 73.909 3 75.875 ;
     RECT  7.728 74.339 8.52 76.403 ;
     RECT  5.664 74.579 6.492 76.499 ;
     RECT  4.272 74.579 4.296 76.885 ;
     RECT  8.496 76.403 8.52 76.979 ;
     RECT  0.78 75.251 1.368 77.555 ;
     RECT  6.048 76.499 6.492 78.131 ;
     RECT  3.6 76.885 4.296 78.709 ;
     RECT  6.18 78.131 6.492 79.573 ;
     RECT  0.78 77.555 1.092 79.717 ;
     RECT  8.256 77.941 8.28 79.765 ;
     RECT  5.856 79.573 6.492 80.821 ;
     RECT  5.856 80.821 6.6 80.867 ;
     RECT  8.256 79.765 8.616 82.117 ;
     RECT  8.256 82.117 8.664 82.501 ;
     RECT  0.78 79.717 1.56 83.219 ;
     RECT  6.18 80.867 6.6 83.221 ;
     RECT  2.736 78.709 4.296 83.413 ;
     RECT  2.16 83.413 4.296 83.459 ;
     RECT  3.168 83.459 4.296 83.749 ;
     RECT  6.18 83.221 6.84 83.749 ;
     RECT  8.016 82.501 8.664 83.749 ;
     RECT  3.168 83.749 4.584 83.795 ;
     RECT  2.16 83.459 2.184 85.909 ;
     RECT  3.168 83.795 3.192 85.909 ;
     RECT  6.18 83.749 8.664 85.909 ;
     RECT  2.16 85.909 3.192 85.955 ;
     RECT  4.272 83.795 4.584 86.149 ;
     RECT  2.256 85.955 3.192 86.195 ;
     RECT  4.272 86.149 5.064 86.675 ;
     RECT  2.256 86.195 3.144 87.155 ;
     RECT  6.18 85.909 8.904 87.251 ;
     RECT  2.256 87.155 2.904 87.827 ;
     RECT  4.272 86.675 4.296 88.213 ;
     RECT  4.272 88.213 5.16 88.741 ;
     RECT  2.256 87.827 2.28 88.883 ;
     RECT  3.696 88.741 5.16 89.363 ;
     RECT  6.18 87.251 7.08 89.459 ;
     RECT  8.88 87.251 8.904 89.987 ;
     RECT  3.696 89.363 4.92 90.083 ;
     RECT  4.272 90.083 4.92 91.141 ;
     RECT  6.18 89.459 6.84 91.619 ;
     RECT  6.18 91.619 6.492 92.293 ;
     RECT  3.696 91.141 4.92 92.819 ;
     RECT  4.272 92.819 4.92 93.973 ;
     RECT  3.984 93.973 4.92 94.019 ;
     RECT  6.048 92.293 6.492 94.549 ;
     RECT  3.984 94.019 4.008 95.125 ;
     RECT  3.984 95.125 4.2 95.171 ;
     RECT  5.52 94.549 6.492 95.411 ;
     RECT  8.784 90.565 8.808 96.467 ;
     RECT  6.18 95.411 6.492 96.565 ;
     RECT  2.448 96.277 2.472 97.811 ;
     RECT  6.18 96.565 6.744 98.099 ;
     RECT  8.592 97.429 8.616 98.339 ;
     RECT  8.64 98.581 8.664 98.915 ;
     RECT  6.18 98.099 6.6 100.069 ;
     RECT  2.544 98.581 2.568 100.213 ;
     RECT  2.256 100.213 2.568 100.259 ;
     RECT  4.176 95.171 4.2 100.453 ;
     RECT  3.984 100.453 4.2 100.499 ;
     RECT  2.256 100.259 2.28 101.555 ;
     RECT  3.984 100.499 4.008 103.235 ;
     RECT  6.18 100.069 6.648 103.763 ;
     RECT  8.88 101.989 8.904 104.291 ;
     RECT  0.78 83.219 1.092 105.053 ;
     RECT  6.18 103.763 6.492 105.053 ;
     RECT  0.78 105.053 0.9 105.323 ;
     RECT  6.18 105.053 6.3 105.323 ;
    LAYER M6 ;
     RECT  0.54 0.996 11.34 1.86 ;
     RECT  0.54 6.396 11.34 7.26 ;
     RECT  0.54 11.796 11.34 12.66 ;
     RECT  0.54 17.196 11.34 18.06 ;
     RECT  0.54 22.596 11.34 23.46 ;
     RECT  0.54 27.996 11.34 28.86 ;
     RECT  0.54 33.396 11.34 34.26 ;
     RECT  0.54 38.796 11.34 39.66 ;
     RECT  0.54 44.196 11.34 45.06 ;
     RECT  0.54 49.596 11.34 50.46 ;
     RECT  0.54 54.996 11.34 55.86 ;
     RECT  0.54 60.396 11.34 61.26 ;
     RECT  0.54 65.796 11.34 66.66 ;
     RECT  0.54 71.196 11.34 72.06 ;
     RECT  0.54 76.596 11.34 77.46 ;
     RECT  0.54 81.996 11.34 82.86 ;
     RECT  0.54 87.396 11.34 88.26 ;
     RECT  0.54 92.796 11.34 93.66 ;
     RECT  0.54 98.196 11.34 99.06 ;
     RECT  0.54 103.596 11.34 104.46 ;
  END
END ot_attn_bank_ew544
END LIBRARY
